VERSION 5.8 ;
BUSBITCHARS "[]" ;
DIVIDERCHAR "/" ;
UNITS
    DATABASE MICRONS 1000 ;
END UNITS

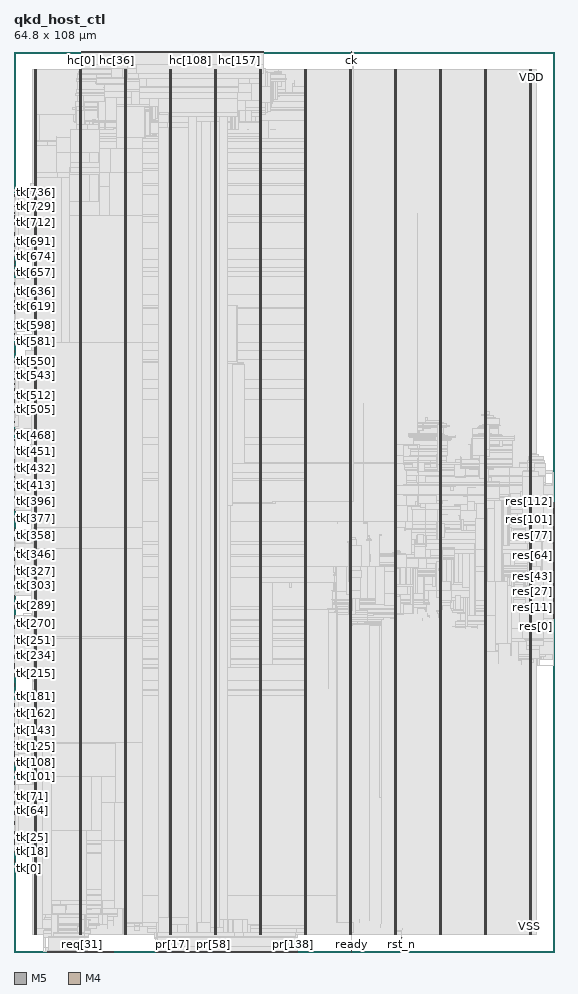
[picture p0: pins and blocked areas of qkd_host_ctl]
MACRO qkd_host_ctl
  FOREIGN qkd_host_ctl 0 0 ;
  CLASS BLOCK ;
  SIZE 64.8 BY 108 ;
  PIN ck
    DIRECTION INPUT ;
    USE SIGNAL ;
    PORT
      LAYER M5 ;
        RECT  40.512 107.916 40.536 108 ;
    END
    PORT
      LAYER M5 ;
        RECT  40.512 107.891 40.536 107.984 ;
    END
  END ck
  PIN hc[0]
    DIRECTION OUTPUT ;
    USE SIGNAL ;
    PORT
      LAYER M5 ;
        RECT  8.064 107.916 8.088 108 ;
    END
  END hc[0]
  PIN hc[100]
    DIRECTION OUTPUT ;
    USE SIGNAL ;
    PORT
      LAYER M5 ;
        RECT  20.16 107.916 20.184 108 ;
    END
  END hc[100]
  PIN hc[101]
    DIRECTION OUTPUT ;
    USE SIGNAL ;
    PORT
      LAYER M5 ;
        RECT  20.256 107.916 20.28 108 ;
    END
  END hc[101]
  PIN hc[102]
    DIRECTION OUTPUT ;
    USE SIGNAL ;
    PORT
      LAYER M5 ;
        RECT  20.4 107.916 20.424 108 ;
    END
  END hc[102]
  PIN hc[103]
    DIRECTION OUTPUT ;
    USE SIGNAL ;
    PORT
      LAYER M5 ;
        RECT  20.496 107.916 20.52 108 ;
    END
  END hc[103]
  PIN hc[104]
    DIRECTION OUTPUT ;
    USE SIGNAL ;
    PORT
      LAYER M5 ;
        RECT  20.64 107.916 20.664 108 ;
    END
  END hc[104]
  PIN hc[105]
    DIRECTION OUTPUT ;
    USE SIGNAL ;
    PORT
      LAYER M5 ;
        RECT  20.736 107.916 20.76 108 ;
    END
  END hc[105]
  PIN hc[106]
    DIRECTION OUTPUT ;
    USE SIGNAL ;
    PORT
      LAYER M5 ;
        RECT  20.88 107.916 20.904 108 ;
    END
  END hc[106]
  PIN hc[107]
    DIRECTION OUTPUT ;
    USE SIGNAL ;
    PORT
      LAYER M5 ;
        RECT  20.976 107.916 21 108 ;
    END
  END hc[107]
  PIN hc[108]
    DIRECTION OUTPUT ;
    USE SIGNAL ;
    PORT
      LAYER M5 ;
        RECT  21.12 107.916 21.144 108 ;
    END
  END hc[108]
  PIN hc[109]
    DIRECTION OUTPUT ;
    USE SIGNAL ;
    PORT
      LAYER M5 ;
        RECT  21.216 107.916 21.24 108 ;
    END
  END hc[109]
  PIN hc[10]
    DIRECTION OUTPUT ;
    USE SIGNAL ;
    PORT
      LAYER M5 ;
        RECT  9.264 107.916 9.288 108 ;
    END
  END hc[10]
  PIN hc[110]
    DIRECTION OUTPUT ;
    USE SIGNAL ;
    PORT
      LAYER M5 ;
        RECT  21.36 107.916 21.384 108 ;
    END
  END hc[110]
  PIN hc[111]
    DIRECTION OUTPUT ;
    USE SIGNAL ;
    PORT
      LAYER M5 ;
        RECT  21.456 107.916 21.48 108 ;
    END
  END hc[111]
  PIN hc[112]
    DIRECTION OUTPUT ;
    USE SIGNAL ;
    PORT
      LAYER M5 ;
        RECT  21.6 107.916 21.624 108 ;
    END
  END hc[112]
  PIN hc[113]
    DIRECTION OUTPUT ;
    USE SIGNAL ;
    PORT
      LAYER M5 ;
        RECT  21.696 107.916 21.72 108 ;
    END
  END hc[113]
  PIN hc[114]
    DIRECTION OUTPUT ;
    USE SIGNAL ;
    PORT
      LAYER M5 ;
        RECT  21.84 107.916 21.864 108 ;
    END
  END hc[114]
  PIN hc[115]
    DIRECTION OUTPUT ;
    USE SIGNAL ;
    PORT
      LAYER M5 ;
        RECT  21.936 107.916 21.96 108 ;
    END
  END hc[115]
  PIN hc[116]
    DIRECTION OUTPUT ;
    USE SIGNAL ;
    PORT
      LAYER M5 ;
        RECT  22.08 107.916 22.104 108 ;
    END
  END hc[116]
  PIN hc[117]
    DIRECTION OUTPUT ;
    USE SIGNAL ;
    PORT
      LAYER M5 ;
        RECT  22.176 107.916 22.2 108 ;
    END
  END hc[117]
  PIN hc[118]
    DIRECTION OUTPUT ;
    USE SIGNAL ;
    PORT
      LAYER M5 ;
        RECT  22.32 107.916 22.344 108 ;
    END
  END hc[118]
  PIN hc[119]
    DIRECTION OUTPUT ;
    USE SIGNAL ;
    PORT
      LAYER M5 ;
        RECT  22.416 107.916 22.44 108 ;
    END
  END hc[119]
  PIN hc[11]
    DIRECTION OUTPUT ;
    USE SIGNAL ;
    PORT
      LAYER M5 ;
        RECT  9.36 107.916 9.384 108 ;
    END
  END hc[11]
  PIN hc[120]
    DIRECTION OUTPUT ;
    USE SIGNAL ;
    PORT
      LAYER M5 ;
        RECT  22.56 107.916 22.584 108 ;
    END
  END hc[120]
  PIN hc[121]
    DIRECTION OUTPUT ;
    USE SIGNAL ;
    PORT
      LAYER M5 ;
        RECT  22.656 107.916 22.68 108 ;
    END
  END hc[121]
  PIN hc[122]
    DIRECTION OUTPUT ;
    USE SIGNAL ;
    PORT
      LAYER M5 ;
        RECT  22.8 107.916 22.824 108 ;
    END
  END hc[122]
  PIN hc[123]
    DIRECTION OUTPUT ;
    USE SIGNAL ;
    PORT
      LAYER M5 ;
        RECT  22.896 107.916 22.92 108 ;
    END
  END hc[123]
  PIN hc[124]
    DIRECTION OUTPUT ;
    USE SIGNAL ;
    PORT
      LAYER M5 ;
        RECT  23.04 107.916 23.064 108 ;
    END
  END hc[124]
  PIN hc[125]
    DIRECTION OUTPUT ;
    USE SIGNAL ;
    PORT
      LAYER M5 ;
        RECT  23.136 107.916 23.16 108 ;
    END
  END hc[125]
  PIN hc[126]
    DIRECTION OUTPUT ;
    USE SIGNAL ;
    PORT
      LAYER M5 ;
        RECT  23.28 107.916 23.304 108 ;
    END
  END hc[126]
  PIN hc[127]
    DIRECTION OUTPUT ;
    USE SIGNAL ;
    PORT
      LAYER M5 ;
        RECT  23.424 107.916 23.448 108 ;
    END
  END hc[127]
  PIN hc[128]
    DIRECTION OUTPUT ;
    USE SIGNAL ;
    PORT
      LAYER M5 ;
        RECT  23.52 107.916 23.544 108 ;
    END
  END hc[128]
  PIN hc[129]
    DIRECTION OUTPUT ;
    USE SIGNAL ;
    PORT
      LAYER M5 ;
        RECT  23.664 107.916 23.688 108 ;
    END
  END hc[129]
  PIN hc[12]
    DIRECTION OUTPUT ;
    USE SIGNAL ;
    PORT
      LAYER M5 ;
        RECT  9.504 107.916 9.528 108 ;
    END
  END hc[12]
  PIN hc[130]
    DIRECTION OUTPUT ;
    USE SIGNAL ;
    PORT
      LAYER M5 ;
        RECT  23.76 107.916 23.784 108 ;
    END
  END hc[130]
  PIN hc[131]
    DIRECTION OUTPUT ;
    USE SIGNAL ;
    PORT
      LAYER M5 ;
        RECT  23.904 107.916 23.928 108 ;
    END
  END hc[131]
  PIN hc[132]
    DIRECTION OUTPUT ;
    USE SIGNAL ;
    PORT
      LAYER M5 ;
        RECT  24 107.916 24.024 108 ;
    END
  END hc[132]
  PIN hc[133]
    DIRECTION OUTPUT ;
    USE SIGNAL ;
    PORT
      LAYER M5 ;
        RECT  24.144 107.916 24.168 108 ;
    END
  END hc[133]
  PIN hc[134]
    DIRECTION OUTPUT ;
    USE SIGNAL ;
    PORT
      LAYER M5 ;
        RECT  24.24 107.916 24.264 108 ;
    END
  END hc[134]
  PIN hc[135]
    DIRECTION OUTPUT ;
    USE SIGNAL ;
    PORT
      LAYER M5 ;
        RECT  24.384 107.916 24.408 108 ;
    END
  END hc[135]
  PIN hc[136]
    DIRECTION OUTPUT ;
    USE SIGNAL ;
    PORT
      LAYER M5 ;
        RECT  24.48 107.916 24.504 108 ;
    END
  END hc[136]
  PIN hc[137]
    DIRECTION OUTPUT ;
    USE SIGNAL ;
    PORT
      LAYER M5 ;
        RECT  24.624 107.916 24.648 108 ;
    END
  END hc[137]
  PIN hc[138]
    DIRECTION OUTPUT ;
    USE SIGNAL ;
    PORT
      LAYER M5 ;
        RECT  24.72 107.916 24.744 108 ;
    END
  END hc[138]
  PIN hc[139]
    DIRECTION OUTPUT ;
    USE SIGNAL ;
    PORT
      LAYER M5 ;
        RECT  24.864 107.916 24.888 108 ;
    END
  END hc[139]
  PIN hc[13]
    DIRECTION OUTPUT ;
    USE SIGNAL ;
    PORT
      LAYER M5 ;
        RECT  9.6 107.916 9.624 108 ;
    END
  END hc[13]
  PIN hc[140]
    DIRECTION OUTPUT ;
    USE SIGNAL ;
    PORT
      LAYER M5 ;
        RECT  24.96 107.916 24.984 108 ;
    END
  END hc[140]
  PIN hc[141]
    DIRECTION OUTPUT ;
    USE SIGNAL ;
    PORT
      LAYER M5 ;
        RECT  25.104 107.916 25.128 108 ;
    END
  END hc[141]
  PIN hc[142]
    DIRECTION OUTPUT ;
    USE SIGNAL ;
    PORT
      LAYER M5 ;
        RECT  25.2 107.916 25.224 108 ;
    END
  END hc[142]
  PIN hc[143]
    DIRECTION OUTPUT ;
    USE SIGNAL ;
    PORT
      LAYER M5 ;
        RECT  25.344 107.916 25.368 108 ;
    END
  END hc[143]
  PIN hc[144]
    DIRECTION OUTPUT ;
    USE SIGNAL ;
    PORT
      LAYER M5 ;
        RECT  25.44 107.916 25.464 108 ;
    END
  END hc[144]
  PIN hc[145]
    DIRECTION OUTPUT ;
    USE SIGNAL ;
    PORT
      LAYER M5 ;
        RECT  25.584 107.916 25.608 108 ;
    END
  END hc[145]
  PIN hc[146]
    DIRECTION OUTPUT ;
    USE SIGNAL ;
    PORT
      LAYER M5 ;
        RECT  25.68 107.916 25.704 108 ;
    END
  END hc[146]
  PIN hc[147]
    DIRECTION OUTPUT ;
    USE SIGNAL ;
    PORT
      LAYER M5 ;
        RECT  25.824 107.916 25.848 108 ;
    END
  END hc[147]
  PIN hc[148]
    DIRECTION OUTPUT ;
    USE SIGNAL ;
    PORT
      LAYER M5 ;
        RECT  25.92 107.916 25.944 108 ;
    END
  END hc[148]
  PIN hc[149]
    DIRECTION OUTPUT ;
    USE SIGNAL ;
    PORT
      LAYER M5 ;
        RECT  26.064 107.916 26.088 108 ;
    END
  END hc[149]
  PIN hc[14]
    DIRECTION OUTPUT ;
    USE SIGNAL ;
    PORT
      LAYER M5 ;
        RECT  9.744 107.916 9.768 108 ;
    END
  END hc[14]
  PIN hc[150]
    DIRECTION OUTPUT ;
    USE SIGNAL ;
    PORT
      LAYER M5 ;
        RECT  26.16 107.916 26.184 108 ;
    END
  END hc[150]
  PIN hc[151]
    DIRECTION OUTPUT ;
    USE SIGNAL ;
    PORT
      LAYER M5 ;
        RECT  26.304 107.916 26.328 108 ;
    END
  END hc[151]
  PIN hc[152]
    DIRECTION OUTPUT ;
    USE SIGNAL ;
    PORT
      LAYER M5 ;
        RECT  26.4 107.916 26.424 108 ;
    END
  END hc[152]
  PIN hc[153]
    DIRECTION OUTPUT ;
    USE SIGNAL ;
    PORT
      LAYER M5 ;
        RECT  26.544 107.916 26.568 108 ;
    END
  END hc[153]
  PIN hc[154]
    DIRECTION OUTPUT ;
    USE SIGNAL ;
    PORT
      LAYER M5 ;
        RECT  26.688 107.916 26.712 108 ;
    END
  END hc[154]
  PIN hc[155]
    DIRECTION OUTPUT ;
    USE SIGNAL ;
    PORT
      LAYER M5 ;
        RECT  26.784 107.916 26.808 108 ;
    END
  END hc[155]
  PIN hc[156]
    DIRECTION OUTPUT ;
    USE SIGNAL ;
    PORT
      LAYER M5 ;
        RECT  26.928 107.916 26.952 108 ;
    END
  END hc[156]
  PIN hc[157]
    DIRECTION OUTPUT ;
    USE SIGNAL ;
    PORT
      LAYER M5 ;
        RECT  27.024 107.916 27.048 108 ;
    END
  END hc[157]
  PIN hc[158]
    DIRECTION OUTPUT ;
    USE SIGNAL ;
    PORT
      LAYER M5 ;
        RECT  27.168 107.916 27.192 108 ;
    END
  END hc[158]
  PIN hc[159]
    DIRECTION OUTPUT ;
    USE SIGNAL ;
    PORT
      LAYER M5 ;
        RECT  27.264 107.916 27.288 108 ;
    END
  END hc[159]
  PIN hc[15]
    DIRECTION OUTPUT ;
    USE SIGNAL ;
    PORT
      LAYER M5 ;
        RECT  9.84 107.916 9.864 108 ;
    END
  END hc[15]
  PIN hc[160]
    DIRECTION OUTPUT ;
    USE SIGNAL ;
    PORT
      LAYER M5 ;
        RECT  27.408 107.916 27.432 108 ;
    END
  END hc[160]
  PIN hc[161]
    DIRECTION OUTPUT ;
    USE SIGNAL ;
    PORT
      LAYER M5 ;
        RECT  27.504 107.916 27.528 108 ;
    END
  END hc[161]
  PIN hc[162]
    DIRECTION OUTPUT ;
    USE SIGNAL ;
    PORT
      LAYER M5 ;
        RECT  27.648 107.916 27.672 108 ;
    END
  END hc[162]
  PIN hc[163]
    DIRECTION OUTPUT ;
    USE SIGNAL ;
    PORT
      LAYER M5 ;
        RECT  27.744 107.916 27.768 108 ;
    END
  END hc[163]
  PIN hc[164]
    DIRECTION OUTPUT ;
    USE SIGNAL ;
    PORT
      LAYER M5 ;
        RECT  27.888 107.916 27.912 108 ;
    END
  END hc[164]
  PIN hc[165]
    DIRECTION OUTPUT ;
    USE SIGNAL ;
    PORT
      LAYER M5 ;
        RECT  27.984 107.916 28.008 108 ;
    END
  END hc[165]
  PIN hc[166]
    DIRECTION OUTPUT ;
    USE SIGNAL ;
    PORT
      LAYER M5 ;
        RECT  28.128 107.916 28.152 108 ;
    END
  END hc[166]
  PIN hc[167]
    DIRECTION OUTPUT ;
    USE SIGNAL ;
    PORT
      LAYER M5 ;
        RECT  28.224 107.916 28.248 108 ;
    END
  END hc[167]
  PIN hc[168]
    DIRECTION OUTPUT ;
    USE SIGNAL ;
    PORT
      LAYER M5 ;
        RECT  28.368 107.916 28.392 108 ;
    END
  END hc[168]
  PIN hc[169]
    DIRECTION OUTPUT ;
    USE SIGNAL ;
    PORT
      LAYER M5 ;
        RECT  28.464 107.916 28.488 108 ;
    END
  END hc[169]
  PIN hc[16]
    DIRECTION OUTPUT ;
    USE SIGNAL ;
    PORT
      LAYER M5 ;
        RECT  9.984 107.916 10.008 108 ;
    END
  END hc[16]
  PIN hc[170]
    DIRECTION OUTPUT ;
    USE SIGNAL ;
    PORT
      LAYER M5 ;
        RECT  28.608 107.916 28.632 108 ;
    END
  END hc[170]
  PIN hc[171]
    DIRECTION OUTPUT ;
    USE SIGNAL ;
    PORT
      LAYER M5 ;
        RECT  28.704 107.916 28.728 108 ;
    END
  END hc[171]
  PIN hc[172]
    DIRECTION OUTPUT ;
    USE SIGNAL ;
    PORT
      LAYER M5 ;
        RECT  28.848 107.916 28.872 108 ;
    END
  END hc[172]
  PIN hc[173]
    DIRECTION OUTPUT ;
    USE SIGNAL ;
    PORT
      LAYER M5 ;
        RECT  28.944 107.916 28.968 108 ;
    END
  END hc[173]
  PIN hc[174]
    DIRECTION OUTPUT ;
    USE SIGNAL ;
    PORT
      LAYER M5 ;
        RECT  29.088 107.916 29.112 108 ;
    END
  END hc[174]
  PIN hc[175]
    DIRECTION OUTPUT ;
    USE SIGNAL ;
    PORT
      LAYER M5 ;
        RECT  29.184 107.916 29.208 108 ;
    END
  END hc[175]
  PIN hc[176]
    DIRECTION OUTPUT ;
    USE SIGNAL ;
    PORT
      LAYER M5 ;
        RECT  29.328 107.916 29.352 108 ;
    END
  END hc[176]
  PIN hc[177]
    DIRECTION OUTPUT ;
    USE SIGNAL ;
    PORT
      LAYER M5 ;
        RECT  29.424 107.916 29.448 108 ;
    END
  END hc[177]
  PIN hc[178]
    DIRECTION OUTPUT ;
    USE SIGNAL ;
    PORT
      LAYER M5 ;
        RECT  29.568 107.916 29.592 108 ;
    END
  END hc[178]
  PIN hc[179]
    DIRECTION OUTPUT ;
    USE SIGNAL ;
    PORT
      LAYER M5 ;
        RECT  29.664 107.916 29.688 108 ;
    END
  END hc[179]
  PIN hc[17]
    DIRECTION OUTPUT ;
    USE SIGNAL ;
    PORT
      LAYER M5 ;
        RECT  10.08 107.916 10.104 108 ;
    END
  END hc[17]
  PIN hc[180]
    DIRECTION OUTPUT ;
    USE SIGNAL ;
    PORT
      LAYER M5 ;
        RECT  29.808 107.916 29.832 108 ;
    END
  END hc[180]
  PIN hc[181]
    DIRECTION OUTPUT ;
    USE SIGNAL ;
    PORT
      LAYER M5 ;
        RECT  29.952 107.916 29.976 108 ;
    END
  END hc[181]
  PIN hc[18]
    DIRECTION OUTPUT ;
    USE SIGNAL ;
    PORT
      LAYER M5 ;
        RECT  10.224 107.916 10.248 108 ;
    END
  END hc[18]
  PIN hc[19]
    DIRECTION OUTPUT ;
    USE SIGNAL ;
    PORT
      LAYER M5 ;
        RECT  10.368 107.916 10.392 108 ;
    END
  END hc[19]
  PIN hc[1]
    DIRECTION OUTPUT ;
    USE SIGNAL ;
    PORT
      LAYER M5 ;
        RECT  8.16 107.916 8.184 108 ;
    END
  END hc[1]
  PIN hc[20]
    DIRECTION OUTPUT ;
    USE SIGNAL ;
    PORT
      LAYER M5 ;
        RECT  10.464 107.916 10.488 108 ;
    END
  END hc[20]
  PIN hc[21]
    DIRECTION OUTPUT ;
    USE SIGNAL ;
    PORT
      LAYER M5 ;
        RECT  10.608 107.916 10.632 108 ;
    END
  END hc[21]
  PIN hc[22]
    DIRECTION OUTPUT ;
    USE SIGNAL ;
    PORT
      LAYER M5 ;
        RECT  10.704 107.916 10.728 108 ;
    END
  END hc[22]
  PIN hc[23]
    DIRECTION OUTPUT ;
    USE SIGNAL ;
    PORT
      LAYER M5 ;
        RECT  10.848 107.916 10.872 108 ;
    END
  END hc[23]
  PIN hc[24]
    DIRECTION OUTPUT ;
    USE SIGNAL ;
    PORT
      LAYER M5 ;
        RECT  10.944 107.916 10.968 108 ;
    END
  END hc[24]
  PIN hc[25]
    DIRECTION OUTPUT ;
    USE SIGNAL ;
    PORT
      LAYER M5 ;
        RECT  11.088 107.916 11.112 108 ;
    END
  END hc[25]
  PIN hc[26]
    DIRECTION OUTPUT ;
    USE SIGNAL ;
    PORT
      LAYER M5 ;
        RECT  11.184 107.916 11.208 108 ;
    END
  END hc[26]
  PIN hc[27]
    DIRECTION OUTPUT ;
    USE SIGNAL ;
    PORT
      LAYER M5 ;
        RECT  11.328 107.916 11.352 108 ;
    END
  END hc[27]
  PIN hc[28]
    DIRECTION OUTPUT ;
    USE SIGNAL ;
    PORT
      LAYER M5 ;
        RECT  11.424 107.916 11.448 108 ;
    END
  END hc[28]
  PIN hc[29]
    DIRECTION OUTPUT ;
    USE SIGNAL ;
    PORT
      LAYER M5 ;
        RECT  11.568 107.916 11.592 108 ;
    END
  END hc[29]
  PIN hc[2]
    DIRECTION OUTPUT ;
    USE SIGNAL ;
    PORT
      LAYER M5 ;
        RECT  8.304 107.916 8.328 108 ;
    END
  END hc[2]
  PIN hc[30]
    DIRECTION OUTPUT ;
    USE SIGNAL ;
    PORT
      LAYER M5 ;
        RECT  11.664 107.916 11.688 108 ;
    END
  END hc[30]
  PIN hc[31]
    DIRECTION OUTPUT ;
    USE SIGNAL ;
    PORT
      LAYER M5 ;
        RECT  11.808 107.916 11.832 108 ;
    END
  END hc[31]
  PIN hc[32]
    DIRECTION OUTPUT ;
    USE SIGNAL ;
    PORT
      LAYER M5 ;
        RECT  11.904 107.916 11.928 108 ;
    END
  END hc[32]
  PIN hc[33]
    DIRECTION OUTPUT ;
    USE SIGNAL ;
    PORT
      LAYER M5 ;
        RECT  12.048 107.916 12.072 108 ;
    END
  END hc[33]
  PIN hc[34]
    DIRECTION OUTPUT ;
    USE SIGNAL ;
    PORT
      LAYER M5 ;
        RECT  12.144 107.916 12.168 108 ;
    END
  END hc[34]
  PIN hc[35]
    DIRECTION OUTPUT ;
    USE SIGNAL ;
    PORT
      LAYER M5 ;
        RECT  12.288 107.916 12.312 108 ;
    END
  END hc[35]
  PIN hc[36]
    DIRECTION OUTPUT ;
    USE SIGNAL ;
    PORT
      LAYER M5 ;
        RECT  12.384 107.916 12.408 108 ;
    END
  END hc[36]
  PIN hc[37]
    DIRECTION OUTPUT ;
    USE SIGNAL ;
    PORT
      LAYER M5 ;
        RECT  12.528 107.916 12.552 108 ;
    END
  END hc[37]
  PIN hc[38]
    DIRECTION OUTPUT ;
    USE SIGNAL ;
    PORT
      LAYER M5 ;
        RECT  12.624 107.916 12.648 108 ;
    END
  END hc[38]
  PIN hc[39]
    DIRECTION OUTPUT ;
    USE SIGNAL ;
    PORT
      LAYER M5 ;
        RECT  12.768 107.916 12.792 108 ;
    END
  END hc[39]
  PIN hc[3]
    DIRECTION OUTPUT ;
    USE SIGNAL ;
    PORT
      LAYER M5 ;
        RECT  8.4 107.916 8.424 108 ;
    END
  END hc[3]
  PIN hc[40]
    DIRECTION OUTPUT ;
    USE SIGNAL ;
    PORT
      LAYER M5 ;
        RECT  12.864 107.916 12.888 108 ;
    END
  END hc[40]
  PIN hc[41]
    DIRECTION OUTPUT ;
    USE SIGNAL ;
    PORT
      LAYER M5 ;
        RECT  13.008 107.916 13.032 108 ;
    END
  END hc[41]
  PIN hc[42]
    DIRECTION OUTPUT ;
    USE SIGNAL ;
    PORT
      LAYER M5 ;
        RECT  13.104 107.916 13.128 108 ;
    END
  END hc[42]
  PIN hc[43]
    DIRECTION OUTPUT ;
    USE SIGNAL ;
    PORT
      LAYER M5 ;
        RECT  13.248 107.916 13.272 108 ;
    END
  END hc[43]
  PIN hc[44]
    DIRECTION OUTPUT ;
    USE SIGNAL ;
    PORT
      LAYER M5 ;
        RECT  13.344 107.916 13.368 108 ;
    END
  END hc[44]
  PIN hc[45]
    DIRECTION OUTPUT ;
    USE SIGNAL ;
    PORT
      LAYER M5 ;
        RECT  13.488 107.916 13.512 108 ;
    END
  END hc[45]
  PIN hc[46]
    DIRECTION OUTPUT ;
    USE SIGNAL ;
    PORT
      LAYER M5 ;
        RECT  13.632 107.916 13.656 108 ;
    END
  END hc[46]
  PIN hc[47]
    DIRECTION OUTPUT ;
    USE SIGNAL ;
    PORT
      LAYER M5 ;
        RECT  13.728 107.916 13.752 108 ;
    END
  END hc[47]
  PIN hc[48]
    DIRECTION OUTPUT ;
    USE SIGNAL ;
    PORT
      LAYER M5 ;
        RECT  13.872 107.916 13.896 108 ;
    END
  END hc[48]
  PIN hc[49]
    DIRECTION OUTPUT ;
    USE SIGNAL ;
    PORT
      LAYER M5 ;
        RECT  13.968 107.916 13.992 108 ;
    END
  END hc[49]
  PIN hc[4]
    DIRECTION OUTPUT ;
    USE SIGNAL ;
    PORT
      LAYER M5 ;
        RECT  8.544 107.916 8.568 108 ;
    END
  END hc[4]
  PIN hc[50]
    DIRECTION OUTPUT ;
    USE SIGNAL ;
    PORT
      LAYER M5 ;
        RECT  14.112 107.916 14.136 108 ;
    END
  END hc[50]
  PIN hc[51]
    DIRECTION OUTPUT ;
    USE SIGNAL ;
    PORT
      LAYER M5 ;
        RECT  14.208 107.916 14.232 108 ;
    END
  END hc[51]
  PIN hc[52]
    DIRECTION OUTPUT ;
    USE SIGNAL ;
    PORT
      LAYER M5 ;
        RECT  14.352 107.916 14.376 108 ;
    END
  END hc[52]
  PIN hc[53]
    DIRECTION OUTPUT ;
    USE SIGNAL ;
    PORT
      LAYER M5 ;
        RECT  14.448 107.916 14.472 108 ;
    END
  END hc[53]
  PIN hc[54]
    DIRECTION OUTPUT ;
    USE SIGNAL ;
    PORT
      LAYER M5 ;
        RECT  14.592 107.916 14.616 108 ;
    END
  END hc[54]
  PIN hc[55]
    DIRECTION OUTPUT ;
    USE SIGNAL ;
    PORT
      LAYER M5 ;
        RECT  14.688 107.916 14.712 108 ;
    END
  END hc[55]
  PIN hc[56]
    DIRECTION OUTPUT ;
    USE SIGNAL ;
    PORT
      LAYER M5 ;
        RECT  14.832 107.916 14.856 108 ;
    END
  END hc[56]
  PIN hc[57]
    DIRECTION OUTPUT ;
    USE SIGNAL ;
    PORT
      LAYER M5 ;
        RECT  14.928 107.916 14.952 108 ;
    END
  END hc[57]
  PIN hc[58]
    DIRECTION OUTPUT ;
    USE SIGNAL ;
    PORT
      LAYER M5 ;
        RECT  15.072 107.916 15.096 108 ;
    END
  END hc[58]
  PIN hc[59]
    DIRECTION OUTPUT ;
    USE SIGNAL ;
    PORT
      LAYER M5 ;
        RECT  15.168 107.916 15.192 108 ;
    END
  END hc[59]
  PIN hc[5]
    DIRECTION OUTPUT ;
    USE SIGNAL ;
    PORT
      LAYER M5 ;
        RECT  8.64 107.916 8.664 108 ;
    END
  END hc[5]
  PIN hc[60]
    DIRECTION OUTPUT ;
    USE SIGNAL ;
    PORT
      LAYER M5 ;
        RECT  15.312 107.916 15.336 108 ;
    END
  END hc[60]
  PIN hc[61]
    DIRECTION OUTPUT ;
    USE SIGNAL ;
    PORT
      LAYER M5 ;
        RECT  15.408 107.916 15.432 108 ;
    END
  END hc[61]
  PIN hc[62]
    DIRECTION OUTPUT ;
    USE SIGNAL ;
    PORT
      LAYER M5 ;
        RECT  15.552 107.916 15.576 108 ;
    END
  END hc[62]
  PIN hc[63]
    DIRECTION OUTPUT ;
    USE SIGNAL ;
    PORT
      LAYER M5 ;
        RECT  15.648 107.916 15.672 108 ;
    END
  END hc[63]
  PIN hc[64]
    DIRECTION OUTPUT ;
    USE SIGNAL ;
    PORT
      LAYER M5 ;
        RECT  15.792 107.916 15.816 108 ;
    END
  END hc[64]
  PIN hc[65]
    DIRECTION OUTPUT ;
    USE SIGNAL ;
    PORT
      LAYER M5 ;
        RECT  15.888 107.916 15.912 108 ;
    END
  END hc[65]
  PIN hc[66]
    DIRECTION OUTPUT ;
    USE SIGNAL ;
    PORT
      LAYER M5 ;
        RECT  16.032 107.916 16.056 108 ;
    END
  END hc[66]
  PIN hc[67]
    DIRECTION OUTPUT ;
    USE SIGNAL ;
    PORT
      LAYER M5 ;
        RECT  16.128 107.916 16.152 108 ;
    END
  END hc[67]
  PIN hc[68]
    DIRECTION OUTPUT ;
    USE SIGNAL ;
    PORT
      LAYER M5 ;
        RECT  16.272 107.916 16.296 108 ;
    END
  END hc[68]
  PIN hc[69]
    DIRECTION OUTPUT ;
    USE SIGNAL ;
    PORT
      LAYER M5 ;
        RECT  16.368 107.916 16.392 108 ;
    END
  END hc[69]
  PIN hc[6]
    DIRECTION OUTPUT ;
    USE SIGNAL ;
    PORT
      LAYER M5 ;
        RECT  8.784 107.916 8.808 108 ;
    END
  END hc[6]
  PIN hc[70]
    DIRECTION OUTPUT ;
    USE SIGNAL ;
    PORT
      LAYER M5 ;
        RECT  16.512 107.916 16.536 108 ;
    END
  END hc[70]
  PIN hc[71]
    DIRECTION OUTPUT ;
    USE SIGNAL ;
    PORT
      LAYER M5 ;
        RECT  16.608 107.916 16.632 108 ;
    END
  END hc[71]
  PIN hc[72]
    DIRECTION OUTPUT ;
    USE SIGNAL ;
    PORT
      LAYER M5 ;
        RECT  16.752 107.916 16.776 108 ;
    END
  END hc[72]
  PIN hc[73]
    DIRECTION OUTPUT ;
    USE SIGNAL ;
    PORT
      LAYER M5 ;
        RECT  16.896 107.916 16.92 108 ;
    END
  END hc[73]
  PIN hc[74]
    DIRECTION OUTPUT ;
    USE SIGNAL ;
    PORT
      LAYER M5 ;
        RECT  16.992 107.916 17.016 108 ;
    END
  END hc[74]
  PIN hc[75]
    DIRECTION OUTPUT ;
    USE SIGNAL ;
    PORT
      LAYER M5 ;
        RECT  17.136 107.916 17.16 108 ;
    END
  END hc[75]
  PIN hc[76]
    DIRECTION OUTPUT ;
    USE SIGNAL ;
    PORT
      LAYER M5 ;
        RECT  17.232 107.916 17.256 108 ;
    END
  END hc[76]
  PIN hc[77]
    DIRECTION OUTPUT ;
    USE SIGNAL ;
    PORT
      LAYER M5 ;
        RECT  17.376 107.916 17.4 108 ;
    END
  END hc[77]
  PIN hc[78]
    DIRECTION OUTPUT ;
    USE SIGNAL ;
    PORT
      LAYER M5 ;
        RECT  17.472 107.916 17.496 108 ;
    END
  END hc[78]
  PIN hc[79]
    DIRECTION OUTPUT ;
    USE SIGNAL ;
    PORT
      LAYER M5 ;
        RECT  17.616 107.916 17.64 108 ;
    END
  END hc[79]
  PIN hc[7]
    DIRECTION OUTPUT ;
    USE SIGNAL ;
    PORT
      LAYER M5 ;
        RECT  8.88 107.916 8.904 108 ;
    END
  END hc[7]
  PIN hc[80]
    DIRECTION OUTPUT ;
    USE SIGNAL ;
    PORT
      LAYER M5 ;
        RECT  17.712 107.916 17.736 108 ;
    END
  END hc[80]
  PIN hc[81]
    DIRECTION OUTPUT ;
    USE SIGNAL ;
    PORT
      LAYER M5 ;
        RECT  17.856 107.916 17.88 108 ;
    END
  END hc[81]
  PIN hc[82]
    DIRECTION OUTPUT ;
    USE SIGNAL ;
    PORT
      LAYER M5 ;
        RECT  17.952 107.916 17.976 108 ;
    END
  END hc[82]
  PIN hc[83]
    DIRECTION OUTPUT ;
    USE SIGNAL ;
    PORT
      LAYER M5 ;
        RECT  18.096 107.916 18.12 108 ;
    END
  END hc[83]
  PIN hc[84]
    DIRECTION OUTPUT ;
    USE SIGNAL ;
    PORT
      LAYER M5 ;
        RECT  18.192 107.916 18.216 108 ;
    END
  END hc[84]
  PIN hc[85]
    DIRECTION OUTPUT ;
    USE SIGNAL ;
    PORT
      LAYER M5 ;
        RECT  18.336 107.916 18.36 108 ;
    END
  END hc[85]
  PIN hc[86]
    DIRECTION OUTPUT ;
    USE SIGNAL ;
    PORT
      LAYER M5 ;
        RECT  18.432 107.916 18.456 108 ;
    END
  END hc[86]
  PIN hc[87]
    DIRECTION OUTPUT ;
    USE SIGNAL ;
    PORT
      LAYER M5 ;
        RECT  18.576 107.916 18.6 108 ;
    END
  END hc[87]
  PIN hc[88]
    DIRECTION OUTPUT ;
    USE SIGNAL ;
    PORT
      LAYER M5 ;
        RECT  18.672 107.916 18.696 108 ;
    END
  END hc[88]
  PIN hc[89]
    DIRECTION OUTPUT ;
    USE SIGNAL ;
    PORT
      LAYER M5 ;
        RECT  18.816 107.916 18.84 108 ;
    END
  END hc[89]
  PIN hc[8]
    DIRECTION OUTPUT ;
    USE SIGNAL ;
    PORT
      LAYER M5 ;
        RECT  9.024 107.916 9.048 108 ;
    END
  END hc[8]
  PIN hc[90]
    DIRECTION OUTPUT ;
    USE SIGNAL ;
    PORT
      LAYER M5 ;
        RECT  18.912 107.916 18.936 108 ;
    END
  END hc[90]
  PIN hc[91]
    DIRECTION OUTPUT ;
    USE SIGNAL ;
    PORT
      LAYER M5 ;
        RECT  19.056 107.916 19.08 108 ;
    END
  END hc[91]
  PIN hc[92]
    DIRECTION OUTPUT ;
    USE SIGNAL ;
    PORT
      LAYER M5 ;
        RECT  19.152 107.916 19.176 108 ;
    END
  END hc[92]
  PIN hc[93]
    DIRECTION OUTPUT ;
    USE SIGNAL ;
    PORT
      LAYER M5 ;
        RECT  19.296 107.916 19.32 108 ;
    END
  END hc[93]
  PIN hc[94]
    DIRECTION OUTPUT ;
    USE SIGNAL ;
    PORT
      LAYER M5 ;
        RECT  19.392 107.916 19.416 108 ;
    END
  END hc[94]
  PIN hc[95]
    DIRECTION OUTPUT ;
    USE SIGNAL ;
    PORT
      LAYER M5 ;
        RECT  19.536 107.916 19.56 108 ;
    END
  END hc[95]
  PIN hc[96]
    DIRECTION OUTPUT ;
    USE SIGNAL ;
    PORT
      LAYER M5 ;
        RECT  19.632 107.916 19.656 108 ;
    END
  END hc[96]
  PIN hc[97]
    DIRECTION OUTPUT ;
    USE SIGNAL ;
    PORT
      LAYER M5 ;
        RECT  19.776 107.916 19.8 108 ;
    END
  END hc[97]
  PIN hc[98]
    DIRECTION OUTPUT ;
    USE SIGNAL ;
    PORT
      LAYER M5 ;
        RECT  19.872 107.916 19.896 108 ;
    END
  END hc[98]
  PIN hc[99]
    DIRECTION OUTPUT ;
    USE SIGNAL ;
    PORT
      LAYER M5 ;
        RECT  20.016 107.916 20.04 108 ;
    END
  END hc[99]
  PIN hc[9]
    DIRECTION OUTPUT ;
    USE SIGNAL ;
    PORT
      LAYER M5 ;
        RECT  9.12 107.916 9.144 108 ;
    END
  END hc[9]
  PIN pr[0]
    DIRECTION INPUT ;
    USE SIGNAL ;
    PORT
      LAYER M5 ;
        RECT  17.04 0 17.064 0.084 ;
    END
  END pr[0]
  PIN pr[100]
    DIRECTION INPUT ;
    USE SIGNAL ;
    PORT
      LAYER M5 ;
        RECT  28.944 0 28.968 0.084 ;
    END
  END pr[100]
  PIN pr[101]
    DIRECTION INPUT ;
    USE SIGNAL ;
    PORT
      LAYER M5 ;
        RECT  29.04 0 29.064 0.084 ;
    END
  END pr[101]
  PIN pr[102]
    DIRECTION INPUT ;
    USE SIGNAL ;
    PORT
      LAYER M5 ;
        RECT  29.184 0 29.208 0.084 ;
    END
  END pr[102]
  PIN pr[103]
    DIRECTION INPUT ;
    USE SIGNAL ;
    PORT
      LAYER M5 ;
        RECT  29.28 0 29.304 0.084 ;
    END
  END pr[103]
  PIN pr[104]
    DIRECTION INPUT ;
    USE SIGNAL ;
    PORT
      LAYER M5 ;
        RECT  29.424 0 29.448 0.084 ;
    END
  END pr[104]
  PIN pr[105]
    DIRECTION INPUT ;
    USE SIGNAL ;
    PORT
      LAYER M5 ;
        RECT  29.52 0 29.544 0.084 ;
    END
  END pr[105]
  PIN pr[106]
    DIRECTION INPUT ;
    USE SIGNAL ;
    PORT
      LAYER M5 ;
        RECT  29.664 0 29.688 0.084 ;
    END
  END pr[106]
  PIN pr[107]
    DIRECTION INPUT ;
    USE SIGNAL ;
    PORT
      LAYER M5 ;
        RECT  29.76 0 29.784 0.084 ;
    END
  END pr[107]
  PIN pr[108]
    DIRECTION INPUT ;
    USE SIGNAL ;
    PORT
      LAYER M5 ;
        RECT  29.904 0 29.928 0.084 ;
    END
  END pr[108]
  PIN pr[109]
    DIRECTION INPUT ;
    USE SIGNAL ;
    PORT
      LAYER M5 ;
        RECT  30 0 30.024 0.084 ;
    END
  END pr[109]
  PIN pr[10]
    DIRECTION INPUT ;
    USE SIGNAL ;
    PORT
      LAYER M5 ;
        RECT  18.24 0 18.264 0.084 ;
    END
  END pr[10]
  PIN pr[110]
    DIRECTION INPUT ;
    USE SIGNAL ;
    PORT
      LAYER M5 ;
        RECT  30.144 0 30.168 0.084 ;
    END
  END pr[110]
  PIN pr[111]
    DIRECTION INPUT ;
    USE SIGNAL ;
    PORT
      LAYER M5 ;
        RECT  30.24 0 30.264 0.084 ;
    END
  END pr[111]
  PIN pr[112]
    DIRECTION INPUT ;
    USE SIGNAL ;
    PORT
      LAYER M5 ;
        RECT  30.384 0 30.408 0.084 ;
    END
  END pr[112]
  PIN pr[113]
    DIRECTION INPUT ;
    USE SIGNAL ;
    PORT
      LAYER M5 ;
        RECT  30.48 0 30.504 0.084 ;
    END
  END pr[113]
  PIN pr[114]
    DIRECTION INPUT ;
    USE SIGNAL ;
    PORT
      LAYER M5 ;
        RECT  30.624 0 30.648 0.084 ;
    END
  END pr[114]
  PIN pr[115]
    DIRECTION INPUT ;
    USE SIGNAL ;
    PORT
      LAYER M5 ;
        RECT  30.72 0 30.744 0.084 ;
    END
  END pr[115]
  PIN pr[116]
    DIRECTION INPUT ;
    USE SIGNAL ;
    PORT
      LAYER M5 ;
        RECT  30.816 0 30.84 0.084 ;
    END
  END pr[116]
  PIN pr[117]
    DIRECTION INPUT ;
    USE SIGNAL ;
    PORT
      LAYER M5 ;
        RECT  30.96 0 30.984 0.084 ;
    END
  END pr[117]
  PIN pr[118]
    DIRECTION INPUT ;
    USE SIGNAL ;
    PORT
      LAYER M5 ;
        RECT  31.056 0 31.08 0.084 ;
    END
  END pr[118]
  PIN pr[119]
    DIRECTION INPUT ;
    USE SIGNAL ;
    PORT
      LAYER M5 ;
        RECT  31.2 0 31.224 0.084 ;
    END
  END pr[119]
  PIN pr[11]
    DIRECTION INPUT ;
    USE SIGNAL ;
    PORT
      LAYER M5 ;
        RECT  18.336 0 18.36 0.084 ;
    END
  END pr[11]
  PIN pr[120]
    DIRECTION INPUT ;
    USE SIGNAL ;
    PORT
      LAYER M5 ;
        RECT  31.296 0 31.32 0.084 ;
    END
  END pr[120]
  PIN pr[121]
    DIRECTION INPUT ;
    USE SIGNAL ;
    PORT
      LAYER M5 ;
        RECT  31.44 0 31.464 0.084 ;
    END
  END pr[121]
  PIN pr[122]
    DIRECTION INPUT ;
    USE SIGNAL ;
    PORT
      LAYER M5 ;
        RECT  31.536 0 31.56 0.084 ;
    END
  END pr[122]
  PIN pr[123]
    DIRECTION INPUT ;
    USE SIGNAL ;
    PORT
      LAYER M5 ;
        RECT  31.68 0 31.704 0.084 ;
    END
  END pr[123]
  PIN pr[124]
    DIRECTION INPUT ;
    USE SIGNAL ;
    PORT
      LAYER M5 ;
        RECT  31.776 0 31.8 0.084 ;
    END
  END pr[124]
  PIN pr[125]
    DIRECTION INPUT ;
    USE SIGNAL ;
    PORT
      LAYER M5 ;
        RECT  31.92 0 31.944 0.084 ;
    END
  END pr[125]
  PIN pr[126]
    DIRECTION INPUT ;
    USE SIGNAL ;
    PORT
      LAYER M5 ;
        RECT  32.016 0 32.04 0.084 ;
    END
  END pr[126]
  PIN pr[127]
    DIRECTION INPUT ;
    USE SIGNAL ;
    PORT
      LAYER M5 ;
        RECT  32.16 0 32.184 0.084 ;
    END
  END pr[127]
  PIN pr[128]
    DIRECTION INPUT ;
    USE SIGNAL ;
    PORT
      LAYER M5 ;
        RECT  32.256 0 32.28 0.084 ;
    END
  END pr[128]
  PIN pr[129]
    DIRECTION INPUT ;
    USE SIGNAL ;
    PORT
      LAYER M5 ;
        RECT  32.4 0 32.424 0.084 ;
    END
  END pr[129]
  PIN pr[12]
    DIRECTION INPUT ;
    USE SIGNAL ;
    PORT
      LAYER M5 ;
        RECT  18.48 0 18.504 0.084 ;
    END
  END pr[12]
  PIN pr[130]
    DIRECTION INPUT ;
    USE SIGNAL ;
    PORT
      LAYER M5 ;
        RECT  32.496 0 32.52 0.084 ;
    END
  END pr[130]
  PIN pr[131]
    DIRECTION INPUT ;
    USE SIGNAL ;
    PORT
      LAYER M5 ;
        RECT  32.64 0 32.664 0.084 ;
    END
  END pr[131]
  PIN pr[132]
    DIRECTION INPUT ;
    USE SIGNAL ;
    PORT
      LAYER M5 ;
        RECT  32.736 0 32.76 0.084 ;
    END
  END pr[132]
  PIN pr[133]
    DIRECTION INPUT ;
    USE SIGNAL ;
    PORT
      LAYER M5 ;
        RECT  32.88 0 32.904 0.084 ;
    END
  END pr[133]
  PIN pr[134]
    DIRECTION INPUT ;
    USE SIGNAL ;
    PORT
      LAYER M5 ;
        RECT  32.976 0 33 0.084 ;
    END
  END pr[134]
  PIN pr[135]
    DIRECTION INPUT ;
    USE SIGNAL ;
    PORT
      LAYER M5 ;
        RECT  33.12 0 33.144 0.084 ;
    END
  END pr[135]
  PIN pr[136]
    DIRECTION INPUT ;
    USE SIGNAL ;
    PORT
      LAYER M5 ;
        RECT  33.216 0 33.24 0.084 ;
    END
  END pr[136]
  PIN pr[137]
    DIRECTION INPUT ;
    USE SIGNAL ;
    PORT
      LAYER M5 ;
        RECT  33.312 0 33.336 0.084 ;
    END
  END pr[137]
  PIN pr[138]
    DIRECTION INPUT ;
    USE SIGNAL ;
    PORT
      LAYER M5 ;
        RECT  33.456 0 33.48 0.084 ;
    END
  END pr[138]
  PIN pr[139]
    DIRECTION INPUT ;
    USE SIGNAL ;
    PORT
      LAYER M5 ;
        RECT  33.552 0 33.576 0.084 ;
    END
  END pr[139]
  PIN pr[13]
    DIRECTION INPUT ;
    USE SIGNAL ;
    PORT
      LAYER M5 ;
        RECT  18.576 0 18.6 0.084 ;
    END
  END pr[13]
  PIN pr[140]
    DIRECTION INPUT ;
    USE SIGNAL ;
    PORT
      LAYER M5 ;
        RECT  33.696 0 33.72 0.084 ;
    END
  END pr[140]
  PIN pr[141]
    DIRECTION INPUT ;
    USE SIGNAL ;
    PORT
      LAYER M5 ;
        RECT  33.792 0 33.816 0.084 ;
    END
  END pr[141]
  PIN pr[142]
    DIRECTION INPUT ;
    USE SIGNAL ;
    PORT
      LAYER M5 ;
        RECT  33.936 0 33.96 0.084 ;
    END
  END pr[142]
  PIN pr[14]
    DIRECTION INPUT ;
    USE SIGNAL ;
    PORT
      LAYER M5 ;
        RECT  18.72 0 18.744 0.084 ;
    END
  END pr[14]
  PIN pr[15]
    DIRECTION INPUT ;
    USE SIGNAL ;
    PORT
      LAYER M5 ;
        RECT  18.816 0 18.84 0.084 ;
    END
  END pr[15]
  PIN pr[16]
    DIRECTION INPUT ;
    USE SIGNAL ;
    PORT
      LAYER M5 ;
        RECT  18.96 0 18.984 0.084 ;
    END
  END pr[16]
  PIN pr[17]
    DIRECTION INPUT ;
    USE SIGNAL ;
    PORT
      LAYER M5 ;
        RECT  19.056 0 19.08 0.084 ;
    END
  END pr[17]
  PIN pr[18]
    DIRECTION INPUT ;
    USE SIGNAL ;
    PORT
      LAYER M5 ;
        RECT  19.2 0 19.224 0.084 ;
    END
  END pr[18]
  PIN pr[19]
    DIRECTION INPUT ;
    USE SIGNAL ;
    PORT
      LAYER M5 ;
        RECT  19.296 0 19.32 0.084 ;
    END
  END pr[19]
  PIN pr[1]
    DIRECTION INPUT ;
    USE SIGNAL ;
    PORT
      LAYER M5 ;
        RECT  17.184 0 17.208 0.084 ;
    END
  END pr[1]
  PIN pr[20]
    DIRECTION INPUT ;
    USE SIGNAL ;
    PORT
      LAYER M5 ;
        RECT  19.44 0 19.464 0.084 ;
    END
  END pr[20]
  PIN pr[21]
    DIRECTION INPUT ;
    USE SIGNAL ;
    PORT
      LAYER M5 ;
        RECT  19.536 0 19.56 0.084 ;
    END
  END pr[21]
  PIN pr[22]
    DIRECTION INPUT ;
    USE SIGNAL ;
    PORT
      LAYER M5 ;
        RECT  19.68 0 19.704 0.084 ;
    END
  END pr[22]
  PIN pr[23]
    DIRECTION INPUT ;
    USE SIGNAL ;
    PORT
      LAYER M5 ;
        RECT  19.776 0 19.8 0.084 ;
    END
  END pr[23]
  PIN pr[24]
    DIRECTION INPUT ;
    USE SIGNAL ;
    PORT
      LAYER M5 ;
        RECT  19.92 0 19.944 0.084 ;
    END
  END pr[24]
  PIN pr[25]
    DIRECTION INPUT ;
    USE SIGNAL ;
    PORT
      LAYER M5 ;
        RECT  20.016 0 20.04 0.084 ;
    END
  END pr[25]
  PIN pr[26]
    DIRECTION INPUT ;
    USE SIGNAL ;
    PORT
      LAYER M5 ;
        RECT  20.16 0 20.184 0.084 ;
    END
  END pr[26]
  PIN pr[27]
    DIRECTION INPUT ;
    USE SIGNAL ;
    PORT
      LAYER M5 ;
        RECT  20.256 0 20.28 0.084 ;
    END
  END pr[27]
  PIN pr[28]
    DIRECTION INPUT ;
    USE SIGNAL ;
    PORT
      LAYER M5 ;
        RECT  20.4 0 20.424 0.084 ;
    END
  END pr[28]
  PIN pr[29]
    DIRECTION INPUT ;
    USE SIGNAL ;
    PORT
      LAYER M5 ;
        RECT  20.496 0 20.52 0.084 ;
    END
  END pr[29]
  PIN pr[2]
    DIRECTION INPUT ;
    USE SIGNAL ;
    PORT
      LAYER M5 ;
        RECT  17.28 0 17.304 0.084 ;
    END
  END pr[2]
  PIN pr[30]
    DIRECTION INPUT ;
    USE SIGNAL ;
    PORT
      LAYER M5 ;
        RECT  20.592 0 20.616 0.084 ;
    END
  END pr[30]
  PIN pr[31]
    DIRECTION INPUT ;
    USE SIGNAL ;
    PORT
      LAYER M5 ;
        RECT  20.736 0 20.76 0.084 ;
    END
  END pr[31]
  PIN pr[32]
    DIRECTION INPUT ;
    USE SIGNAL ;
    PORT
      LAYER M5 ;
        RECT  20.832 0 20.856 0.084 ;
    END
  END pr[32]
  PIN pr[33]
    DIRECTION INPUT ;
    USE SIGNAL ;
    PORT
      LAYER M5 ;
        RECT  20.976 0 21 0.084 ;
    END
  END pr[33]
  PIN pr[34]
    DIRECTION INPUT ;
    USE SIGNAL ;
    PORT
      LAYER M5 ;
        RECT  21.072 0 21.096 0.084 ;
    END
  END pr[34]
  PIN pr[35]
    DIRECTION INPUT ;
    USE SIGNAL ;
    PORT
      LAYER M5 ;
        RECT  21.216 0 21.24 0.084 ;
    END
  END pr[35]
  PIN pr[36]
    DIRECTION INPUT ;
    USE SIGNAL ;
    PORT
      LAYER M5 ;
        RECT  21.312 0 21.336 0.084 ;
    END
  END pr[36]
  PIN pr[37]
    DIRECTION INPUT ;
    USE SIGNAL ;
    PORT
      LAYER M5 ;
        RECT  21.456 0 21.48 0.084 ;
    END
  END pr[37]
  PIN pr[38]
    DIRECTION INPUT ;
    USE SIGNAL ;
    PORT
      LAYER M5 ;
        RECT  21.552 0 21.576 0.084 ;
    END
  END pr[38]
  PIN pr[39]
    DIRECTION INPUT ;
    USE SIGNAL ;
    PORT
      LAYER M5 ;
        RECT  21.696 0 21.72 0.084 ;
    END
  END pr[39]
  PIN pr[3]
    DIRECTION INPUT ;
    USE SIGNAL ;
    PORT
      LAYER M5 ;
        RECT  17.424 0 17.448 0.084 ;
    END
  END pr[3]
  PIN pr[40]
    DIRECTION INPUT ;
    USE SIGNAL ;
    PORT
      LAYER M5 ;
        RECT  21.792 0 21.816 0.084 ;
    END
  END pr[40]
  PIN pr[41]
    DIRECTION INPUT ;
    USE SIGNAL ;
    PORT
      LAYER M5 ;
        RECT  21.936 0 21.96 0.084 ;
    END
  END pr[41]
  PIN pr[42]
    DIRECTION INPUT ;
    USE SIGNAL ;
    PORT
      LAYER M5 ;
        RECT  22.032 0 22.056 0.084 ;
    END
  END pr[42]
  PIN pr[43]
    DIRECTION INPUT ;
    USE SIGNAL ;
    PORT
      LAYER M5 ;
        RECT  22.176 0 22.2 0.084 ;
    END
  END pr[43]
  PIN pr[44]
    DIRECTION INPUT ;
    USE SIGNAL ;
    PORT
      LAYER M5 ;
        RECT  22.272 0 22.296 0.084 ;
    END
  END pr[44]
  PIN pr[45]
    DIRECTION INPUT ;
    USE SIGNAL ;
    PORT
      LAYER M5 ;
        RECT  22.416 0 22.44 0.084 ;
    END
  END pr[45]
  PIN pr[46]
    DIRECTION INPUT ;
    USE SIGNAL ;
    PORT
      LAYER M5 ;
        RECT  22.512 0 22.536 0.084 ;
    END
  END pr[46]
  PIN pr[47]
    DIRECTION INPUT ;
    USE SIGNAL ;
    PORT
      LAYER M5 ;
        RECT  22.656 0 22.68 0.084 ;
    END
  END pr[47]
  PIN pr[48]
    DIRECTION INPUT ;
    USE SIGNAL ;
    PORT
      LAYER M5 ;
        RECT  22.752 0 22.776 0.084 ;
    END
  END pr[48]
  PIN pr[49]
    DIRECTION INPUT ;
    USE SIGNAL ;
    PORT
      LAYER M5 ;
        RECT  22.896 0 22.92 0.084 ;
    END
  END pr[49]
  PIN pr[4]
    DIRECTION INPUT ;
    USE SIGNAL ;
    PORT
      LAYER M5 ;
        RECT  17.52 0 17.544 0.084 ;
    END
  END pr[4]
  PIN pr[50]
    DIRECTION INPUT ;
    USE SIGNAL ;
    PORT
      LAYER M5 ;
        RECT  22.992 0 23.016 0.084 ;
    END
  END pr[50]
  PIN pr[51]
    DIRECTION INPUT ;
    USE SIGNAL ;
    PORT
      LAYER M5 ;
        RECT  23.088 0 23.112 0.084 ;
    END
  END pr[51]
  PIN pr[52]
    DIRECTION INPUT ;
    USE SIGNAL ;
    PORT
      LAYER M5 ;
        RECT  23.232 0 23.256 0.084 ;
    END
  END pr[52]
  PIN pr[53]
    DIRECTION INPUT ;
    USE SIGNAL ;
    PORT
      LAYER M5 ;
        RECT  23.328 0 23.352 0.084 ;
    END
  END pr[53]
  PIN pr[54]
    DIRECTION INPUT ;
    USE SIGNAL ;
    PORT
      LAYER M5 ;
        RECT  23.472 0 23.496 0.084 ;
    END
  END pr[54]
  PIN pr[55]
    DIRECTION INPUT ;
    USE SIGNAL ;
    PORT
      LAYER M5 ;
        RECT  23.568 0 23.592 0.084 ;
    END
  END pr[55]
  PIN pr[56]
    DIRECTION INPUT ;
    USE SIGNAL ;
    PORT
      LAYER M5 ;
        RECT  23.712 0 23.736 0.084 ;
    END
  END pr[56]
  PIN pr[57]
    DIRECTION INPUT ;
    USE SIGNAL ;
    PORT
      LAYER M5 ;
        RECT  23.808 0 23.832 0.084 ;
    END
  END pr[57]
  PIN pr[58]
    DIRECTION INPUT ;
    USE SIGNAL ;
    PORT
      LAYER M5 ;
        RECT  23.952 0 23.976 0.084 ;
    END
  END pr[58]
  PIN pr[59]
    DIRECTION INPUT ;
    USE SIGNAL ;
    PORT
      LAYER M5 ;
        RECT  24.048 0 24.072 0.084 ;
    END
  END pr[59]
  PIN pr[5]
    DIRECTION INPUT ;
    USE SIGNAL ;
    PORT
      LAYER M5 ;
        RECT  17.664 0 17.688 0.084 ;
    END
  END pr[5]
  PIN pr[60]
    DIRECTION INPUT ;
    USE SIGNAL ;
    PORT
      LAYER M5 ;
        RECT  24.192 0 24.216 0.084 ;
    END
  END pr[60]
  PIN pr[61]
    DIRECTION INPUT ;
    USE SIGNAL ;
    PORT
      LAYER M5 ;
        RECT  24.288 0 24.312 0.084 ;
    END
  END pr[61]
  PIN pr[62]
    DIRECTION INPUT ;
    USE SIGNAL ;
    PORT
      LAYER M5 ;
        RECT  24.432 0 24.456 0.084 ;
    END
  END pr[62]
  PIN pr[63]
    DIRECTION INPUT ;
    USE SIGNAL ;
    PORT
      LAYER M5 ;
        RECT  24.528 0 24.552 0.084 ;
    END
  END pr[63]
  PIN pr[64]
    DIRECTION INPUT ;
    USE SIGNAL ;
    PORT
      LAYER M5 ;
        RECT  24.672 0 24.696 0.084 ;
    END
  END pr[64]
  PIN pr[65]
    DIRECTION INPUT ;
    USE SIGNAL ;
    PORT
      LAYER M5 ;
        RECT  24.768 0 24.792 0.084 ;
    END
  END pr[65]
  PIN pr[66]
    DIRECTION INPUT ;
    USE SIGNAL ;
    PORT
      LAYER M5 ;
        RECT  24.912 0 24.936 0.084 ;
    END
  END pr[66]
  PIN pr[67]
    DIRECTION INPUT ;
    USE SIGNAL ;
    PORT
      LAYER M5 ;
        RECT  25.008 0 25.032 0.084 ;
    END
  END pr[67]
  PIN pr[68]
    DIRECTION INPUT ;
    USE SIGNAL ;
    PORT
      LAYER M5 ;
        RECT  25.152 0 25.176 0.084 ;
    END
  END pr[68]
  PIN pr[69]
    DIRECTION INPUT ;
    USE SIGNAL ;
    PORT
      LAYER M5 ;
        RECT  25.248 0 25.272 0.084 ;
    END
  END pr[69]
  PIN pr[6]
    DIRECTION INPUT ;
    USE SIGNAL ;
    PORT
      LAYER M5 ;
        RECT  17.76 0 17.784 0.084 ;
    END
  END pr[6]
  PIN pr[70]
    DIRECTION INPUT ;
    USE SIGNAL ;
    PORT
      LAYER M5 ;
        RECT  25.392 0 25.416 0.084 ;
    END
  END pr[70]
  PIN pr[71]
    DIRECTION INPUT ;
    USE SIGNAL ;
    PORT
      LAYER M5 ;
        RECT  25.488 0 25.512 0.084 ;
    END
  END pr[71]
  PIN pr[72]
    DIRECTION INPUT ;
    USE SIGNAL ;
    PORT
      LAYER M5 ;
        RECT  25.584 0 25.608 0.084 ;
    END
  END pr[72]
  PIN pr[73]
    DIRECTION INPUT ;
    USE SIGNAL ;
    PORT
      LAYER M5 ;
        RECT  25.728 0 25.752 0.084 ;
    END
  END pr[73]
  PIN pr[74]
    DIRECTION INPUT ;
    USE SIGNAL ;
    PORT
      LAYER M5 ;
        RECT  25.824 0 25.848 0.084 ;
    END
  END pr[74]
  PIN pr[75]
    DIRECTION INPUT ;
    USE SIGNAL ;
    PORT
      LAYER M5 ;
        RECT  25.968 0 25.992 0.084 ;
    END
  END pr[75]
  PIN pr[76]
    DIRECTION INPUT ;
    USE SIGNAL ;
    PORT
      LAYER M5 ;
        RECT  26.064 0 26.088 0.084 ;
    END
  END pr[76]
  PIN pr[77]
    DIRECTION INPUT ;
    USE SIGNAL ;
    PORT
      LAYER M5 ;
        RECT  26.208 0 26.232 0.084 ;
    END
  END pr[77]
  PIN pr[78]
    DIRECTION INPUT ;
    USE SIGNAL ;
    PORT
      LAYER M5 ;
        RECT  26.304 0 26.328 0.084 ;
    END
  END pr[78]
  PIN pr[79]
    DIRECTION INPUT ;
    USE SIGNAL ;
    PORT
      LAYER M5 ;
        RECT  26.448 0 26.472 0.084 ;
    END
  END pr[79]
  PIN pr[7]
    DIRECTION INPUT ;
    USE SIGNAL ;
    PORT
      LAYER M5 ;
        RECT  17.904 0 17.928 0.084 ;
    END
  END pr[7]
  PIN pr[80]
    DIRECTION INPUT ;
    USE SIGNAL ;
    PORT
      LAYER M5 ;
        RECT  26.544 0 26.568 0.084 ;
    END
  END pr[80]
  PIN pr[81]
    DIRECTION INPUT ;
    USE SIGNAL ;
    PORT
      LAYER M5 ;
        RECT  26.688 0 26.712 0.084 ;
    END
  END pr[81]
  PIN pr[82]
    DIRECTION INPUT ;
    USE SIGNAL ;
    PORT
      LAYER M5 ;
        RECT  26.784 0 26.808 0.084 ;
    END
  END pr[82]
  PIN pr[83]
    DIRECTION INPUT ;
    USE SIGNAL ;
    PORT
      LAYER M5 ;
        RECT  26.928 0 26.952 0.084 ;
    END
  END pr[83]
  PIN pr[84]
    DIRECTION INPUT ;
    USE SIGNAL ;
    PORT
      LAYER M5 ;
        RECT  27.024 0 27.048 0.084 ;
    END
  END pr[84]
  PIN pr[85]
    DIRECTION INPUT ;
    USE SIGNAL ;
    PORT
      LAYER M5 ;
        RECT  27.168 0 27.192 0.084 ;
    END
  END pr[85]
  PIN pr[86]
    DIRECTION INPUT ;
    USE SIGNAL ;
    PORT
      LAYER M5 ;
        RECT  27.264 0 27.288 0.084 ;
    END
  END pr[86]
  PIN pr[87]
    DIRECTION INPUT ;
    USE SIGNAL ;
    PORT
      LAYER M5 ;
        RECT  27.408 0 27.432 0.084 ;
    END
  END pr[87]
  PIN pr[88]
    DIRECTION INPUT ;
    USE SIGNAL ;
    PORT
      LAYER M5 ;
        RECT  27.504 0 27.528 0.084 ;
    END
  END pr[88]
  PIN pr[89]
    DIRECTION INPUT ;
    USE SIGNAL ;
    PORT
      LAYER M5 ;
        RECT  27.648 0 27.672 0.084 ;
    END
  END pr[89]
  PIN pr[8]
    DIRECTION INPUT ;
    USE SIGNAL ;
    PORT
      LAYER M5 ;
        RECT  18 0 18.024 0.084 ;
    END
  END pr[8]
  PIN pr[90]
    DIRECTION INPUT ;
    USE SIGNAL ;
    PORT
      LAYER M5 ;
        RECT  27.744 0 27.768 0.084 ;
    END
  END pr[90]
  PIN pr[91]
    DIRECTION INPUT ;
    USE SIGNAL ;
    PORT
      LAYER M5 ;
        RECT  27.888 0 27.912 0.084 ;
    END
  END pr[91]
  PIN pr[92]
    DIRECTION INPUT ;
    USE SIGNAL ;
    PORT
      LAYER M5 ;
        RECT  27.984 0 28.008 0.084 ;
    END
  END pr[92]
  PIN pr[93]
    DIRECTION INPUT ;
    USE SIGNAL ;
    PORT
      LAYER M5 ;
        RECT  28.08 0 28.104 0.084 ;
    END
  END pr[93]
  PIN pr[94]
    DIRECTION INPUT ;
    USE SIGNAL ;
    PORT
      LAYER M5 ;
        RECT  28.224 0 28.248 0.084 ;
    END
  END pr[94]
  PIN pr[95]
    DIRECTION INPUT ;
    USE SIGNAL ;
    PORT
      LAYER M5 ;
        RECT  28.32 0 28.344 0.084 ;
    END
  END pr[95]
  PIN pr[96]
    DIRECTION INPUT ;
    USE SIGNAL ;
    PORT
      LAYER M5 ;
        RECT  28.464 0 28.488 0.084 ;
    END
  END pr[96]
  PIN pr[97]
    DIRECTION INPUT ;
    USE SIGNAL ;
    PORT
      LAYER M5 ;
        RECT  28.56 0 28.584 0.084 ;
    END
  END pr[97]
  PIN pr[98]
    DIRECTION INPUT ;
    USE SIGNAL ;
    PORT
      LAYER M5 ;
        RECT  28.704 0 28.728 0.084 ;
    END
  END pr[98]
  PIN pr[99]
    DIRECTION INPUT ;
    USE SIGNAL ;
    PORT
      LAYER M5 ;
        RECT  28.8 0 28.824 0.084 ;
    END
  END pr[99]
  PIN pr[9]
    DIRECTION INPUT ;
    USE SIGNAL ;
    PORT
      LAYER M5 ;
        RECT  18.096 0 18.12 0.084 ;
    END
  END pr[9]
  PIN ready
    DIRECTION INPUT ;
    USE SIGNAL ;
    PORT
      LAYER M5 ;
        RECT  40.512 0 40.536 0.084 ;
    END
    PORT
      LAYER M5 ;
        RECT  40.512 0.016 40.536 0.611 ;
    END
  END ready
  PIN req[0]
    DIRECTION INPUT ;
    USE SIGNAL ;
    PORT
      LAYER M5 ;
        RECT  4.032 0 4.056 0.084 ;
    END
  END req[0]
  PIN req[10]
    DIRECTION INPUT ;
    USE SIGNAL ;
    PORT
      LAYER M5 ;
        RECT  5.376 0 5.4 0.084 ;
    END
  END req[10]
  PIN req[11]
    DIRECTION INPUT ;
    USE SIGNAL ;
    PORT
      LAYER M5 ;
        RECT  5.52 0 5.544 0.084 ;
    END
  END req[11]
  PIN req[12]
    DIRECTION INPUT ;
    USE SIGNAL ;
    PORT
      LAYER M5 ;
        RECT  5.616 0 5.64 0.084 ;
    END
  END req[12]
  PIN req[13]
    DIRECTION INPUT ;
    USE SIGNAL ;
    PORT
      LAYER M5 ;
        RECT  5.76 0 5.784 0.084 ;
    END
  END req[13]
  PIN req[14]
    DIRECTION INPUT ;
    USE SIGNAL ;
    PORT
      LAYER M5 ;
        RECT  5.904 0 5.928 0.084 ;
    END
  END req[14]
  PIN req[15]
    DIRECTION INPUT ;
    USE SIGNAL ;
    PORT
      LAYER M5 ;
        RECT  6 0 6.024 0.084 ;
    END
  END req[15]
  PIN req[16]
    DIRECTION INPUT ;
    USE SIGNAL ;
    PORT
      LAYER M5 ;
        RECT  6.144 0 6.168 0.084 ;
    END
  END req[16]
  PIN req[17]
    DIRECTION INPUT ;
    USE SIGNAL ;
    PORT
      LAYER M5 ;
        RECT  6.288 0 6.312 0.084 ;
    END
  END req[17]
  PIN req[18]
    DIRECTION INPUT ;
    USE SIGNAL ;
    PORT
      LAYER M5 ;
        RECT  6.432 0 6.456 0.084 ;
    END
  END req[18]
  PIN req[19]
    DIRECTION INPUT ;
    USE SIGNAL ;
    PORT
      LAYER M5 ;
        RECT  6.528 0 6.552 0.084 ;
    END
  END req[19]
  PIN req[1]
    DIRECTION INPUT ;
    USE SIGNAL ;
    PORT
      LAYER M5 ;
        RECT  4.176 0 4.2 0.084 ;
    END
  END req[1]
  PIN req[20]
    DIRECTION INPUT ;
    USE SIGNAL ;
    PORT
      LAYER M5 ;
        RECT  6.672 0 6.696 0.084 ;
    END
  END req[20]
  PIN req[21]
    DIRECTION INPUT ;
    USE SIGNAL ;
    PORT
      LAYER M5 ;
        RECT  6.816 0 6.84 0.084 ;
    END
  END req[21]
  PIN req[22]
    DIRECTION INPUT ;
    USE SIGNAL ;
    PORT
      LAYER M5 ;
        RECT  6.96 0 6.984 0.084 ;
    END
  END req[22]
  PIN req[23]
    DIRECTION INPUT ;
    USE SIGNAL ;
    PORT
      LAYER M5 ;
        RECT  7.056 0 7.08 0.084 ;
    END
  END req[23]
  PIN req[24]
    DIRECTION INPUT ;
    USE SIGNAL ;
    PORT
      LAYER M5 ;
        RECT  7.2 0 7.224 0.084 ;
    END
  END req[24]
  PIN req[25]
    DIRECTION INPUT ;
    USE SIGNAL ;
    PORT
      LAYER M5 ;
        RECT  7.344 0 7.368 0.084 ;
    END
  END req[25]
  PIN req[26]
    DIRECTION INPUT ;
    USE SIGNAL ;
    PORT
      LAYER M5 ;
        RECT  7.44 0 7.464 0.084 ;
    END
  END req[26]
  PIN req[27]
    DIRECTION INPUT ;
    USE SIGNAL ;
    PORT
      LAYER M5 ;
        RECT  7.584 0 7.608 0.084 ;
    END
  END req[27]
  PIN req[28]
    DIRECTION INPUT ;
    USE SIGNAL ;
    PORT
      LAYER M5 ;
        RECT  7.728 0 7.752 0.084 ;
    END
  END req[28]
  PIN req[29]
    DIRECTION INPUT ;
    USE SIGNAL ;
    PORT
      LAYER M5 ;
        RECT  7.872 0 7.896 0.084 ;
    END
  END req[29]
  PIN req[2]
    DIRECTION INPUT ;
    USE SIGNAL ;
    PORT
      LAYER M5 ;
        RECT  4.32 0 4.344 0.084 ;
    END
  END req[2]
  PIN req[30]
    DIRECTION INPUT ;
    USE SIGNAL ;
    PORT
      LAYER M5 ;
        RECT  7.968 0 7.992 0.084 ;
    END
  END req[30]
  PIN req[31]
    DIRECTION INPUT ;
    USE SIGNAL ;
    PORT
      LAYER M5 ;
        RECT  8.112 0 8.136 0.084 ;
    END
  END req[31]
  PIN req[32]
    DIRECTION INPUT ;
    USE SIGNAL ;
    PORT
      LAYER M5 ;
        RECT  8.256 0 8.28 0.084 ;
    END
  END req[32]
  PIN req[33]
    DIRECTION INPUT ;
    USE SIGNAL ;
    PORT
      LAYER M5 ;
        RECT  8.4 0 8.424 0.084 ;
    END
  END req[33]
  PIN req[34]
    DIRECTION INPUT ;
    USE SIGNAL ;
    PORT
      LAYER M5 ;
        RECT  8.496 0 8.52 0.084 ;
    END
  END req[34]
  PIN req[35]
    DIRECTION INPUT ;
    USE SIGNAL ;
    PORT
      LAYER M5 ;
        RECT  8.64 0 8.664 0.084 ;
    END
  END req[35]
  PIN req[36]
    DIRECTION INPUT ;
    USE SIGNAL ;
    PORT
      LAYER M5 ;
        RECT  8.784 0 8.808 0.084 ;
    END
  END req[36]
  PIN req[37]
    DIRECTION INPUT ;
    USE SIGNAL ;
    PORT
      LAYER M5 ;
        RECT  8.928 0 8.952 0.084 ;
    END
  END req[37]
  PIN req[38]
    DIRECTION INPUT ;
    USE SIGNAL ;
    PORT
      LAYER M5 ;
        RECT  9.024 0 9.048 0.084 ;
    END
  END req[38]
  PIN req[39]
    DIRECTION INPUT ;
    USE SIGNAL ;
    PORT
      LAYER M5 ;
        RECT  9.168 0 9.192 0.084 ;
    END
  END req[39]
  PIN req[3]
    DIRECTION INPUT ;
    USE SIGNAL ;
    PORT
      LAYER M5 ;
        RECT  4.464 0 4.488 0.084 ;
    END
  END req[3]
  PIN req[40]
    DIRECTION INPUT ;
    USE SIGNAL ;
    PORT
      LAYER M5 ;
        RECT  9.312 0 9.336 0.084 ;
    END
  END req[40]
  PIN req[41]
    DIRECTION INPUT ;
    USE SIGNAL ;
    PORT
      LAYER M5 ;
        RECT  9.408 0 9.432 0.084 ;
    END
  END req[41]
  PIN req[42]
    DIRECTION INPUT ;
    USE SIGNAL ;
    PORT
      LAYER M5 ;
        RECT  9.552 0 9.576 0.084 ;
    END
  END req[42]
  PIN req[43]
    DIRECTION INPUT ;
    USE SIGNAL ;
    PORT
      LAYER M5 ;
        RECT  9.696 0 9.72 0.084 ;
    END
  END req[43]
  PIN req[44]
    DIRECTION INPUT ;
    USE SIGNAL ;
    PORT
      LAYER M5 ;
        RECT  9.84 0 9.864 0.084 ;
    END
  END req[44]
  PIN req[45]
    DIRECTION INPUT ;
    USE SIGNAL ;
    PORT
      LAYER M5 ;
        RECT  9.936 0 9.96 0.084 ;
    END
  END req[45]
  PIN req[46]
    DIRECTION INPUT ;
    USE SIGNAL ;
    PORT
      LAYER M5 ;
        RECT  10.08 0 10.104 0.084 ;
    END
  END req[46]
  PIN req[47]
    DIRECTION INPUT ;
    USE SIGNAL ;
    PORT
      LAYER M5 ;
        RECT  10.224 0 10.248 0.084 ;
    END
  END req[47]
  PIN req[48]
    DIRECTION INPUT ;
    USE SIGNAL ;
    PORT
      LAYER M5 ;
        RECT  10.368 0 10.392 0.084 ;
    END
  END req[48]
  PIN req[49]
    DIRECTION INPUT ;
    USE SIGNAL ;
    PORT
      LAYER M5 ;
        RECT  10.464 0 10.488 0.084 ;
    END
  END req[49]
  PIN req[4]
    DIRECTION INPUT ;
    USE SIGNAL ;
    PORT
      LAYER M5 ;
        RECT  4.56 0 4.584 0.084 ;
    END
  END req[4]
  PIN req[50]
    DIRECTION INPUT ;
    USE SIGNAL ;
    PORT
      LAYER M5 ;
        RECT  10.608 0 10.632 0.084 ;
    END
  END req[50]
  PIN req[51]
    DIRECTION INPUT ;
    USE SIGNAL ;
    PORT
      LAYER M5 ;
        RECT  10.752 0 10.776 0.084 ;
    END
  END req[51]
  PIN req[52]
    DIRECTION INPUT ;
    USE SIGNAL ;
    PORT
      LAYER M5 ;
        RECT  10.896 0 10.92 0.084 ;
    END
  END req[52]
  PIN req[53]
    DIRECTION INPUT ;
    USE SIGNAL ;
    PORT
      LAYER M5 ;
        RECT  10.992 0 11.016 0.084 ;
    END
  END req[53]
  PIN req[54]
    DIRECTION INPUT ;
    USE SIGNAL ;
    PORT
      LAYER M5 ;
        RECT  11.136 0 11.16 0.084 ;
    END
  END req[54]
  PIN req[55]
    DIRECTION INPUT ;
    USE SIGNAL ;
    PORT
      LAYER M5 ;
        RECT  11.28 0 11.304 0.084 ;
    END
  END req[55]
  PIN req[56]
    DIRECTION INPUT ;
    USE SIGNAL ;
    PORT
      LAYER M5 ;
        RECT  11.376 0 11.4 0.084 ;
    END
  END req[56]
  PIN req[57]
    DIRECTION INPUT ;
    USE SIGNAL ;
    PORT
      LAYER M5 ;
        RECT  11.52 0 11.544 0.084 ;
    END
  END req[57]
  PIN req[58]
    DIRECTION INPUT ;
    USE SIGNAL ;
    PORT
      LAYER M5 ;
        RECT  11.664 0 11.688 0.084 ;
    END
  END req[58]
  PIN req[59]
    DIRECTION INPUT ;
    USE SIGNAL ;
    PORT
      LAYER M5 ;
        RECT  11.808 0 11.832 0.084 ;
    END
  END req[59]
  PIN req[5]
    DIRECTION INPUT ;
    USE SIGNAL ;
    PORT
      LAYER M5 ;
        RECT  4.704 0 4.728 0.084 ;
    END
  END req[5]
  PIN req[60]
    DIRECTION INPUT ;
    USE SIGNAL ;
    PORT
      LAYER M5 ;
        RECT  11.904 0 11.928 0.084 ;
    END
  END req[60]
  PIN req[6]
    DIRECTION INPUT ;
    USE SIGNAL ;
    PORT
      LAYER M5 ;
        RECT  4.848 0 4.872 0.084 ;
    END
  END req[6]
  PIN req[7]
    DIRECTION INPUT ;
    USE SIGNAL ;
    PORT
      LAYER M5 ;
        RECT  4.992 0 5.016 0.084 ;
    END
  END req[7]
  PIN req[8]
    DIRECTION INPUT ;
    USE SIGNAL ;
    PORT
      LAYER M5 ;
        RECT  5.088 0 5.112 0.084 ;
    END
  END req[8]
  PIN req[9]
    DIRECTION INPUT ;
    USE SIGNAL ;
    PORT
      LAYER M5 ;
        RECT  5.232 0 5.256 0.084 ;
    END
  END req[9]
  PIN res[0]
    DIRECTION OUTPUT ;
    USE SIGNAL ;
    PORT
      LAYER M4 ;
        RECT  64.716 40.032 64.8 40.056 ;
    END
  END res[0]
  PIN res[100]
    DIRECTION OUTPUT ;
    USE SIGNAL ;
    PORT
      LAYER M4 ;
        RECT  64.716 51.696 64.8 51.72 ;
    END
  END res[100]
  PIN res[101]
    DIRECTION OUTPUT ;
    USE SIGNAL ;
    PORT
      LAYER M4 ;
        RECT  64.716 51.84 64.8 51.864 ;
    END
  END res[101]
  PIN res[102]
    DIRECTION OUTPUT ;
    USE SIGNAL ;
    PORT
      LAYER M4 ;
        RECT  64.716 51.936 64.8 51.96 ;
    END
  END res[102]
  PIN res[103]
    DIRECTION OUTPUT ;
    USE SIGNAL ;
    PORT
      LAYER M4 ;
        RECT  64.716 52.08 64.8 52.104 ;
    END
  END res[103]
  PIN res[104]
    DIRECTION OUTPUT ;
    USE SIGNAL ;
    PORT
      LAYER M4 ;
        RECT  64.716 52.176 64.8 52.2 ;
    END
  END res[104]
  PIN res[105]
    DIRECTION OUTPUT ;
    USE SIGNAL ;
    PORT
      LAYER M4 ;
        RECT  64.716 52.32 64.8 52.344 ;
    END
  END res[105]
  PIN res[106]
    DIRECTION OUTPUT ;
    USE SIGNAL ;
    PORT
      LAYER M4 ;
        RECT  64.716 52.416 64.8 52.44 ;
    END
  END res[106]
  PIN res[107]
    DIRECTION OUTPUT ;
    USE SIGNAL ;
    PORT
      LAYER M4 ;
        RECT  64.716 52.512 64.8 52.536 ;
    END
  END res[107]
  PIN res[108]
    DIRECTION OUTPUT ;
    USE SIGNAL ;
    PORT
      LAYER M4 ;
        RECT  64.716 52.656 64.8 52.68 ;
    END
  END res[108]
  PIN res[109]
    DIRECTION OUTPUT ;
    USE SIGNAL ;
    PORT
      LAYER M4 ;
        RECT  64.716 52.752 64.8 52.776 ;
    END
  END res[109]
  PIN res[10]
    DIRECTION OUTPUT ;
    USE SIGNAL ;
    PORT
      LAYER M4 ;
        RECT  64.716 41.232 64.8 41.256 ;
    END
  END res[10]
  PIN res[110]
    DIRECTION OUTPUT ;
    USE SIGNAL ;
    PORT
      LAYER M4 ;
        RECT  64.716 52.896 64.8 52.92 ;
    END
  END res[110]
  PIN res[111]
    DIRECTION OUTPUT ;
    USE SIGNAL ;
    PORT
      LAYER M4 ;
        RECT  64.716 52.992 64.8 53.016 ;
    END
  END res[111]
  PIN res[112]
    DIRECTION OUTPUT ;
    USE SIGNAL ;
    PORT
      LAYER M4 ;
        RECT  64.716 53.136 64.8 53.16 ;
    END
  END res[112]
  PIN res[113]
    DIRECTION OUTPUT ;
    USE SIGNAL ;
    PORT
      LAYER M4 ;
        RECT  64.716 53.232 64.8 53.256 ;
    END
  END res[113]
  PIN res[114]
    DIRECTION OUTPUT ;
    USE SIGNAL ;
    PORT
      LAYER M4 ;
        RECT  64.716 53.328 64.8 53.352 ;
    END
  END res[114]
  PIN res[115]
    DIRECTION OUTPUT ;
    USE SIGNAL ;
    PORT
      LAYER M4 ;
        RECT  64.716 53.472 64.8 53.496 ;
    END
  END res[115]
  PIN res[116]
    DIRECTION OUTPUT ;
    USE SIGNAL ;
    PORT
      LAYER M4 ;
        RECT  64.716 53.568 64.8 53.592 ;
    END
  END res[116]
  PIN res[117]
    DIRECTION OUTPUT ;
    USE SIGNAL ;
    PORT
      LAYER M4 ;
        RECT  64.716 53.712 64.8 53.736 ;
    END
  END res[117]
  PIN res[118]
    DIRECTION OUTPUT ;
    USE SIGNAL ;
    PORT
      LAYER M4 ;
        RECT  64.716 53.808 64.8 53.832 ;
    END
  END res[118]
  PIN res[119]
    DIRECTION OUTPUT ;
    USE SIGNAL ;
    PORT
      LAYER M4 ;
        RECT  64.716 53.952 64.8 53.976 ;
    END
  END res[119]
  PIN res[11]
    DIRECTION OUTPUT ;
    USE SIGNAL ;
    PORT
      LAYER M4 ;
        RECT  64.716 41.328 64.8 41.352 ;
    END
  END res[11]
  PIN res[12]
    DIRECTION OUTPUT ;
    USE SIGNAL ;
    PORT
      LAYER M4 ;
        RECT  64.716 41.424 64.8 41.448 ;
    END
  END res[12]
  PIN res[13]
    DIRECTION OUTPUT ;
    USE SIGNAL ;
    PORT
      LAYER M4 ;
        RECT  64.716 41.568 64.8 41.592 ;
    END
  END res[13]
  PIN res[14]
    DIRECTION OUTPUT ;
    USE SIGNAL ;
    PORT
      LAYER M4 ;
        RECT  64.716 41.664 64.8 41.688 ;
    END
  END res[14]
  PIN res[15]
    DIRECTION OUTPUT ;
    USE SIGNAL ;
    PORT
      LAYER M4 ;
        RECT  64.716 41.808 64.8 41.832 ;
    END
  END res[15]
  PIN res[16]
    DIRECTION OUTPUT ;
    USE SIGNAL ;
    PORT
      LAYER M4 ;
        RECT  64.716 41.904 64.8 41.928 ;
    END
  END res[16]
  PIN res[17]
    DIRECTION OUTPUT ;
    USE SIGNAL ;
    PORT
      LAYER M4 ;
        RECT  64.716 42.048 64.8 42.072 ;
    END
  END res[17]
  PIN res[18]
    DIRECTION OUTPUT ;
    USE SIGNAL ;
    PORT
      LAYER M4 ;
        RECT  64.716 42.144 64.8 42.168 ;
    END
  END res[18]
  PIN res[19]
    DIRECTION OUTPUT ;
    USE SIGNAL ;
    PORT
      LAYER M4 ;
        RECT  64.716 42.24 64.8 42.264 ;
    END
  END res[19]
  PIN res[1]
    DIRECTION OUTPUT ;
    USE SIGNAL ;
    PORT
      LAYER M4 ;
        RECT  64.716 40.176 64.8 40.2 ;
    END
  END res[1]
  PIN res[20]
    DIRECTION OUTPUT ;
    USE SIGNAL ;
    PORT
      LAYER M4 ;
        RECT  64.716 42.384 64.8 42.408 ;
    END
  END res[20]
  PIN res[21]
    DIRECTION OUTPUT ;
    USE SIGNAL ;
    PORT
      LAYER M4 ;
        RECT  64.716 42.48 64.8 42.504 ;
    END
  END res[21]
  PIN res[22]
    DIRECTION OUTPUT ;
    USE SIGNAL ;
    PORT
      LAYER M4 ;
        RECT  64.716 42.624 64.8 42.648 ;
    END
  END res[22]
  PIN res[23]
    DIRECTION OUTPUT ;
    USE SIGNAL ;
    PORT
      LAYER M4 ;
        RECT  64.716 42.72 64.8 42.744 ;
    END
  END res[23]
  PIN res[24]
    DIRECTION OUTPUT ;
    USE SIGNAL ;
    PORT
      LAYER M4 ;
        RECT  64.716 42.864 64.8 42.888 ;
    END
  END res[24]
  PIN res[25]
    DIRECTION OUTPUT ;
    USE SIGNAL ;
    PORT
      LAYER M4 ;
        RECT  64.716 42.96 64.8 42.984 ;
    END
  END res[25]
  PIN res[26]
    DIRECTION OUTPUT ;
    USE SIGNAL ;
    PORT
      LAYER M4 ;
        RECT  64.716 43.104 64.8 43.128 ;
    END
  END res[26]
  PIN res[27]
    DIRECTION OUTPUT ;
    USE SIGNAL ;
    PORT
      LAYER M4 ;
        RECT  64.716 43.2 64.8 43.224 ;
    END
  END res[27]
  PIN res[28]
    DIRECTION OUTPUT ;
    USE SIGNAL ;
    PORT
      LAYER M4 ;
        RECT  64.716 43.296 64.8 43.32 ;
    END
  END res[28]
  PIN res[29]
    DIRECTION OUTPUT ;
    USE SIGNAL ;
    PORT
      LAYER M4 ;
        RECT  64.716 43.44 64.8 43.464 ;
    END
  END res[29]
  PIN res[2]
    DIRECTION OUTPUT ;
    USE SIGNAL ;
    PORT
      LAYER M4 ;
        RECT  64.716 40.272 64.8 40.296 ;
    END
  END res[2]
  PIN res[30]
    DIRECTION OUTPUT ;
    USE SIGNAL ;
    PORT
      LAYER M4 ;
        RECT  64.716 43.536 64.8 43.56 ;
    END
  END res[30]
  PIN res[31]
    DIRECTION OUTPUT ;
    USE SIGNAL ;
    PORT
      LAYER M4 ;
        RECT  64.716 43.68 64.8 43.704 ;
    END
  END res[31]
  PIN res[32]
    DIRECTION OUTPUT ;
    USE SIGNAL ;
    PORT
      LAYER M4 ;
        RECT  64.716 43.776 64.8 43.8 ;
    END
  END res[32]
  PIN res[33]
    DIRECTION OUTPUT ;
    USE SIGNAL ;
    PORT
      LAYER M4 ;
        RECT  64.716 43.92 64.8 43.944 ;
    END
  END res[33]
  PIN res[34]
    DIRECTION OUTPUT ;
    USE SIGNAL ;
    PORT
      LAYER M4 ;
        RECT  64.716 44.016 64.8 44.04 ;
    END
  END res[34]
  PIN res[35]
    DIRECTION OUTPUT ;
    USE SIGNAL ;
    PORT
      LAYER M4 ;
        RECT  64.716 44.112 64.8 44.136 ;
    END
  END res[35]
  PIN res[36]
    DIRECTION OUTPUT ;
    USE SIGNAL ;
    PORT
      LAYER M4 ;
        RECT  64.716 44.256 64.8 44.28 ;
    END
  END res[36]
  PIN res[37]
    DIRECTION OUTPUT ;
    USE SIGNAL ;
    PORT
      LAYER M4 ;
        RECT  64.716 44.352 64.8 44.376 ;
    END
  END res[37]
  PIN res[38]
    DIRECTION OUTPUT ;
    USE SIGNAL ;
    PORT
      LAYER M4 ;
        RECT  64.716 44.496 64.8 44.52 ;
    END
  END res[38]
  PIN res[39]
    DIRECTION OUTPUT ;
    USE SIGNAL ;
    PORT
      LAYER M4 ;
        RECT  64.716 44.592 64.8 44.616 ;
    END
  END res[39]
  PIN res[3]
    DIRECTION OUTPUT ;
    USE SIGNAL ;
    PORT
      LAYER M4 ;
        RECT  64.716 40.416 64.8 40.44 ;
    END
  END res[3]
  PIN res[40]
    DIRECTION OUTPUT ;
    USE SIGNAL ;
    PORT
      LAYER M4 ;
        RECT  64.716 44.736 64.8 44.76 ;
    END
  END res[40]
  PIN res[41]
    DIRECTION OUTPUT ;
    USE SIGNAL ;
    PORT
      LAYER M4 ;
        RECT  64.716 44.832 64.8 44.856 ;
    END
  END res[41]
  PIN res[42]
    DIRECTION OUTPUT ;
    USE SIGNAL ;
    PORT
      LAYER M4 ;
        RECT  64.716 44.928 64.8 44.952 ;
    END
  END res[42]
  PIN res[43]
    DIRECTION OUTPUT ;
    USE SIGNAL ;
    PORT
      LAYER M4 ;
        RECT  64.716 45.072 64.8 45.096 ;
    END
  END res[43]
  PIN res[44]
    DIRECTION OUTPUT ;
    USE SIGNAL ;
    PORT
      LAYER M4 ;
        RECT  64.716 45.168 64.8 45.192 ;
    END
  END res[44]
  PIN res[45]
    DIRECTION OUTPUT ;
    USE SIGNAL ;
    PORT
      LAYER M4 ;
        RECT  64.716 45.312 64.8 45.336 ;
    END
  END res[45]
  PIN res[46]
    DIRECTION OUTPUT ;
    USE SIGNAL ;
    PORT
      LAYER M4 ;
        RECT  64.716 45.408 64.8 45.432 ;
    END
  END res[46]
  PIN res[47]
    DIRECTION OUTPUT ;
    USE SIGNAL ;
    PORT
      LAYER M4 ;
        RECT  64.716 45.552 64.8 45.576 ;
    END
  END res[47]
  PIN res[48]
    DIRECTION OUTPUT ;
    USE SIGNAL ;
    PORT
      LAYER M4 ;
        RECT  64.716 45.648 64.8 45.672 ;
    END
  END res[48]
  PIN res[49]
    DIRECTION OUTPUT ;
    USE SIGNAL ;
    PORT
      LAYER M4 ;
        RECT  64.716 45.744 64.8 45.768 ;
    END
  END res[49]
  PIN res[4]
    DIRECTION OUTPUT ;
    USE SIGNAL ;
    PORT
      LAYER M4 ;
        RECT  64.716 40.512 64.8 40.536 ;
    END
  END res[4]
  PIN res[50]
    DIRECTION OUTPUT ;
    USE SIGNAL ;
    PORT
      LAYER M4 ;
        RECT  64.716 45.888 64.8 45.912 ;
    END
  END res[50]
  PIN res[51]
    DIRECTION OUTPUT ;
    USE SIGNAL ;
    PORT
      LAYER M4 ;
        RECT  64.716 45.984 64.8 46.008 ;
    END
  END res[51]
  PIN res[52]
    DIRECTION OUTPUT ;
    USE SIGNAL ;
    PORT
      LAYER M4 ;
        RECT  64.716 46.128 64.8 46.152 ;
    END
  END res[52]
  PIN res[53]
    DIRECTION OUTPUT ;
    USE SIGNAL ;
    PORT
      LAYER M4 ;
        RECT  64.716 46.224 64.8 46.248 ;
    END
  END res[53]
  PIN res[54]
    DIRECTION OUTPUT ;
    USE SIGNAL ;
    PORT
      LAYER M4 ;
        RECT  64.716 46.368 64.8 46.392 ;
    END
  END res[54]
  PIN res[55]
    DIRECTION OUTPUT ;
    USE SIGNAL ;
    PORT
      LAYER M4 ;
        RECT  64.716 46.464 64.8 46.488 ;
    END
  END res[55]
  PIN res[56]
    DIRECTION OUTPUT ;
    USE SIGNAL ;
    PORT
      LAYER M4 ;
        RECT  64.716 46.56 64.8 46.584 ;
    END
  END res[56]
  PIN res[57]
    DIRECTION OUTPUT ;
    USE SIGNAL ;
    PORT
      LAYER M4 ;
        RECT  64.716 46.704 64.8 46.728 ;
    END
  END res[57]
  PIN res[58]
    DIRECTION OUTPUT ;
    USE SIGNAL ;
    PORT
      LAYER M4 ;
        RECT  64.716 46.8 64.8 46.824 ;
    END
  END res[58]
  PIN res[59]
    DIRECTION OUTPUT ;
    USE SIGNAL ;
    PORT
      LAYER M4 ;
        RECT  64.716 46.944 64.8 46.968 ;
    END
  END res[59]
  PIN res[5]
    DIRECTION OUTPUT ;
    USE SIGNAL ;
    PORT
      LAYER M4 ;
        RECT  64.716 40.608 64.8 40.632 ;
    END
  END res[5]
  PIN res[60]
    DIRECTION OUTPUT ;
    USE SIGNAL ;
    PORT
      LAYER M4 ;
        RECT  64.716 47.04 64.8 47.064 ;
    END
  END res[60]
  PIN res[61]
    DIRECTION OUTPUT ;
    USE SIGNAL ;
    PORT
      LAYER M4 ;
        RECT  64.716 47.184 64.8 47.208 ;
    END
  END res[61]
  PIN res[62]
    DIRECTION OUTPUT ;
    USE SIGNAL ;
    PORT
      LAYER M4 ;
        RECT  64.716 47.28 64.8 47.304 ;
    END
  END res[62]
  PIN res[63]
    DIRECTION OUTPUT ;
    USE SIGNAL ;
    PORT
      LAYER M4 ;
        RECT  64.716 47.376 64.8 47.4 ;
    END
  END res[63]
  PIN res[64]
    DIRECTION OUTPUT ;
    USE SIGNAL ;
    PORT
      LAYER M4 ;
        RECT  64.716 47.52 64.8 47.544 ;
    END
  END res[64]
  PIN res[65]
    DIRECTION OUTPUT ;
    USE SIGNAL ;
    PORT
      LAYER M4 ;
        RECT  64.716 47.616 64.8 47.64 ;
    END
  END res[65]
  PIN res[66]
    DIRECTION OUTPUT ;
    USE SIGNAL ;
    PORT
      LAYER M4 ;
        RECT  64.716 47.76 64.8 47.784 ;
    END
  END res[66]
  PIN res[67]
    DIRECTION OUTPUT ;
    USE SIGNAL ;
    PORT
      LAYER M4 ;
        RECT  64.716 47.856 64.8 47.88 ;
    END
  END res[67]
  PIN res[68]
    DIRECTION OUTPUT ;
    USE SIGNAL ;
    PORT
      LAYER M4 ;
        RECT  64.716 48 64.8 48.024 ;
    END
  END res[68]
  PIN res[69]
    DIRECTION OUTPUT ;
    USE SIGNAL ;
    PORT
      LAYER M4 ;
        RECT  64.716 48.096 64.8 48.12 ;
    END
  END res[69]
  PIN res[6]
    DIRECTION OUTPUT ;
    USE SIGNAL ;
    PORT
      LAYER M4 ;
        RECT  64.716 40.752 64.8 40.776 ;
    END
  END res[6]
  PIN res[70]
    DIRECTION OUTPUT ;
    USE SIGNAL ;
    PORT
      LAYER M4 ;
        RECT  64.716 48.192 64.8 48.216 ;
    END
  END res[70]
  PIN res[71]
    DIRECTION OUTPUT ;
    USE SIGNAL ;
    PORT
      LAYER M4 ;
        RECT  64.716 48.336 64.8 48.36 ;
    END
  END res[71]
  PIN res[72]
    DIRECTION OUTPUT ;
    USE SIGNAL ;
    PORT
      LAYER M4 ;
        RECT  64.716 48.432 64.8 48.456 ;
    END
  END res[72]
  PIN res[73]
    DIRECTION OUTPUT ;
    USE SIGNAL ;
    PORT
      LAYER M4 ;
        RECT  64.716 48.576 64.8 48.6 ;
    END
  END res[73]
  PIN res[74]
    DIRECTION OUTPUT ;
    USE SIGNAL ;
    PORT
      LAYER M4 ;
        RECT  64.716 48.672 64.8 48.696 ;
    END
  END res[74]
  PIN res[75]
    DIRECTION OUTPUT ;
    USE SIGNAL ;
    PORT
      LAYER M4 ;
        RECT  64.716 48.816 64.8 48.84 ;
    END
  END res[75]
  PIN res[76]
    DIRECTION OUTPUT ;
    USE SIGNAL ;
    PORT
      LAYER M4 ;
        RECT  64.716 48.912 64.8 48.936 ;
    END
  END res[76]
  PIN res[77]
    DIRECTION OUTPUT ;
    USE SIGNAL ;
    PORT
      LAYER M4 ;
        RECT  64.716 49.008 64.8 49.032 ;
    END
  END res[77]
  PIN res[78]
    DIRECTION OUTPUT ;
    USE SIGNAL ;
    PORT
      LAYER M4 ;
        RECT  64.716 49.152 64.8 49.176 ;
    END
  END res[78]
  PIN res[79]
    DIRECTION OUTPUT ;
    USE SIGNAL ;
    PORT
      LAYER M4 ;
        RECT  64.716 49.248 64.8 49.272 ;
    END
  END res[79]
  PIN res[7]
    DIRECTION OUTPUT ;
    USE SIGNAL ;
    PORT
      LAYER M4 ;
        RECT  64.716 40.848 64.8 40.872 ;
    END
  END res[7]
  PIN res[80]
    DIRECTION OUTPUT ;
    USE SIGNAL ;
    PORT
      LAYER M4 ;
        RECT  64.716 49.392 64.8 49.416 ;
    END
  END res[80]
  PIN res[81]
    DIRECTION OUTPUT ;
    USE SIGNAL ;
    PORT
      LAYER M4 ;
        RECT  64.716 49.488 64.8 49.512 ;
    END
  END res[81]
  PIN res[82]
    DIRECTION OUTPUT ;
    USE SIGNAL ;
    PORT
      LAYER M4 ;
        RECT  64.716 49.632 64.8 49.656 ;
    END
  END res[82]
  PIN res[83]
    DIRECTION OUTPUT ;
    USE SIGNAL ;
    PORT
      LAYER M4 ;
        RECT  64.716 49.728 64.8 49.752 ;
    END
  END res[83]
  PIN res[84]
    DIRECTION OUTPUT ;
    USE SIGNAL ;
    PORT
      LAYER M4 ;
        RECT  64.716 49.824 64.8 49.848 ;
    END
  END res[84]
  PIN res[85]
    DIRECTION OUTPUT ;
    USE SIGNAL ;
    PORT
      LAYER M4 ;
        RECT  64.716 49.968 64.8 49.992 ;
    END
  END res[85]
  PIN res[86]
    DIRECTION OUTPUT ;
    USE SIGNAL ;
    PORT
      LAYER M4 ;
        RECT  64.716 50.064 64.8 50.088 ;
    END
  END res[86]
  PIN res[87]
    DIRECTION OUTPUT ;
    USE SIGNAL ;
    PORT
      LAYER M4 ;
        RECT  64.716 50.208 64.8 50.232 ;
    END
  END res[87]
  PIN res[88]
    DIRECTION OUTPUT ;
    USE SIGNAL ;
    PORT
      LAYER M4 ;
        RECT  64.716 50.304 64.8 50.328 ;
    END
  END res[88]
  PIN res[89]
    DIRECTION OUTPUT ;
    USE SIGNAL ;
    PORT
      LAYER M4 ;
        RECT  64.716 50.448 64.8 50.472 ;
    END
  END res[89]
  PIN res[8]
    DIRECTION OUTPUT ;
    USE SIGNAL ;
    PORT
      LAYER M4 ;
        RECT  64.716 40.992 64.8 41.016 ;
    END
  END res[8]
  PIN res[90]
    DIRECTION OUTPUT ;
    USE SIGNAL ;
    PORT
      LAYER M4 ;
        RECT  64.716 50.544 64.8 50.568 ;
    END
  END res[90]
  PIN res[91]
    DIRECTION OUTPUT ;
    USE SIGNAL ;
    PORT
      LAYER M4 ;
        RECT  64.716 50.64 64.8 50.664 ;
    END
  END res[91]
  PIN res[92]
    DIRECTION OUTPUT ;
    USE SIGNAL ;
    PORT
      LAYER M4 ;
        RECT  64.716 50.784 64.8 50.808 ;
    END
  END res[92]
  PIN res[93]
    DIRECTION OUTPUT ;
    USE SIGNAL ;
    PORT
      LAYER M4 ;
        RECT  64.716 50.88 64.8 50.904 ;
    END
  END res[93]
  PIN res[94]
    DIRECTION OUTPUT ;
    USE SIGNAL ;
    PORT
      LAYER M4 ;
        RECT  64.716 51.024 64.8 51.048 ;
    END
  END res[94]
  PIN res[95]
    DIRECTION OUTPUT ;
    USE SIGNAL ;
    PORT
      LAYER M4 ;
        RECT  64.716 51.12 64.8 51.144 ;
    END
  END res[95]
  PIN res[96]
    DIRECTION OUTPUT ;
    USE SIGNAL ;
    PORT
      LAYER M4 ;
        RECT  64.716 51.264 64.8 51.288 ;
    END
  END res[96]
  PIN res[97]
    DIRECTION OUTPUT ;
    USE SIGNAL ;
    PORT
      LAYER M4 ;
        RECT  64.716 51.36 64.8 51.384 ;
    END
  END res[97]
  PIN res[98]
    DIRECTION OUTPUT ;
    USE SIGNAL ;
    PORT
      LAYER M4 ;
        RECT  64.716 51.504 64.8 51.528 ;
    END
  END res[98]
  PIN res[99]
    DIRECTION OUTPUT ;
    USE SIGNAL ;
    PORT
      LAYER M4 ;
        RECT  64.716 51.6 64.8 51.624 ;
    END
  END res[99]
  PIN res[9]
    DIRECTION OUTPUT ;
    USE SIGNAL ;
    PORT
      LAYER M4 ;
        RECT  64.716 41.088 64.8 41.112 ;
    END
  END res[9]
  PIN rst_n
    DIRECTION INPUT ;
    USE SIGNAL ;
    PORT
      LAYER M5 ;
        RECT  46.512 0 46.536 0.084 ;
    END
    PORT
      LAYER M5 ;
        RECT  46.512 0.016 46.536 1.763 ;
    END
  END rst_n
  PIN tk[0]
    DIRECTION INPUT ;
    USE SIGNAL ;
    PORT
      LAYER M4 ;
        RECT  0 10.032 0.084 10.056 ;
    END
  END tk[0]
  PIN tk[100]
    DIRECTION INPUT ;
    USE SIGNAL ;
    PORT
      LAYER M4 ;
        RECT  0 20.928 0.084 20.952 ;
    END
  END tk[100]
  PIN tk[101]
    DIRECTION INPUT ;
    USE SIGNAL ;
    PORT
      LAYER M4 ;
        RECT  0 21.024 0.084 21.048 ;
    END
  END tk[101]
  PIN tk[102]
    DIRECTION INPUT ;
    USE SIGNAL ;
    PORT
      LAYER M4 ;
        RECT  0 21.168 0.084 21.192 ;
    END
  END tk[102]
  PIN tk[103]
    DIRECTION INPUT ;
    USE SIGNAL ;
    PORT
      LAYER M4 ;
        RECT  0 21.264 0.084 21.288 ;
    END
  END tk[103]
  PIN tk[104]
    DIRECTION INPUT ;
    USE SIGNAL ;
    PORT
      LAYER M4 ;
        RECT  0 21.36 0.084 21.384 ;
    END
  END tk[104]
  PIN tk[105]
    DIRECTION INPUT ;
    USE SIGNAL ;
    PORT
      LAYER M4 ;
        RECT  0 21.456 0.084 21.48 ;
    END
  END tk[105]
  PIN tk[106]
    DIRECTION INPUT ;
    USE SIGNAL ;
    PORT
      LAYER M4 ;
        RECT  0 21.6 0.084 21.624 ;
    END
  END tk[106]
  PIN tk[107]
    DIRECTION INPUT ;
    USE SIGNAL ;
    PORT
      LAYER M4 ;
        RECT  0 21.696 0.084 21.72 ;
    END
  END tk[107]
  PIN tk[108]
    DIRECTION INPUT ;
    USE SIGNAL ;
    PORT
      LAYER M4 ;
        RECT  0 21.792 0.084 21.816 ;
    END
  END tk[108]
  PIN tk[109]
    DIRECTION INPUT ;
    USE SIGNAL ;
    PORT
      LAYER M4 ;
        RECT  0 21.888 0.084 21.912 ;
    END
  END tk[109]
  PIN tk[10]
    DIRECTION INPUT ;
    USE SIGNAL ;
    PORT
      LAYER M4 ;
        RECT  0 11.136 0.084 11.16 ;
    END
  END tk[10]
  PIN tk[110]
    DIRECTION INPUT ;
    USE SIGNAL ;
    PORT
      LAYER M4 ;
        RECT  0 22.032 0.084 22.056 ;
    END
  END tk[110]
  PIN tk[111]
    DIRECTION INPUT ;
    USE SIGNAL ;
    PORT
      LAYER M4 ;
        RECT  0 22.128 0.084 22.152 ;
    END
  END tk[111]
  PIN tk[112]
    DIRECTION INPUT ;
    USE SIGNAL ;
    PORT
      LAYER M4 ;
        RECT  0 22.224 0.084 22.248 ;
    END
  END tk[112]
  PIN tk[113]
    DIRECTION INPUT ;
    USE SIGNAL ;
    PORT
      LAYER M4 ;
        RECT  0 22.368 0.084 22.392 ;
    END
  END tk[113]
  PIN tk[114]
    DIRECTION INPUT ;
    USE SIGNAL ;
    PORT
      LAYER M4 ;
        RECT  0 22.464 0.084 22.488 ;
    END
  END tk[114]
  PIN tk[115]
    DIRECTION INPUT ;
    USE SIGNAL ;
    PORT
      LAYER M4 ;
        RECT  0 22.56 0.084 22.584 ;
    END
  END tk[115]
  PIN tk[116]
    DIRECTION INPUT ;
    USE SIGNAL ;
    PORT
      LAYER M4 ;
        RECT  0 22.656 0.084 22.68 ;
    END
  END tk[116]
  PIN tk[117]
    DIRECTION INPUT ;
    USE SIGNAL ;
    PORT
      LAYER M4 ;
        RECT  0 22.8 0.084 22.824 ;
    END
  END tk[117]
  PIN tk[118]
    DIRECTION INPUT ;
    USE SIGNAL ;
    PORT
      LAYER M4 ;
        RECT  0 22.896 0.084 22.92 ;
    END
  END tk[118]
  PIN tk[119]
    DIRECTION INPUT ;
    USE SIGNAL ;
    PORT
      LAYER M4 ;
        RECT  0 22.992 0.084 23.016 ;
    END
  END tk[119]
  PIN tk[11]
    DIRECTION INPUT ;
    USE SIGNAL ;
    PORT
      LAYER M4 ;
        RECT  0 11.232 0.084 11.256 ;
    END
  END tk[11]
  PIN tk[120]
    DIRECTION INPUT ;
    USE SIGNAL ;
    PORT
      LAYER M4 ;
        RECT  0 23.088 0.084 23.112 ;
    END
  END tk[120]
  PIN tk[121]
    DIRECTION INPUT ;
    USE SIGNAL ;
    PORT
      LAYER M4 ;
        RECT  0 23.232 0.084 23.256 ;
    END
  END tk[121]
  PIN tk[122]
    DIRECTION INPUT ;
    USE SIGNAL ;
    PORT
      LAYER M4 ;
        RECT  0 23.328 0.084 23.352 ;
    END
  END tk[122]
  PIN tk[123]
    DIRECTION INPUT ;
    USE SIGNAL ;
    PORT
      LAYER M4 ;
        RECT  0 23.424 0.084 23.448 ;
    END
  END tk[123]
  PIN tk[124]
    DIRECTION INPUT ;
    USE SIGNAL ;
    PORT
      LAYER M4 ;
        RECT  0 23.52 0.084 23.544 ;
    END
  END tk[124]
  PIN tk[125]
    DIRECTION INPUT ;
    USE SIGNAL ;
    PORT
      LAYER M4 ;
        RECT  0 23.664 0.084 23.688 ;
    END
  END tk[125]
  PIN tk[126]
    DIRECTION INPUT ;
    USE SIGNAL ;
    PORT
      LAYER M4 ;
        RECT  0 23.76 0.084 23.784 ;
    END
  END tk[126]
  PIN tk[127]
    DIRECTION INPUT ;
    USE SIGNAL ;
    PORT
      LAYER M4 ;
        RECT  0 23.856 0.084 23.88 ;
    END
  END tk[127]
  PIN tk[128]
    DIRECTION INPUT ;
    USE SIGNAL ;
    PORT
      LAYER M4 ;
        RECT  0 24 0.084 24.024 ;
    END
  END tk[128]
  PIN tk[129]
    DIRECTION INPUT ;
    USE SIGNAL ;
    PORT
      LAYER M4 ;
        RECT  0 24.096 0.084 24.12 ;
    END
  END tk[129]
  PIN tk[12]
    DIRECTION INPUT ;
    USE SIGNAL ;
    PORT
      LAYER M4 ;
        RECT  0 11.328 0.084 11.352 ;
    END
  END tk[12]
  PIN tk[130]
    DIRECTION INPUT ;
    USE SIGNAL ;
    PORT
      LAYER M4 ;
        RECT  0 24.192 0.084 24.216 ;
    END
  END tk[130]
  PIN tk[131]
    DIRECTION INPUT ;
    USE SIGNAL ;
    PORT
      LAYER M4 ;
        RECT  0 24.288 0.084 24.312 ;
    END
  END tk[131]
  PIN tk[132]
    DIRECTION INPUT ;
    USE SIGNAL ;
    PORT
      LAYER M4 ;
        RECT  0 24.432 0.084 24.456 ;
    END
  END tk[132]
  PIN tk[133]
    DIRECTION INPUT ;
    USE SIGNAL ;
    PORT
      LAYER M4 ;
        RECT  0 24.528 0.084 24.552 ;
    END
  END tk[133]
  PIN tk[134]
    DIRECTION INPUT ;
    USE SIGNAL ;
    PORT
      LAYER M4 ;
        RECT  0 24.624 0.084 24.648 ;
    END
  END tk[134]
  PIN tk[135]
    DIRECTION INPUT ;
    USE SIGNAL ;
    PORT
      LAYER M4 ;
        RECT  0 24.72 0.084 24.744 ;
    END
  END tk[135]
  PIN tk[136]
    DIRECTION INPUT ;
    USE SIGNAL ;
    PORT
      LAYER M4 ;
        RECT  0 24.864 0.084 24.888 ;
    END
  END tk[136]
  PIN tk[137]
    DIRECTION INPUT ;
    USE SIGNAL ;
    PORT
      LAYER M4 ;
        RECT  0 24.96 0.084 24.984 ;
    END
  END tk[137]
  PIN tk[138]
    DIRECTION INPUT ;
    USE SIGNAL ;
    PORT
      LAYER M4 ;
        RECT  0 25.056 0.084 25.08 ;
    END
  END tk[138]
  PIN tk[139]
    DIRECTION INPUT ;
    USE SIGNAL ;
    PORT
      LAYER M4 ;
        RECT  0 25.2 0.084 25.224 ;
    END
  END tk[139]
  PIN tk[13]
    DIRECTION INPUT ;
    USE SIGNAL ;
    PORT
      LAYER M4 ;
        RECT  0 11.472 0.084 11.496 ;
    END
  END tk[13]
  PIN tk[140]
    DIRECTION INPUT ;
    USE SIGNAL ;
    PORT
      LAYER M4 ;
        RECT  0 25.296 0.084 25.32 ;
    END
  END tk[140]
  PIN tk[141]
    DIRECTION INPUT ;
    USE SIGNAL ;
    PORT
      LAYER M4 ;
        RECT  0 25.392 0.084 25.416 ;
    END
  END tk[141]
  PIN tk[142]
    DIRECTION INPUT ;
    USE SIGNAL ;
    PORT
      LAYER M4 ;
        RECT  0 25.488 0.084 25.512 ;
    END
  END tk[142]
  PIN tk[143]
    DIRECTION INPUT ;
    USE SIGNAL ;
    PORT
      LAYER M4 ;
        RECT  0 25.632 0.084 25.656 ;
    END
  END tk[143]
  PIN tk[144]
    DIRECTION INPUT ;
    USE SIGNAL ;
    PORT
      LAYER M4 ;
        RECT  0 25.728 0.084 25.752 ;
    END
  END tk[144]
  PIN tk[145]
    DIRECTION INPUT ;
    USE SIGNAL ;
    PORT
      LAYER M4 ;
        RECT  0 25.824 0.084 25.848 ;
    END
  END tk[145]
  PIN tk[146]
    DIRECTION INPUT ;
    USE SIGNAL ;
    PORT
      LAYER M4 ;
        RECT  0 25.92 0.084 25.944 ;
    END
  END tk[146]
  PIN tk[147]
    DIRECTION INPUT ;
    USE SIGNAL ;
    PORT
      LAYER M4 ;
        RECT  0 26.064 0.084 26.088 ;
    END
  END tk[147]
  PIN tk[148]
    DIRECTION INPUT ;
    USE SIGNAL ;
    PORT
      LAYER M4 ;
        RECT  0 26.16 0.084 26.184 ;
    END
  END tk[148]
  PIN tk[149]
    DIRECTION INPUT ;
    USE SIGNAL ;
    PORT
      LAYER M4 ;
        RECT  0 26.256 0.084 26.28 ;
    END
  END tk[149]
  PIN tk[14]
    DIRECTION INPUT ;
    USE SIGNAL ;
    PORT
      LAYER M4 ;
        RECT  0 11.568 0.084 11.592 ;
    END
  END tk[14]
  PIN tk[150]
    DIRECTION INPUT ;
    USE SIGNAL ;
    PORT
      LAYER M4 ;
        RECT  0 26.352 0.084 26.376 ;
    END
  END tk[150]
  PIN tk[151]
    DIRECTION INPUT ;
    USE SIGNAL ;
    PORT
      LAYER M4 ;
        RECT  0 26.496 0.084 26.52 ;
    END
  END tk[151]
  PIN tk[152]
    DIRECTION INPUT ;
    USE SIGNAL ;
    PORT
      LAYER M4 ;
        RECT  0 26.592 0.084 26.616 ;
    END
  END tk[152]
  PIN tk[153]
    DIRECTION INPUT ;
    USE SIGNAL ;
    PORT
      LAYER M4 ;
        RECT  0 26.688 0.084 26.712 ;
    END
  END tk[153]
  PIN tk[154]
    DIRECTION INPUT ;
    USE SIGNAL ;
    PORT
      LAYER M4 ;
        RECT  0 26.832 0.084 26.856 ;
    END
  END tk[154]
  PIN tk[155]
    DIRECTION INPUT ;
    USE SIGNAL ;
    PORT
      LAYER M4 ;
        RECT  0 26.928 0.084 26.952 ;
    END
  END tk[155]
  PIN tk[156]
    DIRECTION INPUT ;
    USE SIGNAL ;
    PORT
      LAYER M4 ;
        RECT  0 27.024 0.084 27.048 ;
    END
  END tk[156]
  PIN tk[157]
    DIRECTION INPUT ;
    USE SIGNAL ;
    PORT
      LAYER M4 ;
        RECT  0 27.12 0.084 27.144 ;
    END
  END tk[157]
  PIN tk[158]
    DIRECTION INPUT ;
    USE SIGNAL ;
    PORT
      LAYER M4 ;
        RECT  0 27.264 0.084 27.288 ;
    END
  END tk[158]
  PIN tk[159]
    DIRECTION INPUT ;
    USE SIGNAL ;
    PORT
      LAYER M4 ;
        RECT  0 27.36 0.084 27.384 ;
    END
  END tk[159]
  PIN tk[15]
    DIRECTION INPUT ;
    USE SIGNAL ;
    PORT
      LAYER M4 ;
        RECT  0 11.664 0.084 11.688 ;
    END
  END tk[15]
  PIN tk[160]
    DIRECTION INPUT ;
    USE SIGNAL ;
    PORT
      LAYER M4 ;
        RECT  0 27.456 0.084 27.48 ;
    END
  END tk[160]
  PIN tk[161]
    DIRECTION INPUT ;
    USE SIGNAL ;
    PORT
      LAYER M4 ;
        RECT  0 27.552 0.084 27.576 ;
    END
  END tk[161]
  PIN tk[162]
    DIRECTION INPUT ;
    USE SIGNAL ;
    PORT
      LAYER M4 ;
        RECT  0 27.696 0.084 27.72 ;
    END
  END tk[162]
  PIN tk[163]
    DIRECTION INPUT ;
    USE SIGNAL ;
    PORT
      LAYER M4 ;
        RECT  0 27.792 0.084 27.816 ;
    END
  END tk[163]
  PIN tk[164]
    DIRECTION INPUT ;
    USE SIGNAL ;
    PORT
      LAYER M4 ;
        RECT  0 27.888 0.084 27.912 ;
    END
  END tk[164]
  PIN tk[165]
    DIRECTION INPUT ;
    USE SIGNAL ;
    PORT
      LAYER M4 ;
        RECT  0 27.984 0.084 28.008 ;
    END
  END tk[165]
  PIN tk[166]
    DIRECTION INPUT ;
    USE SIGNAL ;
    PORT
      LAYER M4 ;
        RECT  0 28.128 0.084 28.152 ;
    END
  END tk[166]
  PIN tk[167]
    DIRECTION INPUT ;
    USE SIGNAL ;
    PORT
      LAYER M4 ;
        RECT  0 28.224 0.084 28.248 ;
    END
  END tk[167]
  PIN tk[168]
    DIRECTION INPUT ;
    USE SIGNAL ;
    PORT
      LAYER M4 ;
        RECT  0 28.32 0.084 28.344 ;
    END
  END tk[168]
  PIN tk[169]
    DIRECTION INPUT ;
    USE SIGNAL ;
    PORT
      LAYER M4 ;
        RECT  0 28.464 0.084 28.488 ;
    END
  END tk[169]
  PIN tk[16]
    DIRECTION INPUT ;
    USE SIGNAL ;
    PORT
      LAYER M4 ;
        RECT  0 11.808 0.084 11.832 ;
    END
  END tk[16]
  PIN tk[170]
    DIRECTION INPUT ;
    USE SIGNAL ;
    PORT
      LAYER M4 ;
        RECT  0 28.56 0.084 28.584 ;
    END
  END tk[170]
  PIN tk[171]
    DIRECTION INPUT ;
    USE SIGNAL ;
    PORT
      LAYER M4 ;
        RECT  0 28.656 0.084 28.68 ;
    END
  END tk[171]
  PIN tk[172]
    DIRECTION INPUT ;
    USE SIGNAL ;
    PORT
      LAYER M4 ;
        RECT  0 28.752 0.084 28.776 ;
    END
  END tk[172]
  PIN tk[173]
    DIRECTION INPUT ;
    USE SIGNAL ;
    PORT
      LAYER M4 ;
        RECT  0 28.896 0.084 28.92 ;
    END
  END tk[173]
  PIN tk[174]
    DIRECTION INPUT ;
    USE SIGNAL ;
    PORT
      LAYER M4 ;
        RECT  0 28.992 0.084 29.016 ;
    END
  END tk[174]
  PIN tk[175]
    DIRECTION INPUT ;
    USE SIGNAL ;
    PORT
      LAYER M4 ;
        RECT  0 29.088 0.084 29.112 ;
    END
  END tk[175]
  PIN tk[176]
    DIRECTION INPUT ;
    USE SIGNAL ;
    PORT
      LAYER M4 ;
        RECT  0 29.184 0.084 29.208 ;
    END
  END tk[176]
  PIN tk[177]
    DIRECTION INPUT ;
    USE SIGNAL ;
    PORT
      LAYER M4 ;
        RECT  0 29.328 0.084 29.352 ;
    END
  END tk[177]
  PIN tk[178]
    DIRECTION INPUT ;
    USE SIGNAL ;
    PORT
      LAYER M4 ;
        RECT  0 29.424 0.084 29.448 ;
    END
  END tk[178]
  PIN tk[179]
    DIRECTION INPUT ;
    USE SIGNAL ;
    PORT
      LAYER M4 ;
        RECT  0 29.52 0.084 29.544 ;
    END
  END tk[179]
  PIN tk[17]
    DIRECTION INPUT ;
    USE SIGNAL ;
    PORT
      LAYER M4 ;
        RECT  0 11.904 0.084 11.928 ;
    END
  END tk[17]
  PIN tk[180]
    DIRECTION INPUT ;
    USE SIGNAL ;
    PORT
      LAYER M4 ;
        RECT  0 29.616 0.084 29.64 ;
    END
  END tk[180]
  PIN tk[181]
    DIRECTION INPUT ;
    USE SIGNAL ;
    PORT
      LAYER M4 ;
        RECT  0 29.76 0.084 29.784 ;
    END
  END tk[181]
  PIN tk[182]
    DIRECTION INPUT ;
    USE SIGNAL ;
    PORT
      LAYER M4 ;
        RECT  0 29.856 0.084 29.88 ;
    END
  END tk[182]
  PIN tk[183]
    DIRECTION INPUT ;
    USE SIGNAL ;
    PORT
      LAYER M4 ;
        RECT  0 29.952 0.084 29.976 ;
    END
  END tk[183]
  PIN tk[184]
    DIRECTION INPUT ;
    USE SIGNAL ;
    PORT
      LAYER M4 ;
        RECT  0 30.096 0.084 30.12 ;
    END
  END tk[184]
  PIN tk[185]
    DIRECTION INPUT ;
    USE SIGNAL ;
    PORT
      LAYER M4 ;
        RECT  0 30.192 0.084 30.216 ;
    END
  END tk[185]
  PIN tk[186]
    DIRECTION INPUT ;
    USE SIGNAL ;
    PORT
      LAYER M4 ;
        RECT  0 30.288 0.084 30.312 ;
    END
  END tk[186]
  PIN tk[187]
    DIRECTION INPUT ;
    USE SIGNAL ;
    PORT
      LAYER M4 ;
        RECT  0 30.384 0.084 30.408 ;
    END
  END tk[187]
  PIN tk[188]
    DIRECTION INPUT ;
    USE SIGNAL ;
    PORT
      LAYER M4 ;
        RECT  0 30.528 0.084 30.552 ;
    END
  END tk[188]
  PIN tk[189]
    DIRECTION INPUT ;
    USE SIGNAL ;
    PORT
      LAYER M4 ;
        RECT  0 30.624 0.084 30.648 ;
    END
  END tk[189]
  PIN tk[18]
    DIRECTION INPUT ;
    USE SIGNAL ;
    PORT
      LAYER M4 ;
        RECT  0 12 0.084 12.024 ;
    END
  END tk[18]
  PIN tk[190]
    DIRECTION INPUT ;
    USE SIGNAL ;
    PORT
      LAYER M4 ;
        RECT  0 30.72 0.084 30.744 ;
    END
  END tk[190]
  PIN tk[191]
    DIRECTION INPUT ;
    USE SIGNAL ;
    PORT
      LAYER M4 ;
        RECT  0 30.816 0.084 30.84 ;
    END
  END tk[191]
  PIN tk[192]
    DIRECTION INPUT ;
    USE SIGNAL ;
    PORT
      LAYER M4 ;
        RECT  0 30.96 0.084 30.984 ;
    END
  END tk[192]
  PIN tk[193]
    DIRECTION INPUT ;
    USE SIGNAL ;
    PORT
      LAYER M4 ;
        RECT  0 31.056 0.084 31.08 ;
    END
  END tk[193]
  PIN tk[194]
    DIRECTION INPUT ;
    USE SIGNAL ;
    PORT
      LAYER M4 ;
        RECT  0 31.152 0.084 31.176 ;
    END
  END tk[194]
  PIN tk[195]
    DIRECTION INPUT ;
    USE SIGNAL ;
    PORT
      LAYER M4 ;
        RECT  0 31.296 0.084 31.32 ;
    END
  END tk[195]
  PIN tk[196]
    DIRECTION INPUT ;
    USE SIGNAL ;
    PORT
      LAYER M4 ;
        RECT  0 31.392 0.084 31.416 ;
    END
  END tk[196]
  PIN tk[197]
    DIRECTION INPUT ;
    USE SIGNAL ;
    PORT
      LAYER M4 ;
        RECT  0 31.488 0.084 31.512 ;
    END
  END tk[197]
  PIN tk[198]
    DIRECTION INPUT ;
    USE SIGNAL ;
    PORT
      LAYER M4 ;
        RECT  0 31.584 0.084 31.608 ;
    END
  END tk[198]
  PIN tk[199]
    DIRECTION INPUT ;
    USE SIGNAL ;
    PORT
      LAYER M4 ;
        RECT  0 31.728 0.084 31.752 ;
    END
  END tk[199]
  PIN tk[19]
    DIRECTION INPUT ;
    USE SIGNAL ;
    PORT
      LAYER M4 ;
        RECT  0 12.096 0.084 12.12 ;
    END
  END tk[19]
  PIN tk[1]
    DIRECTION INPUT ;
    USE SIGNAL ;
    PORT
      LAYER M4 ;
        RECT  0 10.128 0.084 10.152 ;
    END
  END tk[1]
  PIN tk[200]
    DIRECTION INPUT ;
    USE SIGNAL ;
    PORT
      LAYER M4 ;
        RECT  0 31.824 0.084 31.848 ;
    END
  END tk[200]
  PIN tk[201]
    DIRECTION INPUT ;
    USE SIGNAL ;
    PORT
      LAYER M4 ;
        RECT  0 31.92 0.084 31.944 ;
    END
  END tk[201]
  PIN tk[202]
    DIRECTION INPUT ;
    USE SIGNAL ;
    PORT
      LAYER M4 ;
        RECT  0 32.016 0.084 32.04 ;
    END
  END tk[202]
  PIN tk[203]
    DIRECTION INPUT ;
    USE SIGNAL ;
    PORT
      LAYER M4 ;
        RECT  0 32.16 0.084 32.184 ;
    END
  END tk[203]
  PIN tk[204]
    DIRECTION INPUT ;
    USE SIGNAL ;
    PORT
      LAYER M4 ;
        RECT  0 32.256 0.084 32.28 ;
    END
  END tk[204]
  PIN tk[205]
    DIRECTION INPUT ;
    USE SIGNAL ;
    PORT
      LAYER M4 ;
        RECT  0 32.352 0.084 32.376 ;
    END
  END tk[205]
  PIN tk[206]
    DIRECTION INPUT ;
    USE SIGNAL ;
    PORT
      LAYER M4 ;
        RECT  0 32.448 0.084 32.472 ;
    END
  END tk[206]
  PIN tk[207]
    DIRECTION INPUT ;
    USE SIGNAL ;
    PORT
      LAYER M4 ;
        RECT  0 32.592 0.084 32.616 ;
    END
  END tk[207]
  PIN tk[208]
    DIRECTION INPUT ;
    USE SIGNAL ;
    PORT
      LAYER M4 ;
        RECT  0 32.688 0.084 32.712 ;
    END
  END tk[208]
  PIN tk[209]
    DIRECTION INPUT ;
    USE SIGNAL ;
    PORT
      LAYER M4 ;
        RECT  0 32.784 0.084 32.808 ;
    END
  END tk[209]
  PIN tk[20]
    DIRECTION INPUT ;
    USE SIGNAL ;
    PORT
      LAYER M4 ;
        RECT  0 12.24 0.084 12.264 ;
    END
  END tk[20]
  PIN tk[210]
    DIRECTION INPUT ;
    USE SIGNAL ;
    PORT
      LAYER M4 ;
        RECT  0 32.928 0.084 32.952 ;
    END
  END tk[210]
  PIN tk[211]
    DIRECTION INPUT ;
    USE SIGNAL ;
    PORT
      LAYER M4 ;
        RECT  0 33.024 0.084 33.048 ;
    END
  END tk[211]
  PIN tk[212]
    DIRECTION INPUT ;
    USE SIGNAL ;
    PORT
      LAYER M4 ;
        RECT  0 33.12 0.084 33.144 ;
    END
  END tk[212]
  PIN tk[213]
    DIRECTION INPUT ;
    USE SIGNAL ;
    PORT
      LAYER M4 ;
        RECT  0 33.216 0.084 33.24 ;
    END
  END tk[213]
  PIN tk[214]
    DIRECTION INPUT ;
    USE SIGNAL ;
    PORT
      LAYER M4 ;
        RECT  0 33.36 0.084 33.384 ;
    END
  END tk[214]
  PIN tk[215]
    DIRECTION INPUT ;
    USE SIGNAL ;
    PORT
      LAYER M4 ;
        RECT  0 33.456 0.084 33.48 ;
    END
  END tk[215]
  PIN tk[216]
    DIRECTION INPUT ;
    USE SIGNAL ;
    PORT
      LAYER M4 ;
        RECT  0 33.552 0.084 33.576 ;
    END
  END tk[216]
  PIN tk[217]
    DIRECTION INPUT ;
    USE SIGNAL ;
    PORT
      LAYER M4 ;
        RECT  0 33.648 0.084 33.672 ;
    END
  END tk[217]
  PIN tk[218]
    DIRECTION INPUT ;
    USE SIGNAL ;
    PORT
      LAYER M4 ;
        RECT  0 33.792 0.084 33.816 ;
    END
  END tk[218]
  PIN tk[219]
    DIRECTION INPUT ;
    USE SIGNAL ;
    PORT
      LAYER M4 ;
        RECT  0 33.888 0.084 33.912 ;
    END
  END tk[219]
  PIN tk[21]
    DIRECTION INPUT ;
    USE SIGNAL ;
    PORT
      LAYER M4 ;
        RECT  0 12.336 0.084 12.36 ;
    END
  END tk[21]
  PIN tk[220]
    DIRECTION INPUT ;
    USE SIGNAL ;
    PORT
      LAYER M4 ;
        RECT  0 33.984 0.084 34.008 ;
    END
  END tk[220]
  PIN tk[221]
    DIRECTION INPUT ;
    USE SIGNAL ;
    PORT
      LAYER M4 ;
        RECT  0 34.08 0.084 34.104 ;
    END
  END tk[221]
  PIN tk[222]
    DIRECTION INPUT ;
    USE SIGNAL ;
    PORT
      LAYER M4 ;
        RECT  0 34.224 0.084 34.248 ;
    END
  END tk[222]
  PIN tk[223]
    DIRECTION INPUT ;
    USE SIGNAL ;
    PORT
      LAYER M4 ;
        RECT  0 34.32 0.084 34.344 ;
    END
  END tk[223]
  PIN tk[224]
    DIRECTION INPUT ;
    USE SIGNAL ;
    PORT
      LAYER M4 ;
        RECT  0 34.416 0.084 34.44 ;
    END
  END tk[224]
  PIN tk[225]
    DIRECTION INPUT ;
    USE SIGNAL ;
    PORT
      LAYER M4 ;
        RECT  0 34.56 0.084 34.584 ;
    END
  END tk[225]
  PIN tk[226]
    DIRECTION INPUT ;
    USE SIGNAL ;
    PORT
      LAYER M4 ;
        RECT  0 34.656 0.084 34.68 ;
    END
  END tk[226]
  PIN tk[227]
    DIRECTION INPUT ;
    USE SIGNAL ;
    PORT
      LAYER M4 ;
        RECT  0 34.752 0.084 34.776 ;
    END
  END tk[227]
  PIN tk[228]
    DIRECTION INPUT ;
    USE SIGNAL ;
    PORT
      LAYER M4 ;
        RECT  0 34.848 0.084 34.872 ;
    END
  END tk[228]
  PIN tk[229]
    DIRECTION INPUT ;
    USE SIGNAL ;
    PORT
      LAYER M4 ;
        RECT  0 34.992 0.084 35.016 ;
    END
  END tk[229]
  PIN tk[22]
    DIRECTION INPUT ;
    USE SIGNAL ;
    PORT
      LAYER M4 ;
        RECT  0 12.432 0.084 12.456 ;
    END
  END tk[22]
  PIN tk[230]
    DIRECTION INPUT ;
    USE SIGNAL ;
    PORT
      LAYER M4 ;
        RECT  0 35.088 0.084 35.112 ;
    END
  END tk[230]
  PIN tk[231]
    DIRECTION INPUT ;
    USE SIGNAL ;
    PORT
      LAYER M4 ;
        RECT  0 35.184 0.084 35.208 ;
    END
  END tk[231]
  PIN tk[232]
    DIRECTION INPUT ;
    USE SIGNAL ;
    PORT
      LAYER M4 ;
        RECT  0 35.28 0.084 35.304 ;
    END
  END tk[232]
  PIN tk[233]
    DIRECTION INPUT ;
    USE SIGNAL ;
    PORT
      LAYER M4 ;
        RECT  0 35.424 0.084 35.448 ;
    END
  END tk[233]
  PIN tk[234]
    DIRECTION INPUT ;
    USE SIGNAL ;
    PORT
      LAYER M4 ;
        RECT  0 35.52 0.084 35.544 ;
    END
  END tk[234]
  PIN tk[235]
    DIRECTION INPUT ;
    USE SIGNAL ;
    PORT
      LAYER M4 ;
        RECT  0 35.616 0.084 35.64 ;
    END
  END tk[235]
  PIN tk[236]
    DIRECTION INPUT ;
    USE SIGNAL ;
    PORT
      LAYER M4 ;
        RECT  0 35.76 0.084 35.784 ;
    END
  END tk[236]
  PIN tk[237]
    DIRECTION INPUT ;
    USE SIGNAL ;
    PORT
      LAYER M4 ;
        RECT  0 35.856 0.084 35.88 ;
    END
  END tk[237]
  PIN tk[238]
    DIRECTION INPUT ;
    USE SIGNAL ;
    PORT
      LAYER M4 ;
        RECT  0 35.952 0.084 35.976 ;
    END
  END tk[238]
  PIN tk[239]
    DIRECTION INPUT ;
    USE SIGNAL ;
    PORT
      LAYER M4 ;
        RECT  0 36.048 0.084 36.072 ;
    END
  END tk[239]
  PIN tk[23]
    DIRECTION INPUT ;
    USE SIGNAL ;
    PORT
      LAYER M4 ;
        RECT  0 12.528 0.084 12.552 ;
    END
  END tk[23]
  PIN tk[240]
    DIRECTION INPUT ;
    USE SIGNAL ;
    PORT
      LAYER M4 ;
        RECT  0 36.192 0.084 36.216 ;
    END
  END tk[240]
  PIN tk[241]
    DIRECTION INPUT ;
    USE SIGNAL ;
    PORT
      LAYER M4 ;
        RECT  0 36.288 0.084 36.312 ;
    END
  END tk[241]
  PIN tk[242]
    DIRECTION INPUT ;
    USE SIGNAL ;
    PORT
      LAYER M4 ;
        RECT  0 36.384 0.084 36.408 ;
    END
  END tk[242]
  PIN tk[243]
    DIRECTION INPUT ;
    USE SIGNAL ;
    PORT
      LAYER M4 ;
        RECT  0 36.48 0.084 36.504 ;
    END
  END tk[243]
  PIN tk[244]
    DIRECTION INPUT ;
    USE SIGNAL ;
    PORT
      LAYER M4 ;
        RECT  0 36.624 0.084 36.648 ;
    END
  END tk[244]
  PIN tk[245]
    DIRECTION INPUT ;
    USE SIGNAL ;
    PORT
      LAYER M4 ;
        RECT  0 36.72 0.084 36.744 ;
    END
  END tk[245]
  PIN tk[246]
    DIRECTION INPUT ;
    USE SIGNAL ;
    PORT
      LAYER M4 ;
        RECT  0 36.816 0.084 36.84 ;
    END
  END tk[246]
  PIN tk[247]
    DIRECTION INPUT ;
    USE SIGNAL ;
    PORT
      LAYER M4 ;
        RECT  0 36.912 0.084 36.936 ;
    END
  END tk[247]
  PIN tk[248]
    DIRECTION INPUT ;
    USE SIGNAL ;
    PORT
      LAYER M4 ;
        RECT  0 37.056 0.084 37.08 ;
    END
  END tk[248]
  PIN tk[249]
    DIRECTION INPUT ;
    USE SIGNAL ;
    PORT
      LAYER M4 ;
        RECT  0 37.152 0.084 37.176 ;
    END
  END tk[249]
  PIN tk[24]
    DIRECTION INPUT ;
    USE SIGNAL ;
    PORT
      LAYER M4 ;
        RECT  0 12.672 0.084 12.696 ;
    END
  END tk[24]
  PIN tk[250]
    DIRECTION INPUT ;
    USE SIGNAL ;
    PORT
      LAYER M4 ;
        RECT  0 37.248 0.084 37.272 ;
    END
  END tk[250]
  PIN tk[251]
    DIRECTION INPUT ;
    USE SIGNAL ;
    PORT
      LAYER M4 ;
        RECT  0 37.392 0.084 37.416 ;
    END
  END tk[251]
  PIN tk[252]
    DIRECTION INPUT ;
    USE SIGNAL ;
    PORT
      LAYER M4 ;
        RECT  0 37.488 0.084 37.512 ;
    END
  END tk[252]
  PIN tk[253]
    DIRECTION INPUT ;
    USE SIGNAL ;
    PORT
      LAYER M4 ;
        RECT  0 37.584 0.084 37.608 ;
    END
  END tk[253]
  PIN tk[254]
    DIRECTION INPUT ;
    USE SIGNAL ;
    PORT
      LAYER M4 ;
        RECT  0 37.68 0.084 37.704 ;
    END
  END tk[254]
  PIN tk[255]
    DIRECTION INPUT ;
    USE SIGNAL ;
    PORT
      LAYER M4 ;
        RECT  0 37.824 0.084 37.848 ;
    END
  END tk[255]
  PIN tk[256]
    DIRECTION INPUT ;
    USE SIGNAL ;
    PORT
      LAYER M4 ;
        RECT  0 37.92 0.084 37.944 ;
    END
  END tk[256]
  PIN tk[257]
    DIRECTION INPUT ;
    USE SIGNAL ;
    PORT
      LAYER M4 ;
        RECT  0 38.016 0.084 38.04 ;
    END
  END tk[257]
  PIN tk[258]
    DIRECTION INPUT ;
    USE SIGNAL ;
    PORT
      LAYER M4 ;
        RECT  0 38.112 0.084 38.136 ;
    END
  END tk[258]
  PIN tk[259]
    DIRECTION INPUT ;
    USE SIGNAL ;
    PORT
      LAYER M4 ;
        RECT  0 38.256 0.084 38.28 ;
    END
  END tk[259]
  PIN tk[25]
    DIRECTION INPUT ;
    USE SIGNAL ;
    PORT
      LAYER M4 ;
        RECT  0 12.768 0.084 12.792 ;
    END
  END tk[25]
  PIN tk[260]
    DIRECTION INPUT ;
    USE SIGNAL ;
    PORT
      LAYER M4 ;
        RECT  0 38.352 0.084 38.376 ;
    END
  END tk[260]
  PIN tk[261]
    DIRECTION INPUT ;
    USE SIGNAL ;
    PORT
      LAYER M4 ;
        RECT  0 38.448 0.084 38.472 ;
    END
  END tk[261]
  PIN tk[262]
    DIRECTION INPUT ;
    USE SIGNAL ;
    PORT
      LAYER M4 ;
        RECT  0 38.544 0.084 38.568 ;
    END
  END tk[262]
  PIN tk[263]
    DIRECTION INPUT ;
    USE SIGNAL ;
    PORT
      LAYER M4 ;
        RECT  0 38.688 0.084 38.712 ;
    END
  END tk[263]
  PIN tk[264]
    DIRECTION INPUT ;
    USE SIGNAL ;
    PORT
      LAYER M4 ;
        RECT  0 38.784 0.084 38.808 ;
    END
  END tk[264]
  PIN tk[265]
    DIRECTION INPUT ;
    USE SIGNAL ;
    PORT
      LAYER M4 ;
        RECT  0 38.88 0.084 38.904 ;
    END
  END tk[265]
  PIN tk[266]
    DIRECTION INPUT ;
    USE SIGNAL ;
    PORT
      LAYER M4 ;
        RECT  0 39.024 0.084 39.048 ;
    END
  END tk[266]
  PIN tk[267]
    DIRECTION INPUT ;
    USE SIGNAL ;
    PORT
      LAYER M4 ;
        RECT  0 39.12 0.084 39.144 ;
    END
  END tk[267]
  PIN tk[268]
    DIRECTION INPUT ;
    USE SIGNAL ;
    PORT
      LAYER M4 ;
        RECT  0 39.216 0.084 39.24 ;
    END
  END tk[268]
  PIN tk[269]
    DIRECTION INPUT ;
    USE SIGNAL ;
    PORT
      LAYER M4 ;
        RECT  0 39.312 0.084 39.336 ;
    END
  END tk[269]
  PIN tk[26]
    DIRECTION INPUT ;
    USE SIGNAL ;
    PORT
      LAYER M4 ;
        RECT  0 12.864 0.084 12.888 ;
    END
  END tk[26]
  PIN tk[270]
    DIRECTION INPUT ;
    USE SIGNAL ;
    PORT
      LAYER M4 ;
        RECT  0 39.456 0.084 39.48 ;
    END
  END tk[270]
  PIN tk[271]
    DIRECTION INPUT ;
    USE SIGNAL ;
    PORT
      LAYER M4 ;
        RECT  0 39.552 0.084 39.576 ;
    END
  END tk[271]
  PIN tk[272]
    DIRECTION INPUT ;
    USE SIGNAL ;
    PORT
      LAYER M4 ;
        RECT  0 39.648 0.084 39.672 ;
    END
  END tk[272]
  PIN tk[273]
    DIRECTION INPUT ;
    USE SIGNAL ;
    PORT
      LAYER M4 ;
        RECT  0 39.744 0.084 39.768 ;
    END
  END tk[273]
  PIN tk[274]
    DIRECTION INPUT ;
    USE SIGNAL ;
    PORT
      LAYER M4 ;
        RECT  0 39.888 0.084 39.912 ;
    END
  END tk[274]
  PIN tk[275]
    DIRECTION INPUT ;
    USE SIGNAL ;
    PORT
      LAYER M4 ;
        RECT  0 39.984 0.084 40.008 ;
    END
  END tk[275]
  PIN tk[276]
    DIRECTION INPUT ;
    USE SIGNAL ;
    PORT
      LAYER M4 ;
        RECT  0 40.08 0.084 40.104 ;
    END
  END tk[276]
  PIN tk[277]
    DIRECTION INPUT ;
    USE SIGNAL ;
    PORT
      LAYER M4 ;
        RECT  0 40.224 0.084 40.248 ;
    END
  END tk[277]
  PIN tk[278]
    DIRECTION INPUT ;
    USE SIGNAL ;
    PORT
      LAYER M4 ;
        RECT  0 40.32 0.084 40.344 ;
    END
  END tk[278]
  PIN tk[279]
    DIRECTION INPUT ;
    USE SIGNAL ;
    PORT
      LAYER M4 ;
        RECT  0 40.416 0.084 40.44 ;
    END
  END tk[279]
  PIN tk[27]
    DIRECTION INPUT ;
    USE SIGNAL ;
    PORT
      LAYER M4 ;
        RECT  0 12.96 0.084 12.984 ;
    END
  END tk[27]
  PIN tk[280]
    DIRECTION INPUT ;
    USE SIGNAL ;
    PORT
      LAYER M4 ;
        RECT  0 40.512 0.084 40.536 ;
    END
  END tk[280]
  PIN tk[281]
    DIRECTION INPUT ;
    USE SIGNAL ;
    PORT
      LAYER M4 ;
        RECT  0 40.656 0.084 40.68 ;
    END
  END tk[281]
  PIN tk[282]
    DIRECTION INPUT ;
    USE SIGNAL ;
    PORT
      LAYER M4 ;
        RECT  0 40.752 0.084 40.776 ;
    END
  END tk[282]
  PIN tk[283]
    DIRECTION INPUT ;
    USE SIGNAL ;
    PORT
      LAYER M4 ;
        RECT  0 40.848 0.084 40.872 ;
    END
  END tk[283]
  PIN tk[284]
    DIRECTION INPUT ;
    USE SIGNAL ;
    PORT
      LAYER M4 ;
        RECT  0 40.944 0.084 40.968 ;
    END
  END tk[284]
  PIN tk[285]
    DIRECTION INPUT ;
    USE SIGNAL ;
    PORT
      LAYER M4 ;
        RECT  0 41.088 0.084 41.112 ;
    END
  END tk[285]
  PIN tk[286]
    DIRECTION INPUT ;
    USE SIGNAL ;
    PORT
      LAYER M4 ;
        RECT  0 41.184 0.084 41.208 ;
    END
  END tk[286]
  PIN tk[287]
    DIRECTION INPUT ;
    USE SIGNAL ;
    PORT
      LAYER M4 ;
        RECT  0 41.28 0.084 41.304 ;
    END
  END tk[287]
  PIN tk[288]
    DIRECTION INPUT ;
    USE SIGNAL ;
    PORT
      LAYER M4 ;
        RECT  0 41.376 0.084 41.4 ;
    END
  END tk[288]
  PIN tk[289]
    DIRECTION INPUT ;
    USE SIGNAL ;
    PORT
      LAYER M4 ;
        RECT  0 41.52 0.084 41.544 ;
    END
  END tk[289]
  PIN tk[28]
    DIRECTION INPUT ;
    USE SIGNAL ;
    PORT
      LAYER M4 ;
        RECT  0 13.104 0.084 13.128 ;
    END
  END tk[28]
  PIN tk[290]
    DIRECTION INPUT ;
    USE SIGNAL ;
    PORT
      LAYER M4 ;
        RECT  0 41.616 0.084 41.64 ;
    END
  END tk[290]
  PIN tk[291]
    DIRECTION INPUT ;
    USE SIGNAL ;
    PORT
      LAYER M4 ;
        RECT  0 41.712 0.084 41.736 ;
    END
  END tk[291]
  PIN tk[292]
    DIRECTION INPUT ;
    USE SIGNAL ;
    PORT
      LAYER M4 ;
        RECT  0 41.856 0.084 41.88 ;
    END
  END tk[292]
  PIN tk[293]
    DIRECTION INPUT ;
    USE SIGNAL ;
    PORT
      LAYER M4 ;
        RECT  0 41.952 0.084 41.976 ;
    END
  END tk[293]
  PIN tk[294]
    DIRECTION INPUT ;
    USE SIGNAL ;
    PORT
      LAYER M4 ;
        RECT  0 42.048 0.084 42.072 ;
    END
  END tk[294]
  PIN tk[295]
    DIRECTION INPUT ;
    USE SIGNAL ;
    PORT
      LAYER M4 ;
        RECT  0 42.144 0.084 42.168 ;
    END
  END tk[295]
  PIN tk[296]
    DIRECTION INPUT ;
    USE SIGNAL ;
    PORT
      LAYER M4 ;
        RECT  0 42.288 0.084 42.312 ;
    END
  END tk[296]
  PIN tk[297]
    DIRECTION INPUT ;
    USE SIGNAL ;
    PORT
      LAYER M4 ;
        RECT  0 42.384 0.084 42.408 ;
    END
  END tk[297]
  PIN tk[298]
    DIRECTION INPUT ;
    USE SIGNAL ;
    PORT
      LAYER M4 ;
        RECT  0 42.48 0.084 42.504 ;
    END
  END tk[298]
  PIN tk[299]
    DIRECTION INPUT ;
    USE SIGNAL ;
    PORT
      LAYER M4 ;
        RECT  0 42.576 0.084 42.6 ;
    END
  END tk[299]
  PIN tk[29]
    DIRECTION INPUT ;
    USE SIGNAL ;
    PORT
      LAYER M4 ;
        RECT  0 13.2 0.084 13.224 ;
    END
  END tk[29]
  PIN tk[2]
    DIRECTION INPUT ;
    USE SIGNAL ;
    PORT
      LAYER M4 ;
        RECT  0 10.272 0.084 10.296 ;
    END
  END tk[2]
  PIN tk[300]
    DIRECTION INPUT ;
    USE SIGNAL ;
    PORT
      LAYER M4 ;
        RECT  0 42.72 0.084 42.744 ;
    END
  END tk[300]
  PIN tk[301]
    DIRECTION INPUT ;
    USE SIGNAL ;
    PORT
      LAYER M4 ;
        RECT  0 42.816 0.084 42.84 ;
    END
  END tk[301]
  PIN tk[302]
    DIRECTION INPUT ;
    USE SIGNAL ;
    PORT
      LAYER M4 ;
        RECT  0 42.912 0.084 42.936 ;
    END
  END tk[302]
  PIN tk[303]
    DIRECTION INPUT ;
    USE SIGNAL ;
    PORT
      LAYER M4 ;
        RECT  0 43.008 0.084 43.032 ;
    END
  END tk[303]
  PIN tk[304]
    DIRECTION INPUT ;
    USE SIGNAL ;
    PORT
      LAYER M4 ;
        RECT  0 43.152 0.084 43.176 ;
    END
  END tk[304]
  PIN tk[305]
    DIRECTION INPUT ;
    USE SIGNAL ;
    PORT
      LAYER M4 ;
        RECT  0 43.248 0.084 43.272 ;
    END
  END tk[305]
  PIN tk[306]
    DIRECTION INPUT ;
    USE SIGNAL ;
    PORT
      LAYER M4 ;
        RECT  0 43.344 0.084 43.368 ;
    END
  END tk[306]
  PIN tk[307]
    DIRECTION INPUT ;
    USE SIGNAL ;
    PORT
      LAYER M4 ;
        RECT  0 43.488 0.084 43.512 ;
    END
  END tk[307]
  PIN tk[308]
    DIRECTION INPUT ;
    USE SIGNAL ;
    PORT
      LAYER M4 ;
        RECT  0 43.584 0.084 43.608 ;
    END
  END tk[308]
  PIN tk[309]
    DIRECTION INPUT ;
    USE SIGNAL ;
    PORT
      LAYER M4 ;
        RECT  0 43.68 0.084 43.704 ;
    END
  END tk[309]
  PIN tk[30]
    DIRECTION INPUT ;
    USE SIGNAL ;
    PORT
      LAYER M4 ;
        RECT  0 13.296 0.084 13.32 ;
    END
  END tk[30]
  PIN tk[310]
    DIRECTION INPUT ;
    USE SIGNAL ;
    PORT
      LAYER M4 ;
        RECT  0 43.776 0.084 43.8 ;
    END
  END tk[310]
  PIN tk[311]
    DIRECTION INPUT ;
    USE SIGNAL ;
    PORT
      LAYER M4 ;
        RECT  0 43.92 0.084 43.944 ;
    END
  END tk[311]
  PIN tk[312]
    DIRECTION INPUT ;
    USE SIGNAL ;
    PORT
      LAYER M4 ;
        RECT  0 44.016 0.084 44.04 ;
    END
  END tk[312]
  PIN tk[313]
    DIRECTION INPUT ;
    USE SIGNAL ;
    PORT
      LAYER M4 ;
        RECT  0 44.112 0.084 44.136 ;
    END
  END tk[313]
  PIN tk[314]
    DIRECTION INPUT ;
    USE SIGNAL ;
    PORT
      LAYER M4 ;
        RECT  0 44.208 0.084 44.232 ;
    END
  END tk[314]
  PIN tk[315]
    DIRECTION INPUT ;
    USE SIGNAL ;
    PORT
      LAYER M4 ;
        RECT  0 44.352 0.084 44.376 ;
    END
  END tk[315]
  PIN tk[316]
    DIRECTION INPUT ;
    USE SIGNAL ;
    PORT
      LAYER M4 ;
        RECT  0 44.448 0.084 44.472 ;
    END
  END tk[316]
  PIN tk[317]
    DIRECTION INPUT ;
    USE SIGNAL ;
    PORT
      LAYER M4 ;
        RECT  0 44.544 0.084 44.568 ;
    END
  END tk[317]
  PIN tk[318]
    DIRECTION INPUT ;
    USE SIGNAL ;
    PORT
      LAYER M4 ;
        RECT  0 44.64 0.084 44.664 ;
    END
  END tk[318]
  PIN tk[319]
    DIRECTION INPUT ;
    USE SIGNAL ;
    PORT
      LAYER M4 ;
        RECT  0 44.784 0.084 44.808 ;
    END
  END tk[319]
  PIN tk[31]
    DIRECTION INPUT ;
    USE SIGNAL ;
    PORT
      LAYER M4 ;
        RECT  0 13.44 0.084 13.464 ;
    END
  END tk[31]
  PIN tk[320]
    DIRECTION INPUT ;
    USE SIGNAL ;
    PORT
      LAYER M4 ;
        RECT  0 44.88 0.084 44.904 ;
    END
  END tk[320]
  PIN tk[321]
    DIRECTION INPUT ;
    USE SIGNAL ;
    PORT
      LAYER M4 ;
        RECT  0 44.976 0.084 45 ;
    END
  END tk[321]
  PIN tk[322]
    DIRECTION INPUT ;
    USE SIGNAL ;
    PORT
      LAYER M4 ;
        RECT  0 45.12 0.084 45.144 ;
    END
  END tk[322]
  PIN tk[323]
    DIRECTION INPUT ;
    USE SIGNAL ;
    PORT
      LAYER M4 ;
        RECT  0 45.216 0.084 45.24 ;
    END
  END tk[323]
  PIN tk[324]
    DIRECTION INPUT ;
    USE SIGNAL ;
    PORT
      LAYER M4 ;
        RECT  0 45.312 0.084 45.336 ;
    END
  END tk[324]
  PIN tk[325]
    DIRECTION INPUT ;
    USE SIGNAL ;
    PORT
      LAYER M4 ;
        RECT  0 45.408 0.084 45.432 ;
    END
  END tk[325]
  PIN tk[326]
    DIRECTION INPUT ;
    USE SIGNAL ;
    PORT
      LAYER M4 ;
        RECT  0 45.552 0.084 45.576 ;
    END
  END tk[326]
  PIN tk[327]
    DIRECTION INPUT ;
    USE SIGNAL ;
    PORT
      LAYER M4 ;
        RECT  0 45.648 0.084 45.672 ;
    END
  END tk[327]
  PIN tk[328]
    DIRECTION INPUT ;
    USE SIGNAL ;
    PORT
      LAYER M4 ;
        RECT  0 45.744 0.084 45.768 ;
    END
  END tk[328]
  PIN tk[329]
    DIRECTION INPUT ;
    USE SIGNAL ;
    PORT
      LAYER M4 ;
        RECT  0 45.84 0.084 45.864 ;
    END
  END tk[329]
  PIN tk[32]
    DIRECTION INPUT ;
    USE SIGNAL ;
    PORT
      LAYER M4 ;
        RECT  0 13.536 0.084 13.56 ;
    END
  END tk[32]
  PIN tk[330]
    DIRECTION INPUT ;
    USE SIGNAL ;
    PORT
      LAYER M4 ;
        RECT  0 45.984 0.084 46.008 ;
    END
  END tk[330]
  PIN tk[331]
    DIRECTION INPUT ;
    USE SIGNAL ;
    PORT
      LAYER M4 ;
        RECT  0 46.08 0.084 46.104 ;
    END
  END tk[331]
  PIN tk[332]
    DIRECTION INPUT ;
    USE SIGNAL ;
    PORT
      LAYER M4 ;
        RECT  0 46.176 0.084 46.2 ;
    END
  END tk[332]
  PIN tk[333]
    DIRECTION INPUT ;
    USE SIGNAL ;
    PORT
      LAYER M4 ;
        RECT  0 46.32 0.084 46.344 ;
    END
  END tk[333]
  PIN tk[334]
    DIRECTION INPUT ;
    USE SIGNAL ;
    PORT
      LAYER M4 ;
        RECT  0 46.416 0.084 46.44 ;
    END
  END tk[334]
  PIN tk[335]
    DIRECTION INPUT ;
    USE SIGNAL ;
    PORT
      LAYER M4 ;
        RECT  0 46.512 0.084 46.536 ;
    END
  END tk[335]
  PIN tk[336]
    DIRECTION INPUT ;
    USE SIGNAL ;
    PORT
      LAYER M4 ;
        RECT  0 46.608 0.084 46.632 ;
    END
  END tk[336]
  PIN tk[337]
    DIRECTION INPUT ;
    USE SIGNAL ;
    PORT
      LAYER M4 ;
        RECT  0 46.752 0.084 46.776 ;
    END
  END tk[337]
  PIN tk[338]
    DIRECTION INPUT ;
    USE SIGNAL ;
    PORT
      LAYER M4 ;
        RECT  0 46.848 0.084 46.872 ;
    END
  END tk[338]
  PIN tk[339]
    DIRECTION INPUT ;
    USE SIGNAL ;
    PORT
      LAYER M4 ;
        RECT  0 46.944 0.084 46.968 ;
    END
  END tk[339]
  PIN tk[33]
    DIRECTION INPUT ;
    USE SIGNAL ;
    PORT
      LAYER M4 ;
        RECT  0 13.632 0.084 13.656 ;
    END
  END tk[33]
  PIN tk[340]
    DIRECTION INPUT ;
    USE SIGNAL ;
    PORT
      LAYER M4 ;
        RECT  0 47.04 0.084 47.064 ;
    END
  END tk[340]
  PIN tk[341]
    DIRECTION INPUT ;
    USE SIGNAL ;
    PORT
      LAYER M4 ;
        RECT  0 47.184 0.084 47.208 ;
    END
  END tk[341]
  PIN tk[342]
    DIRECTION INPUT ;
    USE SIGNAL ;
    PORT
      LAYER M4 ;
        RECT  0 47.28 0.084 47.304 ;
    END
  END tk[342]
  PIN tk[343]
    DIRECTION INPUT ;
    USE SIGNAL ;
    PORT
      LAYER M4 ;
        RECT  0 47.376 0.084 47.4 ;
    END
  END tk[343]
  PIN tk[344]
    DIRECTION INPUT ;
    USE SIGNAL ;
    PORT
      LAYER M4 ;
        RECT  0 47.472 0.084 47.496 ;
    END
  END tk[344]
  PIN tk[345]
    DIRECTION INPUT ;
    USE SIGNAL ;
    PORT
      LAYER M4 ;
        RECT  0 47.616 0.084 47.64 ;
    END
  END tk[345]
  PIN tk[346]
    DIRECTION INPUT ;
    USE SIGNAL ;
    PORT
      LAYER M4 ;
        RECT  0 47.712 0.084 47.736 ;
    END
  END tk[346]
  PIN tk[347]
    DIRECTION INPUT ;
    USE SIGNAL ;
    PORT
      LAYER M4 ;
        RECT  0 47.808 0.084 47.832 ;
    END
  END tk[347]
  PIN tk[348]
    DIRECTION INPUT ;
    USE SIGNAL ;
    PORT
      LAYER M4 ;
        RECT  0 47.952 0.084 47.976 ;
    END
  END tk[348]
  PIN tk[349]
    DIRECTION INPUT ;
    USE SIGNAL ;
    PORT
      LAYER M4 ;
        RECT  0 48.048 0.084 48.072 ;
    END
  END tk[349]
  PIN tk[34]
    DIRECTION INPUT ;
    USE SIGNAL ;
    PORT
      LAYER M4 ;
        RECT  0 13.728 0.084 13.752 ;
    END
  END tk[34]
  PIN tk[350]
    DIRECTION INPUT ;
    USE SIGNAL ;
    PORT
      LAYER M4 ;
        RECT  0 48.144 0.084 48.168 ;
    END
  END tk[350]
  PIN tk[351]
    DIRECTION INPUT ;
    USE SIGNAL ;
    PORT
      LAYER M4 ;
        RECT  0 48.24 0.084 48.264 ;
    END
  END tk[351]
  PIN tk[352]
    DIRECTION INPUT ;
    USE SIGNAL ;
    PORT
      LAYER M4 ;
        RECT  0 48.384 0.084 48.408 ;
    END
  END tk[352]
  PIN tk[353]
    DIRECTION INPUT ;
    USE SIGNAL ;
    PORT
      LAYER M4 ;
        RECT  0 48.48 0.084 48.504 ;
    END
  END tk[353]
  PIN tk[354]
    DIRECTION INPUT ;
    USE SIGNAL ;
    PORT
      LAYER M4 ;
        RECT  0 48.576 0.084 48.6 ;
    END
  END tk[354]
  PIN tk[355]
    DIRECTION INPUT ;
    USE SIGNAL ;
    PORT
      LAYER M4 ;
        RECT  0 48.672 0.084 48.696 ;
    END
  END tk[355]
  PIN tk[356]
    DIRECTION INPUT ;
    USE SIGNAL ;
    PORT
      LAYER M4 ;
        RECT  0 48.816 0.084 48.84 ;
    END
  END tk[356]
  PIN tk[357]
    DIRECTION INPUT ;
    USE SIGNAL ;
    PORT
      LAYER M4 ;
        RECT  0 48.912 0.084 48.936 ;
    END
  END tk[357]
  PIN tk[358]
    DIRECTION INPUT ;
    USE SIGNAL ;
    PORT
      LAYER M4 ;
        RECT  0 49.008 0.084 49.032 ;
    END
  END tk[358]
  PIN tk[359]
    DIRECTION INPUT ;
    USE SIGNAL ;
    PORT
      LAYER M4 ;
        RECT  0 49.104 0.084 49.128 ;
    END
  END tk[359]
  PIN tk[35]
    DIRECTION INPUT ;
    USE SIGNAL ;
    PORT
      LAYER M4 ;
        RECT  0 13.872 0.084 13.896 ;
    END
  END tk[35]
  PIN tk[360]
    DIRECTION INPUT ;
    USE SIGNAL ;
    PORT
      LAYER M4 ;
        RECT  0 49.248 0.084 49.272 ;
    END
  END tk[360]
  PIN tk[361]
    DIRECTION INPUT ;
    USE SIGNAL ;
    PORT
      LAYER M4 ;
        RECT  0 49.344 0.084 49.368 ;
    END
  END tk[361]
  PIN tk[362]
    DIRECTION INPUT ;
    USE SIGNAL ;
    PORT
      LAYER M4 ;
        RECT  0 49.44 0.084 49.464 ;
    END
  END tk[362]
  PIN tk[363]
    DIRECTION INPUT ;
    USE SIGNAL ;
    PORT
      LAYER M4 ;
        RECT  0 49.584 0.084 49.608 ;
    END
  END tk[363]
  PIN tk[364]
    DIRECTION INPUT ;
    USE SIGNAL ;
    PORT
      LAYER M4 ;
        RECT  0 49.68 0.084 49.704 ;
    END
  END tk[364]
  PIN tk[365]
    DIRECTION INPUT ;
    USE SIGNAL ;
    PORT
      LAYER M4 ;
        RECT  0 49.776 0.084 49.8 ;
    END
  END tk[365]
  PIN tk[366]
    DIRECTION INPUT ;
    USE SIGNAL ;
    PORT
      LAYER M4 ;
        RECT  0 49.872 0.084 49.896 ;
    END
  END tk[366]
  PIN tk[367]
    DIRECTION INPUT ;
    USE SIGNAL ;
    PORT
      LAYER M4 ;
        RECT  0 50.016 0.084 50.04 ;
    END
  END tk[367]
  PIN tk[368]
    DIRECTION INPUT ;
    USE SIGNAL ;
    PORT
      LAYER M4 ;
        RECT  0 50.112 0.084 50.136 ;
    END
  END tk[368]
  PIN tk[369]
    DIRECTION INPUT ;
    USE SIGNAL ;
    PORT
      LAYER M4 ;
        RECT  0 50.208 0.084 50.232 ;
    END
  END tk[369]
  PIN tk[36]
    DIRECTION INPUT ;
    USE SIGNAL ;
    PORT
      LAYER M4 ;
        RECT  0 13.968 0.084 13.992 ;
    END
  END tk[36]
  PIN tk[370]
    DIRECTION INPUT ;
    USE SIGNAL ;
    PORT
      LAYER M4 ;
        RECT  0 50.304 0.084 50.328 ;
    END
  END tk[370]
  PIN tk[371]
    DIRECTION INPUT ;
    USE SIGNAL ;
    PORT
      LAYER M4 ;
        RECT  0 50.448 0.084 50.472 ;
    END
  END tk[371]
  PIN tk[372]
    DIRECTION INPUT ;
    USE SIGNAL ;
    PORT
      LAYER M4 ;
        RECT  0 50.544 0.084 50.568 ;
    END
  END tk[372]
  PIN tk[373]
    DIRECTION INPUT ;
    USE SIGNAL ;
    PORT
      LAYER M4 ;
        RECT  0 50.64 0.084 50.664 ;
    END
  END tk[373]
  PIN tk[374]
    DIRECTION INPUT ;
    USE SIGNAL ;
    PORT
      LAYER M4 ;
        RECT  0 50.784 0.084 50.808 ;
    END
  END tk[374]
  PIN tk[375]
    DIRECTION INPUT ;
    USE SIGNAL ;
    PORT
      LAYER M4 ;
        RECT  0 50.88 0.084 50.904 ;
    END
  END tk[375]
  PIN tk[376]
    DIRECTION INPUT ;
    USE SIGNAL ;
    PORT
      LAYER M4 ;
        RECT  0 50.976 0.084 51 ;
    END
  END tk[376]
  PIN tk[377]
    DIRECTION INPUT ;
    USE SIGNAL ;
    PORT
      LAYER M4 ;
        RECT  0 51.072 0.084 51.096 ;
    END
  END tk[377]
  PIN tk[378]
    DIRECTION INPUT ;
    USE SIGNAL ;
    PORT
      LAYER M4 ;
        RECT  0 51.216 0.084 51.24 ;
    END
  END tk[378]
  PIN tk[379]
    DIRECTION INPUT ;
    USE SIGNAL ;
    PORT
      LAYER M4 ;
        RECT  0 51.312 0.084 51.336 ;
    END
  END tk[379]
  PIN tk[37]
    DIRECTION INPUT ;
    USE SIGNAL ;
    PORT
      LAYER M4 ;
        RECT  0 14.064 0.084 14.088 ;
    END
  END tk[37]
  PIN tk[380]
    DIRECTION INPUT ;
    USE SIGNAL ;
    PORT
      LAYER M4 ;
        RECT  0 51.408 0.084 51.432 ;
    END
  END tk[380]
  PIN tk[381]
    DIRECTION INPUT ;
    USE SIGNAL ;
    PORT
      LAYER M4 ;
        RECT  0 51.504 0.084 51.528 ;
    END
  END tk[381]
  PIN tk[382]
    DIRECTION INPUT ;
    USE SIGNAL ;
    PORT
      LAYER M4 ;
        RECT  0 51.648 0.084 51.672 ;
    END
  END tk[382]
  PIN tk[383]
    DIRECTION INPUT ;
    USE SIGNAL ;
    PORT
      LAYER M4 ;
        RECT  0 51.744 0.084 51.768 ;
    END
  END tk[383]
  PIN tk[384]
    DIRECTION INPUT ;
    USE SIGNAL ;
    PORT
      LAYER M4 ;
        RECT  0 51.84 0.084 51.864 ;
    END
  END tk[384]
  PIN tk[385]
    DIRECTION INPUT ;
    USE SIGNAL ;
    PORT
      LAYER M4 ;
        RECT  0 51.936 0.084 51.96 ;
    END
  END tk[385]
  PIN tk[386]
    DIRECTION INPUT ;
    USE SIGNAL ;
    PORT
      LAYER M4 ;
        RECT  0 52.08 0.084 52.104 ;
    END
  END tk[386]
  PIN tk[387]
    DIRECTION INPUT ;
    USE SIGNAL ;
    PORT
      LAYER M4 ;
        RECT  0 52.176 0.084 52.2 ;
    END
  END tk[387]
  PIN tk[388]
    DIRECTION INPUT ;
    USE SIGNAL ;
    PORT
      LAYER M4 ;
        RECT  0 52.272 0.084 52.296 ;
    END
  END tk[388]
  PIN tk[389]
    DIRECTION INPUT ;
    USE SIGNAL ;
    PORT
      LAYER M4 ;
        RECT  0 52.416 0.084 52.44 ;
    END
  END tk[389]
  PIN tk[38]
    DIRECTION INPUT ;
    USE SIGNAL ;
    PORT
      LAYER M4 ;
        RECT  0 14.16 0.084 14.184 ;
    END
  END tk[38]
  PIN tk[390]
    DIRECTION INPUT ;
    USE SIGNAL ;
    PORT
      LAYER M4 ;
        RECT  0 52.512 0.084 52.536 ;
    END
  END tk[390]
  PIN tk[391]
    DIRECTION INPUT ;
    USE SIGNAL ;
    PORT
      LAYER M4 ;
        RECT  0 52.608 0.084 52.632 ;
    END
  END tk[391]
  PIN tk[392]
    DIRECTION INPUT ;
    USE SIGNAL ;
    PORT
      LAYER M4 ;
        RECT  0 52.704 0.084 52.728 ;
    END
  END tk[392]
  PIN tk[393]
    DIRECTION INPUT ;
    USE SIGNAL ;
    PORT
      LAYER M4 ;
        RECT  0 52.848 0.084 52.872 ;
    END
  END tk[393]
  PIN tk[394]
    DIRECTION INPUT ;
    USE SIGNAL ;
    PORT
      LAYER M4 ;
        RECT  0 52.944 0.084 52.968 ;
    END
  END tk[394]
  PIN tk[395]
    DIRECTION INPUT ;
    USE SIGNAL ;
    PORT
      LAYER M4 ;
        RECT  0 53.04 0.084 53.064 ;
    END
  END tk[395]
  PIN tk[396]
    DIRECTION INPUT ;
    USE SIGNAL ;
    PORT
      LAYER M4 ;
        RECT  0 53.136 0.084 53.16 ;
    END
  END tk[396]
  PIN tk[397]
    DIRECTION INPUT ;
    USE SIGNAL ;
    PORT
      LAYER M4 ;
        RECT  0 53.28 0.084 53.304 ;
    END
  END tk[397]
  PIN tk[398]
    DIRECTION INPUT ;
    USE SIGNAL ;
    PORT
      LAYER M4 ;
        RECT  0 53.376 0.084 53.4 ;
    END
  END tk[398]
  PIN tk[399]
    DIRECTION INPUT ;
    USE SIGNAL ;
    PORT
      LAYER M4 ;
        RECT  0 53.472 0.084 53.496 ;
    END
  END tk[399]
  PIN tk[39]
    DIRECTION INPUT ;
    USE SIGNAL ;
    PORT
      LAYER M4 ;
        RECT  0 14.304 0.084 14.328 ;
    END
  END tk[39]
  PIN tk[3]
    DIRECTION INPUT ;
    USE SIGNAL ;
    PORT
      LAYER M4 ;
        RECT  0 10.368 0.084 10.392 ;
    END
  END tk[3]
  PIN tk[400]
    DIRECTION INPUT ;
    USE SIGNAL ;
    PORT
      LAYER M4 ;
        RECT  0 53.568 0.084 53.592 ;
    END
  END tk[400]
  PIN tk[401]
    DIRECTION INPUT ;
    USE SIGNAL ;
    PORT
      LAYER M4 ;
        RECT  0 53.712 0.084 53.736 ;
    END
  END tk[401]
  PIN tk[402]
    DIRECTION INPUT ;
    USE SIGNAL ;
    PORT
      LAYER M4 ;
        RECT  0 53.808 0.084 53.832 ;
    END
  END tk[402]
  PIN tk[403]
    DIRECTION INPUT ;
    USE SIGNAL ;
    PORT
      LAYER M4 ;
        RECT  0 53.904 0.084 53.928 ;
    END
  END tk[403]
  PIN tk[404]
    DIRECTION INPUT ;
    USE SIGNAL ;
    PORT
      LAYER M4 ;
        RECT  0 54.048 0.084 54.072 ;
    END
  END tk[404]
  PIN tk[405]
    DIRECTION INPUT ;
    USE SIGNAL ;
    PORT
      LAYER M4 ;
        RECT  0 54.144 0.084 54.168 ;
    END
  END tk[405]
  PIN tk[406]
    DIRECTION INPUT ;
    USE SIGNAL ;
    PORT
      LAYER M4 ;
        RECT  0 54.24 0.084 54.264 ;
    END
  END tk[406]
  PIN tk[407]
    DIRECTION INPUT ;
    USE SIGNAL ;
    PORT
      LAYER M4 ;
        RECT  0 54.336 0.084 54.36 ;
    END
  END tk[407]
  PIN tk[408]
    DIRECTION INPUT ;
    USE SIGNAL ;
    PORT
      LAYER M4 ;
        RECT  0 54.48 0.084 54.504 ;
    END
  END tk[408]
  PIN tk[409]
    DIRECTION INPUT ;
    USE SIGNAL ;
    PORT
      LAYER M4 ;
        RECT  0 54.576 0.084 54.6 ;
    END
  END tk[409]
  PIN tk[40]
    DIRECTION INPUT ;
    USE SIGNAL ;
    PORT
      LAYER M4 ;
        RECT  0 14.4 0.084 14.424 ;
    END
  END tk[40]
  PIN tk[410]
    DIRECTION INPUT ;
    USE SIGNAL ;
    PORT
      LAYER M4 ;
        RECT  0 54.672 0.084 54.696 ;
    END
  END tk[410]
  PIN tk[411]
    DIRECTION INPUT ;
    USE SIGNAL ;
    PORT
      LAYER M4 ;
        RECT  0 54.768 0.084 54.792 ;
    END
  END tk[411]
  PIN tk[412]
    DIRECTION INPUT ;
    USE SIGNAL ;
    PORT
      LAYER M4 ;
        RECT  0 54.912 0.084 54.936 ;
    END
  END tk[412]
  PIN tk[413]
    DIRECTION INPUT ;
    USE SIGNAL ;
    PORT
      LAYER M4 ;
        RECT  0 55.008 0.084 55.032 ;
    END
  END tk[413]
  PIN tk[414]
    DIRECTION INPUT ;
    USE SIGNAL ;
    PORT
      LAYER M4 ;
        RECT  0 55.104 0.084 55.128 ;
    END
  END tk[414]
  PIN tk[415]
    DIRECTION INPUT ;
    USE SIGNAL ;
    PORT
      LAYER M4 ;
        RECT  0 55.248 0.084 55.272 ;
    END
  END tk[415]
  PIN tk[416]
    DIRECTION INPUT ;
    USE SIGNAL ;
    PORT
      LAYER M4 ;
        RECT  0 55.344 0.084 55.368 ;
    END
  END tk[416]
  PIN tk[417]
    DIRECTION INPUT ;
    USE SIGNAL ;
    PORT
      LAYER M4 ;
        RECT  0 55.44 0.084 55.464 ;
    END
  END tk[417]
  PIN tk[418]
    DIRECTION INPUT ;
    USE SIGNAL ;
    PORT
      LAYER M4 ;
        RECT  0 55.536 0.084 55.56 ;
    END
  END tk[418]
  PIN tk[419]
    DIRECTION INPUT ;
    USE SIGNAL ;
    PORT
      LAYER M4 ;
        RECT  0 55.68 0.084 55.704 ;
    END
  END tk[419]
  PIN tk[41]
    DIRECTION INPUT ;
    USE SIGNAL ;
    PORT
      LAYER M4 ;
        RECT  0 14.496 0.084 14.52 ;
    END
  END tk[41]
  PIN tk[420]
    DIRECTION INPUT ;
    USE SIGNAL ;
    PORT
      LAYER M4 ;
        RECT  0 55.776 0.084 55.8 ;
    END
  END tk[420]
  PIN tk[421]
    DIRECTION INPUT ;
    USE SIGNAL ;
    PORT
      LAYER M4 ;
        RECT  0 55.872 0.084 55.896 ;
    END
  END tk[421]
  PIN tk[422]
    DIRECTION INPUT ;
    USE SIGNAL ;
    PORT
      LAYER M4 ;
        RECT  0 55.968 0.084 55.992 ;
    END
  END tk[422]
  PIN tk[423]
    DIRECTION INPUT ;
    USE SIGNAL ;
    PORT
      LAYER M4 ;
        RECT  0 56.112 0.084 56.136 ;
    END
  END tk[423]
  PIN tk[424]
    DIRECTION INPUT ;
    USE SIGNAL ;
    PORT
      LAYER M4 ;
        RECT  0 56.208 0.084 56.232 ;
    END
  END tk[424]
  PIN tk[425]
    DIRECTION INPUT ;
    USE SIGNAL ;
    PORT
      LAYER M4 ;
        RECT  0 56.304 0.084 56.328 ;
    END
  END tk[425]
  PIN tk[426]
    DIRECTION INPUT ;
    USE SIGNAL ;
    PORT
      LAYER M4 ;
        RECT  0 56.4 0.084 56.424 ;
    END
  END tk[426]
  PIN tk[427]
    DIRECTION INPUT ;
    USE SIGNAL ;
    PORT
      LAYER M4 ;
        RECT  0 56.544 0.084 56.568 ;
    END
  END tk[427]
  PIN tk[428]
    DIRECTION INPUT ;
    USE SIGNAL ;
    PORT
      LAYER M4 ;
        RECT  0 56.64 0.084 56.664 ;
    END
  END tk[428]
  PIN tk[429]
    DIRECTION INPUT ;
    USE SIGNAL ;
    PORT
      LAYER M4 ;
        RECT  0 56.736 0.084 56.76 ;
    END
  END tk[429]
  PIN tk[42]
    DIRECTION INPUT ;
    USE SIGNAL ;
    PORT
      LAYER M4 ;
        RECT  0 14.592 0.084 14.616 ;
    END
  END tk[42]
  PIN tk[430]
    DIRECTION INPUT ;
    USE SIGNAL ;
    PORT
      LAYER M4 ;
        RECT  0 56.88 0.084 56.904 ;
    END
  END tk[430]
  PIN tk[431]
    DIRECTION INPUT ;
    USE SIGNAL ;
    PORT
      LAYER M4 ;
        RECT  0 56.976 0.084 57 ;
    END
  END tk[431]
  PIN tk[432]
    DIRECTION INPUT ;
    USE SIGNAL ;
    PORT
      LAYER M4 ;
        RECT  0 57.072 0.084 57.096 ;
    END
  END tk[432]
  PIN tk[433]
    DIRECTION INPUT ;
    USE SIGNAL ;
    PORT
      LAYER M4 ;
        RECT  0 57.168 0.084 57.192 ;
    END
  END tk[433]
  PIN tk[434]
    DIRECTION INPUT ;
    USE SIGNAL ;
    PORT
      LAYER M4 ;
        RECT  0 57.312 0.084 57.336 ;
    END
  END tk[434]
  PIN tk[435]
    DIRECTION INPUT ;
    USE SIGNAL ;
    PORT
      LAYER M4 ;
        RECT  0 57.408 0.084 57.432 ;
    END
  END tk[435]
  PIN tk[436]
    DIRECTION INPUT ;
    USE SIGNAL ;
    PORT
      LAYER M4 ;
        RECT  0 57.504 0.084 57.528 ;
    END
  END tk[436]
  PIN tk[437]
    DIRECTION INPUT ;
    USE SIGNAL ;
    PORT
      LAYER M4 ;
        RECT  0 57.6 0.084 57.624 ;
    END
  END tk[437]
  PIN tk[438]
    DIRECTION INPUT ;
    USE SIGNAL ;
    PORT
      LAYER M4 ;
        RECT  0 57.744 0.084 57.768 ;
    END
  END tk[438]
  PIN tk[439]
    DIRECTION INPUT ;
    USE SIGNAL ;
    PORT
      LAYER M4 ;
        RECT  0 57.84 0.084 57.864 ;
    END
  END tk[439]
  PIN tk[43]
    DIRECTION INPUT ;
    USE SIGNAL ;
    PORT
      LAYER M4 ;
        RECT  0 14.736 0.084 14.76 ;
    END
  END tk[43]
  PIN tk[440]
    DIRECTION INPUT ;
    USE SIGNAL ;
    PORT
      LAYER M4 ;
        RECT  0 57.936 0.084 57.96 ;
    END
  END tk[440]
  PIN tk[441]
    DIRECTION INPUT ;
    USE SIGNAL ;
    PORT
      LAYER M4 ;
        RECT  0 58.032 0.084 58.056 ;
    END
  END tk[441]
  PIN tk[442]
    DIRECTION INPUT ;
    USE SIGNAL ;
    PORT
      LAYER M4 ;
        RECT  0 58.176 0.084 58.2 ;
    END
  END tk[442]
  PIN tk[443]
    DIRECTION INPUT ;
    USE SIGNAL ;
    PORT
      LAYER M4 ;
        RECT  0 58.272 0.084 58.296 ;
    END
  END tk[443]
  PIN tk[444]
    DIRECTION INPUT ;
    USE SIGNAL ;
    PORT
      LAYER M4 ;
        RECT  0 58.368 0.084 58.392 ;
    END
  END tk[444]
  PIN tk[445]
    DIRECTION INPUT ;
    USE SIGNAL ;
    PORT
      LAYER M4 ;
        RECT  0 58.512 0.084 58.536 ;
    END
  END tk[445]
  PIN tk[446]
    DIRECTION INPUT ;
    USE SIGNAL ;
    PORT
      LAYER M4 ;
        RECT  0 58.608 0.084 58.632 ;
    END
  END tk[446]
  PIN tk[447]
    DIRECTION INPUT ;
    USE SIGNAL ;
    PORT
      LAYER M4 ;
        RECT  0 58.704 0.084 58.728 ;
    END
  END tk[447]
  PIN tk[448]
    DIRECTION INPUT ;
    USE SIGNAL ;
    PORT
      LAYER M4 ;
        RECT  0 58.8 0.084 58.824 ;
    END
  END tk[448]
  PIN tk[449]
    DIRECTION INPUT ;
    USE SIGNAL ;
    PORT
      LAYER M4 ;
        RECT  0 58.944 0.084 58.968 ;
    END
  END tk[449]
  PIN tk[44]
    DIRECTION INPUT ;
    USE SIGNAL ;
    PORT
      LAYER M4 ;
        RECT  0 14.832 0.084 14.856 ;
    END
  END tk[44]
  PIN tk[450]
    DIRECTION INPUT ;
    USE SIGNAL ;
    PORT
      LAYER M4 ;
        RECT  0 59.04 0.084 59.064 ;
    END
  END tk[450]
  PIN tk[451]
    DIRECTION INPUT ;
    USE SIGNAL ;
    PORT
      LAYER M4 ;
        RECT  0 59.136 0.084 59.16 ;
    END
  END tk[451]
  PIN tk[452]
    DIRECTION INPUT ;
    USE SIGNAL ;
    PORT
      LAYER M4 ;
        RECT  0 59.232 0.084 59.256 ;
    END
  END tk[452]
  PIN tk[453]
    DIRECTION INPUT ;
    USE SIGNAL ;
    PORT
      LAYER M4 ;
        RECT  0 59.376 0.084 59.4 ;
    END
  END tk[453]
  PIN tk[454]
    DIRECTION INPUT ;
    USE SIGNAL ;
    PORT
      LAYER M4 ;
        RECT  0 59.472 0.084 59.496 ;
    END
  END tk[454]
  PIN tk[455]
    DIRECTION INPUT ;
    USE SIGNAL ;
    PORT
      LAYER M4 ;
        RECT  0 59.568 0.084 59.592 ;
    END
  END tk[455]
  PIN tk[456]
    DIRECTION INPUT ;
    USE SIGNAL ;
    PORT
      LAYER M4 ;
        RECT  0 59.712 0.084 59.736 ;
    END
  END tk[456]
  PIN tk[457]
    DIRECTION INPUT ;
    USE SIGNAL ;
    PORT
      LAYER M4 ;
        RECT  0 59.808 0.084 59.832 ;
    END
  END tk[457]
  PIN tk[458]
    DIRECTION INPUT ;
    USE SIGNAL ;
    PORT
      LAYER M4 ;
        RECT  0 59.904 0.084 59.928 ;
    END
  END tk[458]
  PIN tk[459]
    DIRECTION INPUT ;
    USE SIGNAL ;
    PORT
      LAYER M4 ;
        RECT  0 60 0.084 60.024 ;
    END
  END tk[459]
  PIN tk[45]
    DIRECTION INPUT ;
    USE SIGNAL ;
    PORT
      LAYER M4 ;
        RECT  0 14.928 0.084 14.952 ;
    END
  END tk[45]
  PIN tk[460]
    DIRECTION INPUT ;
    USE SIGNAL ;
    PORT
      LAYER M4 ;
        RECT  0 60.144 0.084 60.168 ;
    END
  END tk[460]
  PIN tk[461]
    DIRECTION INPUT ;
    USE SIGNAL ;
    PORT
      LAYER M4 ;
        RECT  0 60.24 0.084 60.264 ;
    END
  END tk[461]
  PIN tk[462]
    DIRECTION INPUT ;
    USE SIGNAL ;
    PORT
      LAYER M4 ;
        RECT  0 60.336 0.084 60.36 ;
    END
  END tk[462]
  PIN tk[463]
    DIRECTION INPUT ;
    USE SIGNAL ;
    PORT
      LAYER M4 ;
        RECT  0 60.432 0.084 60.456 ;
    END
  END tk[463]
  PIN tk[464]
    DIRECTION INPUT ;
    USE SIGNAL ;
    PORT
      LAYER M4 ;
        RECT  0 60.576 0.084 60.6 ;
    END
  END tk[464]
  PIN tk[465]
    DIRECTION INPUT ;
    USE SIGNAL ;
    PORT
      LAYER M4 ;
        RECT  0 60.672 0.084 60.696 ;
    END
  END tk[465]
  PIN tk[466]
    DIRECTION INPUT ;
    USE SIGNAL ;
    PORT
      LAYER M4 ;
        RECT  0 60.768 0.084 60.792 ;
    END
  END tk[466]
  PIN tk[467]
    DIRECTION INPUT ;
    USE SIGNAL ;
    PORT
      LAYER M4 ;
        RECT  0 60.864 0.084 60.888 ;
    END
  END tk[467]
  PIN tk[468]
    DIRECTION INPUT ;
    USE SIGNAL ;
    PORT
      LAYER M4 ;
        RECT  0 61.008 0.084 61.032 ;
    END
  END tk[468]
  PIN tk[469]
    DIRECTION INPUT ;
    USE SIGNAL ;
    PORT
      LAYER M4 ;
        RECT  0 61.104 0.084 61.128 ;
    END
  END tk[469]
  PIN tk[46]
    DIRECTION INPUT ;
    USE SIGNAL ;
    PORT
      LAYER M4 ;
        RECT  0 15.072 0.084 15.096 ;
    END
  END tk[46]
  PIN tk[470]
    DIRECTION INPUT ;
    USE SIGNAL ;
    PORT
      LAYER M4 ;
        RECT  0 61.2 0.084 61.224 ;
    END
  END tk[470]
  PIN tk[471]
    DIRECTION INPUT ;
    USE SIGNAL ;
    PORT
      LAYER M4 ;
        RECT  0 61.344 0.084 61.368 ;
    END
  END tk[471]
  PIN tk[472]
    DIRECTION INPUT ;
    USE SIGNAL ;
    PORT
      LAYER M4 ;
        RECT  0 61.44 0.084 61.464 ;
    END
  END tk[472]
  PIN tk[473]
    DIRECTION INPUT ;
    USE SIGNAL ;
    PORT
      LAYER M4 ;
        RECT  0 61.536 0.084 61.56 ;
    END
  END tk[473]
  PIN tk[474]
    DIRECTION INPUT ;
    USE SIGNAL ;
    PORT
      LAYER M4 ;
        RECT  0 61.632 0.084 61.656 ;
    END
  END tk[474]
  PIN tk[475]
    DIRECTION INPUT ;
    USE SIGNAL ;
    PORT
      LAYER M4 ;
        RECT  0 61.776 0.084 61.8 ;
    END
  END tk[475]
  PIN tk[476]
    DIRECTION INPUT ;
    USE SIGNAL ;
    PORT
      LAYER M4 ;
        RECT  0 61.872 0.084 61.896 ;
    END
  END tk[476]
  PIN tk[477]
    DIRECTION INPUT ;
    USE SIGNAL ;
    PORT
      LAYER M4 ;
        RECT  0 61.968 0.084 61.992 ;
    END
  END tk[477]
  PIN tk[478]
    DIRECTION INPUT ;
    USE SIGNAL ;
    PORT
      LAYER M4 ;
        RECT  0 62.064 0.084 62.088 ;
    END
  END tk[478]
  PIN tk[479]
    DIRECTION INPUT ;
    USE SIGNAL ;
    PORT
      LAYER M4 ;
        RECT  0 62.208 0.084 62.232 ;
    END
  END tk[479]
  PIN tk[47]
    DIRECTION INPUT ;
    USE SIGNAL ;
    PORT
      LAYER M4 ;
        RECT  0 15.168 0.084 15.192 ;
    END
  END tk[47]
  PIN tk[480]
    DIRECTION INPUT ;
    USE SIGNAL ;
    PORT
      LAYER M4 ;
        RECT  0 62.304 0.084 62.328 ;
    END
  END tk[480]
  PIN tk[481]
    DIRECTION INPUT ;
    USE SIGNAL ;
    PORT
      LAYER M4 ;
        RECT  0 62.4 0.084 62.424 ;
    END
  END tk[481]
  PIN tk[482]
    DIRECTION INPUT ;
    USE SIGNAL ;
    PORT
      LAYER M4 ;
        RECT  0 62.496 0.084 62.52 ;
    END
  END tk[482]
  PIN tk[483]
    DIRECTION INPUT ;
    USE SIGNAL ;
    PORT
      LAYER M4 ;
        RECT  0 62.64 0.084 62.664 ;
    END
  END tk[483]
  PIN tk[484]
    DIRECTION INPUT ;
    USE SIGNAL ;
    PORT
      LAYER M4 ;
        RECT  0 62.736 0.084 62.76 ;
    END
  END tk[484]
  PIN tk[485]
    DIRECTION INPUT ;
    USE SIGNAL ;
    PORT
      LAYER M4 ;
        RECT  0 62.832 0.084 62.856 ;
    END
  END tk[485]
  PIN tk[486]
    DIRECTION INPUT ;
    USE SIGNAL ;
    PORT
      LAYER M4 ;
        RECT  0 62.976 0.084 63 ;
    END
  END tk[486]
  PIN tk[487]
    DIRECTION INPUT ;
    USE SIGNAL ;
    PORT
      LAYER M4 ;
        RECT  0 63.072 0.084 63.096 ;
    END
  END tk[487]
  PIN tk[488]
    DIRECTION INPUT ;
    USE SIGNAL ;
    PORT
      LAYER M4 ;
        RECT  0 63.168 0.084 63.192 ;
    END
  END tk[488]
  PIN tk[489]
    DIRECTION INPUT ;
    USE SIGNAL ;
    PORT
      LAYER M4 ;
        RECT  0 63.264 0.084 63.288 ;
    END
  END tk[489]
  PIN tk[48]
    DIRECTION INPUT ;
    USE SIGNAL ;
    PORT
      LAYER M4 ;
        RECT  0 15.264 0.084 15.288 ;
    END
  END tk[48]
  PIN tk[490]
    DIRECTION INPUT ;
    USE SIGNAL ;
    PORT
      LAYER M4 ;
        RECT  0 63.408 0.084 63.432 ;
    END
  END tk[490]
  PIN tk[491]
    DIRECTION INPUT ;
    USE SIGNAL ;
    PORT
      LAYER M4 ;
        RECT  0 63.504 0.084 63.528 ;
    END
  END tk[491]
  PIN tk[492]
    DIRECTION INPUT ;
    USE SIGNAL ;
    PORT
      LAYER M4 ;
        RECT  0 63.6 0.084 63.624 ;
    END
  END tk[492]
  PIN tk[493]
    DIRECTION INPUT ;
    USE SIGNAL ;
    PORT
      LAYER M4 ;
        RECT  0 63.696 0.084 63.72 ;
    END
  END tk[493]
  PIN tk[494]
    DIRECTION INPUT ;
    USE SIGNAL ;
    PORT
      LAYER M4 ;
        RECT  0 63.84 0.084 63.864 ;
    END
  END tk[494]
  PIN tk[495]
    DIRECTION INPUT ;
    USE SIGNAL ;
    PORT
      LAYER M4 ;
        RECT  0 63.936 0.084 63.96 ;
    END
  END tk[495]
  PIN tk[496]
    DIRECTION INPUT ;
    USE SIGNAL ;
    PORT
      LAYER M4 ;
        RECT  0 64.032 0.084 64.056 ;
    END
  END tk[496]
  PIN tk[497]
    DIRECTION INPUT ;
    USE SIGNAL ;
    PORT
      LAYER M4 ;
        RECT  0 64.128 0.084 64.152 ;
    END
  END tk[497]
  PIN tk[498]
    DIRECTION INPUT ;
    USE SIGNAL ;
    PORT
      LAYER M4 ;
        RECT  0 64.272 0.084 64.296 ;
    END
  END tk[498]
  PIN tk[499]
    DIRECTION INPUT ;
    USE SIGNAL ;
    PORT
      LAYER M4 ;
        RECT  0 64.368 0.084 64.392 ;
    END
  END tk[499]
  PIN tk[49]
    DIRECTION INPUT ;
    USE SIGNAL ;
    PORT
      LAYER M4 ;
        RECT  0 15.36 0.084 15.384 ;
    END
  END tk[49]
  PIN tk[4]
    DIRECTION INPUT ;
    USE SIGNAL ;
    PORT
      LAYER M4 ;
        RECT  0 10.464 0.084 10.488 ;
    END
  END tk[4]
  PIN tk[500]
    DIRECTION INPUT ;
    USE SIGNAL ;
    PORT
      LAYER M4 ;
        RECT  0 64.464 0.084 64.488 ;
    END
  END tk[500]
  PIN tk[501]
    DIRECTION INPUT ;
    USE SIGNAL ;
    PORT
      LAYER M4 ;
        RECT  0 64.608 0.084 64.632 ;
    END
  END tk[501]
  PIN tk[502]
    DIRECTION INPUT ;
    USE SIGNAL ;
    PORT
      LAYER M4 ;
        RECT  0 64.704 0.084 64.728 ;
    END
  END tk[502]
  PIN tk[503]
    DIRECTION INPUT ;
    USE SIGNAL ;
    PORT
      LAYER M4 ;
        RECT  0 64.8 0.084 64.824 ;
    END
  END tk[503]
  PIN tk[504]
    DIRECTION INPUT ;
    USE SIGNAL ;
    PORT
      LAYER M4 ;
        RECT  0 64.896 0.084 64.92 ;
    END
  END tk[504]
  PIN tk[505]
    DIRECTION INPUT ;
    USE SIGNAL ;
    PORT
      LAYER M4 ;
        RECT  0 65.04 0.084 65.064 ;
    END
  END tk[505]
  PIN tk[506]
    DIRECTION INPUT ;
    USE SIGNAL ;
    PORT
      LAYER M4 ;
        RECT  0 65.136 0.084 65.16 ;
    END
  END tk[506]
  PIN tk[507]
    DIRECTION INPUT ;
    USE SIGNAL ;
    PORT
      LAYER M4 ;
        RECT  0 65.232 0.084 65.256 ;
    END
  END tk[507]
  PIN tk[508]
    DIRECTION INPUT ;
    USE SIGNAL ;
    PORT
      LAYER M4 ;
        RECT  0 65.328 0.084 65.352 ;
    END
  END tk[508]
  PIN tk[509]
    DIRECTION INPUT ;
    USE SIGNAL ;
    PORT
      LAYER M4 ;
        RECT  0 65.472 0.084 65.496 ;
    END
  END tk[509]
  PIN tk[50]
    DIRECTION INPUT ;
    USE SIGNAL ;
    PORT
      LAYER M4 ;
        RECT  0 15.504 0.084 15.528 ;
    END
  END tk[50]
  PIN tk[510]
    DIRECTION INPUT ;
    USE SIGNAL ;
    PORT
      LAYER M4 ;
        RECT  0 65.568 0.084 65.592 ;
    END
  END tk[510]
  PIN tk[511]
    DIRECTION INPUT ;
    USE SIGNAL ;
    PORT
      LAYER M4 ;
        RECT  0 65.664 0.084 65.688 ;
    END
  END tk[511]
  PIN tk[512]
    DIRECTION INPUT ;
    USE SIGNAL ;
    PORT
      LAYER M4 ;
        RECT  0 65.808 0.084 65.832 ;
    END
  END tk[512]
  PIN tk[513]
    DIRECTION INPUT ;
    USE SIGNAL ;
    PORT
      LAYER M4 ;
        RECT  0 65.904 0.084 65.928 ;
    END
  END tk[513]
  PIN tk[514]
    DIRECTION INPUT ;
    USE SIGNAL ;
    PORT
      LAYER M4 ;
        RECT  0 66 0.084 66.024 ;
    END
  END tk[514]
  PIN tk[515]
    DIRECTION INPUT ;
    USE SIGNAL ;
    PORT
      LAYER M4 ;
        RECT  0 66.096 0.084 66.12 ;
    END
  END tk[515]
  PIN tk[516]
    DIRECTION INPUT ;
    USE SIGNAL ;
    PORT
      LAYER M4 ;
        RECT  0 66.24 0.084 66.264 ;
    END
  END tk[516]
  PIN tk[517]
    DIRECTION INPUT ;
    USE SIGNAL ;
    PORT
      LAYER M4 ;
        RECT  0 66.336 0.084 66.36 ;
    END
  END tk[517]
  PIN tk[518]
    DIRECTION INPUT ;
    USE SIGNAL ;
    PORT
      LAYER M4 ;
        RECT  0 66.432 0.084 66.456 ;
    END
  END tk[518]
  PIN tk[519]
    DIRECTION INPUT ;
    USE SIGNAL ;
    PORT
      LAYER M4 ;
        RECT  0 66.528 0.084 66.552 ;
    END
  END tk[519]
  PIN tk[51]
    DIRECTION INPUT ;
    USE SIGNAL ;
    PORT
      LAYER M4 ;
        RECT  0 15.6 0.084 15.624 ;
    END
  END tk[51]
  PIN tk[520]
    DIRECTION INPUT ;
    USE SIGNAL ;
    PORT
      LAYER M4 ;
        RECT  0 66.672 0.084 66.696 ;
    END
  END tk[520]
  PIN tk[521]
    DIRECTION INPUT ;
    USE SIGNAL ;
    PORT
      LAYER M4 ;
        RECT  0 66.768 0.084 66.792 ;
    END
  END tk[521]
  PIN tk[522]
    DIRECTION INPUT ;
    USE SIGNAL ;
    PORT
      LAYER M4 ;
        RECT  0 66.864 0.084 66.888 ;
    END
  END tk[522]
  PIN tk[523]
    DIRECTION INPUT ;
    USE SIGNAL ;
    PORT
      LAYER M4 ;
        RECT  0 66.96 0.084 66.984 ;
    END
  END tk[523]
  PIN tk[524]
    DIRECTION INPUT ;
    USE SIGNAL ;
    PORT
      LAYER M4 ;
        RECT  0 67.104 0.084 67.128 ;
    END
  END tk[524]
  PIN tk[525]
    DIRECTION INPUT ;
    USE SIGNAL ;
    PORT
      LAYER M4 ;
        RECT  0 67.2 0.084 67.224 ;
    END
  END tk[525]
  PIN tk[526]
    DIRECTION INPUT ;
    USE SIGNAL ;
    PORT
      LAYER M4 ;
        RECT  0 67.296 0.084 67.32 ;
    END
  END tk[526]
  PIN tk[527]
    DIRECTION INPUT ;
    USE SIGNAL ;
    PORT
      LAYER M4 ;
        RECT  0 67.44 0.084 67.464 ;
    END
  END tk[527]
  PIN tk[528]
    DIRECTION INPUT ;
    USE SIGNAL ;
    PORT
      LAYER M4 ;
        RECT  0 67.536 0.084 67.56 ;
    END
  END tk[528]
  PIN tk[529]
    DIRECTION INPUT ;
    USE SIGNAL ;
    PORT
      LAYER M4 ;
        RECT  0 67.632 0.084 67.656 ;
    END
  END tk[529]
  PIN tk[52]
    DIRECTION INPUT ;
    USE SIGNAL ;
    PORT
      LAYER M4 ;
        RECT  0 15.696 0.084 15.72 ;
    END
  END tk[52]
  PIN tk[530]
    DIRECTION INPUT ;
    USE SIGNAL ;
    PORT
      LAYER M4 ;
        RECT  0 67.728 0.084 67.752 ;
    END
  END tk[530]
  PIN tk[531]
    DIRECTION INPUT ;
    USE SIGNAL ;
    PORT
      LAYER M4 ;
        RECT  0 67.872 0.084 67.896 ;
    END
  END tk[531]
  PIN tk[532]
    DIRECTION INPUT ;
    USE SIGNAL ;
    PORT
      LAYER M4 ;
        RECT  0 67.968 0.084 67.992 ;
    END
  END tk[532]
  PIN tk[533]
    DIRECTION INPUT ;
    USE SIGNAL ;
    PORT
      LAYER M4 ;
        RECT  0 68.064 0.084 68.088 ;
    END
  END tk[533]
  PIN tk[534]
    DIRECTION INPUT ;
    USE SIGNAL ;
    PORT
      LAYER M4 ;
        RECT  0 68.16 0.084 68.184 ;
    END
  END tk[534]
  PIN tk[535]
    DIRECTION INPUT ;
    USE SIGNAL ;
    PORT
      LAYER M4 ;
        RECT  0 68.304 0.084 68.328 ;
    END
  END tk[535]
  PIN tk[536]
    DIRECTION INPUT ;
    USE SIGNAL ;
    PORT
      LAYER M4 ;
        RECT  0 68.4 0.084 68.424 ;
    END
  END tk[536]
  PIN tk[537]
    DIRECTION INPUT ;
    USE SIGNAL ;
    PORT
      LAYER M4 ;
        RECT  0 68.496 0.084 68.52 ;
    END
  END tk[537]
  PIN tk[538]
    DIRECTION INPUT ;
    USE SIGNAL ;
    PORT
      LAYER M4 ;
        RECT  0 68.592 0.084 68.616 ;
    END
  END tk[538]
  PIN tk[539]
    DIRECTION INPUT ;
    USE SIGNAL ;
    PORT
      LAYER M4 ;
        RECT  0 68.736 0.084 68.76 ;
    END
  END tk[539]
  PIN tk[53]
    DIRECTION INPUT ;
    USE SIGNAL ;
    PORT
      LAYER M4 ;
        RECT  0 15.792 0.084 15.816 ;
    END
  END tk[53]
  PIN tk[540]
    DIRECTION INPUT ;
    USE SIGNAL ;
    PORT
      LAYER M4 ;
        RECT  0 68.832 0.084 68.856 ;
    END
  END tk[540]
  PIN tk[541]
    DIRECTION INPUT ;
    USE SIGNAL ;
    PORT
      LAYER M4 ;
        RECT  0 68.928 0.084 68.952 ;
    END
  END tk[541]
  PIN tk[542]
    DIRECTION INPUT ;
    USE SIGNAL ;
    PORT
      LAYER M4 ;
        RECT  0 69.072 0.084 69.096 ;
    END
  END tk[542]
  PIN tk[543]
    DIRECTION INPUT ;
    USE SIGNAL ;
    PORT
      LAYER M4 ;
        RECT  0 69.168 0.084 69.192 ;
    END
  END tk[543]
  PIN tk[544]
    DIRECTION INPUT ;
    USE SIGNAL ;
    PORT
      LAYER M4 ;
        RECT  0 69.264 0.084 69.288 ;
    END
  END tk[544]
  PIN tk[545]
    DIRECTION INPUT ;
    USE SIGNAL ;
    PORT
      LAYER M4 ;
        RECT  0 69.36 0.084 69.384 ;
    END
  END tk[545]
  PIN tk[546]
    DIRECTION INPUT ;
    USE SIGNAL ;
    PORT
      LAYER M4 ;
        RECT  0 69.504 0.084 69.528 ;
    END
  END tk[546]
  PIN tk[547]
    DIRECTION INPUT ;
    USE SIGNAL ;
    PORT
      LAYER M4 ;
        RECT  0 69.6 0.084 69.624 ;
    END
  END tk[547]
  PIN tk[548]
    DIRECTION INPUT ;
    USE SIGNAL ;
    PORT
      LAYER M4 ;
        RECT  0 69.696 0.084 69.72 ;
    END
  END tk[548]
  PIN tk[549]
    DIRECTION INPUT ;
    USE SIGNAL ;
    PORT
      LAYER M4 ;
        RECT  0 69.792 0.084 69.816 ;
    END
  END tk[549]
  PIN tk[54]
    DIRECTION INPUT ;
    USE SIGNAL ;
    PORT
      LAYER M4 ;
        RECT  0 15.936 0.084 15.96 ;
    END
  END tk[54]
  PIN tk[550]
    DIRECTION INPUT ;
    USE SIGNAL ;
    PORT
      LAYER M4 ;
        RECT  0 69.936 0.084 69.96 ;
    END
  END tk[550]
  PIN tk[551]
    DIRECTION INPUT ;
    USE SIGNAL ;
    PORT
      LAYER M4 ;
        RECT  0 70.032 0.084 70.056 ;
    END
  END tk[551]
  PIN tk[552]
    DIRECTION INPUT ;
    USE SIGNAL ;
    PORT
      LAYER M4 ;
        RECT  0 70.128 0.084 70.152 ;
    END
  END tk[552]
  PIN tk[553]
    DIRECTION INPUT ;
    USE SIGNAL ;
    PORT
      LAYER M4 ;
        RECT  0 70.272 0.084 70.296 ;
    END
  END tk[553]
  PIN tk[554]
    DIRECTION INPUT ;
    USE SIGNAL ;
    PORT
      LAYER M4 ;
        RECT  0 70.368 0.084 70.392 ;
    END
  END tk[554]
  PIN tk[555]
    DIRECTION INPUT ;
    USE SIGNAL ;
    PORT
      LAYER M4 ;
        RECT  0 70.464 0.084 70.488 ;
    END
  END tk[555]
  PIN tk[556]
    DIRECTION INPUT ;
    USE SIGNAL ;
    PORT
      LAYER M4 ;
        RECT  0 70.56 0.084 70.584 ;
    END
  END tk[556]
  PIN tk[557]
    DIRECTION INPUT ;
    USE SIGNAL ;
    PORT
      LAYER M4 ;
        RECT  0 70.704 0.084 70.728 ;
    END
  END tk[557]
  PIN tk[558]
    DIRECTION INPUT ;
    USE SIGNAL ;
    PORT
      LAYER M4 ;
        RECT  0 70.8 0.084 70.824 ;
    END
  END tk[558]
  PIN tk[559]
    DIRECTION INPUT ;
    USE SIGNAL ;
    PORT
      LAYER M4 ;
        RECT  0 70.896 0.084 70.92 ;
    END
  END tk[559]
  PIN tk[55]
    DIRECTION INPUT ;
    USE SIGNAL ;
    PORT
      LAYER M4 ;
        RECT  0 16.032 0.084 16.056 ;
    END
  END tk[55]
  PIN tk[560]
    DIRECTION INPUT ;
    USE SIGNAL ;
    PORT
      LAYER M4 ;
        RECT  0 70.992 0.084 71.016 ;
    END
  END tk[560]
  PIN tk[561]
    DIRECTION INPUT ;
    USE SIGNAL ;
    PORT
      LAYER M4 ;
        RECT  0 71.136 0.084 71.16 ;
    END
  END tk[561]
  PIN tk[562]
    DIRECTION INPUT ;
    USE SIGNAL ;
    PORT
      LAYER M4 ;
        RECT  0 71.232 0.084 71.256 ;
    END
  END tk[562]
  PIN tk[563]
    DIRECTION INPUT ;
    USE SIGNAL ;
    PORT
      LAYER M4 ;
        RECT  0 71.328 0.084 71.352 ;
    END
  END tk[563]
  PIN tk[564]
    DIRECTION INPUT ;
    USE SIGNAL ;
    PORT
      LAYER M4 ;
        RECT  0 71.424 0.084 71.448 ;
    END
  END tk[564]
  PIN tk[565]
    DIRECTION INPUT ;
    USE SIGNAL ;
    PORT
      LAYER M4 ;
        RECT  0 71.568 0.084 71.592 ;
    END
  END tk[565]
  PIN tk[566]
    DIRECTION INPUT ;
    USE SIGNAL ;
    PORT
      LAYER M4 ;
        RECT  0 71.664 0.084 71.688 ;
    END
  END tk[566]
  PIN tk[567]
    DIRECTION INPUT ;
    USE SIGNAL ;
    PORT
      LAYER M4 ;
        RECT  0 71.76 0.084 71.784 ;
    END
  END tk[567]
  PIN tk[568]
    DIRECTION INPUT ;
    USE SIGNAL ;
    PORT
      LAYER M4 ;
        RECT  0 71.904 0.084 71.928 ;
    END
  END tk[568]
  PIN tk[569]
    DIRECTION INPUT ;
    USE SIGNAL ;
    PORT
      LAYER M4 ;
        RECT  0 72 0.084 72.024 ;
    END
  END tk[569]
  PIN tk[56]
    DIRECTION INPUT ;
    USE SIGNAL ;
    PORT
      LAYER M4 ;
        RECT  0 16.128 0.084 16.152 ;
    END
  END tk[56]
  PIN tk[570]
    DIRECTION INPUT ;
    USE SIGNAL ;
    PORT
      LAYER M4 ;
        RECT  0 72.096 0.084 72.12 ;
    END
  END tk[570]
  PIN tk[571]
    DIRECTION INPUT ;
    USE SIGNAL ;
    PORT
      LAYER M4 ;
        RECT  0 72.192 0.084 72.216 ;
    END
  END tk[571]
  PIN tk[572]
    DIRECTION INPUT ;
    USE SIGNAL ;
    PORT
      LAYER M4 ;
        RECT  0 72.336 0.084 72.36 ;
    END
  END tk[572]
  PIN tk[573]
    DIRECTION INPUT ;
    USE SIGNAL ;
    PORT
      LAYER M4 ;
        RECT  0 72.432 0.084 72.456 ;
    END
  END tk[573]
  PIN tk[574]
    DIRECTION INPUT ;
    USE SIGNAL ;
    PORT
      LAYER M4 ;
        RECT  0 72.528 0.084 72.552 ;
    END
  END tk[574]
  PIN tk[575]
    DIRECTION INPUT ;
    USE SIGNAL ;
    PORT
      LAYER M4 ;
        RECT  0 72.624 0.084 72.648 ;
    END
  END tk[575]
  PIN tk[576]
    DIRECTION INPUT ;
    USE SIGNAL ;
    PORT
      LAYER M4 ;
        RECT  0 72.768 0.084 72.792 ;
    END
  END tk[576]
  PIN tk[577]
    DIRECTION INPUT ;
    USE SIGNAL ;
    PORT
      LAYER M4 ;
        RECT  0 72.864 0.084 72.888 ;
    END
  END tk[577]
  PIN tk[578]
    DIRECTION INPUT ;
    USE SIGNAL ;
    PORT
      LAYER M4 ;
        RECT  0 72.96 0.084 72.984 ;
    END
  END tk[578]
  PIN tk[579]
    DIRECTION INPUT ;
    USE SIGNAL ;
    PORT
      LAYER M4 ;
        RECT  0 73.056 0.084 73.08 ;
    END
  END tk[579]
  PIN tk[57]
    DIRECTION INPUT ;
    USE SIGNAL ;
    PORT
      LAYER M4 ;
        RECT  0 16.272 0.084 16.296 ;
    END
  END tk[57]
  PIN tk[580]
    DIRECTION INPUT ;
    USE SIGNAL ;
    PORT
      LAYER M4 ;
        RECT  0 73.2 0.084 73.224 ;
    END
  END tk[580]
  PIN tk[581]
    DIRECTION INPUT ;
    USE SIGNAL ;
    PORT
      LAYER M4 ;
        RECT  0 73.296 0.084 73.32 ;
    END
  END tk[581]
  PIN tk[582]
    DIRECTION INPUT ;
    USE SIGNAL ;
    PORT
      LAYER M4 ;
        RECT  0 73.392 0.084 73.416 ;
    END
  END tk[582]
  PIN tk[583]
    DIRECTION INPUT ;
    USE SIGNAL ;
    PORT
      LAYER M4 ;
        RECT  0 73.536 0.084 73.56 ;
    END
  END tk[583]
  PIN tk[584]
    DIRECTION INPUT ;
    USE SIGNAL ;
    PORT
      LAYER M4 ;
        RECT  0 73.632 0.084 73.656 ;
    END
  END tk[584]
  PIN tk[585]
    DIRECTION INPUT ;
    USE SIGNAL ;
    PORT
      LAYER M4 ;
        RECT  0 73.728 0.084 73.752 ;
    END
  END tk[585]
  PIN tk[586]
    DIRECTION INPUT ;
    USE SIGNAL ;
    PORT
      LAYER M4 ;
        RECT  0 73.824 0.084 73.848 ;
    END
  END tk[586]
  PIN tk[587]
    DIRECTION INPUT ;
    USE SIGNAL ;
    PORT
      LAYER M4 ;
        RECT  0 73.968 0.084 73.992 ;
    END
  END tk[587]
  PIN tk[588]
    DIRECTION INPUT ;
    USE SIGNAL ;
    PORT
      LAYER M4 ;
        RECT  0 74.064 0.084 74.088 ;
    END
  END tk[588]
  PIN tk[589]
    DIRECTION INPUT ;
    USE SIGNAL ;
    PORT
      LAYER M4 ;
        RECT  0 74.16 0.084 74.184 ;
    END
  END tk[589]
  PIN tk[58]
    DIRECTION INPUT ;
    USE SIGNAL ;
    PORT
      LAYER M4 ;
        RECT  0 16.368 0.084 16.392 ;
    END
  END tk[58]
  PIN tk[590]
    DIRECTION INPUT ;
    USE SIGNAL ;
    PORT
      LAYER M4 ;
        RECT  0 74.256 0.084 74.28 ;
    END
  END tk[590]
  PIN tk[591]
    DIRECTION INPUT ;
    USE SIGNAL ;
    PORT
      LAYER M4 ;
        RECT  0 74.4 0.084 74.424 ;
    END
  END tk[591]
  PIN tk[592]
    DIRECTION INPUT ;
    USE SIGNAL ;
    PORT
      LAYER M4 ;
        RECT  0 74.496 0.084 74.52 ;
    END
  END tk[592]
  PIN tk[593]
    DIRECTION INPUT ;
    USE SIGNAL ;
    PORT
      LAYER M4 ;
        RECT  0 74.592 0.084 74.616 ;
    END
  END tk[593]
  PIN tk[594]
    DIRECTION INPUT ;
    USE SIGNAL ;
    PORT
      LAYER M4 ;
        RECT  0 74.736 0.084 74.76 ;
    END
  END tk[594]
  PIN tk[595]
    DIRECTION INPUT ;
    USE SIGNAL ;
    PORT
      LAYER M4 ;
        RECT  0 74.832 0.084 74.856 ;
    END
  END tk[595]
  PIN tk[596]
    DIRECTION INPUT ;
    USE SIGNAL ;
    PORT
      LAYER M4 ;
        RECT  0 74.928 0.084 74.952 ;
    END
  END tk[596]
  PIN tk[597]
    DIRECTION INPUT ;
    USE SIGNAL ;
    PORT
      LAYER M4 ;
        RECT  0 75.024 0.084 75.048 ;
    END
  END tk[597]
  PIN tk[598]
    DIRECTION INPUT ;
    USE SIGNAL ;
    PORT
      LAYER M4 ;
        RECT  0 75.168 0.084 75.192 ;
    END
  END tk[598]
  PIN tk[599]
    DIRECTION INPUT ;
    USE SIGNAL ;
    PORT
      LAYER M4 ;
        RECT  0 75.264 0.084 75.288 ;
    END
  END tk[599]
  PIN tk[59]
    DIRECTION INPUT ;
    USE SIGNAL ;
    PORT
      LAYER M4 ;
        RECT  0 16.464 0.084 16.488 ;
    END
  END tk[59]
  PIN tk[5]
    DIRECTION INPUT ;
    USE SIGNAL ;
    PORT
      LAYER M4 ;
        RECT  0 10.608 0.084 10.632 ;
    END
  END tk[5]
  PIN tk[600]
    DIRECTION INPUT ;
    USE SIGNAL ;
    PORT
      LAYER M4 ;
        RECT  0 75.36 0.084 75.384 ;
    END
  END tk[600]
  PIN tk[601]
    DIRECTION INPUT ;
    USE SIGNAL ;
    PORT
      LAYER M4 ;
        RECT  0 75.456 0.084 75.48 ;
    END
  END tk[601]
  PIN tk[602]
    DIRECTION INPUT ;
    USE SIGNAL ;
    PORT
      LAYER M4 ;
        RECT  0 75.6 0.084 75.624 ;
    END
  END tk[602]
  PIN tk[603]
    DIRECTION INPUT ;
    USE SIGNAL ;
    PORT
      LAYER M4 ;
        RECT  0 75.696 0.084 75.72 ;
    END
  END tk[603]
  PIN tk[604]
    DIRECTION INPUT ;
    USE SIGNAL ;
    PORT
      LAYER M4 ;
        RECT  0 75.792 0.084 75.816 ;
    END
  END tk[604]
  PIN tk[605]
    DIRECTION INPUT ;
    USE SIGNAL ;
    PORT
      LAYER M4 ;
        RECT  0 75.888 0.084 75.912 ;
    END
  END tk[605]
  PIN tk[606]
    DIRECTION INPUT ;
    USE SIGNAL ;
    PORT
      LAYER M4 ;
        RECT  0 76.032 0.084 76.056 ;
    END
  END tk[606]
  PIN tk[607]
    DIRECTION INPUT ;
    USE SIGNAL ;
    PORT
      LAYER M4 ;
        RECT  0 76.128 0.084 76.152 ;
    END
  END tk[607]
  PIN tk[608]
    DIRECTION INPUT ;
    USE SIGNAL ;
    PORT
      LAYER M4 ;
        RECT  0 76.224 0.084 76.248 ;
    END
  END tk[608]
  PIN tk[609]
    DIRECTION INPUT ;
    USE SIGNAL ;
    PORT
      LAYER M4 ;
        RECT  0 76.368 0.084 76.392 ;
    END
  END tk[609]
  PIN tk[60]
    DIRECTION INPUT ;
    USE SIGNAL ;
    PORT
      LAYER M4 ;
        RECT  0 16.56 0.084 16.584 ;
    END
  END tk[60]
  PIN tk[610]
    DIRECTION INPUT ;
    USE SIGNAL ;
    PORT
      LAYER M4 ;
        RECT  0 76.464 0.084 76.488 ;
    END
  END tk[610]
  PIN tk[611]
    DIRECTION INPUT ;
    USE SIGNAL ;
    PORT
      LAYER M4 ;
        RECT  0 76.56 0.084 76.584 ;
    END
  END tk[611]
  PIN tk[612]
    DIRECTION INPUT ;
    USE SIGNAL ;
    PORT
      LAYER M4 ;
        RECT  0 76.656 0.084 76.68 ;
    END
  END tk[612]
  PIN tk[613]
    DIRECTION INPUT ;
    USE SIGNAL ;
    PORT
      LAYER M4 ;
        RECT  0 76.8 0.084 76.824 ;
    END
  END tk[613]
  PIN tk[614]
    DIRECTION INPUT ;
    USE SIGNAL ;
    PORT
      LAYER M4 ;
        RECT  0 76.896 0.084 76.92 ;
    END
  END tk[614]
  PIN tk[615]
    DIRECTION INPUT ;
    USE SIGNAL ;
    PORT
      LAYER M4 ;
        RECT  0 76.992 0.084 77.016 ;
    END
  END tk[615]
  PIN tk[616]
    DIRECTION INPUT ;
    USE SIGNAL ;
    PORT
      LAYER M4 ;
        RECT  0 77.088 0.084 77.112 ;
    END
  END tk[616]
  PIN tk[617]
    DIRECTION INPUT ;
    USE SIGNAL ;
    PORT
      LAYER M4 ;
        RECT  0 77.232 0.084 77.256 ;
    END
  END tk[617]
  PIN tk[618]
    DIRECTION INPUT ;
    USE SIGNAL ;
    PORT
      LAYER M4 ;
        RECT  0 77.328 0.084 77.352 ;
    END
  END tk[618]
  PIN tk[619]
    DIRECTION INPUT ;
    USE SIGNAL ;
    PORT
      LAYER M4 ;
        RECT  0 77.424 0.084 77.448 ;
    END
  END tk[619]
  PIN tk[61]
    DIRECTION INPUT ;
    USE SIGNAL ;
    PORT
      LAYER M4 ;
        RECT  0 16.704 0.084 16.728 ;
    END
  END tk[61]
  PIN tk[620]
    DIRECTION INPUT ;
    USE SIGNAL ;
    PORT
      LAYER M4 ;
        RECT  0 77.52 0.084 77.544 ;
    END
  END tk[620]
  PIN tk[621]
    DIRECTION INPUT ;
    USE SIGNAL ;
    PORT
      LAYER M4 ;
        RECT  0 77.664 0.084 77.688 ;
    END
  END tk[621]
  PIN tk[622]
    DIRECTION INPUT ;
    USE SIGNAL ;
    PORT
      LAYER M4 ;
        RECT  0 77.76 0.084 77.784 ;
    END
  END tk[622]
  PIN tk[623]
    DIRECTION INPUT ;
    USE SIGNAL ;
    PORT
      LAYER M4 ;
        RECT  0 77.856 0.084 77.88 ;
    END
  END tk[623]
  PIN tk[624]
    DIRECTION INPUT ;
    USE SIGNAL ;
    PORT
      LAYER M4 ;
        RECT  0 78 0.084 78.024 ;
    END
  END tk[624]
  PIN tk[625]
    DIRECTION INPUT ;
    USE SIGNAL ;
    PORT
      LAYER M4 ;
        RECT  0 78.096 0.084 78.12 ;
    END
  END tk[625]
  PIN tk[626]
    DIRECTION INPUT ;
    USE SIGNAL ;
    PORT
      LAYER M4 ;
        RECT  0 78.192 0.084 78.216 ;
    END
  END tk[626]
  PIN tk[627]
    DIRECTION INPUT ;
    USE SIGNAL ;
    PORT
      LAYER M4 ;
        RECT  0 78.288 0.084 78.312 ;
    END
  END tk[627]
  PIN tk[628]
    DIRECTION INPUT ;
    USE SIGNAL ;
    PORT
      LAYER M4 ;
        RECT  0 78.432 0.084 78.456 ;
    END
  END tk[628]
  PIN tk[629]
    DIRECTION INPUT ;
    USE SIGNAL ;
    PORT
      LAYER M4 ;
        RECT  0 78.528 0.084 78.552 ;
    END
  END tk[629]
  PIN tk[62]
    DIRECTION INPUT ;
    USE SIGNAL ;
    PORT
      LAYER M4 ;
        RECT  0 16.8 0.084 16.824 ;
    END
  END tk[62]
  PIN tk[630]
    DIRECTION INPUT ;
    USE SIGNAL ;
    PORT
      LAYER M4 ;
        RECT  0 78.624 0.084 78.648 ;
    END
  END tk[630]
  PIN tk[631]
    DIRECTION INPUT ;
    USE SIGNAL ;
    PORT
      LAYER M4 ;
        RECT  0 78.72 0.084 78.744 ;
    END
  END tk[631]
  PIN tk[632]
    DIRECTION INPUT ;
    USE SIGNAL ;
    PORT
      LAYER M4 ;
        RECT  0 78.864 0.084 78.888 ;
    END
  END tk[632]
  PIN tk[633]
    DIRECTION INPUT ;
    USE SIGNAL ;
    PORT
      LAYER M4 ;
        RECT  0 78.96 0.084 78.984 ;
    END
  END tk[633]
  PIN tk[634]
    DIRECTION INPUT ;
    USE SIGNAL ;
    PORT
      LAYER M4 ;
        RECT  0 79.056 0.084 79.08 ;
    END
  END tk[634]
  PIN tk[635]
    DIRECTION INPUT ;
    USE SIGNAL ;
    PORT
      LAYER M4 ;
        RECT  0 79.2 0.084 79.224 ;
    END
  END tk[635]
  PIN tk[636]
    DIRECTION INPUT ;
    USE SIGNAL ;
    PORT
      LAYER M4 ;
        RECT  0 79.296 0.084 79.32 ;
    END
  END tk[636]
  PIN tk[637]
    DIRECTION INPUT ;
    USE SIGNAL ;
    PORT
      LAYER M4 ;
        RECT  0 79.392 0.084 79.416 ;
    END
  END tk[637]
  PIN tk[638]
    DIRECTION INPUT ;
    USE SIGNAL ;
    PORT
      LAYER M4 ;
        RECT  0 79.488 0.084 79.512 ;
    END
  END tk[638]
  PIN tk[639]
    DIRECTION INPUT ;
    USE SIGNAL ;
    PORT
      LAYER M4 ;
        RECT  0 79.632 0.084 79.656 ;
    END
  END tk[639]
  PIN tk[63]
    DIRECTION INPUT ;
    USE SIGNAL ;
    PORT
      LAYER M4 ;
        RECT  0 16.896 0.084 16.92 ;
    END
  END tk[63]
  PIN tk[640]
    DIRECTION INPUT ;
    USE SIGNAL ;
    PORT
      LAYER M4 ;
        RECT  0 79.728 0.084 79.752 ;
    END
  END tk[640]
  PIN tk[641]
    DIRECTION INPUT ;
    USE SIGNAL ;
    PORT
      LAYER M4 ;
        RECT  0 79.824 0.084 79.848 ;
    END
  END tk[641]
  PIN tk[642]
    DIRECTION INPUT ;
    USE SIGNAL ;
    PORT
      LAYER M4 ;
        RECT  0 79.92 0.084 79.944 ;
    END
  END tk[642]
  PIN tk[643]
    DIRECTION INPUT ;
    USE SIGNAL ;
    PORT
      LAYER M4 ;
        RECT  0 80.064 0.084 80.088 ;
    END
  END tk[643]
  PIN tk[644]
    DIRECTION INPUT ;
    USE SIGNAL ;
    PORT
      LAYER M4 ;
        RECT  0 80.16 0.084 80.184 ;
    END
  END tk[644]
  PIN tk[645]
    DIRECTION INPUT ;
    USE SIGNAL ;
    PORT
      LAYER M4 ;
        RECT  0 80.256 0.084 80.28 ;
    END
  END tk[645]
  PIN tk[646]
    DIRECTION INPUT ;
    USE SIGNAL ;
    PORT
      LAYER M4 ;
        RECT  0 80.352 0.084 80.376 ;
    END
  END tk[646]
  PIN tk[647]
    DIRECTION INPUT ;
    USE SIGNAL ;
    PORT
      LAYER M4 ;
        RECT  0 80.496 0.084 80.52 ;
    END
  END tk[647]
  PIN tk[648]
    DIRECTION INPUT ;
    USE SIGNAL ;
    PORT
      LAYER M4 ;
        RECT  0 80.592 0.084 80.616 ;
    END
  END tk[648]
  PIN tk[649]
    DIRECTION INPUT ;
    USE SIGNAL ;
    PORT
      LAYER M4 ;
        RECT  0 80.688 0.084 80.712 ;
    END
  END tk[649]
  PIN tk[64]
    DIRECTION INPUT ;
    USE SIGNAL ;
    PORT
      LAYER M4 ;
        RECT  0 16.992 0.084 17.016 ;
    END
  END tk[64]
  PIN tk[650]
    DIRECTION INPUT ;
    USE SIGNAL ;
    PORT
      LAYER M4 ;
        RECT  0 80.832 0.084 80.856 ;
    END
  END tk[650]
  PIN tk[651]
    DIRECTION INPUT ;
    USE SIGNAL ;
    PORT
      LAYER M4 ;
        RECT  0 80.928 0.084 80.952 ;
    END
  END tk[651]
  PIN tk[652]
    DIRECTION INPUT ;
    USE SIGNAL ;
    PORT
      LAYER M4 ;
        RECT  0 81.024 0.084 81.048 ;
    END
  END tk[652]
  PIN tk[653]
    DIRECTION INPUT ;
    USE SIGNAL ;
    PORT
      LAYER M4 ;
        RECT  0 81.12 0.084 81.144 ;
    END
  END tk[653]
  PIN tk[654]
    DIRECTION INPUT ;
    USE SIGNAL ;
    PORT
      LAYER M4 ;
        RECT  0 81.264 0.084 81.288 ;
    END
  END tk[654]
  PIN tk[655]
    DIRECTION INPUT ;
    USE SIGNAL ;
    PORT
      LAYER M4 ;
        RECT  0 81.36 0.084 81.384 ;
    END
  END tk[655]
  PIN tk[656]
    DIRECTION INPUT ;
    USE SIGNAL ;
    PORT
      LAYER M4 ;
        RECT  0 81.456 0.084 81.48 ;
    END
  END tk[656]
  PIN tk[657]
    DIRECTION INPUT ;
    USE SIGNAL ;
    PORT
      LAYER M4 ;
        RECT  0 81.552 0.084 81.576 ;
    END
  END tk[657]
  PIN tk[658]
    DIRECTION INPUT ;
    USE SIGNAL ;
    PORT
      LAYER M4 ;
        RECT  0 81.696 0.084 81.72 ;
    END
  END tk[658]
  PIN tk[659]
    DIRECTION INPUT ;
    USE SIGNAL ;
    PORT
      LAYER M4 ;
        RECT  0 81.792 0.084 81.816 ;
    END
  END tk[659]
  PIN tk[65]
    DIRECTION INPUT ;
    USE SIGNAL ;
    PORT
      LAYER M4 ;
        RECT  0 17.136 0.084 17.16 ;
    END
  END tk[65]
  PIN tk[660]
    DIRECTION INPUT ;
    USE SIGNAL ;
    PORT
      LAYER M4 ;
        RECT  0 81.888 0.084 81.912 ;
    END
  END tk[660]
  PIN tk[661]
    DIRECTION INPUT ;
    USE SIGNAL ;
    PORT
      LAYER M4 ;
        RECT  0 81.984 0.084 82.008 ;
    END
  END tk[661]
  PIN tk[662]
    DIRECTION INPUT ;
    USE SIGNAL ;
    PORT
      LAYER M4 ;
        RECT  0 82.128 0.084 82.152 ;
    END
  END tk[662]
  PIN tk[663]
    DIRECTION INPUT ;
    USE SIGNAL ;
    PORT
      LAYER M4 ;
        RECT  0 82.224 0.084 82.248 ;
    END
  END tk[663]
  PIN tk[664]
    DIRECTION INPUT ;
    USE SIGNAL ;
    PORT
      LAYER M4 ;
        RECT  0 82.32 0.084 82.344 ;
    END
  END tk[664]
  PIN tk[665]
    DIRECTION INPUT ;
    USE SIGNAL ;
    PORT
      LAYER M4 ;
        RECT  0 82.464 0.084 82.488 ;
    END
  END tk[665]
  PIN tk[666]
    DIRECTION INPUT ;
    USE SIGNAL ;
    PORT
      LAYER M4 ;
        RECT  0 82.56 0.084 82.584 ;
    END
  END tk[666]
  PIN tk[667]
    DIRECTION INPUT ;
    USE SIGNAL ;
    PORT
      LAYER M4 ;
        RECT  0 82.656 0.084 82.68 ;
    END
  END tk[667]
  PIN tk[668]
    DIRECTION INPUT ;
    USE SIGNAL ;
    PORT
      LAYER M4 ;
        RECT  0 82.752 0.084 82.776 ;
    END
  END tk[668]
  PIN tk[669]
    DIRECTION INPUT ;
    USE SIGNAL ;
    PORT
      LAYER M4 ;
        RECT  0 82.896 0.084 82.92 ;
    END
  END tk[669]
  PIN tk[66]
    DIRECTION INPUT ;
    USE SIGNAL ;
    PORT
      LAYER M4 ;
        RECT  0 17.232 0.084 17.256 ;
    END
  END tk[66]
  PIN tk[670]
    DIRECTION INPUT ;
    USE SIGNAL ;
    PORT
      LAYER M4 ;
        RECT  0 82.992 0.084 83.016 ;
    END
  END tk[670]
  PIN tk[671]
    DIRECTION INPUT ;
    USE SIGNAL ;
    PORT
      LAYER M4 ;
        RECT  0 83.088 0.084 83.112 ;
    END
  END tk[671]
  PIN tk[672]
    DIRECTION INPUT ;
    USE SIGNAL ;
    PORT
      LAYER M4 ;
        RECT  0 83.184 0.084 83.208 ;
    END
  END tk[672]
  PIN tk[673]
    DIRECTION INPUT ;
    USE SIGNAL ;
    PORT
      LAYER M4 ;
        RECT  0 83.328 0.084 83.352 ;
    END
  END tk[673]
  PIN tk[674]
    DIRECTION INPUT ;
    USE SIGNAL ;
    PORT
      LAYER M4 ;
        RECT  0 83.424 0.084 83.448 ;
    END
  END tk[674]
  PIN tk[675]
    DIRECTION INPUT ;
    USE SIGNAL ;
    PORT
      LAYER M4 ;
        RECT  0 83.52 0.084 83.544 ;
    END
  END tk[675]
  PIN tk[676]
    DIRECTION INPUT ;
    USE SIGNAL ;
    PORT
      LAYER M4 ;
        RECT  0 83.616 0.084 83.64 ;
    END
  END tk[676]
  PIN tk[677]
    DIRECTION INPUT ;
    USE SIGNAL ;
    PORT
      LAYER M4 ;
        RECT  0 83.76 0.084 83.784 ;
    END
  END tk[677]
  PIN tk[678]
    DIRECTION INPUT ;
    USE SIGNAL ;
    PORT
      LAYER M4 ;
        RECT  0 83.856 0.084 83.88 ;
    END
  END tk[678]
  PIN tk[679]
    DIRECTION INPUT ;
    USE SIGNAL ;
    PORT
      LAYER M4 ;
        RECT  0 83.952 0.084 83.976 ;
    END
  END tk[679]
  PIN tk[67]
    DIRECTION INPUT ;
    USE SIGNAL ;
    PORT
      LAYER M4 ;
        RECT  0 17.328 0.084 17.352 ;
    END
  END tk[67]
  PIN tk[680]
    DIRECTION INPUT ;
    USE SIGNAL ;
    PORT
      LAYER M4 ;
        RECT  0 84.096 0.084 84.12 ;
    END
  END tk[680]
  PIN tk[681]
    DIRECTION INPUT ;
    USE SIGNAL ;
    PORT
      LAYER M4 ;
        RECT  0 84.192 0.084 84.216 ;
    END
  END tk[681]
  PIN tk[682]
    DIRECTION INPUT ;
    USE SIGNAL ;
    PORT
      LAYER M4 ;
        RECT  0 84.288 0.084 84.312 ;
    END
  END tk[682]
  PIN tk[683]
    DIRECTION INPUT ;
    USE SIGNAL ;
    PORT
      LAYER M4 ;
        RECT  0 84.384 0.084 84.408 ;
    END
  END tk[683]
  PIN tk[684]
    DIRECTION INPUT ;
    USE SIGNAL ;
    PORT
      LAYER M4 ;
        RECT  0 84.528 0.084 84.552 ;
    END
  END tk[684]
  PIN tk[685]
    DIRECTION INPUT ;
    USE SIGNAL ;
    PORT
      LAYER M4 ;
        RECT  0 84.624 0.084 84.648 ;
    END
  END tk[685]
  PIN tk[686]
    DIRECTION INPUT ;
    USE SIGNAL ;
    PORT
      LAYER M4 ;
        RECT  0 84.72 0.084 84.744 ;
    END
  END tk[686]
  PIN tk[687]
    DIRECTION INPUT ;
    USE SIGNAL ;
    PORT
      LAYER M4 ;
        RECT  0 84.816 0.084 84.84 ;
    END
  END tk[687]
  PIN tk[688]
    DIRECTION INPUT ;
    USE SIGNAL ;
    PORT
      LAYER M4 ;
        RECT  0 84.96 0.084 84.984 ;
    END
  END tk[688]
  PIN tk[689]
    DIRECTION INPUT ;
    USE SIGNAL ;
    PORT
      LAYER M4 ;
        RECT  0 85.056 0.084 85.08 ;
    END
  END tk[689]
  PIN tk[68]
    DIRECTION INPUT ;
    USE SIGNAL ;
    PORT
      LAYER M4 ;
        RECT  0 17.424 0.084 17.448 ;
    END
  END tk[68]
  PIN tk[690]
    DIRECTION INPUT ;
    USE SIGNAL ;
    PORT
      LAYER M4 ;
        RECT  0 85.152 0.084 85.176 ;
    END
  END tk[690]
  PIN tk[691]
    DIRECTION INPUT ;
    USE SIGNAL ;
    PORT
      LAYER M4 ;
        RECT  0 85.296 0.084 85.32 ;
    END
  END tk[691]
  PIN tk[692]
    DIRECTION INPUT ;
    USE SIGNAL ;
    PORT
      LAYER M4 ;
        RECT  0 85.392 0.084 85.416 ;
    END
  END tk[692]
  PIN tk[693]
    DIRECTION INPUT ;
    USE SIGNAL ;
    PORT
      LAYER M4 ;
        RECT  0 85.488 0.084 85.512 ;
    END
  END tk[693]
  PIN tk[694]
    DIRECTION INPUT ;
    USE SIGNAL ;
    PORT
      LAYER M4 ;
        RECT  0 85.584 0.084 85.608 ;
    END
  END tk[694]
  PIN tk[695]
    DIRECTION INPUT ;
    USE SIGNAL ;
    PORT
      LAYER M4 ;
        RECT  0 85.728 0.084 85.752 ;
    END
  END tk[695]
  PIN tk[696]
    DIRECTION INPUT ;
    USE SIGNAL ;
    PORT
      LAYER M4 ;
        RECT  0 85.824 0.084 85.848 ;
    END
  END tk[696]
  PIN tk[697]
    DIRECTION INPUT ;
    USE SIGNAL ;
    PORT
      LAYER M4 ;
        RECT  0 85.92 0.084 85.944 ;
    END
  END tk[697]
  PIN tk[698]
    DIRECTION INPUT ;
    USE SIGNAL ;
    PORT
      LAYER M4 ;
        RECT  0 86.016 0.084 86.04 ;
    END
  END tk[698]
  PIN tk[699]
    DIRECTION INPUT ;
    USE SIGNAL ;
    PORT
      LAYER M4 ;
        RECT  0 86.16 0.084 86.184 ;
    END
  END tk[699]
  PIN tk[69]
    DIRECTION INPUT ;
    USE SIGNAL ;
    PORT
      LAYER M4 ;
        RECT  0 17.568 0.084 17.592 ;
    END
  END tk[69]
  PIN tk[6]
    DIRECTION INPUT ;
    USE SIGNAL ;
    PORT
      LAYER M4 ;
        RECT  0 10.704 0.084 10.728 ;
    END
  END tk[6]
  PIN tk[700]
    DIRECTION INPUT ;
    USE SIGNAL ;
    PORT
      LAYER M4 ;
        RECT  0 86.256 0.084 86.28 ;
    END
  END tk[700]
  PIN tk[701]
    DIRECTION INPUT ;
    USE SIGNAL ;
    PORT
      LAYER M4 ;
        RECT  0 86.352 0.084 86.376 ;
    END
  END tk[701]
  PIN tk[702]
    DIRECTION INPUT ;
    USE SIGNAL ;
    PORT
      LAYER M4 ;
        RECT  0 86.448 0.084 86.472 ;
    END
  END tk[702]
  PIN tk[703]
    DIRECTION INPUT ;
    USE SIGNAL ;
    PORT
      LAYER M4 ;
        RECT  0 86.592 0.084 86.616 ;
    END
  END tk[703]
  PIN tk[704]
    DIRECTION INPUT ;
    USE SIGNAL ;
    PORT
      LAYER M4 ;
        RECT  0 86.688 0.084 86.712 ;
    END
  END tk[704]
  PIN tk[705]
    DIRECTION INPUT ;
    USE SIGNAL ;
    PORT
      LAYER M4 ;
        RECT  0 86.784 0.084 86.808 ;
    END
  END tk[705]
  PIN tk[706]
    DIRECTION INPUT ;
    USE SIGNAL ;
    PORT
      LAYER M4 ;
        RECT  0 86.928 0.084 86.952 ;
    END
  END tk[706]
  PIN tk[707]
    DIRECTION INPUT ;
    USE SIGNAL ;
    PORT
      LAYER M4 ;
        RECT  0 87.024 0.084 87.048 ;
    END
  END tk[707]
  PIN tk[708]
    DIRECTION INPUT ;
    USE SIGNAL ;
    PORT
      LAYER M4 ;
        RECT  0 87.12 0.084 87.144 ;
    END
  END tk[708]
  PIN tk[709]
    DIRECTION INPUT ;
    USE SIGNAL ;
    PORT
      LAYER M4 ;
        RECT  0 87.216 0.084 87.24 ;
    END
  END tk[709]
  PIN tk[70]
    DIRECTION INPUT ;
    USE SIGNAL ;
    PORT
      LAYER M4 ;
        RECT  0 17.664 0.084 17.688 ;
    END
  END tk[70]
  PIN tk[710]
    DIRECTION INPUT ;
    USE SIGNAL ;
    PORT
      LAYER M4 ;
        RECT  0 87.36 0.084 87.384 ;
    END
  END tk[710]
  PIN tk[711]
    DIRECTION INPUT ;
    USE SIGNAL ;
    PORT
      LAYER M4 ;
        RECT  0 87.456 0.084 87.48 ;
    END
  END tk[711]
  PIN tk[712]
    DIRECTION INPUT ;
    USE SIGNAL ;
    PORT
      LAYER M4 ;
        RECT  0 87.552 0.084 87.576 ;
    END
  END tk[712]
  PIN tk[713]
    DIRECTION INPUT ;
    USE SIGNAL ;
    PORT
      LAYER M4 ;
        RECT  0 87.648 0.084 87.672 ;
    END
  END tk[713]
  PIN tk[714]
    DIRECTION INPUT ;
    USE SIGNAL ;
    PORT
      LAYER M4 ;
        RECT  0 87.792 0.084 87.816 ;
    END
  END tk[714]
  PIN tk[715]
    DIRECTION INPUT ;
    USE SIGNAL ;
    PORT
      LAYER M4 ;
        RECT  0 87.888 0.084 87.912 ;
    END
  END tk[715]
  PIN tk[716]
    DIRECTION INPUT ;
    USE SIGNAL ;
    PORT
      LAYER M4 ;
        RECT  0 87.984 0.084 88.008 ;
    END
  END tk[716]
  PIN tk[717]
    DIRECTION INPUT ;
    USE SIGNAL ;
    PORT
      LAYER M4 ;
        RECT  0 88.08 0.084 88.104 ;
    END
  END tk[717]
  PIN tk[718]
    DIRECTION INPUT ;
    USE SIGNAL ;
    PORT
      LAYER M4 ;
        RECT  0 88.224 0.084 88.248 ;
    END
  END tk[718]
  PIN tk[719]
    DIRECTION INPUT ;
    USE SIGNAL ;
    PORT
      LAYER M4 ;
        RECT  0 88.32 0.084 88.344 ;
    END
  END tk[719]
  PIN tk[71]
    DIRECTION INPUT ;
    USE SIGNAL ;
    PORT
      LAYER M4 ;
        RECT  0 17.76 0.084 17.784 ;
    END
  END tk[71]
  PIN tk[720]
    DIRECTION INPUT ;
    USE SIGNAL ;
    PORT
      LAYER M4 ;
        RECT  0 88.416 0.084 88.44 ;
    END
  END tk[720]
  PIN tk[721]
    DIRECTION INPUT ;
    USE SIGNAL ;
    PORT
      LAYER M4 ;
        RECT  0 88.56 0.084 88.584 ;
    END
  END tk[721]
  PIN tk[722]
    DIRECTION INPUT ;
    USE SIGNAL ;
    PORT
      LAYER M4 ;
        RECT  0 88.656 0.084 88.68 ;
    END
  END tk[722]
  PIN tk[723]
    DIRECTION INPUT ;
    USE SIGNAL ;
    PORT
      LAYER M4 ;
        RECT  0 88.752 0.084 88.776 ;
    END
  END tk[723]
  PIN tk[724]
    DIRECTION INPUT ;
    USE SIGNAL ;
    PORT
      LAYER M4 ;
        RECT  0 88.848 0.084 88.872 ;
    END
  END tk[724]
  PIN tk[725]
    DIRECTION INPUT ;
    USE SIGNAL ;
    PORT
      LAYER M4 ;
        RECT  0 88.992 0.084 89.016 ;
    END
  END tk[725]
  PIN tk[726]
    DIRECTION INPUT ;
    USE SIGNAL ;
    PORT
      LAYER M4 ;
        RECT  0 89.088 0.084 89.112 ;
    END
  END tk[726]
  PIN tk[727]
    DIRECTION INPUT ;
    USE SIGNAL ;
    PORT
      LAYER M4 ;
        RECT  0 89.184 0.084 89.208 ;
    END
  END tk[727]
  PIN tk[728]
    DIRECTION INPUT ;
    USE SIGNAL ;
    PORT
      LAYER M4 ;
        RECT  0 89.28 0.084 89.304 ;
    END
  END tk[728]
  PIN tk[729]
    DIRECTION INPUT ;
    USE SIGNAL ;
    PORT
      LAYER M4 ;
        RECT  0 89.424 0.084 89.448 ;
    END
  END tk[729]
  PIN tk[72]
    DIRECTION INPUT ;
    USE SIGNAL ;
    PORT
      LAYER M4 ;
        RECT  0 17.904 0.084 17.928 ;
    END
  END tk[72]
  PIN tk[730]
    DIRECTION INPUT ;
    USE SIGNAL ;
    PORT
      LAYER M4 ;
        RECT  0 89.52 0.084 89.544 ;
    END
  END tk[730]
  PIN tk[731]
    DIRECTION INPUT ;
    USE SIGNAL ;
    PORT
      LAYER M4 ;
        RECT  0 89.616 0.084 89.64 ;
    END
  END tk[731]
  PIN tk[732]
    DIRECTION INPUT ;
    USE SIGNAL ;
    PORT
      LAYER M4 ;
        RECT  0 89.76 0.084 89.784 ;
    END
  END tk[732]
  PIN tk[733]
    DIRECTION INPUT ;
    USE SIGNAL ;
    PORT
      LAYER M4 ;
        RECT  0 89.856 0.084 89.88 ;
    END
  END tk[733]
  PIN tk[734]
    DIRECTION INPUT ;
    USE SIGNAL ;
    PORT
      LAYER M4 ;
        RECT  0 89.952 0.084 89.976 ;
    END
  END tk[734]
  PIN tk[735]
    DIRECTION INPUT ;
    USE SIGNAL ;
    PORT
      LAYER M4 ;
        RECT  0 90.048 0.084 90.072 ;
    END
  END tk[735]
  PIN tk[736]
    DIRECTION INPUT ;
    USE SIGNAL ;
    PORT
      LAYER M4 ;
        RECT  0 90.192 0.084 90.216 ;
    END
  END tk[736]
  PIN tk[737]
    DIRECTION INPUT ;
    USE SIGNAL ;
    PORT
      LAYER M4 ;
        RECT  0 90.288 0.084 90.312 ;
    END
  END tk[737]
  PIN tk[738]
    DIRECTION INPUT ;
    USE SIGNAL ;
    PORT
      LAYER M4 ;
        RECT  0 90.384 0.084 90.408 ;
    END
  END tk[738]
  PIN tk[739]
    DIRECTION INPUT ;
    USE SIGNAL ;
    PORT
      LAYER M4 ;
        RECT  0 90.48 0.084 90.504 ;
    END
  END tk[739]
  PIN tk[73]
    DIRECTION INPUT ;
    USE SIGNAL ;
    PORT
      LAYER M4 ;
        RECT  0 18 0.084 18.024 ;
    END
  END tk[73]
  PIN tk[740]
    DIRECTION INPUT ;
    USE SIGNAL ;
    PORT
      LAYER M4 ;
        RECT  0 90.624 0.084 90.648 ;
    END
  END tk[740]
  PIN tk[741]
    DIRECTION INPUT ;
    USE SIGNAL ;
    PORT
      LAYER M4 ;
        RECT  0 90.72 0.084 90.744 ;
    END
  END tk[741]
  PIN tk[742]
    DIRECTION INPUT ;
    USE SIGNAL ;
    PORT
      LAYER M4 ;
        RECT  0 90.816 0.084 90.84 ;
    END
  END tk[742]
  PIN tk[743]
    DIRECTION INPUT ;
    USE SIGNAL ;
    PORT
      LAYER M4 ;
        RECT  0 90.912 0.084 90.936 ;
    END
  END tk[743]
  PIN tk[74]
    DIRECTION INPUT ;
    USE SIGNAL ;
    PORT
      LAYER M4 ;
        RECT  0 18.096 0.084 18.12 ;
    END
  END tk[74]
  PIN tk[75]
    DIRECTION INPUT ;
    USE SIGNAL ;
    PORT
      LAYER M4 ;
        RECT  0 18.192 0.084 18.216 ;
    END
  END tk[75]
  PIN tk[76]
    DIRECTION INPUT ;
    USE SIGNAL ;
    PORT
      LAYER M4 ;
        RECT  0 18.336 0.084 18.36 ;
    END
  END tk[76]
  PIN tk[77]
    DIRECTION INPUT ;
    USE SIGNAL ;
    PORT
      LAYER M4 ;
        RECT  0 18.432 0.084 18.456 ;
    END
  END tk[77]
  PIN tk[78]
    DIRECTION INPUT ;
    USE SIGNAL ;
    PORT
      LAYER M4 ;
        RECT  0 18.528 0.084 18.552 ;
    END
  END tk[78]
  PIN tk[79]
    DIRECTION INPUT ;
    USE SIGNAL ;
    PORT
      LAYER M4 ;
        RECT  0 18.624 0.084 18.648 ;
    END
  END tk[79]
  PIN tk[7]
    DIRECTION INPUT ;
    USE SIGNAL ;
    PORT
      LAYER M4 ;
        RECT  0 10.8 0.084 10.824 ;
    END
  END tk[7]
  PIN tk[80]
    DIRECTION INPUT ;
    USE SIGNAL ;
    PORT
      LAYER M4 ;
        RECT  0 18.768 0.084 18.792 ;
    END
  END tk[80]
  PIN tk[81]
    DIRECTION INPUT ;
    USE SIGNAL ;
    PORT
      LAYER M4 ;
        RECT  0 18.864 0.084 18.888 ;
    END
  END tk[81]
  PIN tk[82]
    DIRECTION INPUT ;
    USE SIGNAL ;
    PORT
      LAYER M4 ;
        RECT  0 18.96 0.084 18.984 ;
    END
  END tk[82]
  PIN tk[83]
    DIRECTION INPUT ;
    USE SIGNAL ;
    PORT
      LAYER M4 ;
        RECT  0 19.056 0.084 19.08 ;
    END
  END tk[83]
  PIN tk[84]
    DIRECTION INPUT ;
    USE SIGNAL ;
    PORT
      LAYER M4 ;
        RECT  0 19.2 0.084 19.224 ;
    END
  END tk[84]
  PIN tk[85]
    DIRECTION INPUT ;
    USE SIGNAL ;
    PORT
      LAYER M4 ;
        RECT  0 19.296 0.084 19.32 ;
    END
  END tk[85]
  PIN tk[86]
    DIRECTION INPUT ;
    USE SIGNAL ;
    PORT
      LAYER M4 ;
        RECT  0 19.392 0.084 19.416 ;
    END
  END tk[86]
  PIN tk[87]
    DIRECTION INPUT ;
    USE SIGNAL ;
    PORT
      LAYER M4 ;
        RECT  0 19.536 0.084 19.56 ;
    END
  END tk[87]
  PIN tk[88]
    DIRECTION INPUT ;
    USE SIGNAL ;
    PORT
      LAYER M4 ;
        RECT  0 19.632 0.084 19.656 ;
    END
  END tk[88]
  PIN tk[89]
    DIRECTION INPUT ;
    USE SIGNAL ;
    PORT
      LAYER M4 ;
        RECT  0 19.728 0.084 19.752 ;
    END
  END tk[89]
  PIN tk[8]
    DIRECTION INPUT ;
    USE SIGNAL ;
    PORT
      LAYER M4 ;
        RECT  0 10.896 0.084 10.92 ;
    END
  END tk[8]
  PIN tk[90]
    DIRECTION INPUT ;
    USE SIGNAL ;
    PORT
      LAYER M4 ;
        RECT  0 19.824 0.084 19.848 ;
    END
  END tk[90]
  PIN tk[91]
    DIRECTION INPUT ;
    USE SIGNAL ;
    PORT
      LAYER M4 ;
        RECT  0 19.968 0.084 19.992 ;
    END
  END tk[91]
  PIN tk[92]
    DIRECTION INPUT ;
    USE SIGNAL ;
    PORT
      LAYER M4 ;
        RECT  0 20.064 0.084 20.088 ;
    END
  END tk[92]
  PIN tk[93]
    DIRECTION INPUT ;
    USE SIGNAL ;
    PORT
      LAYER M4 ;
        RECT  0 20.16 0.084 20.184 ;
    END
  END tk[93]
  PIN tk[94]
    DIRECTION INPUT ;
    USE SIGNAL ;
    PORT
      LAYER M4 ;
        RECT  0 20.256 0.084 20.28 ;
    END
  END tk[94]
  PIN tk[95]
    DIRECTION INPUT ;
    USE SIGNAL ;
    PORT
      LAYER M4 ;
        RECT  0 20.4 0.084 20.424 ;
    END
  END tk[95]
  PIN tk[96]
    DIRECTION INPUT ;
    USE SIGNAL ;
    PORT
      LAYER M4 ;
        RECT  0 20.496 0.084 20.52 ;
    END
  END tk[96]
  PIN tk[97]
    DIRECTION INPUT ;
    USE SIGNAL ;
    PORT
      LAYER M4 ;
        RECT  0 20.592 0.084 20.616 ;
    END
  END tk[97]
  PIN tk[98]
    DIRECTION INPUT ;
    USE SIGNAL ;
    PORT
      LAYER M4 ;
        RECT  0 20.736 0.084 20.76 ;
    END
  END tk[98]
  PIN tk[99]
    DIRECTION INPUT ;
    USE SIGNAL ;
    PORT
      LAYER M4 ;
        RECT  0 20.832 0.084 20.856 ;
    END
  END tk[99]
  PIN tk[9]
    DIRECTION INPUT ;
    USE SIGNAL ;
    PORT
      LAYER M4 ;
        RECT  0 11.04 0.084 11.064 ;
    END
  END tk[9]
  PIN VDD
    DIRECTION INOUT ;
    USE POWER ;
    PORT
      LAYER M5 ;
        RECT  61.992 2.151 62.112 105.849 ;
        RECT  56.592 2.151 56.712 105.849 ;
        RECT  51.192 2.151 51.312 105.849 ;
        RECT  45.792 2.151 45.912 105.849 ;
        RECT  40.392 2.151 40.512 105.849 ;
        RECT  34.992 2.151 35.112 105.849 ;
        RECT  29.592 2.151 29.712 105.849 ;
        RECT  24.192 2.151 24.312 105.849 ;
        RECT  18.792 2.151 18.912 105.849 ;
        RECT  13.392 2.151 13.512 105.849 ;
        RECT  7.992 2.151 8.112 105.849 ;
        RECT  2.592 2.151 2.712 105.849 ;
    END
  END VDD
  PIN VSS
    DIRECTION INOUT ;
    USE GROUND ;
    PORT
      LAYER M5 ;
        RECT  61.8 2.137 61.92 105.863 ;
        RECT  56.4 2.137 56.52 105.863 ;
        RECT  51 2.137 51.12 105.863 ;
        RECT  45.6 2.137 45.72 105.863 ;
        RECT  40.2 2.137 40.32 105.863 ;
        RECT  34.8 2.137 34.92 105.863 ;
        RECT  29.4 2.137 29.52 105.863 ;
        RECT  24 2.137 24.12 105.863 ;
        RECT  18.6 2.137 18.72 105.863 ;
        RECT  13.2 2.137 13.32 105.863 ;
        RECT  7.8 2.137 7.92 105.863 ;
        RECT  2.4 2.137 2.52 105.863 ;
    END
  END VSS
  # OT_OBS_CLOSED layer=M5 d_um=1.536 added=86
  OBS
    LAYER RVTN ;
     RECT  2.16 2.16 62.64 2.295 ;
     RECT  2.16 2.565 62.64 2.835 ;
     RECT  2.16 3.105 62.64 3.375 ;
     RECT  2.16 3.645 62.64 3.915 ;
     RECT  2.16 4.185 62.64 4.455 ;
     RECT  2.16 4.725 62.64 4.995 ;
     RECT  2.16 5.265 62.64 5.535 ;
     RECT  2.16 5.805 62.64 6.075 ;
     RECT  2.16 6.345 62.64 6.615 ;
     RECT  2.16 6.885 62.64 7.155 ;
     RECT  2.16 7.425 62.64 7.695 ;
     RECT  2.16 7.965 62.64 8.235 ;
     RECT  2.16 8.505 62.64 8.775 ;
     RECT  2.16 9.045 62.64 9.315 ;
     RECT  2.16 9.585 62.64 9.855 ;
     RECT  2.16 10.125 62.64 10.395 ;
     RECT  2.16 10.665 62.64 10.935 ;
     RECT  2.16 11.205 62.64 11.475 ;
     RECT  2.16 11.745 62.64 12.015 ;
     RECT  2.16 12.285 62.64 12.555 ;
     RECT  2.16 12.825 62.64 13.095 ;
     RECT  2.16 13.365 62.64 13.635 ;
     RECT  2.16 13.905 62.64 14.175 ;
     RECT  2.16 14.445 62.64 14.715 ;
     RECT  2.16 14.985 62.64 15.255 ;
     RECT  2.16 15.525 62.64 15.795 ;
     RECT  2.16 16.065 62.64 16.335 ;
     RECT  2.16 16.605 62.64 16.875 ;
     RECT  2.16 17.145 62.64 17.415 ;
     RECT  2.16 17.685 62.64 17.955 ;
     RECT  2.16 18.225 62.64 18.495 ;
     RECT  2.16 18.765 62.64 19.035 ;
     RECT  2.16 19.305 62.64 19.575 ;
     RECT  2.16 19.845 62.64 20.115 ;
     RECT  2.16 20.385 62.64 20.655 ;
     RECT  2.16 20.925 62.64 21.195 ;
     RECT  2.16 21.465 62.64 21.735 ;
     RECT  2.16 22.005 62.64 22.275 ;
     RECT  2.16 22.545 62.64 22.815 ;
     RECT  2.16 23.085 62.64 23.355 ;
     RECT  2.16 23.625 62.64 23.895 ;
     RECT  2.16 24.165 62.64 24.435 ;
     RECT  2.16 24.705 62.64 24.975 ;
     RECT  2.16 25.245 62.64 25.515 ;
     RECT  2.16 25.785 62.64 26.055 ;
     RECT  2.16 26.325 62.64 26.595 ;
     RECT  2.16 26.865 62.64 27.135 ;
     RECT  2.16 27.405 62.64 27.675 ;
     RECT  2.16 27.945 62.64 28.215 ;
     RECT  2.16 28.485 62.64 28.755 ;
     RECT  2.16 29.025 62.64 29.295 ;
     RECT  2.16 29.565 62.64 29.835 ;
     RECT  2.16 30.105 62.64 30.375 ;
     RECT  2.16 30.645 62.64 30.915 ;
     RECT  2.16 31.185 62.64 31.455 ;
     RECT  2.16 31.725 62.64 31.995 ;
     RECT  2.16 32.265 62.64 32.535 ;
     RECT  2.16 32.805 62.64 33.075 ;
     RECT  2.16 33.345 62.64 33.615 ;
     RECT  2.16 33.885 62.64 34.155 ;
     RECT  2.16 34.425 62.64 34.695 ;
     RECT  2.16 34.965 62.64 35.235 ;
     RECT  2.16 35.505 62.64 35.775 ;
     RECT  2.16 36.045 62.64 36.315 ;
     RECT  2.16 36.585 62.64 36.855 ;
     RECT  2.16 37.125 62.64 37.395 ;
     RECT  2.16 37.665 62.64 37.935 ;
     RECT  2.16 38.205 62.64 38.475 ;
     RECT  2.16 38.745 62.64 39.015 ;
     RECT  2.16 39.285 62.64 39.555 ;
     RECT  2.16 39.825 62.64 40.095 ;
     RECT  2.16 40.365 62.64 40.635 ;
     RECT  2.16 40.905 62.64 41.175 ;
     RECT  2.16 41.445 62.64 41.715 ;
     RECT  2.16 41.985 62.64 42.255 ;
     RECT  2.16 42.525 62.64 42.795 ;
     RECT  2.16 43.065 62.64 43.335 ;
     RECT  2.16 43.605 62.64 43.875 ;
     RECT  2.16 44.145 62.64 44.415 ;
     RECT  2.16 44.685 62.64 44.955 ;
     RECT  2.16 45.225 62.64 45.495 ;
     RECT  2.16 45.765 62.64 46.035 ;
     RECT  2.16 46.305 62.64 46.575 ;
     RECT  2.16 46.845 62.64 47.115 ;
     RECT  2.16 47.385 62.64 47.655 ;
     RECT  2.16 47.925 62.64 48.195 ;
     RECT  2.16 48.465 62.64 48.735 ;
     RECT  2.16 49.005 62.64 49.275 ;
     RECT  2.16 49.545 62.64 49.815 ;
     RECT  2.16 50.085 62.64 50.355 ;
     RECT  2.16 50.625 62.64 50.895 ;
     RECT  2.16 51.165 62.64 51.435 ;
     RECT  2.16 51.705 62.64 51.975 ;
     RECT  2.16 52.245 62.64 52.515 ;
     RECT  2.16 52.785 62.64 53.055 ;
     RECT  2.16 53.325 62.64 53.595 ;
     RECT  2.16 53.865 62.64 54.135 ;
     RECT  2.16 54.405 62.64 54.675 ;
     RECT  2.16 54.945 62.64 55.215 ;
     RECT  2.16 55.485 62.64 55.755 ;
     RECT  2.16 56.025 62.64 56.295 ;
     RECT  2.16 56.565 62.64 56.835 ;
     RECT  2.16 57.105 62.64 57.375 ;
     RECT  2.16 57.645 62.64 57.915 ;
     RECT  2.16 58.185 62.64 58.455 ;
     RECT  2.16 58.725 62.64 58.995 ;
     RECT  2.16 59.265 62.64 59.535 ;
     RECT  2.16 59.805 62.64 60.075 ;
     RECT  2.16 60.345 62.64 60.615 ;
     RECT  2.16 60.885 62.64 61.155 ;
     RECT  2.16 61.425 62.64 61.695 ;
     RECT  2.16 61.965 62.64 62.235 ;
     RECT  2.16 62.505 62.64 62.775 ;
     RECT  2.16 63.045 62.64 63.315 ;
     RECT  2.16 63.585 62.64 63.855 ;
     RECT  2.16 64.125 62.64 64.395 ;
     RECT  2.16 64.665 62.64 64.935 ;
     RECT  2.16 65.205 62.64 65.475 ;
     RECT  2.16 65.745 62.64 66.015 ;
     RECT  2.16 66.285 62.64 66.555 ;
     RECT  2.16 66.825 62.64 67.095 ;
     RECT  2.16 67.365 62.64 67.635 ;
     RECT  2.16 67.905 62.64 68.175 ;
     RECT  2.16 68.445 62.64 68.715 ;
     RECT  2.16 68.985 62.64 69.255 ;
     RECT  2.16 69.525 62.64 69.795 ;
     RECT  2.16 70.065 62.64 70.335 ;
     RECT  2.16 70.605 62.64 70.875 ;
     RECT  2.16 71.145 62.64 71.415 ;
     RECT  2.16 71.685 62.64 71.955 ;
     RECT  2.16 72.225 62.64 72.495 ;
     RECT  2.16 72.765 62.64 73.035 ;
     RECT  2.16 73.305 62.64 73.575 ;
     RECT  2.16 73.845 62.64 74.115 ;
     RECT  2.16 74.385 62.64 74.655 ;
     RECT  2.16 74.925 62.64 75.195 ;
     RECT  2.16 75.465 62.64 75.735 ;
     RECT  2.16 76.005 62.64 76.275 ;
     RECT  2.16 76.545 62.64 76.815 ;
     RECT  2.16 77.085 62.64 77.355 ;
     RECT  2.16 77.625 62.64 77.895 ;
     RECT  2.16 78.165 62.64 78.435 ;
     RECT  2.16 78.705 62.64 78.975 ;
     RECT  2.16 79.245 62.64 79.515 ;
     RECT  2.16 79.785 62.64 80.055 ;
     RECT  2.16 80.325 62.64 80.595 ;
     RECT  2.16 80.865 62.64 81.135 ;
     RECT  2.16 81.405 62.64 81.675 ;
     RECT  2.16 81.945 62.64 82.215 ;
     RECT  2.16 82.485 62.64 82.755 ;
     RECT  2.16 83.025 62.64 83.295 ;
     RECT  2.16 83.565 62.64 83.835 ;
     RECT  2.16 84.105 62.64 84.375 ;
     RECT  2.16 84.645 62.64 84.915 ;
     RECT  2.16 85.185 62.64 85.455 ;
     RECT  2.16 85.725 62.64 85.995 ;
     RECT  2.16 86.265 62.64 86.535 ;
     RECT  2.16 86.805 62.64 87.075 ;
     RECT  2.16 87.345 62.64 87.615 ;
     RECT  2.16 87.885 62.64 88.155 ;
     RECT  2.16 88.425 62.64 88.695 ;
     RECT  2.16 88.965 62.64 89.235 ;
     RECT  2.16 89.505 62.64 89.775 ;
     RECT  2.16 90.045 62.64 90.315 ;
     RECT  2.16 90.585 62.64 90.855 ;
     RECT  2.16 91.125 62.64 91.395 ;
     RECT  2.16 91.665 62.64 91.935 ;
     RECT  2.16 92.205 62.64 92.475 ;
     RECT  2.16 92.745 62.64 93.015 ;
     RECT  2.16 93.285 62.64 93.555 ;
     RECT  2.16 93.825 62.64 94.095 ;
     RECT  2.16 94.365 62.64 94.635 ;
     RECT  2.16 94.905 62.64 95.175 ;
     RECT  2.16 95.445 62.64 95.715 ;
     RECT  2.16 95.985 62.64 96.255 ;
     RECT  2.16 96.525 62.64 96.795 ;
     RECT  2.16 97.065 62.64 97.335 ;
     RECT  2.16 97.605 62.64 97.875 ;
     RECT  2.16 98.145 62.64 98.415 ;
     RECT  2.16 98.685 62.64 98.955 ;
     RECT  2.16 99.225 62.64 99.495 ;
     RECT  2.16 99.765 62.64 100.035 ;
     RECT  2.16 100.305 62.64 100.575 ;
     RECT  2.16 100.845 62.64 101.115 ;
     RECT  2.16 101.385 62.64 101.655 ;
     RECT  2.16 101.925 62.64 102.195 ;
     RECT  2.16 102.465 62.64 102.735 ;
     RECT  2.16 103.005 62.64 103.275 ;
     RECT  2.16 103.545 62.64 103.815 ;
     RECT  2.16 104.085 62.64 104.355 ;
     RECT  2.16 104.625 62.64 104.895 ;
     RECT  2.16 105.165 62.64 105.435 ;
     RECT  2.16 105.705 62.64 105.84 ;
    LAYER RVTP ;
     RECT  2.16 2.295 62.64 2.565 ;
     RECT  2.16 2.835 62.64 3.105 ;
     RECT  2.16 3.375 62.64 3.645 ;
     RECT  2.16 3.915 62.64 4.185 ;
     RECT  2.16 4.455 62.64 4.725 ;
     RECT  2.16 4.995 62.64 5.265 ;
     RECT  2.16 5.535 62.64 5.805 ;
     RECT  2.16 6.075 62.64 6.345 ;
     RECT  2.16 6.615 62.64 6.885 ;
     RECT  2.16 7.155 62.64 7.425 ;
     RECT  2.16 7.695 62.64 7.965 ;
     RECT  2.16 8.235 62.64 8.505 ;
     RECT  2.16 8.775 62.64 9.045 ;
     RECT  2.16 9.315 62.64 9.585 ;
     RECT  2.16 9.855 62.64 10.125 ;
     RECT  2.16 10.395 62.64 10.665 ;
     RECT  2.16 10.935 62.64 11.205 ;
     RECT  2.16 11.475 62.64 11.745 ;
     RECT  2.16 12.015 62.64 12.285 ;
     RECT  2.16 12.555 62.64 12.825 ;
     RECT  2.16 13.095 62.64 13.365 ;
     RECT  2.16 13.635 62.64 13.905 ;
     RECT  2.16 14.175 62.64 14.445 ;
     RECT  2.16 14.715 62.64 14.985 ;
     RECT  2.16 15.255 62.64 15.525 ;
     RECT  2.16 15.795 62.64 16.065 ;
     RECT  2.16 16.335 62.64 16.605 ;
     RECT  2.16 16.875 62.64 17.145 ;
     RECT  2.16 17.415 62.64 17.685 ;
     RECT  2.16 17.955 62.64 18.225 ;
     RECT  2.16 18.495 62.64 18.765 ;
     RECT  2.16 19.035 62.64 19.305 ;
     RECT  2.16 19.575 62.64 19.845 ;
     RECT  2.16 20.115 62.64 20.385 ;
     RECT  2.16 20.655 62.64 20.925 ;
     RECT  2.16 21.195 62.64 21.465 ;
     RECT  2.16 21.735 62.64 22.005 ;
     RECT  2.16 22.275 62.64 22.545 ;
     RECT  2.16 22.815 62.64 23.085 ;
     RECT  2.16 23.355 62.64 23.625 ;
     RECT  2.16 23.895 62.64 24.165 ;
     RECT  2.16 24.435 62.64 24.705 ;
     RECT  2.16 24.975 62.64 25.245 ;
     RECT  2.16 25.515 62.64 25.785 ;
     RECT  2.16 26.055 62.64 26.325 ;
     RECT  2.16 26.595 62.64 26.865 ;
     RECT  2.16 27.135 62.64 27.405 ;
     RECT  2.16 27.675 62.64 27.945 ;
     RECT  2.16 28.215 62.64 28.485 ;
     RECT  2.16 28.755 62.64 29.025 ;
     RECT  2.16 29.295 62.64 29.565 ;
     RECT  2.16 29.835 62.64 30.105 ;
     RECT  2.16 30.375 62.64 30.645 ;
     RECT  2.16 30.915 62.64 31.185 ;
     RECT  2.16 31.455 62.64 31.725 ;
     RECT  2.16 31.995 62.64 32.265 ;
     RECT  2.16 32.535 62.64 32.805 ;
     RECT  2.16 33.075 62.64 33.345 ;
     RECT  2.16 33.615 62.64 33.885 ;
     RECT  2.16 34.155 62.64 34.425 ;
     RECT  2.16 34.695 62.64 34.965 ;
     RECT  2.16 35.235 62.64 35.505 ;
     RECT  2.16 35.775 62.64 36.045 ;
     RECT  2.16 36.315 62.64 36.585 ;
     RECT  2.16 36.855 62.64 37.125 ;
     RECT  2.16 37.395 62.64 37.665 ;
     RECT  2.16 37.935 62.64 38.205 ;
     RECT  2.16 38.475 62.64 38.745 ;
     RECT  2.16 39.015 62.64 39.285 ;
     RECT  2.16 39.555 62.64 39.825 ;
     RECT  2.16 40.095 62.64 40.365 ;
     RECT  2.16 40.635 62.64 40.905 ;
     RECT  2.16 41.175 62.64 41.445 ;
     RECT  2.16 41.715 62.64 41.985 ;
     RECT  2.16 42.255 62.64 42.525 ;
     RECT  2.16 42.795 62.64 43.065 ;
     RECT  2.16 43.335 62.64 43.605 ;
     RECT  2.16 43.875 62.64 44.145 ;
     RECT  2.16 44.415 62.64 44.685 ;
     RECT  2.16 44.955 62.64 45.225 ;
     RECT  2.16 45.495 62.64 45.765 ;
     RECT  2.16 46.035 62.64 46.305 ;
     RECT  2.16 46.575 62.64 46.845 ;
     RECT  2.16 47.115 62.64 47.385 ;
     RECT  2.16 47.655 62.64 47.925 ;
     RECT  2.16 48.195 62.64 48.465 ;
     RECT  2.16 48.735 62.64 49.005 ;
     RECT  2.16 49.275 62.64 49.545 ;
     RECT  2.16 49.815 62.64 50.085 ;
     RECT  2.16 50.355 62.64 50.625 ;
     RECT  2.16 50.895 62.64 51.165 ;
     RECT  2.16 51.435 62.64 51.705 ;
     RECT  2.16 51.975 62.64 52.245 ;
     RECT  2.16 52.515 62.64 52.785 ;
     RECT  2.16 53.055 62.64 53.325 ;
     RECT  2.16 53.595 62.64 53.865 ;
     RECT  2.16 54.135 62.64 54.405 ;
     RECT  2.16 54.675 62.64 54.945 ;
     RECT  2.16 55.215 62.64 55.485 ;
     RECT  2.16 55.755 62.64 56.025 ;
     RECT  2.16 56.295 62.64 56.565 ;
     RECT  2.16 56.835 62.64 57.105 ;
     RECT  2.16 57.375 62.64 57.645 ;
     RECT  2.16 57.915 62.64 58.185 ;
     RECT  2.16 58.455 62.64 58.725 ;
     RECT  2.16 58.995 62.64 59.265 ;
     RECT  2.16 59.535 62.64 59.805 ;
     RECT  2.16 60.075 62.64 60.345 ;
     RECT  2.16 60.615 62.64 60.885 ;
     RECT  2.16 61.155 62.64 61.425 ;
     RECT  2.16 61.695 62.64 61.965 ;
     RECT  2.16 62.235 62.64 62.505 ;
     RECT  2.16 62.775 62.64 63.045 ;
     RECT  2.16 63.315 62.64 63.585 ;
     RECT  2.16 63.855 62.64 64.125 ;
     RECT  2.16 64.395 62.64 64.665 ;
     RECT  2.16 64.935 62.64 65.205 ;
     RECT  2.16 65.475 62.64 65.745 ;
     RECT  2.16 66.015 62.64 66.285 ;
     RECT  2.16 66.555 62.64 66.825 ;
     RECT  2.16 67.095 62.64 67.365 ;
     RECT  2.16 67.635 62.64 67.905 ;
     RECT  2.16 68.175 62.64 68.445 ;
     RECT  2.16 68.715 62.64 68.985 ;
     RECT  2.16 69.255 62.64 69.525 ;
     RECT  2.16 69.795 62.64 70.065 ;
     RECT  2.16 70.335 62.64 70.605 ;
     RECT  2.16 70.875 62.64 71.145 ;
     RECT  2.16 71.415 62.64 71.685 ;
     RECT  2.16 71.955 62.64 72.225 ;
     RECT  2.16 72.495 62.64 72.765 ;
     RECT  2.16 73.035 62.64 73.305 ;
     RECT  2.16 73.575 62.64 73.845 ;
     RECT  2.16 74.115 62.64 74.385 ;
     RECT  2.16 74.655 62.64 74.925 ;
     RECT  2.16 75.195 62.64 75.465 ;
     RECT  2.16 75.735 62.64 76.005 ;
     RECT  2.16 76.275 62.64 76.545 ;
     RECT  2.16 76.815 62.64 77.085 ;
     RECT  2.16 77.355 62.64 77.625 ;
     RECT  2.16 77.895 62.64 78.165 ;
     RECT  2.16 78.435 62.64 78.705 ;
     RECT  2.16 78.975 62.64 79.245 ;
     RECT  2.16 79.515 62.64 79.785 ;
     RECT  2.16 80.055 62.64 80.325 ;
     RECT  2.16 80.595 62.64 80.865 ;
     RECT  2.16 81.135 62.64 81.405 ;
     RECT  2.16 81.675 62.64 81.945 ;
     RECT  2.16 82.215 62.64 82.485 ;
     RECT  2.16 82.755 62.64 83.025 ;
     RECT  2.16 83.295 62.64 83.565 ;
     RECT  2.16 83.835 62.64 84.105 ;
     RECT  2.16 84.375 62.64 84.645 ;
     RECT  2.16 84.915 62.64 85.185 ;
     RECT  2.16 85.455 62.64 85.725 ;
     RECT  2.16 85.995 62.64 86.265 ;
     RECT  2.16 86.535 62.64 86.805 ;
     RECT  2.16 87.075 62.64 87.345 ;
     RECT  2.16 87.615 62.64 87.885 ;
     RECT  2.16 88.155 62.64 88.425 ;
     RECT  2.16 88.695 62.64 88.965 ;
     RECT  2.16 89.235 62.64 89.505 ;
     RECT  2.16 89.775 62.64 90.045 ;
     RECT  2.16 90.315 62.64 90.585 ;
     RECT  2.16 90.855 62.64 91.125 ;
     RECT  2.16 91.395 62.64 91.665 ;
     RECT  2.16 91.935 62.64 92.205 ;
     RECT  2.16 92.475 62.64 92.745 ;
     RECT  2.16 93.015 62.64 93.285 ;
     RECT  2.16 93.555 62.64 93.825 ;
     RECT  2.16 94.095 62.64 94.365 ;
     RECT  2.16 94.635 62.64 94.905 ;
     RECT  2.16 95.175 62.64 95.445 ;
     RECT  2.16 95.715 62.64 95.985 ;
     RECT  2.16 96.255 62.64 96.525 ;
     RECT  2.16 96.795 62.64 97.065 ;
     RECT  2.16 97.335 62.64 97.605 ;
     RECT  2.16 97.875 62.64 98.145 ;
     RECT  2.16 98.415 62.64 98.685 ;
     RECT  2.16 98.955 62.64 99.225 ;
     RECT  2.16 99.495 62.64 99.765 ;
     RECT  2.16 100.035 62.64 100.305 ;
     RECT  2.16 100.575 62.64 100.845 ;
     RECT  2.16 101.115 62.64 101.385 ;
     RECT  2.16 101.655 62.64 101.925 ;
     RECT  2.16 102.195 62.64 102.465 ;
     RECT  2.16 102.735 62.64 103.005 ;
     RECT  2.16 103.275 62.64 103.545 ;
     RECT  2.16 103.815 62.64 104.085 ;
     RECT  2.16 104.355 62.64 104.625 ;
     RECT  2.16 104.895 62.64 105.165 ;
     RECT  2.16 105.435 62.64 105.705 ;
    LAYER M1 ;
     RECT  2.16 2.151 62.64 105.849 ;
    LAYER M2 ;
     RECT  0.031 44.541 0.103 44.559 ;
     RECT  0.103 15.57 0.139 15.588 ;
     RECT  0.103 24.48 0.139 25.47 ;
     RECT  0.103 33.012 0.139 33.03 ;
     RECT  0.031 42.732 0.139 42.75 ;
     RECT  0.103 43.812 0.139 44.559 ;
     RECT  0.103 45.432 0.139 45.45 ;
     RECT  0.103 54.612 0.139 55.242 ;
     RECT  0.103 63.09 0.139 63.108 ;
     RECT  0.103 73.35 0.139 73.368 ;
     RECT  0.103 83.772 0.139 83.79 ;
     RECT  0.103 84.69 0.139 84.708 ;
     RECT  0.103 12.528 0.175 12.546 ;
     RECT  0.103 22.752 0.175 22.77 ;
     RECT  0.139 23.67 0.175 25.47 ;
     RECT  0.139 33.012 0.175 33.408 ;
     RECT  0.139 42.732 0.175 43.02 ;
     RECT  0.139 43.812 0.175 45.45 ;
     RECT  0.103 52.992 0.175 53.01 ;
     RECT  0.139 54.108 0.175 55.278 ;
     RECT  0.103 64.71 0.175 65.268 ;
     RECT  0.139 72.972 0.175 73.368 ;
     RECT  0.139 83.772 0.175 84.87 ;
     RECT  0.175 12.528 0.211 13.05 ;
     RECT  0.103 13.95 0.211 14.508 ;
     RECT  0.139 62.82 0.211 63.108 ;
     RECT  0.175 64.17 0.211 65.268 ;
     RECT  0.175 72.972 0.211 73.53 ;
     RECT  0.103 38.484 0.239 38.502 ;
     RECT  0.103 69.3 0.239 69.318 ;
     RECT  0.103 80.604 0.239 80.622 ;
     RECT  0.211 12.528 0.535 14.508 ;
     RECT  0.175 22.752 0.535 25.47 ;
     RECT  0.175 83.34 0.535 84.906 ;
     RECT  1.147 29.772 1.327 29.79 ;
     RECT  1.183 30.582 1.327 30.6 ;
     RECT  0.103 20.664 1.399 20.682 ;
     RECT  0.535 67.716 1.723 67.734 ;
     RECT  1.147 81.612 1.723 81.63 ;
     RECT  1.399 20.664 1.975 21.42 ;
     RECT  1.723 91.674 1.975 91.692 ;
     RECT  1.147 48.978 2.047 48.996 ;
     RECT  0.103 61.632 2.083 61.65 ;
     RECT  1.723 67.608 2.083 67.734 ;
     RECT  1.147 71.082 2.083 71.1 ;
     RECT  1.723 39.096 2.119 39.114 ;
     RECT  0.535 22.518 2.155 25.47 ;
     RECT  0.103 26.532 2.155 26.55 ;
     RECT  0.103 34.74 2.155 34.758 ;
     RECT  2.119 38.412 2.155 39.78 ;
     RECT  1.147 40.572 2.155 40.59 ;
     RECT  0.175 42.732 2.155 45.45 ;
     RECT  0.535 12.492 2.16 14.508 ;
     RECT  0.139 15.264 2.16 15.588 ;
     RECT  0.103 17.46 2.16 17.478 ;
     RECT  1.975 20.052 2.16 21.42 ;
     RECT  2.155 22.518 2.16 26.55 ;
     RECT  2.155 28.764 2.16 28.782 ;
     RECT  1.327 29.772 2.16 30.6 ;
     RECT  1.723 31.392 2.16 31.41 ;
     RECT  0.175 33.012 2.16 33.57 ;
     RECT  2.155 34.74 2.16 35.262 ;
     RECT  2.155 36.864 2.16 37.62 ;
     RECT  2.155 38.412 2.16 40.59 ;
     RECT  2.119 41.454 2.16 41.472 ;
     RECT  2.155 42.336 2.16 45.45 ;
     RECT  2.047 47.664 2.16 47.682 ;
     RECT  2.047 48.978 2.16 49.23 ;
     RECT  0.175 52.992 2.16 55.278 ;
     RECT  0.535 56.736 2.16 56.754 ;
     RECT  2.047 58.266 2.16 58.284 ;
     RECT  2.047 59.202 2.16 59.49 ;
     RECT  1.975 60.822 2.16 60.84 ;
     RECT  2.083 61.632 2.16 61.722 ;
     RECT  0.211 62.82 2.16 65.268 ;
     RECT  2.083 66.492 2.16 66.51 ;
     RECT  2.083 67.608 2.16 68.202 ;
     RECT  2.083 69.264 2.16 69.282 ;
     RECT  2.083 70.614 2.16 71.1 ;
     RECT  1.399 72.162 2.16 72.18 ;
     RECT  0.211 72.972 2.16 74.07 ;
     RECT  0.103 75.132 2.16 76.878 ;
     RECT  0.535 78.516 2.16 78.534 ;
     RECT  1.399 80.262 2.16 80.28 ;
     RECT  1.723 81.612 2.16 82.17 ;
     RECT  0.535 83.34 2.16 85.41 ;
     RECT  0.103 87.624 2.16 87.642 ;
     RECT  1.975 91.674 2.16 92.16 ;
     RECT  2.16 2.151 12.991 105.849 ;
     RECT  12.991 2.151 13.091 106.578 ;
     RECT  13.091 2.151 16.987 105.849 ;
     RECT  16.987 2.106 17.915 105.849 ;
     RECT  17.915 2.151 62.64 105.849 ;
     RECT  62.64 43.146 62.699 43.866 ;
     RECT  62.64 44.694 62.735 49.536 ;
     RECT  62.64 34.326 62.771 40.158 ;
     RECT  62.699 43.848 62.771 43.866 ;
     RECT  62.64 54.576 62.951 59.724 ;
     RECT  62.771 34.326 63.095 40.014 ;
     RECT  63.095 35.136 63.167 40.014 ;
     RECT  63.167 36.828 63.239 40.014 ;
     RECT  63.167 35.136 63.275 35.964 ;
     RECT  62.735 45.126 63.275 49.536 ;
     RECT  63.275 45.126 63.311 48.726 ;
     RECT  63.275 35.136 63.563 35.874 ;
     RECT  62.951 54.576 63.563 59.454 ;
     RECT  63.563 58.626 63.599 59.454 ;
     RECT  63.563 54.576 63.635 57.744 ;
     RECT  63.239 36.828 63.671 38.664 ;
     RECT  63.599 58.626 63.671 59.022 ;
     RECT  63.239 39.762 63.707 40.014 ;
     RECT  63.671 36.864 63.743 38.664 ;
     RECT  63.671 58.626 63.743 58.644 ;
     RECT  62.64 52.416 63.779 53.784 ;
     RECT  63.311 47.556 63.815 48.726 ;
     RECT  63.635 57.114 63.815 57.744 ;
     RECT  63.707 39.87 63.851 40.014 ;
     RECT  63.815 47.556 63.851 48.384 ;
     RECT  63.779 53.766 63.851 53.784 ;
     RECT  63.851 39.996 63.887 40.014 ;
     RECT  62.64 41.076 63.887 41.202 ;
     RECT  63.311 45.126 63.887 45.684 ;
     RECT  63.887 45.666 63.923 45.684 ;
     RECT  63.743 37.098 64.219 38.664 ;
     RECT  64.219 37.098 64.463 38.772 ;
     RECT  64.463 38.376 64.471 38.772 ;
     RECT  62.64 50.526 64.471 51.624 ;
     RECT  63.779 52.416 64.471 52.929 ;
     RECT  64.471 50.526 64.499 52.929 ;
     RECT  63.635 54.576 64.499 56.214 ;
     RECT  64.463 37.098 64.535 37.314 ;
     RECT  64.499 55.458 64.535 56.214 ;
     RECT  63.563 35.136 64.571 35.766 ;
     RECT  64.535 55.836 64.571 56.214 ;
     RECT  64.471 38.376 64.607 38.844 ;
     RECT  64.499 50.526 64.607 51.894 ;
     RECT  63.887 41.184 64.615 41.202 ;
     RECT  64.499 52.911 64.615 52.929 ;
     RECT  64.571 35.136 64.643 35.46 ;
     RECT  64.607 51.291 64.643 51.894 ;
     RECT  64.571 56.196 64.643 56.214 ;
     RECT  64.615 41.184 64.651 41.436 ;
     RECT  64.643 35.136 64.679 35.154 ;
     RECT  64.607 50.526 64.679 50.544 ;
     RECT  64.615 52.911 64.679 53.046 ;
     RECT  63.815 57.384 64.679 57.744 ;
     RECT  64.651 41.076 64.687 41.436 ;
     RECT  64.607 38.646 64.715 38.664 ;
     RECT  63.851 48.096 64.715 48.114 ;
     RECT  64.679 53.028 64.715 53.046 ;
     RECT  64.499 54.576 64.715 54.666 ;
     RECT  64.679 57.384 64.715 57.564 ;
     RECT  64.535 37.098 64.751 37.116 ;
     RECT  64.687 41.076 64.751 41.589 ;
     RECT  63.095 34.326 64.787 34.344 ;
     RECT  64.751 41.571 64.787 41.589 ;
     RECT  64.643 51.291 64.787 51.309 ;
     RECT  64.715 57.546 64.787 57.564 ;
    LAYER M3 ;
     RECT  3.492 0.091 3.51 0.523 ;
     RECT  17.028 0.091 17.046 0.523 ;
     RECT  17.784 0.091 18.126 0.523 ;
     RECT  22.644 0.091 22.662 0.523 ;
     RECT  26.82 0.091 27.09 0.523 ;
     RECT  17.028 0.523 18.486 0.571 ;
     RECT  22.644 0.523 22.878 0.571 ;
     RECT  5.76 0.571 5.778 1.099 ;
     RECT  7.416 0.571 7.434 1.099 ;
     RECT  20.016 0.571 20.034 1.099 ;
     RECT  22.248 0.571 23.49 1.099 ;
     RECT  21.708 1.099 23.49 1.627 ;
     RECT  26.82 0.523 27.234 1.627 ;
     RECT  31.14 1.099 31.158 1.627 ;
     RECT  16.92 0.571 18.846 1.675 ;
     RECT  20.016 1.099 20.106 1.675 ;
     RECT  26.28 1.627 27.234 1.675 ;
     RECT  30.24 1.627 30.258 1.675 ;
     RECT  3.492 0.523 3.798 1.723 ;
     RECT  4.536 0.091 4.554 1.723 ;
     RECT  5.76 1.099 6.246 1.723 ;
     RECT  7.416 1.099 7.65 1.723 ;
     RECT  16.848 1.675 20.106 1.723 ;
     RECT  21.708 1.627 23.742 1.723 ;
     RECT  24.696 0.571 24.714 1.723 ;
     RECT  26.28 1.675 27.306 1.723 ;
     RECT  28.44 0.091 28.458 1.723 ;
     RECT  30.168 1.675 30.258 1.723 ;
     RECT  31.14 1.627 31.806 1.723 ;
     RECT  33.444 1.675 33.462 1.723 ;
     RECT  3.492 1.723 4.59 1.771 ;
     RECT  5.4 1.723 8.73 1.771 ;
     RECT  16.848 1.723 30.402 1.771 ;
     RECT  31.14 1.723 33.93 1.771 ;
     RECT  40.5 0.571 40.518 2.143 ;
     RECT  3.492 1.771 8.946 2.263 ;
     RECT  16.848 1.771 33.93 2.299 ;
     RECT  16.632 2.299 33.93 2.371 ;
     RECT  40.215 2.143 40.518 2.371 ;
     RECT  2.415 2.143 2.505 2.413 ;
     RECT  13.215 2.143 13.305 2.413 ;
     RECT  34.815 2.143 34.905 2.413 ;
     RECT  45.615 2.143 45.705 2.413 ;
     RECT  46.512 1.723 46.53 2.413 ;
     RECT  51.015 2.143 51.105 2.413 ;
     RECT  56.415 2.143 56.505 2.413 ;
     RECT  61.815 2.143 61.905 2.413 ;
     RECT  3.492 2.263 9.126 2.525 ;
     RECT  45.615 2.413 46.53 2.525 ;
     RECT  15.084 2.569 15.102 2.605 ;
     RECT  3.636 2.525 9.126 2.641 ;
     RECT  3.636 2.641 9.234 2.767 ;
     RECT  46.656 2.641 46.674 2.795 ;
     RECT  3.636 2.767 9.27 2.803 ;
     RECT  16.02 2.371 33.93 2.803 ;
     RECT  34.815 2.413 35.097 2.803 ;
     RECT  3.636 2.803 9.882 3.145 ;
     RECT  14.508 2.605 15.102 3.181 ;
     RECT  16.02 2.803 35.097 3.181 ;
     RECT  3.636 3.145 10.242 3.271 ;
     RECT  11.16 2.875 11.178 3.271 ;
     RECT  43.992 2.911 44.01 3.335 ;
     RECT  3.636 3.271 11.178 3.341 ;
     RECT  3.636 3.341 10.242 3.443 ;
     RECT  40.215 2.371 40.77 3.569 ;
     RECT  11.16 3.341 11.178 3.721 ;
     RECT  11.916 3.181 11.934 3.721 ;
     RECT  41.4 3.577 41.418 3.875 ;
     RECT  3.636 3.443 10.134 4.145 ;
     RECT  11.16 3.721 11.934 4.261 ;
     RECT  3.78 4.145 10.134 4.495 ;
     RECT  11.16 4.261 12.438 4.495 ;
     RECT  3.78 4.495 12.438 4.649 ;
     RECT  3.78 4.649 3.798 4.685 ;
     RECT  4.572 4.649 12.438 5.575 ;
     RECT  4.14 5.575 12.438 5.741 ;
     RECT  4.428 5.741 12.438 6.269 ;
     RECT  4.968 6.269 12.438 6.539 ;
     RECT  5.4 6.539 12.438 6.809 ;
     RECT  5.4 6.809 5.454 6.845 ;
     RECT  6.192 6.809 12.438 6.881 ;
     RECT  6.228 6.881 12.438 7.457 ;
     RECT  6.48 7.457 12.438 11.821 ;
     RECT  3.564 11.821 3.582 11.911 ;
     RECT  2.415 2.413 2.697 11.947 ;
     RECT  3.564 11.911 3.654 11.947 ;
     RECT  6.336 11.821 12.438 11.947 ;
     RECT  2.415 11.947 3.654 12.361 ;
     RECT  0.54 12.487 0.558 12.523 ;
     RECT  2.415 12.361 3.87 12.793 ;
     RECT  2.34 12.793 3.87 12.865 ;
     RECT  5.4 6.845 5.418 12.901 ;
     RECT  6.228 11.947 12.438 12.901 ;
     RECT  2.304 12.865 3.87 13.027 ;
     RECT  2.304 13.027 4.302 13.063 ;
     RECT  5.4 12.901 12.438 13.063 ;
     RECT  0.108 12.523 0.558 13.661 ;
     RECT  0.108 13.661 0.522 13.901 ;
     RECT  0.108 13.901 0.486 14.189 ;
     RECT  0.108 14.189 0.27 14.621 ;
     RECT  2.304 13.063 12.438 15.163 ;
     RECT  0.108 14.621 0.162 15.533 ;
     RECT  0.108 15.533 0.126 16.493 ;
     RECT  2.268 15.163 12.438 17.419 ;
     RECT  1.98 17.419 12.438 18.091 ;
     RECT  0.108 17.455 0.126 18.331 ;
     RECT  1.404 18.091 12.438 18.419 ;
     RECT  44.136 3.451 44.154 18.499 ;
     RECT  0.108 18.331 0.162 18.619 ;
     RECT  13.215 2.413 13.497 18.661 ;
     RECT  0.108 18.619 0.234 18.749 ;
     RECT  1.404 18.419 10.242 20.075 ;
     RECT  11.088 18.419 12.438 20.425 ;
     RECT  13.215 18.661 13.698 20.425 ;
     RECT  0.108 18.749 0.126 20.687 ;
     RECT  2.304 20.075 10.242 20.885 ;
     RECT  2.415 20.885 10.242 21.001 ;
     RECT  2.415 21.001 10.278 21.101 ;
     RECT  1.404 20.075 1.422 21.425 ;
     RECT  2.415 21.101 10.17 22.207 ;
     RECT  2.34 22.207 10.17 22.621 ;
     RECT  0.54 22.513 0.558 22.747 ;
     RECT  11.088 20.425 13.698 23.161 ;
     RECT  0.108 22.747 0.558 23.693 ;
     RECT  0.108 23.693 0.522 24.125 ;
     RECT  2.268 22.621 10.17 24.169 ;
     RECT  0.108 24.125 0.486 24.317 ;
     RECT  2.268 24.169 10.278 24.439 ;
     RECT  11.088 23.161 13.77 24.439 ;
     RECT  2.268 24.439 13.77 24.781 ;
     RECT  0.108 24.317 0.306 25.421 ;
     RECT  0.108 25.421 0.126 25.757 ;
     RECT  2.232 24.781 13.77 25.861 ;
     RECT  2.16 25.861 13.77 26.957 ;
     RECT  0.108 26.527 0.126 27.053 ;
     RECT  1.332 27.547 1.35 27.787 ;
     RECT  1.152 27.787 1.35 27.883 ;
     RECT  2.232 26.957 13.77 27.883 ;
     RECT  0.144 28.891 0.162 29.069 ;
     RECT  1.152 27.883 13.77 29.795 ;
     RECT  1.188 29.795 13.77 30.605 ;
     RECT  1.728 30.605 13.77 30.811 ;
     RECT  14.508 3.181 35.097 30.811 ;
     RECT  1.728 30.811 35.097 31.415 ;
     RECT  2.232 31.415 35.097 31.559 ;
     RECT  2.232 31.559 3.258 32.431 ;
     RECT  2.232 32.431 3.33 32.611 ;
     RECT  4.14 31.559 35.097 32.611 ;
     RECT  0.108 33.007 0.126 33.349 ;
     RECT  2.232 32.611 35.097 34.501 ;
     RECT  0.108 33.349 0.558 34.685 ;
     RECT  61.815 2.413 62.097 34.735 ;
     RECT  61.815 34.735 62.19 34.771 ;
     RECT  0.108 34.685 0.126 34.877 ;
     RECT  60.912 34.465 60.93 35.005 ;
     RECT  60.552 35.005 60.93 35.041 ;
     RECT  61.815 34.771 62.298 35.041 ;
     RECT  2.196 34.501 35.097 35.083 ;
     RECT  64.764 34.321 64.782 35.131 ;
     RECT  2.16 35.083 35.097 35.267 ;
     RECT  60.552 35.041 62.298 35.275 ;
     RECT  63.072 34.735 63.09 35.275 ;
     RECT  60.552 35.275 63.09 35.401 ;
     RECT  64.656 35.131 64.782 35.437 ;
     RECT  59.58 35.545 59.598 35.597 ;
     RECT  60.552 35.401 63.81 35.671 ;
     RECT  64.62 35.437 64.782 35.671 ;
     RECT  58.14 34.627 58.158 36.085 ;
     RECT  57.744 36.085 58.158 36.125 ;
     RECT  0.144 36.091 0.162 36.221 ;
     RECT  2.196 35.267 35.097 36.715 ;
     RECT  58.14 36.125 58.158 36.931 ;
     RECT  59.652 36.391 59.67 37.003 ;
     RECT  59.292 37.003 59.67 37.201 ;
     RECT  60.552 35.671 64.782 37.201 ;
     RECT  56.415 2.413 56.697 37.327 ;
     RECT  57.636 36.931 58.158 37.327 ;
     RECT  0.144 37.243 0.162 37.373 ;
     RECT  2.16 36.715 35.097 37.387 ;
     RECT  59.292 37.201 64.782 37.597 ;
     RECT  2.124 37.387 35.097 37.675 ;
     RECT  1.728 37.675 35.097 38.251 ;
     RECT  0.324 38.347 0.342 38.443 ;
     RECT  0.108 38.443 0.342 38.477 ;
     RECT  56.415 37.327 58.158 38.479 ;
     RECT  59.112 37.597 64.782 38.479 ;
     RECT  0.108 38.477 0.234 38.507 ;
     RECT  0.216 38.507 0.234 38.621 ;
     RECT  54.144 38.821 54.162 38.911 ;
     RECT  55.62 38.821 55.638 38.911 ;
     RECT  53.028 38.911 54.162 39.055 ;
     RECT  54.9 38.911 55.638 39.055 ;
     RECT  53.028 39.055 55.638 39.067 ;
     RECT  1.152 38.251 35.097 39.119 ;
     RECT  52.596 39.067 55.638 39.119 ;
     RECT  40.215 3.569 40.497 39.217 ;
     RECT  42.624 3.721 42.642 39.217 ;
     RECT  43.884 18.499 44.154 39.217 ;
     RECT  42.624 39.217 44.154 39.289 ;
     RECT  53.028 39.119 55.638 39.289 ;
     RECT  56.415 38.479 64.782 39.289 ;
     RECT  40.215 39.217 40.626 39.355 ;
     RECT  42.408 39.289 44.154 39.451 ;
     RECT  42.192 39.451 44.154 39.595 ;
     RECT  53.028 39.289 64.782 39.623 ;
     RECT  40.215 39.355 41.238 39.631 ;
     RECT  42.084 39.595 44.154 39.631 ;
     RECT  53.172 39.623 64.782 39.749 ;
     RECT  2.124 39.119 35.097 39.785 ;
     RECT  40.215 39.631 44.154 39.901 ;
     RECT  2.16 39.785 35.097 39.929 ;
     RECT  45.615 2.525 45.897 40.027 ;
     RECT  49.032 39.721 49.05 40.055 ;
     RECT  0.324 39.979 0.342 40.109 ;
     RECT  39.024 32.881 39.042 40.171 ;
     RECT  40.215 39.901 44.37 40.171 ;
     RECT  45.144 40.027 45.897 40.171 ;
     RECT  51.015 2.413 51.297 40.171 ;
     RECT  38.844 40.171 39.042 40.261 ;
     RECT  49.86 40.135 49.878 40.297 ;
     RECT  49.608 40.297 49.878 40.325 ;
     RECT  50.94 40.171 51.297 40.333 ;
     RECT  38.772 40.261 39.042 40.459 ;
     RECT  38.7 40.459 39.042 40.531 ;
     RECT  40.215 40.171 45.897 40.531 ;
     RECT  50.94 40.333 51.354 40.567 ;
     RECT  1.152 39.119 1.17 40.595 ;
     RECT  49.608 40.325 49.626 40.595 ;
     RECT  53.604 39.749 64.782 40.603 ;
     RECT  37.764 31.657 37.782 40.711 ;
     RECT  38.7 40.531 46.746 40.711 ;
     RECT  53.172 40.603 64.782 40.711 ;
     RECT  50.796 40.567 51.354 40.909 ;
     RECT  52.56 40.711 64.782 40.981 ;
     RECT  50.724 40.909 51.354 41.009 ;
     RECT  49.428 40.837 49.518 41.071 ;
     RECT  51.015 41.009 51.354 41.071 ;
     RECT  37.764 40.711 46.746 41.131 ;
     RECT  37.62 41.131 46.746 41.171 ;
     RECT  52.452 40.981 64.782 41.179 ;
     RECT  48.42 40.639 48.438 41.215 ;
     RECT  49.284 41.071 49.518 41.215 ;
     RECT  38.016 41.171 46.746 41.243 ;
     RECT  48.42 41.215 49.518 41.371 ;
     RECT  2.196 39.929 35.097 41.449 ;
     RECT  51.015 41.071 51.426 41.521 ;
     RECT  52.416 41.179 64.782 41.521 ;
     RECT  51.015 41.521 64.782 41.594 ;
     RECT  51.015 41.594 64.71 41.597 ;
     RECT  38.196 41.243 46.746 41.707 ;
     RECT  47.88 41.371 49.518 41.707 ;
     RECT  38.196 41.707 49.842 41.783 ;
     RECT  38.196 41.783 49.806 41.909 ;
     RECT  38.196 41.909 49.77 42.223 ;
     RECT  38.16 42.223 49.77 42.317 ;
     RECT  51.015 41.597 64.674 42.565 ;
     RECT  0.036 42.727 0.054 42.997 ;
     RECT  0.036 42.997 0.162 43.105 ;
     RECT  38.196 42.317 49.77 43.333 ;
     RECT  38.124 43.333 49.77 43.339 ;
     RECT  50.688 42.565 64.674 43.339 ;
     RECT  38.124 43.339 64.674 43.373 ;
     RECT  0.036 43.105 0.558 44.141 ;
     RECT  38.376 43.373 64.674 44.141 ;
     RECT  0.036 44.141 0.234 44.564 ;
     RECT  39.024 44.141 64.638 44.765 ;
     RECT  2.124 41.449 35.097 44.959 ;
     RECT  39.024 44.765 64.278 45.031 ;
     RECT  38.772 45.031 64.278 45.121 ;
     RECT  38.34 45.121 64.278 45.197 ;
     RECT  38.34 45.197 63.918 45.257 ;
     RECT  0.108 44.564 0.234 45.301 ;
     RECT  38.52 45.257 63.918 45.533 ;
     RECT  38.52 45.533 38.682 45.581 ;
     RECT  39.42 45.533 63.918 45.581 ;
     RECT  38.592 45.581 38.682 45.599 ;
     RECT  38.592 45.599 38.61 45.629 ;
     RECT  39.42 45.581 62.766 45.689 ;
     RECT  39.924 45.689 62.766 45.725 ;
     RECT  0.108 45.301 0.558 45.773 ;
     RECT  0.18 45.773 0.558 45.869 ;
     RECT  40.215 45.725 42.678 45.959 ;
     RECT  40.215 45.959 42.642 45.995 ;
     RECT  43.632 45.725 62.766 45.995 ;
     RECT  40.215 45.995 41.742 46.067 ;
     RECT  43.884 45.995 62.766 46.253 ;
     RECT  0.54 45.869 0.558 46.349 ;
     RECT  63.864 45.581 63.918 46.381 ;
     RECT  63.252 46.381 63.918 46.397 ;
     RECT  43.884 46.253 62.262 46.409 ;
     RECT  43.884 46.409 48.294 46.499 ;
     RECT  49.068 46.409 62.262 46.643 ;
     RECT  43.884 46.499 48.186 46.685 ;
     RECT  42.624 45.995 42.642 46.849 ;
     RECT  49.104 46.643 62.262 47.191 ;
     RECT  49.104 47.191 62.298 47.281 ;
     RECT  49.104 47.281 62.334 47.315 ;
     RECT  43.884 46.685 47.898 47.461 ;
     RECT  2.088 44.959 35.097 47.467 ;
     RECT  43.884 47.461 48.042 47.551 ;
     RECT  49.104 47.315 49.122 47.551 ;
     RECT  49.932 47.315 62.334 47.611 ;
     RECT  63.252 46.397 63.846 47.611 ;
     RECT  43.884 47.551 49.122 47.651 ;
     RECT  2.052 47.467 35.097 47.687 ;
     RECT  42.624 46.849 42.786 47.759 ;
     RECT  43.884 47.651 46.926 47.849 ;
     RECT  47.664 47.651 49.122 47.885 ;
     RECT  45.432 47.849 46.35 47.921 ;
     RECT  64.692 47.179 64.71 47.995 ;
     RECT  64.656 47.995 64.71 48.091 ;
     RECT  45.615 47.921 46.35 48.119 ;
     RECT  64.584 48.091 64.71 48.119 ;
     RECT  45.615 48.119 46.206 48.155 ;
     RECT  48.456 47.885 49.122 48.191 ;
     RECT  49.068 48.191 49.122 48.271 ;
     RECT  49.932 47.611 63.846 48.271 ;
     RECT  0.324 48.043 0.342 48.475 ;
     RECT  0.216 48.475 0.342 48.797 ;
     RECT  40.215 46.067 41.67 48.839 ;
     RECT  47.664 47.885 47.682 48.859 ;
     RECT  2.088 47.687 35.097 48.907 ;
     RECT  49.068 48.271 63.846 48.973 ;
     RECT  1.152 48.973 1.17 49.133 ;
     RECT  2.052 48.907 35.097 49.235 ;
     RECT  0.324 48.797 0.342 49.277 ;
     RECT  42.624 47.759 42.642 49.351 ;
     RECT  47.664 48.859 48.006 49.441 ;
     RECT  42.336 49.351 42.894 49.469 ;
     RECT  47.664 49.441 48.186 49.477 ;
     RECT  48.996 48.973 63.846 49.477 ;
     RECT  40.215 48.839 41.058 49.505 ;
     RECT  42.372 49.469 42.786 49.649 ;
     RECT  40.215 49.505 40.95 49.775 ;
     RECT  42.372 49.649 42.642 49.811 ;
     RECT  43.884 47.849 43.902 49.981 ;
     RECT  42.372 49.811 42.606 50.009 ;
     RECT  43.884 49.981 44.154 50.081 ;
     RECT  43.884 50.081 43.902 50.153 ;
     RECT  47.664 49.477 63.846 50.299 ;
     RECT  64.584 48.119 64.674 50.299 ;
     RECT  0.144 50.203 0.162 50.669 ;
     RECT  46.908 50.557 46.926 50.701 ;
     RECT  47.664 50.299 64.674 50.701 ;
     RECT  46.908 50.701 64.674 50.779 ;
     RECT  46.908 50.779 64.71 50.819 ;
     RECT  47.664 50.819 64.71 50.855 ;
     RECT  45.615 48.155 45.897 50.935 ;
     RECT  46.908 50.819 46.926 50.935 ;
     RECT  47.844 50.855 64.71 51.286 ;
     RECT  42.372 50.009 42.426 51.367 ;
     RECT  38.772 51.367 38.79 51.503 ;
     RECT  41.904 51.367 42.426 51.503 ;
     RECT  45.615 50.935 46.926 51.637 ;
     RECT  47.844 51.286 64.782 51.637 ;
     RECT  45.615 51.637 64.782 51.665 ;
     RECT  45.615 51.665 46.314 51.677 ;
     RECT  47.232 51.665 64.782 51.677 ;
     RECT  40.215 49.775 40.554 52.169 ;
     RECT  45.615 51.677 46.206 52.781 ;
     RECT  47.844 51.677 64.782 53.131 ;
     RECT  0.108 52.987 0.126 53.293 ;
     RECT  46.908 53.257 46.926 53.309 ;
     RECT  47.7 53.131 64.782 53.401 ;
     RECT  0.108 53.293 0.558 54.509 ;
     RECT  47.052 53.401 64.782 54.751 ;
     RECT  45.615 52.781 45.897 54.949 ;
     RECT  46.764 54.751 64.782 54.949 ;
     RECT  0.108 54.509 0.414 55.037 ;
     RECT  0.108 55.037 0.162 55.709 ;
     RECT  45.615 54.949 64.782 55.997 ;
     RECT  46.764 55.997 64.782 56.021 ;
     RECT  46.764 56.021 63.81 56.129 ;
     RECT  0.144 55.709 0.162 56.141 ;
     RECT  64.62 56.021 64.782 56.219 ;
     RECT  47.088 56.129 63.81 56.327 ;
     RECT  47.088 56.327 48.33 56.525 ;
     RECT  2.088 49.235 35.097 56.587 ;
     RECT  2.052 56.587 35.097 56.765 ;
     RECT  49.32 56.327 63.81 57.029 ;
     RECT  53.568 57.029 63.81 57.101 ;
     RECT  54.036 57.101 63.81 57.137 ;
     RECT  47.124 56.525 48.33 57.181 ;
     RECT  49.32 57.029 52.83 57.181 ;
     RECT  0.54 56.731 0.558 57.197 ;
     RECT  54.036 57.137 63.738 57.209 ;
     RECT  2.088 56.765 35.097 57.499 ;
     RECT  64.656 56.219 64.782 57.569 ;
     RECT  47.124 57.181 52.83 57.721 ;
     RECT  64.656 57.569 64.674 57.749 ;
     RECT  46.98 57.721 52.83 57.955 ;
     RECT  54.144 57.209 63.738 58.081 ;
     RECT  46.908 57.955 52.83 58.109 ;
     RECT  54.108 58.081 63.738 58.109 ;
     RECT  54.108 58.109 59.85 58.261 ;
     RECT  46.908 58.109 49.986 58.495 ;
     RECT  50.724 58.109 52.83 58.495 ;
     RECT  53.64 58.261 59.85 58.495 ;
     RECT  50.724 58.495 59.85 58.649 ;
     RECT  60.624 58.109 63.738 58.649 ;
     RECT  50.724 58.649 51.966 58.685 ;
     RECT  60.624 58.649 63.666 58.685 ;
     RECT  0.144 58.363 0.162 58.795 ;
     RECT  61.632 58.685 63.666 58.955 ;
     RECT  0.144 58.795 0.342 58.973 ;
     RECT  46.692 58.495 49.986 58.999 ;
     RECT  50.724 58.685 51.858 58.999 ;
     RECT  61.74 58.955 63.666 59.027 ;
     RECT  52.992 58.649 59.814 59.063 ;
     RECT  61.74 59.027 63.594 59.063 ;
     RECT  53.604 59.063 59.814 59.117 ;
     RECT  54.72 59.117 59.814 59.189 ;
     RECT  46.692 58.999 51.858 59.459 ;
     RECT  53.604 59.117 53.622 59.459 ;
     RECT  61.776 59.063 63.594 59.459 ;
     RECT  61.776 59.459 62.946 59.495 ;
     RECT  47.484 59.459 51.858 59.603 ;
     RECT  47.556 59.603 51.858 59.611 ;
     RECT  46.692 59.459 46.71 59.645 ;
     RECT  61.815 59.495 62.946 59.729 ;
     RECT  61.815 59.729 62.55 59.801 ;
     RECT  54.828 59.189 59.778 59.971 ;
     RECT  47.556 59.611 51.966 60.043 ;
     RECT  54.72 59.971 59.778 60.151 ;
     RECT  54.72 60.151 59.85 60.341 ;
     RECT  47.556 60.043 52.002 60.349 ;
     RECT  47.556 60.349 52.038 60.385 ;
     RECT  47.34 60.385 52.038 60.809 ;
     RECT  54.72 60.341 59.778 60.809 ;
     RECT  1.98 57.499 35.097 60.845 ;
     RECT  55.26 60.809 59.778 60.845 ;
     RECT  47.124 60.811 47.142 60.851 ;
     RECT  54.504 60.889 54.522 60.941 ;
     RECT  47.916 60.809 52.038 61.393 ;
     RECT  55.476 60.845 59.778 61.429 ;
     RECT  47.916 61.393 52.434 61.465 ;
     RECT  55.476 61.429 60.102 61.579 ;
     RECT  47.916 61.465 52.542 61.627 ;
     RECT  0.108 59.035 0.126 61.655 ;
     RECT  2.088 60.845 35.097 61.727 ;
     RECT  47.88 61.627 52.542 61.735 ;
     RECT  47.448 61.735 52.542 61.771 ;
     RECT  47.448 61.771 52.938 61.861 ;
     RECT  47.304 61.861 52.938 61.889 ;
     RECT  55.008 61.579 60.102 61.889 ;
     RECT  55.008 61.889 58.59 61.925 ;
     RECT  60.012 61.889 60.03 61.925 ;
     RECT  47.304 61.889 52.038 61.961 ;
     RECT  48.096 61.961 52.038 62.033 ;
     RECT  52.92 61.889 52.938 62.033 ;
     RECT  48.096 62.033 51.606 62.069 ;
     RECT  55.008 61.925 58.482 62.159 ;
     RECT  47.304 61.961 47.322 62.189 ;
     RECT  48.096 62.069 51.498 62.195 ;
     RECT  55.008 62.159 58.122 62.843 ;
     RECT  48.384 62.195 51.498 62.941 ;
     RECT  55.62 62.843 58.122 62.969 ;
     RECT  0.144 62.815 0.162 63.013 ;
     RECT  55.692 62.969 58.122 63.041 ;
     RECT  0.144 63.013 0.558 63.085 ;
     RECT  48.384 62.941 51.858 63.085 ;
     RECT  55.872 63.041 58.122 63.121 ;
     RECT  48.384 63.085 52.29 63.239 ;
     RECT  55.872 63.121 58.41 63.239 ;
     RECT  56.16 63.239 58.302 63.275 ;
     RECT  48.384 63.239 51.858 63.383 ;
     RECT  48.384 63.383 51.498 63.509 ;
     RECT  48.384 63.509 51.297 63.545 ;
     RECT  49.392 63.545 51.297 63.779 ;
     RECT  49.392 63.779 50.202 63.815 ;
     RECT  56.415 63.275 58.302 64.049 ;
     RECT  49.392 63.815 49.59 64.085 ;
     RECT  56.415 64.049 57.798 64.085 ;
     RECT  49.392 64.085 49.41 64.157 ;
     RECT  0.108 63.085 0.558 64.397 ;
     RECT  56.415 64.085 57.582 64.411 ;
     RECT  56.088 64.411 57.582 64.427 ;
     RECT  56.088 64.427 57.042 64.445 ;
     RECT  56.088 64.445 57.006 64.463 ;
     RECT  0.108 64.397 0.522 64.637 ;
     RECT  56.415 64.463 57.006 64.895 ;
     RECT  0.108 64.637 0.486 64.925 ;
     RECT  0.108 64.925 0.27 65.597 ;
     RECT  41.904 51.503 41.922 65.849 ;
     RECT  0.324 65.899 0.342 66.029 ;
     RECT  2.124 61.727 35.097 66.331 ;
     RECT  0.144 66.427 0.162 67.085 ;
     RECT  1.728 66.331 35.097 67.631 ;
     RECT  0.324 67.531 0.342 67.711 ;
     RECT  0.324 67.711 0.558 67.901 ;
     RECT  0.144 67.963 0.162 68.237 ;
     RECT  1.152 68.587 1.17 68.731 ;
     RECT  2.088 67.631 35.097 68.731 ;
     RECT  0.324 69.067 0.342 69.259 ;
     RECT  0.108 69.259 0.342 69.293 ;
     RECT  0.108 69.293 0.234 69.323 ;
     RECT  0.144 69.323 0.234 69.437 ;
     RECT  0.144 69.437 0.162 69.485 ;
     RECT  0.144 70.699 0.162 70.829 ;
     RECT  1.152 68.731 35.097 71.105 ;
     RECT  1.404 71.105 35.097 72.185 ;
     RECT  2.124 72.185 35.097 73.103 ;
     RECT  0.144 72.967 0.162 73.345 ;
     RECT  0.108 73.345 0.162 73.507 ;
     RECT  0.108 73.507 0.198 73.885 ;
     RECT  0.108 73.885 0.27 74.285 ;
     RECT  0.144 74.285 0.27 75.127 ;
     RECT  2.16 73.103 35.097 75.299 ;
     RECT  0.108 75.127 0.27 75.775 ;
     RECT  0.108 75.775 0.558 75.917 ;
     RECT  2.304 75.299 35.097 77.227 ;
     RECT  2.268 77.227 35.097 77.387 ;
     RECT  0.108 75.917 0.126 77.549 ;
     RECT  2.268 77.387 10.314 77.855 ;
     RECT  2.304 77.855 10.314 78.089 ;
     RECT  0.54 78.511 0.558 78.749 ;
     RECT  1.404 77.755 1.422 78.859 ;
     RECT  2.304 78.089 10.278 78.859 ;
     RECT  11.196 77.387 35.097 78.899 ;
     RECT  0.324 79.051 0.342 79.229 ;
     RECT  1.404 78.859 10.278 79.291 ;
     RECT  0.144 79.387 0.162 79.805 ;
     RECT  0.324 80.491 0.342 80.587 ;
     RECT  0.108 80.587 0.342 80.621 ;
     RECT  0.108 80.621 0.306 80.627 ;
     RECT  0.216 80.627 0.306 80.765 ;
     RECT  0.288 80.765 0.306 80.813 ;
     RECT  1.152 79.291 10.278 81.031 ;
     RECT  11.448 78.899 35.097 81.031 ;
     RECT  1.152 81.031 35.097 81.635 ;
     RECT  1.728 81.635 35.097 82.139 ;
     RECT  1.728 82.139 2.697 82.175 ;
     RECT  2.415 82.175 2.697 83.101 ;
     RECT  3.672 82.139 35.097 83.101 ;
     RECT  0.18 83.335 0.198 83.533 ;
     RECT  0.18 83.533 0.522 83.605 ;
     RECT  0.18 83.605 0.558 83.767 ;
     RECT  2.415 83.101 35.097 84.479 ;
     RECT  0.108 83.767 0.558 84.653 ;
     RECT  0.108 84.653 0.522 85.181 ;
     RECT  2.415 84.479 10.242 85.225 ;
     RECT  0.144 85.181 0.522 85.325 ;
     RECT  0.18 85.325 0.522 85.387 ;
     RECT  0.18 85.387 0.558 85.757 ;
     RECT  0.18 85.757 0.198 85.853 ;
     RECT  2.304 85.225 10.242 86.305 ;
     RECT  2.268 86.305 10.242 86.495 ;
     RECT  2.304 86.495 10.242 87.547 ;
     RECT  10.98 84.479 35.097 87.547 ;
     RECT  0.108 87.619 0.126 87.979 ;
     RECT  0.108 87.979 0.162 88.205 ;
     RECT  2.304 87.547 35.097 88.315 ;
     RECT  0.108 88.205 0.126 88.445 ;
     RECT  2.268 88.315 35.097 88.555 ;
     RECT  48.384 63.545 48.402 88.655 ;
     RECT  0.144 88.987 0.162 89.261 ;
     RECT  0.144 90.475 0.162 90.715 ;
     RECT  0.144 90.715 0.342 90.811 ;
     RECT  0.108 90.811 0.342 90.845 ;
     RECT  1.728 88.555 35.097 90.923 ;
     RECT  0.108 90.845 0.126 91.037 ;
     RECT  1.728 90.923 11.142 91.049 ;
     RECT  6.012 91.049 11.142 91.193 ;
     RECT  1.728 91.049 4.95 91.319 ;
     RECT  6.012 91.193 6.03 91.391 ;
     RECT  6.804 91.193 11.142 91.499 ;
     RECT  1.728 91.319 3.654 91.589 ;
     RECT  4.392 91.319 4.95 91.589 ;
     RECT  1.728 91.589 3.582 91.697 ;
     RECT  4.5 91.589 4.95 91.769 ;
     RECT  7.308 91.499 11.142 92.011 ;
     RECT  11.916 90.923 35.097 92.011 ;
     RECT  1.98 91.697 3.582 92.165 ;
     RECT  7.308 92.011 35.097 92.201 ;
     RECT  11.916 92.201 35.097 92.273 ;
     RECT  2.415 92.165 3.582 92.399 ;
     RECT  4.536 91.769 4.95 92.399 ;
     RECT  2.415 92.399 3.006 92.669 ;
     RECT  4.536 92.399 4.554 92.669 ;
     RECT  7.308 92.201 11.142 92.923 ;
     RECT  6.84 92.923 11.142 92.975 ;
     RECT  7.308 92.975 11.142 93.091 ;
     RECT  11.916 92.273 11.934 93.091 ;
     RECT  7.308 93.091 11.934 93.757 ;
     RECT  12.672 92.273 35.097 93.757 ;
     RECT  7.308 93.757 35.097 94.075 ;
     RECT  7.2 94.075 35.097 94.595 ;
     RECT  7.308 94.595 35.097 95.995 ;
     RECT  7.2 95.995 35.097 96.449 ;
     RECT  7.308 96.449 35.097 97.295 ;
     RECT  7.38 97.295 35.097 97.637 ;
     RECT  7.38 97.637 29.697 97.871 ;
     RECT  7.416 97.871 29.697 98.189 ;
     RECT  7.56 98.189 29.697 99.571 ;
     RECT  7.272 99.571 29.697 99.661 ;
     RECT  7.128 99.661 29.697 99.725 ;
     RECT  7.56 99.725 29.697 99.733 ;
     RECT  30.492 97.637 35.097 99.733 ;
     RECT  7.56 99.733 35.097 101.011 ;
     RECT  7.416 101.011 35.097 101.155 ;
     RECT  7.056 101.155 35.097 101.345 ;
     RECT  7.416 101.345 35.097 102.029 ;
     RECT  7.56 102.029 35.097 102.763 ;
     RECT  7.38 102.763 35.097 102.965 ;
     RECT  7.488 102.965 35.097 103.199 ;
     RECT  7.488 103.199 32.598 103.469 ;
     RECT  33.408 103.199 35.097 103.847 ;
     RECT  33.408 103.847 33.642 104.279 ;
     RECT  7.596 103.469 32.598 104.431 ;
     RECT  33.624 104.279 33.642 104.621 ;
     RECT  7.524 104.431 32.598 104.701 ;
     RECT  7.524 104.701 32.706 104.819 ;
     RECT  7.668 104.819 32.598 105.269 ;
     RECT  7.668 105.269 32.094 105.395 ;
     RECT  7.74 105.395 32.094 105.485 ;
     RECT  2.415 92.669 2.697 105.587 ;
     RECT  34.815 103.847 35.097 105.587 ;
     RECT  40.215 52.169 40.497 105.587 ;
     RECT  45.615 55.997 45.897 105.587 ;
     RECT  51.015 63.779 51.297 105.587 ;
     RECT  56.415 64.895 56.697 105.587 ;
     RECT  61.815 59.801 62.097 105.587 ;
     RECT  7.74 105.485 30.438 105.629 ;
     RECT  31.212 105.485 32.094 105.629 ;
     RECT  7.74 105.629 9.81 105.665 ;
     RECT  29.268 105.629 30.438 105.701 ;
     RECT  10.656 105.629 28.494 105.737 ;
     RECT  31.68 105.629 31.698 105.809 ;
     RECT  2.415 105.587 2.505 105.857 ;
     RECT  7.815 105.665 9.558 105.857 ;
     RECT  34.815 105.587 34.905 105.857 ;
     RECT  40.215 105.587 40.305 105.857 ;
     RECT  45.615 105.587 45.705 105.857 ;
     RECT  51.015 105.587 51.105 105.857 ;
     RECT  56.415 105.587 56.505 105.857 ;
     RECT  61.815 105.587 61.905 105.857 ;
     RECT  10.728 105.737 28.494 105.917 ;
     RECT  29.268 105.701 30.186 105.917 ;
     RECT  29.268 105.917 30.15 105.965 ;
     RECT  10.728 105.917 28.458 106.013 ;
     RECT  29.34 105.965 30.15 106.013 ;
     RECT  8.136 105.857 9.558 106.061 ;
     RECT  10.728 106.013 20.862 106.061 ;
     RECT  29.556 106.013 29.574 106.061 ;
     RECT  21.816 106.013 28.386 106.541 ;
     RECT  8.208 106.061 9.558 106.589 ;
     RECT  10.728 106.061 20.322 106.589 ;
     RECT  21.816 106.541 26.73 106.589 ;
     RECT  27.504 106.541 28.386 106.589 ;
     RECT  9.252 106.589 9.342 106.637 ;
     RECT  14.148 106.589 18.594 106.637 ;
     RECT  11.16 106.589 13.158 106.685 ;
     RECT  9.324 106.637 9.342 107.165 ;
     RECT  11.16 106.685 12.078 107.165 ;
     RECT  13.068 106.685 13.158 107.165 ;
     RECT  14.148 106.637 17.658 107.165 ;
     RECT  20.304 106.589 20.322 107.165 ;
     RECT  24.156 106.589 26.514 107.165 ;
     RECT  8.208 106.589 8.262 107.213 ;
     RECT  13.068 107.165 13.086 107.213 ;
     RECT  15.624 107.165 15.642 107.213 ;
     RECT  21.816 106.589 22.374 107.213 ;
     RECT  8.244 107.213 8.262 107.885 ;
     RECT  11.232 107.165 11.25 107.885 ;
     RECT  14.148 107.165 14.634 107.885 ;
     RECT  24.156 107.165 24.174 107.885 ;
     RECT  25.56 107.165 25.578 107.885 ;
     RECT  27.576 106.589 27.594 107.885 ;
    LAYER M4 ;
     RECT  0.06 84.384 0.097 90.936 ;
     RECT  0.06 43.92 0.133 50.472 ;
     RECT  0.06 64.128 0.133 70.728 ;
     RECT  0.06 13.536 0.137 20.088 ;
     RECT  0.06 54.048 0.137 60.6 ;
     RECT  0.133 64.128 0.137 70.824 ;
     RECT  0.06 74.256 0.137 80.856 ;
     RECT  0.097 84.384 0.137 91.032 ;
     RECT  0.137 54.144 0.173 60.6 ;
     RECT  0.137 64.272 0.173 70.824 ;
     RECT  0.137 84.528 0.173 91.032 ;
     RECT  0.173 54.24 0.209 60.6 ;
     RECT  0.137 13.632 0.569 20.088 ;
     RECT  0.06 23.664 0.569 30.216 ;
     RECT  0.173 64.368 0.569 70.824 ;
     RECT  0.173 84.624 0.569 91.032 ;
     RECT  0.133 43.92 2.293 50.664 ;
     RECT  0.06 33.792 2.329 40.344 ;
     RECT  0.569 13.824 2.401 20.088 ;
     RECT  2.401 13.824 2.408 20.328 ;
     RECT  0.569 23.856 2.408 30.216 ;
     RECT  2.329 33.792 2.408 40.44 ;
     RECT  2.293 43.92 2.408 50.952 ;
     RECT  0.209 54.336 2.408 60.6 ;
     RECT  0.569 64.704 2.408 70.824 ;
     RECT  0.137 74.4 2.408 80.856 ;
     RECT  0.569 85.392 2.408 91.032 ;
     RECT  2.408 2.148 2.512 105.852 ;
     RECT  2.512 2.418 2.704 105.582 ;
     RECT  2.704 19.824 2.765 20.184 ;
     RECT  2.704 33.792 2.765 38.472 ;
     RECT  2.704 64.992 2.765 68.424 ;
     RECT  2.704 76.032 2.765 80.808 ;
     RECT  2.704 30.048 2.801 30.456 ;
     RECT  2.765 36.96 2.801 38.472 ;
     RECT  2.704 46.512 2.801 50.184 ;
     RECT  2.704 88.752 2.801 90.936 ;
     RECT  2.704 13.824 2.837 18.792 ;
     RECT  2.704 23.856 2.837 29.064 ;
     RECT  2.765 33.792 2.837 35.544 ;
     RECT  2.801 47.616 2.837 50.184 ;
     RECT  2.704 54.336 2.837 59.304 ;
     RECT  2.765 67.824 2.837 68.424 ;
     RECT  2.765 76.032 2.837 79.8 ;
     RECT  2.704 85.488 2.837 87.672 ;
     RECT  2.801 46.512 2.873 46.536 ;
     RECT  2.837 13.824 2.909 18.264 ;
     RECT  2.801 89.424 2.909 90.936 ;
     RECT  2.704 40.08 2.945 40.584 ;
     RECT  2.837 54.912 2.945 59.304 ;
     RECT  2.837 47.712 2.981 50.184 ;
     RECT  2.704 70.512 2.981 71.448 ;
     RECT  2.704 44.688 3.017 45.192 ;
     RECT  2.765 64.992 3.089 66.6 ;
     RECT  2.837 76.8 3.089 79.8 ;
     RECT  2.837 85.488 3.089 86.232 ;
     RECT  2.837 28.272 3.125 29.064 ;
     RECT  3.089 76.944 3.125 79.8 ;
     RECT  2.765 80.784 3.125 80.808 ;
     RECT  2.837 87.648 3.125 87.672 ;
     RECT  2.909 14.208 3.161 18.264 ;
     RECT  2.765 19.872 3.299 20.184 ;
     RECT  2.704 22.032 3.299 22.2 ;
     RECT  2.837 23.856 3.299 26.808 ;
     RECT  2.801 36.96 3.299 38.424 ;
     RECT  2.801 30.432 3.347 30.456 ;
     RECT  2.837 33.792 3.347 34.872 ;
     RECT  2.981 47.712 3.413 48.888 ;
     RECT  2.704 69.456 3.436 69.528 ;
     RECT  3.017 44.976 3.521 45.192 ;
     RECT  3.161 15.648 3.557 18.264 ;
     RECT  3.299 36.96 3.665 37.896 ;
     RECT  2.704 42.72 3.733 42.744 ;
     RECT  2.837 67.824 3.733 67.848 ;
     RECT  2.704 74.592 3.733 74.616 ;
     RECT  3.481 0.096 3.769 0.12 ;
     RECT  2.704 51.648 3.769 51.672 ;
     RECT  2.704 60.672 3.773 62.856 ;
     RECT  3.733 42.72 3.781 43.32 ;
     RECT  2.704 96 3.781 96.024 ;
     RECT  2.945 54.912 3.805 58.152 ;
     RECT  3.436 69.456 3.805 69.48 ;
     RECT  3.733 74.592 3.805 75.432 ;
     RECT  3.089 86.16 3.805 86.232 ;
     RECT  3.299 24.096 3.841 26.808 ;
     RECT  3.125 28.272 3.841 28.968 ;
     RECT  2.945 59.28 3.841 59.304 ;
     RECT  3.733 67.296 3.841 67.848 ;
     RECT  3.805 68.88 3.841 69.48 ;
     RECT  3.521 45.168 3.877 45.192 ;
     RECT  3.877 45.168 3.913 45.672 ;
     RECT  3.913 45.168 3.949 45.96 ;
     RECT  3.805 74.064 3.989 75.432 ;
     RECT  3.347 34.512 4.021 34.872 ;
     RECT  3.949 88.224 4.021 88.248 ;
     RECT  2.909 89.424 4.021 90.648 ;
     RECT  3.841 24.096 4.025 28.968 ;
     RECT  2.945 40.56 4.057 40.584 ;
     RECT  3.769 51.648 4.093 51.912 ;
     RECT  2.704 6.192 4.129 6.216 ;
     RECT  3.089 64.992 4.129 65.88 ;
     RECT  3.841 67.296 4.129 69.48 ;
     RECT  4.025 24.096 4.133 25.416 ;
     RECT  4.129 1.728 4.165 1.752 ;
     RECT  3.161 14.208 4.237 14.376 ;
     RECT  3.413 48.384 4.237 48.888 ;
     RECT  3.841 59.28 4.241 59.496 ;
     RECT  3.773 60.672 4.273 60.984 ;
     RECT  3.557 15.648 4.277 16.488 ;
     RECT  3.805 53.952 4.309 58.152 ;
     RECT  4.025 26.64 4.345 28.968 ;
     RECT  3.805 86.16 4.345 86.424 ;
     RECT  4.237 48.384 4.381 49.032 ;
     RECT  4.021 34.512 4.405 35.688 ;
     RECT  4.309 53.952 4.417 59.112 ;
     RECT  4.417 53.568 4.421 59.112 ;
     RECT  4.165 1.728 4.453 1.848 ;
     RECT  2.704 2.832 4.453 3.96 ;
     RECT  3.733 72.864 4.453 72.888 ;
     RECT  3.769 0.096 4.499 0.552 ;
     RECT  4.453 72.864 4.508 72.984 ;
     RECT  2.981 70.512 4.525 70.536 ;
     RECT  4.525 70.512 4.549 71.112 ;
     RECT  4.421 53.568 4.561 55.8 ;
     RECT  4.273 60.528 4.561 60.984 ;
     RECT  4.021 88.224 4.573 90.648 ;
     RECT  4.508 72.624 4.595 72.984 ;
     RECT  4.133 24.096 4.597 25.368 ;
     RECT  4.561 53.136 4.597 55.8 ;
     RECT  4.597 23.616 4.601 25.368 ;
     RECT  4.129 64.992 4.601 69.48 ;
     RECT  4.573 89.376 4.601 90.648 ;
     RECT  4.499 0.096 4.609 0.12 ;
     RECT  4.093 51.408 4.633 51.912 ;
     RECT  4.597 53.04 4.633 55.8 ;
     RECT  4.595 72.864 4.633 72.984 ;
     RECT  3.989 74.256 4.633 75.432 ;
     RECT  4.237 13.872 4.669 14.376 ;
     RECT  4.633 33.264 4.669 33.288 ;
     RECT  4.633 38.64 4.693 38.664 ;
     RECT  4.057 39.888 4.693 40.584 ;
     RECT  4.237 84.432 4.7 84.456 ;
     RECT  4.381 48.384 4.705 49.128 ;
     RECT  2.981 50.16 4.705 50.184 ;
     RECT  4.549 70.512 4.741 71.208 ;
     RECT  4.601 66.576 4.745 69.48 ;
     RECT  4.669 33.264 4.777 33.528 ;
     RECT  4.405 34.512 4.777 35.88 ;
     RECT  4.633 72.864 4.787 73.032 ;
     RECT  4.277 16.224 4.813 16.488 ;
     RECT  3.781 41.904 4.813 43.32 ;
     RECT  3.949 45.168 4.813 46.2 ;
     RECT  4.345 86.16 4.813 86.76 ;
     RECT  4.345 26.64 4.849 29.688 ;
     RECT  3.299 20.16 4.853 20.184 ;
     RECT  3.665 36.96 4.885 37.608 ;
     RECT  4.693 38.64 4.885 40.584 ;
     RECT  4.813 41.616 4.885 43.32 ;
     RECT  4.561 60.432 4.885 60.984 ;
     RECT  3.773 62.16 4.885 62.856 ;
     RECT  4.7 83.76 4.885 84.456 ;
     RECT  4.849 26.64 4.889 30.408 ;
     RECT  4.741 70.512 4.889 71.256 ;
     RECT  4.633 74.256 4.889 75.768 ;
     RECT  4.813 45.024 4.921 46.2 ;
     RECT  4.421 56.832 4.924 59.112 ;
     RECT  4.889 75.408 4.925 75.768 ;
     RECT  3.125 76.944 4.925 79.752 ;
     RECT  4.745 66.576 4.931 69.24 ;
     RECT  4.601 64.992 4.957 65.304 ;
     RECT  4.885 60.432 4.988 62.856 ;
     RECT  4.921 45.024 4.993 46.536 ;
     RECT  4.813 86.064 5.027 86.76 ;
     RECT  4.925 75.744 5.065 75.768 ;
     RECT  4.925 76.944 5.065 77.784 ;
     RECT  4.705 48.384 5.069 50.184 ;
     RECT  4.885 83.712 5.069 84.456 ;
     RECT  4.787 72.912 5.075 73.032 ;
     RECT  3.781 96 5.077 97.32 ;
     RECT  4.957 64.176 5.123 65.304 ;
     RECT  4.129 5.712 5.125 6.216 ;
     RECT  4.777 33.264 5.132 35.88 ;
     RECT  5.132 32.976 5.137 35.88 ;
     RECT  4.885 36.96 5.137 43.32 ;
     RECT  4.601 89.664 5.141 90.648 ;
     RECT  5.137 32.976 5.209 43.32 ;
     RECT  4.993 44.592 5.209 46.536 ;
     RECT  4.453 1.728 5.213 4.536 ;
     RECT  5.209 32.976 5.219 46.536 ;
     RECT  3.557 17.616 5.267 18.072 ;
     RECT  4.601 25.056 5.281 25.368 ;
     RECT  5.027 86.688 5.317 86.76 ;
     RECT  5.213 1.728 5.321 4.488 ;
     RECT  4.889 70.8 5.413 71.256 ;
     RECT  4.988 60.432 5.42 63.192 ;
     RECT  4.813 16.224 5.425 16.584 ;
     RECT  5.281 25.056 5.425 25.56 ;
     RECT  4.889 26.64 5.425 28.776 ;
     RECT  4.501 31.536 5.425 31.56 ;
     RECT  4.633 51.408 5.425 55.8 ;
     RECT  4.924 56.832 5.425 58.584 ;
     RECT  4.889 30 5.573 30.408 ;
     RECT  5.125 5.712 5.605 6.264 ;
     RECT  5.573 30.384 5.605 30.408 ;
     RECT  5.425 31.488 5.605 31.56 ;
     RECT  5.125 93.504 5.605 93.528 ;
     RECT  4.889 74.256 5.677 74.328 ;
     RECT  5.069 48.432 5.713 50.184 ;
     RECT  5.425 51.408 5.713 58.584 ;
     RECT  5.123 64.992 5.713 65.304 ;
     RECT  4.931 66.576 5.713 68.952 ;
     RECT  5.605 30.384 5.785 31.56 ;
     RECT  5.075 72.96 5.785 73.032 ;
     RECT  5.677 18.576 5.821 18.6 ;
     RECT  5.713 64.992 5.825 68.952 ;
     RECT  4.925 78.768 5.825 79.752 ;
     RECT  4.165 80.928 5.825 80.952 ;
     RECT  5.749 0.576 5.833 0.6 ;
     RECT  5.785 72.96 5.869 73.08 ;
     RECT  5.069 83.76 5.897 84.456 ;
     RECT  5.321 4.464 5.933 4.488 ;
     RECT  5.869 72.96 5.941 73.032 ;
     RECT  5.42 60.432 5.965 63.768 ;
     RECT  5.605 5.664 6.037 6.264 ;
     RECT  4.601 23.616 6.037 23.688 ;
     RECT  5.317 86.688 6.037 86.808 ;
     RECT  5.825 66.576 6.041 68.952 ;
     RECT  5.413 70.8 6.073 71.832 ;
     RECT  5.941 72.96 6.073 72.984 ;
     RECT  5.065 75.744 6.077 77.784 ;
     RECT  4.669 13.872 6.083 15.096 ;
     RECT  5.677 74.112 6.113 74.328 ;
     RECT  6.077 75.744 6.113 75.816 ;
     RECT  6.041 66.672 6.149 68.952 ;
     RECT  6.077 76.944 6.149 77.784 ;
     RECT  6.037 23.616 6.181 23.832 ;
     RECT  5.425 25.056 6.181 28.776 ;
     RECT  6.037 86.688 6.181 86.904 ;
     RECT  4.573 88.224 6.181 88.248 ;
     RECT  6.083 13.872 6.185 14.232 ;
     RECT  5.425 16.08 6.185 17.544 ;
     RECT  6.037 5.664 6.188 6.84 ;
     RECT  5.321 1.728 6.217 2.28 ;
     RECT  5.219 33.168 6.253 46.536 ;
     RECT  6.253 33.072 6.257 46.536 ;
     RECT  6.257 33.072 6.293 43.08 ;
     RECT  6.185 17.088 6.325 17.544 ;
     RECT  5.821 18.576 6.325 18.792 ;
     RECT  5.821 20.304 6.325 20.328 ;
     RECT  5.785 30.384 6.329 31.896 ;
     RECT  6.257 44.256 6.329 46.536 ;
     RECT  5.713 48.432 6.329 58.584 ;
     RECT  6.325 17.088 6.365 20.328 ;
     RECT  5.965 59.856 6.38 63.768 ;
     RECT  5.825 64.992 6.38 65.064 ;
     RECT  6.185 16.08 6.397 16.104 ;
     RECT  6.329 48.432 6.397 49.08 ;
     RECT  6.181 86.688 6.397 88.248 ;
     RECT  6.38 59.856 6.419 65.064 ;
     RECT  6.181 23.616 6.437 28.776 ;
     RECT  6.293 35.328 6.437 37.128 ;
     RECT  6.113 75.792 6.437 75.816 ;
     RECT  6.149 77.088 6.437 77.784 ;
     RECT  5.141 90.624 6.437 90.648 ;
     RECT  6.217 1.104 6.467 2.28 ;
     RECT  6.365 17.328 6.467 20.328 ;
     RECT  6.293 38.688 6.467 43.08 ;
     RECT  6.419 60.144 6.467 65.064 ;
     RECT  6.293 33.072 6.469 34.152 ;
     RECT  6.437 77.52 6.509 77.784 ;
     RECT  6.397 86.688 6.509 88.92 ;
     RECT  6.397 15.312 6.545 16.104 ;
     RECT  6.437 35.328 6.617 37.032 ;
     RECT  5.605 92.928 6.661 93.528 ;
     RECT  6.329 30.576 6.709 31.896 ;
     RECT  6.469 33.024 6.709 34.152 ;
     RECT  6.661 92.928 6.709 93.576 ;
     RECT  6.329 44.448 6.721 46.536 ;
     RECT  6.397 47.904 6.721 49.08 ;
     RECT  6.721 44.448 6.761 49.08 ;
     RECT  6.617 35.664 6.803 37.032 ;
     RECT  5.077 96 6.805 97.8 ;
     RECT  6.437 23.808 6.973 28.776 ;
     RECT  6.545 15.312 7.045 16.008 ;
     RECT  6.149 66.672 7.117 68.712 ;
     RECT  5.897 83.76 7.117 83.784 ;
     RECT  2.704 100.512 7.117 100.536 ;
     RECT  6.113 74.304 7.333 74.328 ;
     RECT  6.805 96 7.369 98.664 ;
     RECT  7.117 99.696 7.397 100.536 ;
     RECT  6.467 38.688 7.405 39.336 ;
     RECT  6.467 20.304 7.429 20.328 ;
     RECT  6.467 1.728 7.441 2.28 ;
     RECT  6.803 36.192 7.441 37.032 ;
     RECT  6.709 30.576 7.477 34.152 ;
     RECT  7.441 36.192 7.477 37.128 ;
     RECT  7.405 38.496 7.477 39.336 ;
     RECT  6.467 40.56 7.477 43.08 ;
     RECT  6.709 92.928 7.477 94.104 ;
     RECT  7.369 95.184 7.477 98.664 ;
     RECT  7.405 0.576 7.489 0.6 ;
     RECT  6.329 50.4 7.58 55.224 ;
     RECT  6.329 56.256 7.58 58.584 ;
     RECT  7.045 14.736 7.613 16.008 ;
     RECT  7.441 1.68 7.621 2.28 ;
     RECT  6.467 60.144 7.628 63.768 ;
     RECT  6.467 17.328 7.657 18.6 ;
     RECT  7.58 50.4 7.669 58.584 ;
     RECT  7.628 59.616 7.669 63.768 ;
     RECT  7.477 40.56 7.693 43.128 ;
     RECT  7.613 14.208 7.765 16.008 ;
     RECT  6.509 77.52 7.765 77.64 ;
     RECT  6.509 86.88 7.801 87.48 ;
     RECT  7.621 1.104 7.808 3.096 ;
     RECT  6.188 4.656 7.808 6.84 ;
     RECT  7.765 13.344 7.808 16.008 ;
     RECT  7.657 17.232 7.808 18.6 ;
     RECT  7.429 19.92 7.808 20.328 ;
     RECT  3.299 22.176 7.808 22.2 ;
     RECT  6.973 23.808 7.808 29.112 ;
     RECT  7.477 30.384 7.808 34.152 ;
     RECT  7.477 36.192 7.808 39.336 ;
     RECT  7.693 40.56 7.808 43.32 ;
     RECT  6.761 44.448 7.808 48.984 ;
     RECT  7.669 50.4 7.808 63.768 ;
     RECT  6.467 65.04 7.808 65.064 ;
     RECT  7.117 66.672 7.808 69.24 ;
     RECT  6.073 70.8 7.808 72.984 ;
     RECT  7.333 74.16 7.808 74.328 ;
     RECT  7.765 77.04 7.808 77.64 ;
     RECT  5.825 79.152 7.808 79.752 ;
     RECT  7.285 80.784 7.808 80.808 ;
     RECT  7.117 83.76 7.808 83.832 ;
     RECT  7.333 85.104 7.808 85.128 ;
     RECT  7.801 86.736 7.808 87.48 ;
     RECT  6.509 88.896 7.808 88.92 ;
     RECT  6.853 90.048 7.808 90.072 ;
     RECT  7.477 92.928 7.808 98.664 ;
     RECT  7.397 99.696 7.808 101.496 ;
     RECT  7.369 102.768 7.808 102.792 ;
     RECT  7.808 1.104 8.053 105.852 ;
     RECT  8.053 1.104 8.104 106.056 ;
     RECT  8.104 14.64 8.129 15.624 ;
     RECT  8.104 1.104 8.147 6.84 ;
     RECT  8.129 14.736 8.165 15.624 ;
     RECT  8.104 23.808 8.165 25.224 ;
     RECT  8.104 50.544 8.165 58.488 ;
     RECT  8.149 107.856 8.197 107.88 ;
     RECT  8.165 23.808 8.201 24.648 ;
     RECT  8.104 26.256 8.201 27.096 ;
     RECT  8.104 44.304 8.243 49.272 ;
     RECT  8.104 64.368 8.243 65.688 ;
     RECT  8.104 76.848 8.243 78.648 ;
     RECT  8.104 83.712 8.243 86.904 ;
     RECT  8.104 89.472 8.243 89.496 ;
     RECT  8.104 90.528 8.243 91.464 ;
     RECT  8.197 107.184 8.273 107.88 ;
     RECT  8.243 77.04 8.281 78.648 ;
     RECT  8.104 94.704 8.291 102.792 ;
     RECT  8.104 36.24 8.309 36.984 ;
     RECT  8.291 94.704 8.332 99.72 ;
     RECT  8.291 100.896 8.337 102.792 ;
     RECT  8.273 107.184 8.339 107.208 ;
     RECT  8.104 105.264 8.377 106.056 ;
     RECT  8.165 51.264 8.381 58.488 ;
     RECT  8.104 68.928 8.381 69.24 ;
     RECT  8.165 15.504 8.417 15.624 ;
     RECT  8.147 1.728 8.435 6.84 ;
     RECT  8.104 28.896 8.435 30.072 ;
     RECT  8.332 94.704 8.453 96.984 ;
     RECT  8.337 100.896 8.483 101.928 ;
     RECT  8.104 19.344 8.489 19.944 ;
     RECT  8.243 83.712 8.489 83.784 ;
     RECT  8.435 2.928 8.525 6.84 ;
     RECT  8.201 23.808 8.525 24.504 ;
     RECT  8.104 66.72 8.531 67.848 ;
     RECT  8.104 73.392 8.531 75.432 ;
     RECT  8.281 77.04 8.531 77.592 ;
     RECT  8.332 98.016 8.531 99.72 ;
     RECT  8.104 31.104 8.561 34.776 ;
     RECT  8.243 64.368 8.561 64.392 ;
     RECT  8.243 86.64 8.561 86.904 ;
     RECT  8.201 26.256 8.597 26.376 ;
     RECT  8.104 38.112 8.597 39.336 ;
     RECT  8.531 75.408 8.597 75.432 ;
     RECT  8.381 51.264 8.62 54.408 ;
     RECT  8.104 60.576 8.669 63.288 ;
     RECT  8.377 105.264 8.675 107.16 ;
     RECT  8.381 68.928 8.705 68.952 ;
     RECT  8.525 2.928 8.723 5.208 ;
     RECT  8.435 1.728 8.741 1.8 ;
     RECT  8.597 38.688 8.771 39.336 ;
     RECT  8.381 55.632 8.777 58.488 ;
     RECT  8.417 15.504 8.813 15.528 ;
     RECT  8.489 19.92 8.867 19.944 ;
     RECT  8.435 28.896 8.921 29.112 ;
     RECT  8.62 51.408 8.921 54.408 ;
     RECT  8.104 92.688 8.921 93.624 ;
     RECT  8.741 1.776 8.957 1.8 ;
     RECT  8.723 2.928 8.957 3.864 ;
     RECT  8.104 17.904 9.059 18.168 ;
     RECT  8.531 66.72 9.065 67.416 ;
     RECT  8.281 78.624 9.065 78.648 ;
     RECT  8.531 98.064 9.073 99.72 ;
     RECT  8.104 70.8 9.089 71.832 ;
     RECT  8.531 73.392 9.089 74.328 ;
     RECT  9.089 70.8 9.101 74.328 ;
     RECT  8.777 57.792 9.116 58.488 ;
     RECT  9.116 57.792 9.133 58.728 ;
     RECT  8.561 31.104 9.137 31.896 ;
     RECT  8.309 36.96 9.137 36.984 ;
     RECT  8.675 105.456 9.137 107.16 ;
     RECT  8.921 53.328 9.155 54.408 ;
     RECT  9.133 57.792 9.157 58.824 ;
     RECT  9.059 17.904 9.169 17.928 ;
     RECT  9.101 70.8 9.169 72.6 ;
     RECT  8.957 3.84 9.173 3.864 ;
     RECT  8.669 60.576 9.173 63.24 ;
     RECT  9.169 70.704 9.173 72.6 ;
     RECT  9.101 74.16 9.196 74.328 ;
     RECT  9.173 60.576 9.197 61.656 ;
     RECT  8.243 46.512 9.205 49.272 ;
     RECT  9.137 106.512 9.245 107.16 ;
     RECT  9.173 70.704 9.253 71.832 ;
     RECT  8.243 84.816 9.277 84.84 ;
     RECT  8.561 86.88 9.277 86.904 ;
     RECT  9.197 59.856 9.281 61.656 ;
     RECT  9.155 53.328 9.299 54.36 ;
     RECT  9.205 46.464 9.313 49.272 ;
     RECT  9.253 70.56 9.34 71.832 ;
     RECT  9.26 14.544 9.347 14.568 ;
     RECT  8.104 40.608 9.349 43.32 ;
     RECT  8.243 44.304 9.349 45.288 ;
     RECT  9.313 46.464 9.349 49.56 ;
     RECT  8.723 5.088 9.353 5.208 ;
     RECT  9.245 106.56 9.353 107.16 ;
     RECT  9.277 90.048 9.361 90.072 ;
     RECT  8.243 91.44 9.385 91.464 ;
     RECT  9.157 57.792 9.389 58.872 ;
     RECT  9.34 70.704 9.395 71.832 ;
     RECT  8.771 38.736 9.445 39.336 ;
     RECT  8.453 94.704 9.457 96.36 ;
     RECT  9.073 98.688 9.457 99.72 ;
     RECT  9.385 21.648 9.469 21.672 ;
     RECT  9.385 91.44 9.497 91.896 ;
     RECT  9.457 98.688 9.497 99.96 ;
     RECT  9.395 70.704 9.533 70.872 ;
     RECT  8.525 23.808 9.565 23.832 ;
     RECT  9.353 106.56 9.569 106.632 ;
     RECT  9.349 40.608 9.587 49.56 ;
     RECT  9.281 60.768 9.587 61.656 ;
     RECT  9.569 106.608 9.635 106.632 ;
     RECT  9.065 67.344 9.637 67.416 ;
     RECT  9.445 38.736 9.641 39.384 ;
     RECT  8.777 55.632 9.641 56.52 ;
     RECT  9.641 55.92 9.649 56.52 ;
     RECT  9.587 44.4 9.677 49.56 ;
     RECT  9.641 38.736 9.683 39.288 ;
     RECT  9.457 94.704 9.683 96.6 ;
     RECT  9.565 97.632 9.683 97.656 ;
     RECT  9.173 62.64 9.709 63.24 ;
     RECT  8.561 33.12 9.713 34.776 ;
     RECT  9.389 57.792 9.721 58.728 ;
     RECT  9.137 105.456 9.733 105.48 ;
     RECT  9.713 33.12 9.74 34.104 ;
     RECT  9.497 99.936 9.749 99.96 ;
     RECT  9.587 40.608 9.779 43.08 ;
     RECT  8.104 88.32 9.781 88.344 ;
     RECT  9.587 61.008 9.793 61.656 ;
     RECT  9.683 38.736 9.821 39.24 ;
     RECT  9.74 32.88 9.827 34.104 ;
     RECT  9.721 57.792 9.857 58.488 ;
     RECT  9.637 67.344 9.857 68.136 ;
     RECT  8.921 51.408 9.877 52.344 ;
     RECT  8.921 93.504 9.884 93.624 ;
     RECT  9.877 50.64 9.889 52.344 ;
     RECT  9.677 48.816 9.923 49.56 ;
     RECT  9.137 31.104 9.925 31.656 ;
     RECT  9.829 104.256 9.953 104.28 ;
     RECT  9.709 62.64 9.961 63.288 ;
     RECT  9.961 62.64 9.965 63.432 ;
     RECT  9.733 105.264 9.965 105.48 ;
     RECT  9.884 93.312 9.971 93.624 ;
     RECT  9.965 62.784 9.997 63.432 ;
     RECT  9.923 48.912 10.001 49.56 ;
     RECT  9.683 94.704 10.001 96.36 ;
     RECT  9.953 104.16 10.001 104.28 ;
     RECT  8.483 101.424 10.033 101.928 ;
     RECT  10.001 49.104 10.037 49.56 ;
     RECT  9.997 62.784 10.037 64.392 ;
     RECT  10.001 104.16 10.037 104.184 ;
     RECT  10.037 63.312 10.073 64.392 ;
     RECT  10.073 63.408 10.109 64.392 ;
     RECT  9.677 44.88 10.115 47.736 ;
     RECT  9.965 105.456 10.141 105.48 ;
     RECT  10.115 47.376 10.145 47.736 ;
     RECT  9.793 61.632 10.145 61.656 ;
     RECT  10.033 100.176 10.165 101.928 ;
     RECT  9.277 86.88 10.213 87.192 ;
     RECT  9.781 88.32 10.213 88.392 ;
     RECT  9.821 38.736 10.253 38.904 ;
     RECT  10.165 100.176 10.253 102.072 ;
     RECT  9.637 89.472 10.259 90.024 ;
     RECT  10.259 89.472 10.281 89.496 ;
     RECT  10.165 21.072 10.289 21.096 ;
     RECT  10.037 49.536 10.307 49.56 ;
     RECT  9.277 84.384 10.307 84.84 ;
     RECT  9.889 50.64 10.325 52.584 ;
     RECT  10.001 94.704 10.361 95.16 ;
     RECT  9.779 40.656 10.397 43.08 ;
     RECT  9.857 67.392 10.397 68.136 ;
     RECT  9.353 5.184 10.412 5.208 ;
     RECT  9.649 55.92 10.433 56.136 ;
     RECT  10.141 105.456 10.453 105.528 ;
     RECT  10.412 4.512 10.499 5.208 ;
     RECT  10.213 86.88 10.499 88.392 ;
     RECT  9.533 70.8 10.501 70.872 ;
     RECT  10.499 86.88 10.541 87.864 ;
     RECT  9.925 30.864 10.547 31.656 ;
     RECT  10.465 59.856 10.549 59.88 ;
     RECT  10.453 105.456 10.597 105.576 ;
     RECT  9.857 57.792 10.609 58.392 ;
     RECT  10.556 3.312 10.643 3.336 ;
     RECT  10.109 64.368 10.643 64.392 ;
     RECT  10.597 105.456 10.673 105.816 ;
     RECT  10.115 44.88 10.681 46.296 ;
     RECT  10.609 57.696 10.739 58.392 ;
     RECT  9.637 28.128 10.787 28.152 ;
     RECT  10.547 30.864 10.789 30.888 ;
     RECT  10.397 41.136 10.789 43.08 ;
     RECT  10.681 44.16 10.789 46.296 ;
     RECT  10.325 50.64 10.793 52.488 ;
     RECT  9.497 98.688 10.825 98.904 ;
     RECT  10.253 100.176 10.825 101.928 ;
     RECT  10.739 58.224 10.829 58.392 ;
     RECT  10.673 105.456 10.829 106.584 ;
     RECT  10.145 47.712 10.883 47.736 ;
     RECT  10.541 86.88 10.883 87.192 ;
     RECT  10.753 103.68 10.885 103.704 ;
     RECT  10.789 30.768 10.931 30.888 ;
     RECT  9.299 53.568 10.931 54.36 ;
     RECT  10.883 87.168 10.931 87.192 ;
     RECT  10.825 98.688 10.931 101.928 ;
     RECT  10.829 106.56 10.933 106.584 ;
     RECT  10.931 54.288 10.937 54.36 ;
     RECT  10.253 38.736 10.979 38.76 ;
     RECT  10.829 58.368 10.979 58.392 ;
     RECT  9.565 23.808 11.027 25.176 ;
     RECT  10.931 100.176 11.045 101.928 ;
     RECT  10.981 54.384 11.068 54.408 ;
     RECT  10.933 106.56 11.077 107.16 ;
     RECT  10.433 56.112 11.081 56.136 ;
     RECT  11.045 100.656 11.117 101.928 ;
     RECT  10.793 50.64 11.132 51.672 ;
     RECT  10.789 41.136 11.153 46.296 ;
     RECT  11.132 50.064 11.219 51.672 ;
     RECT  10.501 70.8 11.219 71.784 ;
     RECT  11.153 41.136 11.225 45.048 ;
     RECT  11.077 106.56 11.261 107.88 ;
     RECT  11.225 41.136 11.297 45 ;
     RECT  10.885 103.2 11.297 103.704 ;
     RECT  8.597 26.256 11.315 26.28 ;
     RECT  11.228 56.256 11.315 56.28 ;
     RECT  11.117 101.232 11.317 101.928 ;
     RECT  10.897 47.856 11.405 47.88 ;
     RECT  10.931 30.864 11.411 30.888 ;
     RECT  11.219 50.256 11.411 51.672 ;
     RECT  9.169 17.664 11.459 17.928 ;
     RECT  9.971 93.504 11.459 93.624 ;
     RECT  11.413 104.736 11.5 104.76 ;
     RECT  9.529 15.984 11.507 16.008 ;
     RECT  9.497 91.776 11.507 91.896 ;
     RECT  8.525 6.192 11.555 6.84 ;
     RECT  8.104 79.776 11.555 79.8 ;
     RECT  11.027 24.528 11.603 25.176 ;
     RECT  10.001 96.336 11.603 96.36 ;
     RECT  11.297 41.136 11.621 44.28 ;
     RECT  11.411 50.928 11.621 51.672 ;
     RECT  11.317 101.232 11.773 102.648 ;
     RECT  11.621 44.16 11.909 44.28 ;
     RECT  11.555 6.72 11.981 6.84 ;
     RECT  10.931 98.688 11.981 98.904 ;
     RECT  10.499 5.184 12.035 5.208 ;
     RECT  11.459 93.6 12.035 93.624 ;
     RECT  11.653 103.728 12.053 103.752 ;
     RECT  8.104 13.344 12.083 13.368 ;
     RECT  10.361 95.136 12.083 95.16 ;
     RECT  11.261 106.56 12.089 107.16 ;
     RECT  11.459 17.904 12.131 17.928 ;
     RECT  11.507 91.872 12.131 91.896 ;
     RECT  11.909 44.16 12.161 44.184 ;
     RECT  10.397 68.112 12.188 68.136 ;
     RECT  11.773 101.232 12.337 102.6 ;
     RECT  12.089 106.56 12.581 106.68 ;
     RECT  12.337 101.136 12.877 102.6 ;
     RECT  12.229 104.88 12.997 104.904 ;
     RECT  12.581 105.984 12.997 106.68 ;
     RECT  12.997 104.88 13.057 106.68 ;
     RECT  11.981 6.816 13.208 6.84 ;
     RECT  11.603 25.152 13.208 25.176 ;
     RECT  9.827 33.648 13.208 34.104 ;
     RECT  11.621 41.136 13.208 42.552 ;
     RECT  11.153 46.224 13.208 46.296 ;
     RECT  11.621 51.648 13.208 51.672 ;
     RECT  12.188 67.728 13.208 68.136 ;
     RECT  11.219 70.8 13.208 70.824 ;
     RECT  9.196 74.304 13.208 74.328 ;
     RECT  8.531 77.568 13.208 77.592 ;
     RECT  10.307 84.816 13.208 84.84 ;
     RECT  11.981 98.784 13.208 98.904 ;
     RECT  12.877 100.32 13.208 102.6 ;
     RECT  13.057 104.88 13.208 107.208 ;
     RECT  13.208 2.148 13.312 107.208 ;
     RECT  13.312 2.418 13.477 107.208 ;
     RECT  13.477 2.418 13.504 107.832 ;
     RECT  13.504 104.832 13.619 104.856 ;
     RECT  13.504 105.984 13.673 107.832 ;
     RECT  13.673 106.512 14.093 107.832 ;
     RECT  14.093 106.512 14.645 107.88 ;
     RECT  13.504 42.48 14.717 42.504 ;
     RECT  14.569 105.408 14.723 105.432 ;
     RECT  14.645 106.512 14.821 107.16 ;
     RECT  13.504 98.64 14.893 103.224 ;
     RECT  14.893 98.496 14.969 103.224 ;
     RECT  14.969 102.096 15.037 103.224 ;
     RECT  13.504 3.024 15.061 3.048 ;
     RECT  15.037 102.096 15.253 103.752 ;
     RECT  14.885 104.832 15.253 104.856 ;
     RECT  14.969 98.496 15.325 100.872 ;
     RECT  14.821 105.984 15.365 107.16 ;
     RECT  15.061 3.024 15.397 3.432 ;
     RECT  15.325 98.208 15.433 100.872 ;
     RECT  15.365 106.512 15.613 107.16 ;
     RECT  15.433 98.16 15.637 100.872 ;
     RECT  15.613 106.512 15.827 107.208 ;
     RECT  15.637 97.728 15.833 100.872 ;
     RECT  15.833 97.968 16.213 100.872 ;
     RECT  15.253 102.096 16.213 104.856 ;
     RECT  16.213 97.968 16.337 104.856 ;
     RECT  16.337 99.744 16.481 104.856 ;
     RECT  15.827 106.512 16.481 107.16 ;
     RECT  16.337 97.968 16.589 98.232 ;
     RECT  16.481 99.744 16.625 101.448 ;
     RECT  16.481 102.432 16.885 104.856 ;
     RECT  16.625 99.84 16.985 101.448 ;
     RECT  16.909 0.576 17.017 0.6 ;
     RECT  16.837 1.68 17.089 1.704 ;
     RECT  15.397 3.024 17.089 3.576 ;
     RECT  16.589 97.968 17.093 98.088 ;
     RECT  16.985 99.984 17.237 101.448 ;
     RECT  17.017 0.096 17.485 0.6 ;
     RECT  17.089 1.68 17.485 3.576 ;
     RECT  17.237 99.984 17.489 101.064 ;
     RECT  17.485 0.096 17.555 3.576 ;
     RECT  16.481 106.56 17.669 107.16 ;
     RECT  16.885 102.432 17.917 105.48 ;
     RECT  17.737 98.352 17.953 98.904 ;
     RECT  17.917 102.336 18.025 105.48 ;
     RECT  17.669 106.56 18.025 106.632 ;
     RECT  17.953 98.352 18.133 99 ;
     RECT  17.489 99.984 18.133 101.016 ;
     RECT  18.133 98.352 18.241 101.016 ;
     RECT  17.555 2.256 18.469 3.576 ;
     RECT  18.241 98.112 18.469 101.016 ;
     RECT  18.025 102.336 18.469 106.632 ;
     RECT  17.555 0.096 18.515 1.128 ;
     RECT  18.469 2.256 18.608 4.152 ;
     RECT  13.504 6.816 18.608 6.84 ;
     RECT  13.504 34.08 18.608 34.104 ;
     RECT  13.504 41.136 18.608 41.16 ;
     RECT  13.504 46.224 18.608 46.296 ;
     RECT  13.504 51.648 18.608 51.672 ;
     RECT  13.504 70.8 18.608 70.824 ;
     RECT  13.504 77.568 18.608 77.592 ;
     RECT  18.469 98.112 18.608 106.632 ;
     RECT  18.515 0.096 18.611 0.6 ;
     RECT  18.608 2.148 18.611 106.632 ;
     RECT  18.611 0.528 18.774 0.6 ;
     RECT  18.774 0.576 18.892 0.6 ;
     RECT  18.611 2.148 18.904 106.584 ;
     RECT  18.904 2.148 18.917 4.152 ;
     RECT  18.904 97.824 19.001 106.584 ;
     RECT  19.381 107.808 19.523 107.832 ;
     RECT  19.001 97.824 19.933 100.392 ;
     RECT  19.933 97.68 19.969 100.392 ;
     RECT  20.005 0.576 20.077 0.6 ;
     RECT  18.917 1.68 20.077 4.152 ;
     RECT  19.001 101.472 20.081 106.584 ;
     RECT  20.077 0.576 20.089 4.152 ;
     RECT  20.089 1.104 20.195 4.152 ;
     RECT  20.149 107.136 20.333 107.16 ;
     RECT  20.081 101.472 20.441 106.056 ;
     RECT  19.969 97.488 20.545 100.392 ;
     RECT  20.441 101.472 20.545 104.472 ;
     RECT  20.545 97.488 20.549 104.472 ;
     RECT  18.904 70.8 20.761 70.824 ;
     RECT  20.441 105.456 20.873 106.056 ;
     RECT  20.761 70.704 21.089 70.824 ;
     RECT  20.549 98.352 21.089 104.28 ;
     RECT  21.089 98.544 21.553 104.28 ;
     RECT  20.873 105.456 21.553 106.008 ;
     RECT  21.493 107.808 21.635 107.832 ;
     RECT  21.553 98.544 21.637 106.008 ;
     RECT  20.195 1.728 21.697 4.152 ;
     RECT  21.697 1.104 21.827 4.152 ;
     RECT  21.637 98.544 22.057 104.328 ;
     RECT  21.637 105.408 22.241 106.008 ;
     RECT  22.241 105.984 22.309 106.008 ;
     RECT  21.788 107.184 22.309 107.208 ;
     RECT  22.237 0.576 22.321 0.6 ;
     RECT  22.309 105.984 22.451 107.208 ;
     RECT  21.089 70.704 22.813 70.728 ;
     RECT  18.904 77.568 22.813 77.592 ;
     RECT  22.813 70.704 22.853 70.824 ;
     RECT  22.813 77.568 22.853 77.688 ;
     RECT  22.057 98.064 22.885 104.328 ;
     RECT  22.633 0.096 22.931 0.552 ;
     RECT  22.931 0.528 23.027 0.552 ;
     RECT  21.827 1.728 23.033 4.152 ;
     RECT  22.885 98.064 23.509 105 ;
     RECT  22.451 105.984 23.509 106.584 ;
     RECT  23.461 0.576 23.545 0.6 ;
     RECT  23.509 98.064 23.573 106.584 ;
     RECT  23.033 1.728 23.713 3.912 ;
     RECT  23.573 98.064 23.795 106.104 ;
     RECT  23.713 1.632 23.987 3.912 ;
     RECT  23.987 1.728 24.008 3.912 ;
     RECT  18.904 6.816 24.008 6.84 ;
     RECT  18.904 34.08 24.008 34.104 ;
     RECT  18.904 41.136 24.008 41.16 ;
     RECT  18.904 46.224 24.008 46.296 ;
     RECT  18.904 51.648 24.008 51.672 ;
     RECT  22.853 70.8 24.008 70.824 ;
     RECT  22.853 77.664 24.008 77.688 ;
     RECT  23.795 98.064 24.008 106.008 ;
     RECT  23.989 107.808 24.101 107.832 ;
     RECT  24.101 107.808 24.185 107.88 ;
     RECT  24.008 1.728 24.304 106.008 ;
     RECT  24.185 107.808 24.361 107.832 ;
     RECT  24.304 77.52 24.419 77.688 ;
     RECT  24.304 97.968 24.445 106.008 ;
     RECT  24.361 107.136 24.467 107.832 ;
     RECT  24.445 98.064 24.473 106.008 ;
     RECT  24.304 1.728 24.581 3.912 ;
     RECT  24.473 98.688 24.617 106.008 ;
     RECT  24.617 99.936 24.725 106.008 ;
     RECT  24.685 0.576 24.803 0.6 ;
     RECT  24.725 104.88 24.833 106.008 ;
     RECT  24.725 99.936 25.013 103.752 ;
     RECT  24.833 105.456 25.139 106.008 ;
     RECT  25.139 105.984 25.189 106.008 ;
     RECT  24.467 107.136 25.189 107.16 ;
     RECT  25.189 105.984 25.429 107.16 ;
     RECT  25.429 105.984 25.589 107.88 ;
     RECT  24.581 1.728 25.621 3.864 ;
     RECT  25.589 105.984 25.661 107.16 ;
     RECT  25.013 99.936 25.693 101.448 ;
     RECT  25.621 1.728 25.705 3.96 ;
     RECT  25.013 102.48 25.837 103.752 ;
     RECT  24.617 98.688 25.873 98.712 ;
     RECT  24.304 34.512 25.909 34.536 ;
     RECT  25.873 98.64 25.937 98.712 ;
     RECT  25.693 99.696 25.937 101.448 ;
     RECT  25.909 34.128 25.955 34.536 ;
     RECT  25.937 98.64 26.053 101.448 ;
     RECT  25.837 102.48 26.053 104.856 ;
     RECT  25.909 53.568 26.149 53.592 ;
     RECT  24.304 70.8 26.149 70.824 ;
     RECT  26.053 98.64 26.165 104.856 ;
     RECT  26.149 53.568 26.195 53.976 ;
     RECT  26.149 70.608 26.195 70.824 ;
     RECT  26.195 70.608 26.236 70.68 ;
     RECT  25.705 1.728 26.252 3.864 ;
     RECT  26.252 1.632 26.339 3.864 ;
     RECT  26.165 98.688 26.513 104.856 ;
     RECT  25.661 106.56 26.525 107.16 ;
     RECT  26.513 98.688 26.597 104.904 ;
     RECT  26.525 106.56 26.677 106.584 ;
     RECT  24.419 77.52 26.771 77.544 ;
     RECT  26.195 53.856 26.813 53.976 ;
     RECT  26.773 0.096 26.876 0.12 ;
     RECT  26.597 98.688 26.957 101.208 ;
     RECT  26.597 102.48 27.029 104.328 ;
     RECT  26.876 0.096 27.101 0.552 ;
     RECT  26.957 99.552 27.101 101.208 ;
     RECT  26.677 105.984 27.136 106.584 ;
     RECT  27.136 105.936 27.245 106.584 ;
     RECT  26.339 1.68 27.443 3.864 ;
     RECT  26.236 70.656 27.497 70.68 ;
     RECT  27.493 107.856 27.605 107.88 ;
     RECT  27.589 70.464 27.676 70.488 ;
     RECT  27.101 0.528 27.683 0.552 ;
     RECT  27.029 103.728 27.709 104.328 ;
     RECT  27.101 99.696 27.781 101.208 ;
     RECT  27.029 102.48 27.781 102.504 ;
     RECT  27.443 1.728 27.965 3.864 ;
     RECT  27.709 103.728 27.997 104.856 ;
     RECT  28.033 98.64 28.145 98.664 ;
     RECT  27.997 103.536 28.321 104.856 ;
     RECT  27.965 1.728 28.361 3.336 ;
     RECT  27.245 105.984 28.397 106.584 ;
     RECT  28.397 105.984 28.421 106.008 ;
     RECT  27.781 99.696 28.537 102.504 ;
     RECT  28.321 103.536 28.537 104.904 ;
     RECT  28.429 0.096 28.739 0.12 ;
     RECT  28.537 99.696 28.933 104.904 ;
     RECT  28.421 105.888 28.933 106.008 ;
     RECT  28.361 1.728 29.408 2.28 ;
     RECT  28.361 3.312 29.408 3.336 ;
     RECT  24.304 6.816 29.408 6.84 ;
     RECT  25.955 34.128 29.408 34.152 ;
     RECT  24.304 41.136 29.408 41.16 ;
     RECT  24.304 46.224 29.408 46.296 ;
     RECT  24.304 51.648 29.408 51.672 ;
     RECT  26.813 53.856 29.408 53.88 ;
     RECT  27.589 58.656 29.408 58.68 ;
     RECT  28.933 99.696 29.408 106.008 ;
     RECT  29.408 1.728 29.413 106.008 ;
     RECT  29.413 1.728 29.585 106.056 ;
     RECT  29.585 1.728 29.704 106.008 ;
     RECT  29.704 1.728 30.157 2.28 ;
     RECT  29.704 100.512 30.161 106.008 ;
     RECT  30.161 100.512 30.197 105.912 ;
     RECT  30.157 1.68 30.229 2.28 ;
     RECT  30.197 100.512 30.233 105.48 ;
     RECT  30.233 100.8 30.413 105.48 ;
     RECT  30.413 100.896 30.737 105.48 ;
     RECT  30.737 100.896 30.809 104.52 ;
     RECT  30.809 101.472 30.953 104.52 ;
     RECT  30.953 101.808 31.025 104.52 ;
     RECT  29.704 34.512 31.043 34.536 ;
     RECT  29.704 53.856 31.057 53.88 ;
     RECT  30.229 1.632 31.129 2.28 ;
     RECT  31.025 102.096 31.169 104.52 ;
     RECT  30.769 98.64 31.349 98.664 ;
     RECT  31.169 102.288 31.385 104.52 ;
     RECT  31.057 53.856 31.421 54.12 ;
     RECT  31.385 102.336 31.565 104.52 ;
     RECT  31.129 1.104 31.571 2.28 ;
     RECT  31.565 102.336 31.637 102.84 ;
     RECT  31.637 102.624 31.817 102.648 ;
     RECT  31.571 1.632 31.955 2.28 ;
     RECT  31.565 103.824 32.069 104.52 ;
     RECT  32.069 103.824 32.141 103.848 ;
     RECT  30.997 44.352 33.073 44.376 ;
     RECT  33.073 43.776 33.257 44.376 ;
     RECT  31.955 1.728 33.433 2.28 ;
     RECT  33.433 1.68 33.731 2.28 ;
     RECT  33.731 1.728 33.827 2.28 ;
     RECT  33.827 1.728 33.985 1.752 ;
     RECT  29.704 6.816 34.808 6.84 ;
     RECT  29.704 41.136 34.808 41.16 ;
     RECT  33.257 44.352 34.808 44.376 ;
     RECT  29.704 46.224 34.808 46.296 ;
     RECT  29.704 51.648 34.808 51.672 ;
     RECT  31.421 54.096 34.808 54.12 ;
     RECT  29.704 58.656 34.808 58.68 ;
     RECT  34.808 2.148 34.912 105.852 ;
     RECT  34.912 2.418 35.104 105.582 ;
     RECT  35.104 41.136 37.649 41.16 ;
     RECT  38.113 43.344 38.348 43.368 ;
     RECT  35.104 44.352 38.348 44.376 ;
     RECT  38.348 43.344 38.389 44.376 ;
     RECT  35.104 46.224 38.389 46.296 ;
     RECT  38.149 42.288 38.437 42.312 ;
     RECT  38.389 45.504 38.581 46.296 ;
     RECT  38.437 41.904 38.609 42.312 ;
     RECT  38.389 43.296 38.609 44.376 ;
     RECT  38.509 40.896 38.629 40.92 ;
     RECT  38.609 41.904 38.629 44.376 ;
     RECT  38.629 40.896 38.653 44.376 ;
     RECT  38.581 45.456 38.653 46.296 ;
     RECT  38.653 40.896 38.675 46.296 ;
     RECT  38.675 40.896 38.684 41.448 ;
     RECT  38.675 42.768 38.693 46.296 ;
     RECT  35.104 6.816 38.771 6.84 ;
     RECT  38.684 40.464 38.771 41.448 ;
     RECT  38.693 43.296 39.877 46.296 ;
     RECT  38.771 41.424 40.093 41.448 ;
     RECT  38.725 3.552 40.208 3.576 ;
     RECT  40.093 40.56 40.208 41.784 ;
     RECT  39.877 42.864 40.208 46.296 ;
     RECT  40.069 49.2 40.208 49.224 ;
     RECT  35.104 51.648 40.208 51.672 ;
     RECT  35.104 54.096 40.208 54.12 ;
     RECT  35.104 58.656 40.208 58.68 ;
     RECT  40.208 2.148 40.312 105.852 ;
     RECT  40.312 2.418 40.504 105.582 ;
     RECT  40.489 0.576 40.573 0.6 ;
     RECT  40.504 54.096 40.691 54.12 ;
     RECT  40.501 107.856 40.691 107.88 ;
     RECT  40.504 40.56 40.961 42.456 ;
     RECT  40.961 40.992 41.429 42.456 ;
     RECT  41.429 42.432 41.605 42.456 ;
     RECT  40.504 43.44 41.605 46.296 ;
     RECT  41.605 42.432 42.401 46.296 ;
     RECT  41.429 40.992 42.421 41.016 ;
     RECT  42.421 40.368 42.467 41.016 ;
     RECT  40.504 39.36 42.501 39.384 ;
     RECT  42.467 40.368 43.193 40.632 ;
     RECT  42.401 42.48 43.369 46.296 ;
     RECT  43.369 41.664 44.413 46.296 ;
     RECT  43.193 40.608 45.608 40.632 ;
     RECT  44.413 41.616 45.608 46.296 ;
     RECT  40.504 51.648 45.608 51.672 ;
     RECT  40.504 58.656 45.608 58.68 ;
     RECT  45.608 2.148 45.712 105.852 ;
     RECT  45.712 2.148 45.904 105.582 ;
     RECT  45.904 40.608 46.333 47.208 ;
     RECT  46.501 1.728 46.585 1.752 ;
     RECT  46.333 40.608 46.721 41.784 ;
     RECT  45.904 58.656 46.739 59.64 ;
     RECT  46.333 42.864 46.933 47.208 ;
     RECT  46.933 42.864 47.029 47.592 ;
     RECT  47.029 42.864 47.075 47.64 ;
     RECT  47.075 47.568 47.116 47.64 ;
     RECT  46.897 53.28 47.221 53.304 ;
     RECT  45.904 51.648 47.267 51.672 ;
     RECT  47.221 53.28 47.267 53.592 ;
     RECT  46.721 41.712 47.581 41.784 ;
     RECT  47.075 42.864 47.581 46.584 ;
     RECT  46.739 58.656 47.761 58.68 ;
     RECT  46.721 40.608 47.852 40.632 ;
     RECT  47.581 41.712 47.852 46.584 ;
     RECT  47.852 40.608 47.939 46.584 ;
     RECT  47.948 48.864 48.035 48.888 ;
     RECT  47.116 47.568 48.089 47.592 ;
     RECT  47.939 43.008 48.157 46.584 ;
     RECT  47.267 53.568 48.193 53.592 ;
     RECT  48.157 49.008 48.265 49.56 ;
     RECT  48.265 49.008 48.373 49.992 ;
     RECT  48.157 43.008 48.377 47.304 ;
     RECT  45.904 55.968 48.428 55.992 ;
     RECT  47.761 58.128 48.428 58.68 ;
     RECT  48.193 53.568 48.469 54.12 ;
     RECT  48.428 58.128 48.469 59.256 ;
     RECT  45.904 60.816 48.469 60.84 ;
     RECT  48.428 55.968 48.515 56.28 ;
     RECT  48.469 57.504 48.515 59.256 ;
     RECT  47.293 62.16 48.553 62.184 ;
     RECT  48.515 57.504 48.556 58.728 ;
     RECT  48.469 53.568 48.593 54.84 ;
     RECT  48.469 60.384 48.629 60.84 ;
     RECT  48.553 62.16 48.629 62.568 ;
     RECT  48.593 53.568 48.733 53.784 ;
     RECT  48.629 62.544 49.013 62.568 ;
     RECT  49.013 62.544 49.091 63.288 ;
     RECT  49.091 62.832 49.097 63.288 ;
     RECT  47.939 41.712 49.165 41.976 ;
     RECT  48.377 43.008 49.165 45.048 ;
     RECT  48.373 49.008 49.169 50.088 ;
     RECT  49.165 41.712 49.241 45.048 ;
     RECT  48.556 57.6 49.241 58.68 ;
     RECT  49.241 41.712 49.277 43.176 ;
     RECT  48.629 60.384 49.313 60.408 ;
     RECT  49.169 49.008 49.381 49.992 ;
     RECT  49.34 52.176 49.427 52.2 ;
     RECT  48.733 53.28 49.427 53.784 ;
     RECT  48.377 46.032 49.449 47.304 ;
     RECT  49.381 48.672 49.468 49.992 ;
     RECT  49.427 53.76 49.468 53.784 ;
     RECT  49.277 41.712 49.853 41.736 ;
     RECT  49.097 62.832 49.961 63 ;
     RECT  49.241 44.16 50.209 45.048 ;
     RECT  50.209 43.92 50.533 45.048 ;
     RECT  49.449 46.032 50.533 46.584 ;
     RECT  49.921 61.392 50.533 61.416 ;
     RECT  49.468 49.536 50.677 49.992 ;
     RECT  48.593 54.816 50.677 54.84 ;
     RECT  49.241 58.656 50.677 58.68 ;
     RECT  50.533 43.92 50.749 46.584 ;
     RECT  50.677 49.536 50.749 50.328 ;
     RECT  50.732 51.648 50.749 51.672 ;
     RECT  50.749 49.536 50.773 51.672 ;
     RECT  50.533 61.392 50.78 61.848 ;
     RECT  49.241 57.6 50.821 57.624 ;
     RECT  50.677 58.656 50.821 59.64 ;
     RECT  49.961 62.976 50.821 63 ;
     RECT  50.773 49.536 50.857 53.064 ;
     RECT  50.677 54.192 50.857 54.84 ;
     RECT  50.749 43.392 51.008 46.872 ;
     RECT  50.857 49.536 51.008 54.84 ;
     RECT  50.821 57.6 51.008 59.64 ;
     RECT  50.78 60.624 51.008 61.848 ;
     RECT  50.821 62.976 51.008 63.288 ;
     RECT  51.008 2.148 51.112 105.852 ;
     RECT  51.112 2.418 51.304 105.582 ;
     RECT  51.304 53.808 51.365 54.216 ;
     RECT  51.304 43.392 51.401 48.504 ;
     RECT  51.304 49.776 51.617 51.48 ;
     RECT  51.617 50.304 51.653 51.48 ;
     RECT  51.304 61.68 51.689 61.752 ;
     RECT  51.653 50.304 51.761 50.952 ;
     RECT  51.401 43.392 51.923 47.16 ;
     RECT  51.689 61.68 51.977 61.704 ;
     RECT  51.365 54.192 52.013 54.216 ;
     RECT  51.304 52.512 52.049 52.536 ;
     RECT  51.761 50.928 52.229 50.952 ;
     RECT  51.304 55.872 52.333 55.896 ;
     RECT  51.304 41.616 52.405 42.168 ;
     RECT  51.923 43.488 52.451 47.16 ;
     RECT  52.405 41.184 52.693 42.168 ;
     RECT  52.451 44.112 52.697 47.16 ;
     RECT  52.333 55.392 52.697 55.896 ;
     RECT  52.697 44.304 52.801 47.16 ;
     RECT  51.401 48.48 52.801 48.504 ;
     RECT  52.801 44.304 52.877 48.504 ;
     RECT  52.693 41.088 52.981 42.168 ;
     RECT  52.697 55.872 52.985 55.896 ;
     RECT  52.877 44.304 53.309 47.88 ;
     RECT  53.377 52.416 53.485 52.44 ;
     RECT  53.485 51.888 53.521 52.44 ;
     RECT  52.981 41.088 53.525 42.744 ;
     RECT  53.521 51.168 53.557 52.44 ;
     RECT  52.909 53.616 53.557 53.64 ;
     RECT  51.304 58.512 53.593 58.68 ;
     RECT  53.557 50.736 53.603 53.64 ;
     RECT  53.593 58.512 53.605 59.304 ;
     RECT  53.603 50.736 53.633 52.008 ;
     RECT  53.605 58.08 53.651 59.304 ;
     RECT  53.651 59.088 53.677 59.304 ;
     RECT  53.633 50.736 53.737 51.912 ;
     RECT  53.309 44.304 53.809 47.784 ;
     RECT  53.809 44.208 53.845 47.784 ;
     RECT  53.525 41.088 53.881 42.552 ;
     RECT  53.737 50.544 53.993 51.912 ;
     RECT  52.585 39.072 54.133 39.096 ;
     RECT  53.881 40.8 54.133 42.552 ;
     RECT  53.017 56.976 54.173 57 ;
     RECT  53.993 50.544 54.281 51.192 ;
     RECT  53.603 53.04 54.373 53.64 ;
     RECT  53.953 54.672 54.373 54.696 ;
     RECT  54.133 39.072 54.389 42.552 ;
     RECT  54.373 53.04 54.419 54.696 ;
     RECT  54.389 40.368 54.637 42.552 ;
     RECT  53.845 43.776 54.637 47.784 ;
     RECT  53.651 58.08 54.709 58.104 ;
     RECT  54.709 57.936 54.749 58.104 ;
     RECT  53.677 59.088 54.949 59.112 ;
     RECT  54.493 60.912 54.949 60.936 ;
     RECT  54.949 59.088 54.995 61.608 ;
     RECT  54.995 59.088 55.036 60.312 ;
     RECT  54.995 61.584 55.037 61.608 ;
     RECT  54.637 40.368 55.285 47.784 ;
     RECT  53.629 49.008 55.285 49.032 ;
     RECT  54.419 53.04 55.289 54.12 ;
     RECT  55.285 40.368 55.321 49.032 ;
     RECT  54.281 50.544 55.34 51.144 ;
     RECT  55.34 50.544 55.381 51.288 ;
     RECT  54.373 55.68 55.397 55.704 ;
     RECT  55.381 50.544 55.427 51.96 ;
     RECT  55.321 40.368 55.433 49.128 ;
     RECT  55.427 50.544 55.433 50.76 ;
     RECT  55.427 51.936 55.465 51.96 ;
     RECT  55.289 53.04 55.465 53.832 ;
     RECT  54.749 57.936 55.717 57.96 ;
     RECT  55.717 57.312 55.861 57.96 ;
     RECT  55.753 59.04 55.861 59.064 ;
     RECT  55.036 60.288 56.293 60.312 ;
     RECT  55.433 40.368 56.408 40.92 ;
     RECT  55.433 42.192 56.408 49.128 ;
     RECT  55.433 50.736 56.408 50.76 ;
     RECT  55.465 51.936 56.408 53.832 ;
     RECT  55.861 56.88 56.408 59.064 ;
     RECT  56.293 60.192 56.408 60.312 ;
     RECT  55.753 62.256 56.408 62.28 ;
     RECT  56.077 64.416 56.408 64.44 ;
     RECT  56.408 2.148 56.512 105.852 ;
     RECT  56.512 2.418 56.704 105.582 ;
     RECT  56.704 40.416 56.819 54.456 ;
     RECT  56.704 56.448 56.909 57.96 ;
     RECT  56.704 59.424 57.053 60.696 ;
     RECT  56.704 64.416 57.053 64.44 ;
     RECT  57.053 60.288 57.107 60.696 ;
     RECT  56.704 63.264 57.125 63.288 ;
     RECT  56.909 56.448 57.305 56.904 ;
     RECT  56.704 62.256 57.305 62.28 ;
     RECT  56.909 57.936 57.593 57.96 ;
     RECT  56.819 44.16 57.635 54.456 ;
     RECT  57.692 36.096 57.779 36.12 ;
     RECT  57.305 56.448 58.213 56.472 ;
     RECT  57.107 60.672 58.273 60.696 ;
     RECT  58.213 55.776 58.277 56.472 ;
     RECT  58.277 55.776 58.3 55.8 ;
     RECT  56.819 40.416 58.453 43.128 ;
     RECT  57.635 44.16 58.453 54.408 ;
     RECT  58.453 40.416 58.601 54.408 ;
     RECT  58.273 60.672 58.601 61.416 ;
     RECT  58.601 40.416 58.633 47.832 ;
     RECT  58.601 48.816 58.633 54.408 ;
     RECT  58.601 61.392 58.673 61.416 ;
     RECT  58.633 48.816 58.705 54.696 ;
     RECT  58.705 48.816 58.741 54.744 ;
     RECT  58.633 39.984 58.781 47.832 ;
     RECT  58.781 40.416 58.853 45.192 ;
     RECT  58.957 38.784 59.069 38.808 ;
     RECT  58.853 40.416 59.257 45.048 ;
     RECT  58.741 48.816 59.269 54.888 ;
     RECT  59.173 37.008 59.321 37.032 ;
     RECT  59.269 48.816 59.389 54.936 ;
     RECT  59.389 48.816 59.393 55.08 ;
     RECT  59.393 48.816 59.429 51 ;
     RECT  59.257 40.416 59.501 45 ;
     RECT  59.429 49.344 59.501 51 ;
     RECT  58.781 46.368 59.573 47.832 ;
     RECT  59.393 52.128 59.573 55.08 ;
     RECT  59.564 35.568 59.651 35.592 ;
     RECT  59.501 40.8 59.717 45 ;
     RECT  59.501 49.392 59.753 51 ;
     RECT  59.413 58.128 59.861 58.152 ;
     RECT  59.753 49.392 59.897 50.856 ;
     RECT  59.717 40.8 59.933 42.744 ;
     RECT  59.717 43.872 59.933 45 ;
     RECT  59.897 49.392 59.933 50.472 ;
     RECT  59.933 49.44 59.969 50.472 ;
     RECT  59.573 46.368 60.005 47.256 ;
     RECT  59.933 43.872 60.113 44.424 ;
     RECT  59.969 49.44 60.113 50.232 ;
     RECT  60.005 46.944 60.149 47.256 ;
     RECT  59.573 52.128 60.365 52.584 ;
     RECT  60.113 49.44 60.473 50.04 ;
     RECT  60.149 47.232 60.581 47.256 ;
     RECT  60.62 38.784 60.677 38.808 ;
     RECT  60.677 38.784 60.761 39.336 ;
     RECT  59.573 53.856 60.793 55.08 ;
     RECT  60.829 37.632 60.937 37.656 ;
     RECT  60.365 52.272 60.973 52.584 ;
     RECT  60.113 44.4 61.045 44.424 ;
     RECT  61.045 44.4 61.189 44.952 ;
     RECT  61.045 57.6 61.189 57.624 ;
     RECT  61.189 43.92 61.225 44.952 ;
     RECT  60.937 37.584 61.261 37.656 ;
     RECT  60.973 52.272 61.297 52.824 ;
     RECT  60.793 53.856 61.297 55.224 ;
     RECT  60.473 49.44 61.34 49.848 ;
     RECT  61.225 43.92 61.369 45.768 ;
     RECT  61.189 57.6 61.381 57.816 ;
     RECT  61.261 37.488 61.429 37.656 ;
     RECT  59.933 40.8 61.429 42.264 ;
     RECT  61.369 43.344 61.429 45.768 ;
     RECT  61.297 52.272 61.429 55.224 ;
     RECT  61.429 37.344 61.477 37.656 ;
     RECT  60.761 38.784 61.477 39.144 ;
     RECT  61.429 52.272 61.525 55.896 ;
     RECT  61.525 52.224 61.532 55.896 ;
     RECT  61.532 51.936 61.573 55.896 ;
     RECT  61.381 57.024 61.573 57.816 ;
     RECT  61.429 40.8 61.585 45.768 ;
     RECT  61.573 57.024 61.621 58.152 ;
     RECT  61.34 49.008 61.657 49.848 ;
     RECT  61.477 36.336 61.765 36.36 ;
     RECT  61.477 37.344 61.765 39.144 ;
     RECT  61.117 35.184 61.808 35.208 ;
     RECT  61.765 36.336 61.808 39.144 ;
     RECT  61.585 40.176 61.808 46.728 ;
     RECT  61.657 48.336 61.808 49.848 ;
     RECT  61.573 51.504 61.808 55.896 ;
     RECT  61.621 57.024 61.808 58.68 ;
     RECT  61.808 2.148 61.912 105.852 ;
     RECT  61.912 2.418 62.104 105.582 ;
     RECT  62.104 58.656 62.129 58.728 ;
     RECT  62.104 55.2 62.453 55.224 ;
     RECT  62.129 58.704 62.461 58.728 ;
     RECT  62.104 36.816 62.963 37.656 ;
     RECT  62.104 57.024 62.963 57.672 ;
     RECT  62.104 35.184 63.011 35.208 ;
     RECT  62.963 57.024 63.011 57.096 ;
     RECT  62.104 40.416 63.097 40.968 ;
     RECT  62.104 42.048 63.097 42.072 ;
     RECT  63.097 40.416 63.133 42.072 ;
     RECT  62.104 43.2 63.133 46.248 ;
     RECT  63.133 40.416 63.241 46.248 ;
     RECT  62.104 47.616 63.241 53.832 ;
     RECT  63.241 40.416 63.385 53.832 ;
     RECT  62.963 36.816 63.539 36.84 ;
     RECT  63.011 57.024 63.539 57.048 ;
     RECT  63.385 40.032 64.681 53.832 ;
     RECT  64.681 40.032 64.764 53.976 ;
    LAYER M5 ;
     RECT  4.032 0.016 8.808 0.131 ;
     RECT  17.04 0.016 33.96 0.611 ;
     RECT  4.176 0.131 8.808 1.763 ;
     RECT  17.184 0.611 33.96 1.763 ;
     RECT  4.32 1.763 8.808 1.811 ;
     RECT  17.184 1.763 33.816 1.811 ;
     RECT  4.32 1.811 8.424 1.859 ;
     RECT  2.4 2.137 2.52 2.151 ;
     RECT  13.2 2.137 13.32 2.151 ;
     RECT  34.8 2.137 34.92 2.151 ;
     RECT  40.2 2.137 40.32 2.151 ;
     RECT  51 2.137 51.12 2.151 ;
     RECT  56.4 2.137 56.52 2.151 ;
     RECT  61.8 2.137 61.92 2.151 ;
     RECT  4.704 1.859 8.424 2.243 ;
     RECT  4.704 2.243 5.544 2.291 ;
     RECT  6.528 2.243 8.424 2.291 ;
     RECT  17.184 1.811 26.472 2.291 ;
     RECT  27.504 1.811 33.816 2.291 ;
     RECT  2.4 2.151 2.712 2.821 ;
     RECT  23.616 2.291 25.176 2.915 ;
     RECT  13.2 2.151 13.512 3.013 ;
     RECT  18.6 2.291 19.656 3.349 ;
     RECT  20.688 2.291 20.904 3.349 ;
     RECT  13.2 3.013 14.472 3.397 ;
     RECT  13.2 3.397 15.096 3.541 ;
     RECT  21.888 2.291 22.056 3.541 ;
     RECT  7.8 2.291 8.112 3.925 ;
     RECT  18.6 3.349 20.904 4.117 ;
     RECT  7.8 3.925 8.472 4.501 ;
     RECT  10.608 3.301 10.632 4.501 ;
     RECT  6.24 5.077 6.264 5.653 ;
     RECT  7.8 4.501 8.712 5.653 ;
     RECT  10.464 4.501 10.632 6.181 ;
     RECT  12 5.173 12.024 6.181 ;
     RECT  4.464 4.501 4.488 6.229 ;
     RECT  5.616 5.653 8.712 6.229 ;
     RECT  10.464 6.181 12.024 13.333 ;
     RECT  4.464 6.229 8.712 14.533 ;
     RECT  0.144 16.789 0.168 16.979 ;
     RECT  10.464 13.333 12.072 17.893 ;
     RECT  4.464 14.533 9.336 21.061 ;
     RECT  10.464 17.893 12.12 21.061 ;
     RECT  2.4 2.821 3.432 25.045 ;
     RECT  4.464 21.061 12.12 25.045 ;
     RECT  2.4 25.045 12.12 25.141 ;
     RECT  13.2 3.541 15.432 25.141 ;
     RECT  25.632 3.925 25.656 34.117 ;
     RECT  61.8 2.151 62.112 35.173 ;
     RECT  61.8 35.173 63 36.325 ;
     RECT  61.488 36.325 63 36.805 ;
     RECT  59.616 35.557 59.64 36.997 ;
     RECT  61.488 36.805 63.528 37.333 ;
     RECT  61.44 37.333 63.528 37.477 ;
     RECT  61.392 37.477 63.528 37.573 ;
     RECT  2.4 25.141 15.432 37.621 ;
     RECT  2.304 37.621 15.432 37.859 ;
     RECT  60.96 37.573 63.528 38.773 ;
     RECT  0.144 40.069 0.168 40.211 ;
     RECT  56.4 2.151 56.712 40.405 ;
     RECT  57.744 36.085 57.768 40.405 ;
     RECT  38.736 3.541 38.76 40.499 ;
     RECT  54.144 39.877 54.168 40.835 ;
     RECT  60.672 38.773 63.528 40.931 ;
     RECT  40.2 2.151 40.512 40.981 ;
     RECT  42.432 39.349 42.456 41.027 ;
     RECT  60.72 40.931 63.528 41.027 ;
     RECT  64.608 40.885 64.632 41.027 ;
     RECT  60.96 41.027 63.528 41.843 ;
     RECT  51 2.151 51.312 42.133 ;
     RECT  52.416 41.989 52.44 42.133 ;
     RECT  40.2 40.981 40.632 42.419 ;
     RECT  47.904 40.597 47.928 42.419 ;
     RECT  45.6 2.137 45.912 42.709 ;
     RECT  38.64 41.413 38.664 42.803 ;
     RECT  45.6 42.709 46.296 42.853 ;
     RECT  61.392 41.843 63.528 43.379 ;
     RECT  51 42.133 52.44 43.427 ;
     RECT  45.6 42.853 47.16 43.861 ;
     RECT  59.184 36.997 59.64 43.955 ;
     RECT  61.536 43.379 63.528 43.955 ;
     RECT  45.6 43.861 47.88 44.099 ;
     RECT  31.008 34.501 31.032 44.387 ;
     RECT  52.416 43.427 52.44 44.483 ;
     RECT  56.4 40.405 57.768 44.483 ;
     RECT  40.2 42.419 40.512 44.485 ;
     RECT  47.856 44.099 47.88 44.627 ;
     RECT  63.504 43.955 63.528 44.627 ;
     RECT  59.184 43.955 59.208 45.059 ;
     RECT  38.4 43.285 38.424 45.539 ;
     RECT  44.448 42.997 44.472 45.635 ;
     RECT  41.712 44.965 41.736 45.731 ;
     RECT  56.4 44.483 56.808 45.731 ;
     RECT  51 43.427 51.312 45.733 ;
     RECT  45.6 44.099 46.296 46.067 ;
     RECT  50.88 45.733 51.312 46.067 ;
     RECT  48 46.021 48.024 46.069 ;
     RECT  48 46.069 48.504 46.165 ;
     RECT  55.392 45.685 55.416 46.309 ;
     RECT  56.4 45.731 56.712 46.309 ;
     RECT  47.04 46.165 48.504 47.269 ;
     RECT  47.04 47.269 49.416 47.315 ;
     RECT  47.04 47.315 48.024 47.651 ;
     RECT  55.392 46.309 56.712 48.275 ;
     RECT  2.4 37.859 15.432 48.373 ;
     RECT  49.392 47.315 49.416 48.707 ;
     RECT  48 47.651 48.024 48.899 ;
     RECT  61.8 43.955 62.112 48.997 ;
     RECT  1.152 48.997 1.176 49.139 ;
     RECT  40.08 44.485 40.512 49.235 ;
     RECT  64.608 48.997 64.632 49.235 ;
     RECT  0.144 48.133 0.168 49.379 ;
     RECT  61.392 48.997 62.112 49.477 ;
     RECT  63.504 49.237 63.528 49.477 ;
     RECT  2.304 48.373 15.432 50.963 ;
     RECT  51 46.067 51.312 51.637 ;
     RECT  55.392 48.275 55.416 51.971 ;
     RECT  61.392 49.477 63.528 52.453 ;
     RECT  50.784 51.637 51.312 53.075 ;
     RECT  56.4 48.275 56.712 53.221 ;
     RECT  53.568 52.405 53.592 53.555 ;
     RECT  25.632 34.117 25.944 53.557 ;
     RECT  47.232 51.637 47.256 53.603 ;
     RECT  49.392 49.861 49.416 53.795 ;
     RECT  40.2 49.235 40.512 54.085 ;
     RECT  56.4 53.221 57.624 54.133 ;
     RECT  51 53.075 51.312 54.181 ;
     RECT  56.4 54.133 58.248 54.467 ;
     RECT  58.224 54.467 58.248 54.517 ;
     RECT  59.424 50.101 59.448 54.517 ;
     RECT  58.224 54.517 59.448 54.707 ;
     RECT  50.688 54.181 51.312 54.851 ;
     RECT  59.28 54.707 59.448 54.947 ;
     RECT  54.384 54.085 54.408 55.715 ;
     RECT  58.224 54.707 58.248 55.811 ;
     RECT  56.4 54.467 56.712 56.869 ;
     RECT  61.056 52.453 63.528 57.059 ;
     RECT  61.056 57.059 63 57.107 ;
     RECT  48.48 54.085 48.504 57.539 ;
     RECT  61.056 57.107 62.952 57.635 ;
     RECT  61.488 57.635 62.952 57.683 ;
     RECT  61.536 57.683 62.424 57.779 ;
     RECT  59.424 54.947 59.448 58.163 ;
     RECT  61.584 57.779 62.424 58.163 ;
     RECT  51 54.851 51.312 58.501 ;
     RECT  55.872 56.869 56.712 58.643 ;
     RECT  61.632 58.163 62.424 58.691 ;
     RECT  61.8 58.691 62.424 58.739 ;
     RECT  0.144 58.933 0.168 59.123 ;
     RECT  53.616 58.069 53.64 59.315 ;
     RECT  45.6 46.067 45.912 59.605 ;
     RECT  56.4 58.643 56.712 60.277 ;
     RECT  48.48 58.693 48.504 60.419 ;
     RECT  45.6 59.605 46.728 60.851 ;
     RECT  54.96 59.605 54.984 61.619 ;
     RECT  49.056 62.533 49.08 63.299 ;
     RECT  50.832 58.501 51.312 63.299 ;
     RECT  56.4 60.277 57.096 63.299 ;
     RECT  0.144 65.749 0.168 66.035 ;
     RECT  0.144 67.621 0.168 67.811 ;
     RECT  27.6 58.645 27.624 70.499 ;
     RECT  25.632 53.557 26.184 70.645 ;
     RECT  25.632 70.645 26.76 70.835 ;
     RECT  2.4 50.963 15.432 73.091 ;
     RECT  26.736 70.835 26.76 77.555 ;
     RECT  0.144 78.997 0.168 79.235 ;
     RECT  6.672 73.091 15.432 88.403 ;
     RECT  6.672 88.403 10.248 90.083 ;
     RECT  10.176 90.083 10.248 91.859 ;
     RECT  2.4 73.091 5.64 92.963 ;
     RECT  6.672 90.083 9.048 93.301 ;
     RECT  10.176 91.859 10.2 93.301 ;
     RECT  2.4 92.963 5.16 93.539 ;
     RECT  11.424 88.403 15.432 93.539 ;
     RECT  6.672 93.301 10.2 93.587 ;
     RECT  6.72 93.587 10.2 94.115 ;
     RECT  6.816 94.115 10.2 94.739 ;
     RECT  6.816 94.739 9.048 95.941 ;
     RECT  10.176 94.739 10.2 95.941 ;
     RECT  11.568 93.539 15.432 96.371 ;
     RECT  2.4 93.539 5.112 96.803 ;
     RECT  2.4 96.803 3.96 97.283 ;
     RECT  2.4 97.283 3.816 97.331 ;
     RECT  12.24 96.371 15.432 97.717 ;
     RECT  5.088 96.803 5.112 97.811 ;
     RECT  6.816 95.941 10.2 98.675 ;
     RECT  7.44 98.675 10.2 98.723 ;
     RECT  18.48 4.117 20.904 98.917 ;
     RECT  7.44 98.723 8.856 99.251 ;
     RECT  18.432 98.917 20.904 99.539 ;
     RECT  25.632 70.835 25.656 99.637 ;
     RECT  21.888 3.541 22.44 99.685 ;
     RECT  23.616 2.915 24.6 99.685 ;
     RECT  10.176 98.723 10.2 99.733 ;
     RECT  18.48 99.539 20.904 100.261 ;
     RECT  21.888 99.685 24.6 100.261 ;
     RECT  25.632 99.637 25.992 100.261 ;
     RECT  29.4 2.291 29.712 100.261 ;
     RECT  18.48 100.261 25.992 100.309 ;
     RECT  17.328 2.291 17.352 100.453 ;
     RECT  2.4 97.331 3.096 100.547 ;
     RECT  17.328 100.453 17.448 100.693 ;
     RECT  18.48 100.309 26.808 100.693 ;
     RECT  28.464 100.261 29.712 100.789 ;
     RECT  7.44 99.251 8.472 100.931 ;
     RECT  28.464 100.789 30.216 101.029 ;
     RECT  27.792 101.029 30.216 101.315 ;
     RECT  12.24 97.717 15.672 101.461 ;
     RECT  7.44 100.931 8.28 101.507 ;
     RECT  12.24 101.461 16.248 101.699 ;
     RECT  10.176 99.733 10.92 102.083 ;
     RECT  27.792 101.315 29.712 102.227 ;
     RECT  15.072 101.699 16.248 102.469 ;
     RECT  17.328 100.693 26.808 102.469 ;
     RECT  10.848 102.083 10.92 102.517 ;
     RECT  12.24 101.699 14.04 102.517 ;
     RECT  7.8 101.507 8.28 102.803 ;
     RECT  15.072 102.469 26.808 103.189 ;
     RECT  10.848 102.517 14.04 103.235 ;
     RECT  15.072 103.189 26.952 103.763 ;
     RECT  15.408 103.763 26.952 103.811 ;
     RECT  30.768 101.941 30.792 103.811 ;
     RECT  10.848 103.235 13.512 104.149 ;
     RECT  9.984 104.149 13.512 104.245 ;
     RECT  28.464 102.227 29.712 104.245 ;
     RECT  9.84 104.245 13.512 104.821 ;
     RECT  15.888 103.811 26.952 104.821 ;
     RECT  28.224 104.245 29.712 104.821 ;
     RECT  9.84 104.821 13.608 104.915 ;
     RECT  7.8 102.803 8.112 105.253 ;
     RECT  9.84 104.915 11.688 105.253 ;
     RECT  14.928 104.821 29.712 105.397 ;
     RECT  7.8 105.253 8.664 105.445 ;
     RECT  9.744 105.253 11.688 105.445 ;
     RECT  14.688 105.397 29.712 105.445 ;
     RECT  2.4 100.547 2.712 105.849 ;
     RECT  34.8 2.151 35.112 105.849 ;
     RECT  45.6 60.851 45.912 105.849 ;
     RECT  51 63.299 51.312 105.849 ;
     RECT  56.4 63.299 56.712 105.849 ;
     RECT  61.8 58.739 62.112 105.849 ;
     RECT  2.4 105.849 2.52 105.863 ;
     RECT  7.8 105.445 11.688 105.863 ;
     RECT  34.8 105.849 34.92 105.863 ;
     RECT  40.2 54.085 40.68 105.863 ;
     RECT  45.6 105.849 45.72 105.863 ;
     RECT  51 105.849 51.12 105.863 ;
     RECT  56.4 105.849 56.52 105.863 ;
     RECT  61.8 105.849 61.92 105.863 ;
     RECT  8.064 105.863 11.688 105.973 ;
     RECT  13.008 104.915 13.608 105.973 ;
     RECT  8.064 105.973 13.656 106.501 ;
     RECT  14.688 105.445 29.976 106.501 ;
     RECT  40.656 105.863 40.68 107.845 ;
     RECT  40.512 107.845 40.68 107.891 ;
     RECT  8.064 106.501 29.976 107.984 ;
     RECT  33.816 1.763 33.96 2.137 ;
     RECT  26.472 1.811 27.504 2.291 ;
     RECT  33.816 2.137 34.8 2.291 ;
     RECT  5.544 2.243 6.528 2.291 ;
     RECT  17.352 2.291 18.6 4.117 ;
     RECT  19.656 2.291 20.688 3.349 ;
     RECT  20.904 2.291 21.888 100.261 ;
     RECT  22.056 2.291 23.616 3.541 ;
     RECT  24.6 2.915 25.176 3.925 ;
     RECT  22.44 3.541 23.616 99.685 ;
     RECT  38.76 3.541 40.2 40.499 ;
     RECT  24.6 3.925 25.632 100.261 ;
     RECT  17.352 4.117 18.48 98.917 ;
     RECT  3.432 4.501 4.464 25.045 ;
     RECT  10.632 5.173 12 6.181 ;
     RECT  12.024 5.173 13.2 13.333 ;
     RECT  4.488 5.653 5.616 6.229 ;
     RECT  12.072 13.333 13.2 17.893 ;
     RECT  9.336 14.533 10.464 21.061 ;
     RECT  12.12 17.893 13.2 25.141 ;
     RECT  29.712 34.501 31.008 44.387 ;
     RECT  56.712 36.085 57.744 40.405 ;
     RECT  57.768 36.997 59.184 44.483 ;
     RECT  59.64 37.573 60.96 38.773 ;
     RECT  59.64 38.773 60.672 40.931 ;
     RECT  63.528 40.885 64.608 41.027 ;
     RECT  59.64 40.931 60.72 41.027 ;
     RECT  59.64 41.027 60.96 41.843 ;
     RECT  51.312 41.989 52.416 42.133 ;
     RECT  44.472 42.997 45.6 45.635 ;
     RECT  51.312 43.427 52.416 44.483 ;
     RECT  62.112 43.955 63.504 44.627 ;
     RECT  40.512 44.965 41.712 45.731 ;
     RECT  55.416 45.685 56.4 46.309 ;
     RECT  45.912 46.067 46.296 46.165 ;
     RECT  45.912 46.165 47.04 47.651 ;
     RECT  48.024 47.315 49.392 48.707 ;
     RECT  55.416 48.275 56.4 51.971 ;
     RECT  48.024 48.707 49.416 48.899 ;
     RECT  49.392 48.899 49.416 49.861 ;
     RECT  0.168 48.997 1.152 49.139 ;
     RECT  1.176 48.997 2.304 49.139 ;
     RECT  62.112 49.237 63.504 49.477 ;
     RECT  45.912 51.637 47.232 53.603 ;
     RECT  49.416 51.637 50.784 53.075 ;
     RECT  49.416 53.075 51 53.795 ;
     RECT  50.688 53.795 51 54.181 ;
     RECT  58.248 54.133 59.424 54.517 ;
     RECT  56.712 54.467 58.224 55.811 ;
     RECT  58.248 54.707 59.28 54.947 ;
     RECT  58.248 54.947 59.424 55.811 ;
     RECT  48.48 57.539 48.504 58.693 ;
     RECT  55.872 58.643 56.4 59.605 ;
     RECT  26.184 58.645 27.6 70.499 ;
     RECT  54.984 59.605 56.4 61.619 ;
     RECT  26.184 70.499 26.76 70.645 ;
     RECT  25.656 70.835 26.736 77.555 ;
     RECT  5.64 73.091 6.672 92.963 ;
     RECT  10.248 88.403 11.424 91.859 ;
     RECT  9.048 90.083 10.176 93.301 ;
     RECT  10.2 91.859 11.424 93.539 ;
     RECT  5.16 92.963 6.672 93.539 ;
     RECT  10.2 93.539 11.568 96.371 ;
     RECT  9.048 94.739 10.176 95.941 ;
     RECT  3.96 96.803 5.088 97.283 ;
     RECT  3.816 97.283 5.088 97.331 ;
     RECT  8.856 98.723 10.176 99.251 ;
     RECT  17.352 98.917 18.432 99.539 ;
     RECT  17.352 99.539 18.48 100.453 ;
     RECT  10.92 99.733 12.24 102.517 ;
     RECT  17.448 100.453 18.48 100.693 ;
     RECT  26.808 101.029 27.792 102.227 ;
     RECT  29.712 101.315 30.216 101.941 ;
     RECT  16.248 101.461 17.328 102.469 ;
     RECT  14.04 101.699 15.072 103.235 ;
     RECT  29.712 101.941 30.768 103.811 ;
     RECT  26.808 102.227 28.464 103.189 ;
     RECT  26.952 103.189 28.464 104.245 ;
     RECT  15.072 103.763 15.408 103.811 ;
     RECT  15.072 103.811 15.888 104.821 ;
     RECT  26.952 104.245 28.224 104.821 ;
     RECT  13.608 104.821 14.928 105.397 ;
     RECT  11.688 104.915 13.008 105.973 ;
     RECT  8.664 105.253 9.744 105.445 ;
     RECT  13.608 105.397 14.688 105.973 ;
     RECT  13.656 105.973 14.688 106.501 ;
  END
END qkd_host_ctl
END LIBRARY
